VERSION 5.8 ;
BUSBITCHARS "[]" ;
DIVIDERCHAR "/" ;
UNITS
    DATABASE MICRONS 1000 ;
END UNITS

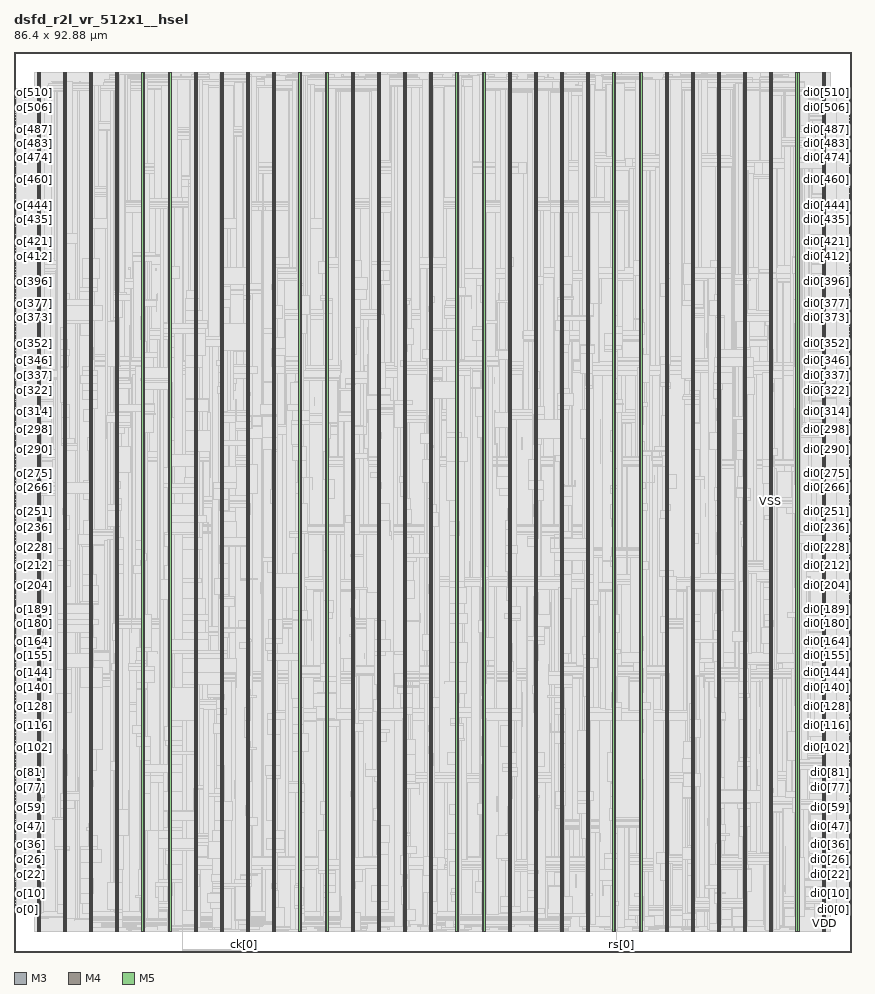
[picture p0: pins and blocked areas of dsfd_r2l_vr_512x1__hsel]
MACRO dsfd_r2l_vr_512x1__hsel
  FOREIGN dsfd_r2l_vr_512x1__hsel 0 0 ;
  CLASS BLOCK ;
  SIZE 86.4 BY 92.88 ;
  PIN ck[0]
    DIRECTION INPUT ;
    USE SIGNAL ;
    PORT
      LAYER M3 ;
        RECT  23.76 0 23.778 0.144 ;
    END
    PORT
      LAYER M3 ;
        RECT  23.76 0.108 23.778 0.221 ;
    END
  END ck[0]
  PIN di0[0]
    DIRECTION INPUT ;
    USE SIGNAL ;
    PORT
      LAYER M4 ;
        RECT  86.208 4.416 86.4 4.44 ;
    END
  END di0[0]
  PIN di0[100]
    DIRECTION INPUT ;
    USE SIGNAL ;
    PORT
      LAYER M4 ;
        RECT  86.208 20.784 86.4 20.808 ;
    END
  END di0[100]
  PIN di0[101]
    DIRECTION INPUT ;
    USE SIGNAL ;
    PORT
      LAYER M4 ;
        RECT  86.208 20.928 86.4 20.952 ;
    END
  END di0[101]
  PIN di0[102]
    DIRECTION INPUT ;
    USE SIGNAL ;
    PORT
      LAYER M4 ;
        RECT  86.208 21.12 86.4 21.144 ;
    END
  END di0[102]
  PIN di0[103]
    DIRECTION INPUT ;
    USE SIGNAL ;
    PORT
      LAYER M4 ;
        RECT  86.208 21.264 86.4 21.288 ;
    END
  END di0[103]
  PIN di0[104]
    DIRECTION INPUT ;
    USE SIGNAL ;
    PORT
      LAYER M4 ;
        RECT  86.208 21.408 86.4 21.432 ;
    END
  END di0[104]
  PIN di0[105]
    DIRECTION INPUT ;
    USE SIGNAL ;
    PORT
      LAYER M4 ;
        RECT  86.208 21.6 86.4 21.624 ;
    END
  END di0[105]
  PIN di0[106]
    DIRECTION INPUT ;
    USE SIGNAL ;
    PORT
      LAYER M4 ;
        RECT  86.208 21.744 86.4 21.768 ;
    END
  END di0[106]
  PIN di0[107]
    DIRECTION INPUT ;
    USE SIGNAL ;
    PORT
      LAYER M4 ;
        RECT  86.208 21.936 86.4 21.96 ;
    END
  END di0[107]
  PIN di0[108]
    DIRECTION INPUT ;
    USE SIGNAL ;
    PORT
      LAYER M4 ;
        RECT  86.208 22.08 86.4 22.104 ;
    END
  END di0[108]
  PIN di0[109]
    DIRECTION INPUT ;
    USE SIGNAL ;
    PORT
      LAYER M4 ;
        RECT  86.208 22.224 86.4 22.248 ;
    END
  END di0[109]
  PIN di0[10]
    DIRECTION INPUT ;
    USE SIGNAL ;
    PORT
      LAYER M4 ;
        RECT  86.208 6.048 86.4 6.072 ;
    END
  END di0[10]
  PIN di0[110]
    DIRECTION INPUT ;
    USE SIGNAL ;
    PORT
      LAYER M4 ;
        RECT  86.208 22.416 86.4 22.44 ;
    END
  END di0[110]
  PIN di0[111]
    DIRECTION INPUT ;
    USE SIGNAL ;
    PORT
      LAYER M4 ;
        RECT  86.208 22.56 86.4 22.584 ;
    END
  END di0[111]
  PIN di0[112]
    DIRECTION INPUT ;
    USE SIGNAL ;
    PORT
      LAYER M4 ;
        RECT  86.208 22.752 86.4 22.776 ;
    END
  END di0[112]
  PIN di0[113]
    DIRECTION INPUT ;
    USE SIGNAL ;
    PORT
      LAYER M4 ;
        RECT  86.208 22.896 86.4 22.92 ;
    END
  END di0[113]
  PIN di0[114]
    DIRECTION INPUT ;
    USE SIGNAL ;
    PORT
      LAYER M4 ;
        RECT  86.208 23.04 86.4 23.064 ;
    END
  END di0[114]
  PIN di0[115]
    DIRECTION INPUT ;
    USE SIGNAL ;
    PORT
      LAYER M4 ;
        RECT  86.208 23.232 86.4 23.256 ;
    END
  END di0[115]
  PIN di0[116]
    DIRECTION INPUT ;
    USE SIGNAL ;
    PORT
      LAYER M4 ;
        RECT  86.208 23.376 86.4 23.4 ;
    END
  END di0[116]
  PIN di0[117]
    DIRECTION INPUT ;
    USE SIGNAL ;
    PORT
      LAYER M4 ;
        RECT  86.208 23.568 86.4 23.592 ;
    END
  END di0[117]
  PIN di0[118]
    DIRECTION INPUT ;
    USE SIGNAL ;
    PORT
      LAYER M4 ;
        RECT  86.208 23.712 86.4 23.736 ;
    END
  END di0[118]
  PIN di0[119]
    DIRECTION INPUT ;
    USE SIGNAL ;
    PORT
      LAYER M4 ;
        RECT  86.208 23.856 86.4 23.88 ;
    END
  END di0[119]
  PIN di0[11]
    DIRECTION INPUT ;
    USE SIGNAL ;
    PORT
      LAYER M4 ;
        RECT  86.208 6.192 86.4 6.216 ;
    END
  END di0[11]
  PIN di0[120]
    DIRECTION INPUT ;
    USE SIGNAL ;
    PORT
      LAYER M4 ;
        RECT  86.208 24.048 86.4 24.072 ;
    END
  END di0[120]
  PIN di0[121]
    DIRECTION INPUT ;
    USE SIGNAL ;
    PORT
      LAYER M4 ;
        RECT  86.208 24.192 86.4 24.216 ;
    END
  END di0[121]
  PIN di0[122]
    DIRECTION INPUT ;
    USE SIGNAL ;
    PORT
      LAYER M4 ;
        RECT  86.208 24.384 86.4 24.408 ;
    END
  END di0[122]
  PIN di0[123]
    DIRECTION INPUT ;
    USE SIGNAL ;
    PORT
      LAYER M4 ;
        RECT  86.208 24.528 86.4 24.552 ;
    END
  END di0[123]
  PIN di0[124]
    DIRECTION INPUT ;
    USE SIGNAL ;
    PORT
      LAYER M4 ;
        RECT  86.208 24.72 86.4 24.744 ;
    END
  END di0[124]
  PIN di0[125]
    DIRECTION INPUT ;
    USE SIGNAL ;
    PORT
      LAYER M4 ;
        RECT  86.208 24.864 86.4 24.888 ;
    END
  END di0[125]
  PIN di0[126]
    DIRECTION INPUT ;
    USE SIGNAL ;
    PORT
      LAYER M4 ;
        RECT  86.208 25.008 86.4 25.032 ;
    END
  END di0[126]
  PIN di0[127]
    DIRECTION INPUT ;
    USE SIGNAL ;
    PORT
      LAYER M4 ;
        RECT  86.208 25.2 86.4 25.224 ;
    END
  END di0[127]
  PIN di0[128]
    DIRECTION INPUT ;
    USE SIGNAL ;
    PORT
      LAYER M4 ;
        RECT  86.208 25.344 86.4 25.368 ;
    END
  END di0[128]
  PIN di0[129]
    DIRECTION INPUT ;
    USE SIGNAL ;
    PORT
      LAYER M4 ;
        RECT  86.208 25.536 86.4 25.56 ;
    END
  END di0[129]
  PIN di0[12]
    DIRECTION INPUT ;
    USE SIGNAL ;
    PORT
      LAYER M4 ;
        RECT  86.208 6.384 86.4 6.408 ;
    END
  END di0[12]
  PIN di0[130]
    DIRECTION INPUT ;
    USE SIGNAL ;
    PORT
      LAYER M4 ;
        RECT  86.208 25.68 86.4 25.704 ;
    END
  END di0[130]
  PIN di0[131]
    DIRECTION INPUT ;
    USE SIGNAL ;
    PORT
      LAYER M4 ;
        RECT  86.208 25.824 86.4 25.848 ;
    END
  END di0[131]
  PIN di0[132]
    DIRECTION INPUT ;
    USE SIGNAL ;
    PORT
      LAYER M4 ;
        RECT  86.208 26.016 86.4 26.04 ;
    END
  END di0[132]
  PIN di0[133]
    DIRECTION INPUT ;
    USE SIGNAL ;
    PORT
      LAYER M4 ;
        RECT  86.208 26.16 86.4 26.184 ;
    END
  END di0[133]
  PIN di0[134]
    DIRECTION INPUT ;
    USE SIGNAL ;
    PORT
      LAYER M4 ;
        RECT  86.208 26.352 86.4 26.376 ;
    END
  END di0[134]
  PIN di0[135]
    DIRECTION INPUT ;
    USE SIGNAL ;
    PORT
      LAYER M4 ;
        RECT  86.208 26.496 86.4 26.52 ;
    END
  END di0[135]
  PIN di0[136]
    DIRECTION INPUT ;
    USE SIGNAL ;
    PORT
      LAYER M4 ;
        RECT  86.208 26.64 86.4 26.664 ;
    END
  END di0[136]
  PIN di0[137]
    DIRECTION INPUT ;
    USE SIGNAL ;
    PORT
      LAYER M4 ;
        RECT  86.208 26.832 86.4 26.856 ;
    END
  END di0[137]
  PIN di0[138]
    DIRECTION INPUT ;
    USE SIGNAL ;
    PORT
      LAYER M4 ;
        RECT  86.208 26.976 86.4 27 ;
    END
  END di0[138]
  PIN di0[139]
    DIRECTION INPUT ;
    USE SIGNAL ;
    PORT
      LAYER M4 ;
        RECT  86.208 27.168 86.4 27.192 ;
    END
  END di0[139]
  PIN di0[13]
    DIRECTION INPUT ;
    USE SIGNAL ;
    PORT
      LAYER M4 ;
        RECT  86.208 6.528 86.4 6.552 ;
    END
  END di0[13]
  PIN di0[140]
    DIRECTION INPUT ;
    USE SIGNAL ;
    PORT
      LAYER M4 ;
        RECT  86.208 27.312 86.4 27.336 ;
    END
  END di0[140]
  PIN di0[141]
    DIRECTION INPUT ;
    USE SIGNAL ;
    PORT
      LAYER M4 ;
        RECT  86.208 27.456 86.4 27.48 ;
    END
  END di0[141]
  PIN di0[142]
    DIRECTION INPUT ;
    USE SIGNAL ;
    PORT
      LAYER M4 ;
        RECT  86.208 27.648 86.4 27.672 ;
    END
  END di0[142]
  PIN di0[143]
    DIRECTION INPUT ;
    USE SIGNAL ;
    PORT
      LAYER M4 ;
        RECT  86.208 27.792 86.4 27.816 ;
    END
  END di0[143]
  PIN di0[144]
    DIRECTION INPUT ;
    USE SIGNAL ;
    PORT
      LAYER M4 ;
        RECT  86.208 27.984 86.4 28.008 ;
    END
  END di0[144]
  PIN di0[145]
    DIRECTION INPUT ;
    USE SIGNAL ;
    PORT
      LAYER M4 ;
        RECT  86.208 28.128 86.4 28.152 ;
    END
  END di0[145]
  PIN di0[146]
    DIRECTION INPUT ;
    USE SIGNAL ;
    PORT
      LAYER M4 ;
        RECT  86.208 28.272 86.4 28.296 ;
    END
  END di0[146]
  PIN di0[147]
    DIRECTION INPUT ;
    USE SIGNAL ;
    PORT
      LAYER M4 ;
        RECT  86.208 28.464 86.4 28.488 ;
    END
  END di0[147]
  PIN di0[148]
    DIRECTION INPUT ;
    USE SIGNAL ;
    PORT
      LAYER M4 ;
        RECT  86.208 28.608 86.4 28.632 ;
    END
  END di0[148]
  PIN di0[149]
    DIRECTION INPUT ;
    USE SIGNAL ;
    PORT
      LAYER M4 ;
        RECT  86.208 28.8 86.4 28.824 ;
    END
  END di0[149]
  PIN di0[14]
    DIRECTION INPUT ;
    USE SIGNAL ;
    PORT
      LAYER M4 ;
        RECT  86.208 6.72 86.4 6.744 ;
    END
  END di0[14]
  PIN di0[150]
    DIRECTION INPUT ;
    USE SIGNAL ;
    PORT
      LAYER M4 ;
        RECT  86.208 28.944 86.4 28.968 ;
    END
  END di0[150]
  PIN di0[151]
    DIRECTION INPUT ;
    USE SIGNAL ;
    PORT
      LAYER M4 ;
        RECT  86.208 29.136 86.4 29.16 ;
    END
  END di0[151]
  PIN di0[152]
    DIRECTION INPUT ;
    USE SIGNAL ;
    PORT
      LAYER M4 ;
        RECT  86.208 29.28 86.4 29.304 ;
    END
  END di0[152]
  PIN di0[153]
    DIRECTION INPUT ;
    USE SIGNAL ;
    PORT
      LAYER M4 ;
        RECT  86.208 29.424 86.4 29.448 ;
    END
  END di0[153]
  PIN di0[154]
    DIRECTION INPUT ;
    USE SIGNAL ;
    PORT
      LAYER M4 ;
        RECT  86.208 29.616 86.4 29.64 ;
    END
  END di0[154]
  PIN di0[155]
    DIRECTION INPUT ;
    USE SIGNAL ;
    PORT
      LAYER M4 ;
        RECT  86.208 29.76 86.4 29.784 ;
    END
  END di0[155]
  PIN di0[156]
    DIRECTION INPUT ;
    USE SIGNAL ;
    PORT
      LAYER M4 ;
        RECT  86.208 29.952 86.4 29.976 ;
    END
  END di0[156]
  PIN di0[157]
    DIRECTION INPUT ;
    USE SIGNAL ;
    PORT
      LAYER M4 ;
        RECT  86.208 30.096 86.4 30.12 ;
    END
  END di0[157]
  PIN di0[158]
    DIRECTION INPUT ;
    USE SIGNAL ;
    PORT
      LAYER M4 ;
        RECT  86.208 30.24 86.4 30.264 ;
    END
  END di0[158]
  PIN di0[159]
    DIRECTION INPUT ;
    USE SIGNAL ;
    PORT
      LAYER M4 ;
        RECT  86.208 30.432 86.4 30.456 ;
    END
  END di0[159]
  PIN di0[15]
    DIRECTION INPUT ;
    USE SIGNAL ;
    PORT
      LAYER M4 ;
        RECT  86.208 6.864 86.4 6.888 ;
    END
  END di0[15]
  PIN di0[160]
    DIRECTION INPUT ;
    USE SIGNAL ;
    PORT
      LAYER M4 ;
        RECT  86.208 30.576 86.4 30.6 ;
    END
  END di0[160]
  PIN di0[161]
    DIRECTION INPUT ;
    USE SIGNAL ;
    PORT
      LAYER M4 ;
        RECT  86.208 30.768 86.4 30.792 ;
    END
  END di0[161]
  PIN di0[162]
    DIRECTION INPUT ;
    USE SIGNAL ;
    PORT
      LAYER M4 ;
        RECT  86.208 30.912 86.4 30.936 ;
    END
  END di0[162]
  PIN di0[163]
    DIRECTION INPUT ;
    USE SIGNAL ;
    PORT
      LAYER M4 ;
        RECT  86.208 31.056 86.4 31.08 ;
    END
  END di0[163]
  PIN di0[164]
    DIRECTION INPUT ;
    USE SIGNAL ;
    PORT
      LAYER M4 ;
        RECT  86.208 31.248 86.4 31.272 ;
    END
  END di0[164]
  PIN di0[165]
    DIRECTION INPUT ;
    USE SIGNAL ;
    PORT
      LAYER M4 ;
        RECT  86.208 31.392 86.4 31.416 ;
    END
  END di0[165]
  PIN di0[166]
    DIRECTION INPUT ;
    USE SIGNAL ;
    PORT
      LAYER M4 ;
        RECT  86.208 31.584 86.4 31.608 ;
    END
  END di0[166]
  PIN di0[167]
    DIRECTION INPUT ;
    USE SIGNAL ;
    PORT
      LAYER M4 ;
        RECT  86.208 31.728 86.4 31.752 ;
    END
  END di0[167]
  PIN di0[168]
    DIRECTION INPUT ;
    USE SIGNAL ;
    PORT
      LAYER M4 ;
        RECT  86.208 31.872 86.4 31.896 ;
    END
  END di0[168]
  PIN di0[169]
    DIRECTION INPUT ;
    USE SIGNAL ;
    PORT
      LAYER M4 ;
        RECT  86.208 32.064 86.4 32.088 ;
    END
  END di0[169]
  PIN di0[16]
    DIRECTION INPUT ;
    USE SIGNAL ;
    PORT
      LAYER M4 ;
        RECT  86.208 7.008 86.4 7.032 ;
    END
  END di0[16]
  PIN di0[170]
    DIRECTION INPUT ;
    USE SIGNAL ;
    PORT
      LAYER M4 ;
        RECT  86.208 32.208 86.4 32.232 ;
    END
  END di0[170]
  PIN di0[171]
    DIRECTION INPUT ;
    USE SIGNAL ;
    PORT
      LAYER M4 ;
        RECT  86.208 32.4 86.4 32.424 ;
    END
  END di0[171]
  PIN di0[172]
    DIRECTION INPUT ;
    USE SIGNAL ;
    PORT
      LAYER M4 ;
        RECT  86.208 32.544 86.4 32.568 ;
    END
  END di0[172]
  PIN di0[173]
    DIRECTION INPUT ;
    USE SIGNAL ;
    PORT
      LAYER M4 ;
        RECT  86.208 32.688 86.4 32.712 ;
    END
  END di0[173]
  PIN di0[174]
    DIRECTION INPUT ;
    USE SIGNAL ;
    PORT
      LAYER M4 ;
        RECT  86.208 32.88 86.4 32.904 ;
    END
  END di0[174]
  PIN di0[175]
    DIRECTION INPUT ;
    USE SIGNAL ;
    PORT
      LAYER M4 ;
        RECT  86.208 33.024 86.4 33.048 ;
    END
  END di0[175]
  PIN di0[176]
    DIRECTION INPUT ;
    USE SIGNAL ;
    PORT
      LAYER M4 ;
        RECT  86.208 33.216 86.4 33.24 ;
    END
  END di0[176]
  PIN di0[177]
    DIRECTION INPUT ;
    USE SIGNAL ;
    PORT
      LAYER M4 ;
        RECT  86.208 33.36 86.4 33.384 ;
    END
  END di0[177]
  PIN di0[178]
    DIRECTION INPUT ;
    USE SIGNAL ;
    PORT
      LAYER M4 ;
        RECT  86.208 33.552 86.4 33.576 ;
    END
  END di0[178]
  PIN di0[179]
    DIRECTION INPUT ;
    USE SIGNAL ;
    PORT
      LAYER M4 ;
        RECT  86.208 33.696 86.4 33.72 ;
    END
  END di0[179]
  PIN di0[17]
    DIRECTION INPUT ;
    USE SIGNAL ;
    PORT
      LAYER M4 ;
        RECT  86.208 7.2 86.4 7.224 ;
    END
  END di0[17]
  PIN di0[180]
    DIRECTION INPUT ;
    USE SIGNAL ;
    PORT
      LAYER M4 ;
        RECT  86.208 33.84 86.4 33.864 ;
    END
  END di0[180]
  PIN di0[181]
    DIRECTION INPUT ;
    USE SIGNAL ;
    PORT
      LAYER M4 ;
        RECT  86.208 34.032 86.4 34.056 ;
    END
  END di0[181]
  PIN di0[182]
    DIRECTION INPUT ;
    USE SIGNAL ;
    PORT
      LAYER M4 ;
        RECT  86.208 34.176 86.4 34.2 ;
    END
  END di0[182]
  PIN di0[183]
    DIRECTION INPUT ;
    USE SIGNAL ;
    PORT
      LAYER M4 ;
        RECT  86.208 34.368 86.4 34.392 ;
    END
  END di0[183]
  PIN di0[184]
    DIRECTION INPUT ;
    USE SIGNAL ;
    PORT
      LAYER M4 ;
        RECT  86.208 34.512 86.4 34.536 ;
    END
  END di0[184]
  PIN di0[185]
    DIRECTION INPUT ;
    USE SIGNAL ;
    PORT
      LAYER M4 ;
        RECT  86.208 34.656 86.4 34.68 ;
    END
  END di0[185]
  PIN di0[186]
    DIRECTION INPUT ;
    USE SIGNAL ;
    PORT
      LAYER M4 ;
        RECT  86.208 34.848 86.4 34.872 ;
    END
  END di0[186]
  PIN di0[187]
    DIRECTION INPUT ;
    USE SIGNAL ;
    PORT
      LAYER M4 ;
        RECT  86.208 34.992 86.4 35.016 ;
    END
  END di0[187]
  PIN di0[188]
    DIRECTION INPUT ;
    USE SIGNAL ;
    PORT
      LAYER M4 ;
        RECT  86.208 35.184 86.4 35.208 ;
    END
  END di0[188]
  PIN di0[189]
    DIRECTION INPUT ;
    USE SIGNAL ;
    PORT
      LAYER M4 ;
        RECT  86.208 35.328 86.4 35.352 ;
    END
  END di0[189]
  PIN di0[18]
    DIRECTION INPUT ;
    USE SIGNAL ;
    PORT
      LAYER M4 ;
        RECT  86.208 7.344 86.4 7.368 ;
    END
  END di0[18]
  PIN di0[190]
    DIRECTION INPUT ;
    USE SIGNAL ;
    PORT
      LAYER M4 ;
        RECT  86.208 35.472 86.4 35.496 ;
    END
  END di0[190]
  PIN di0[191]
    DIRECTION INPUT ;
    USE SIGNAL ;
    PORT
      LAYER M4 ;
        RECT  86.208 35.664 86.4 35.688 ;
    END
  END di0[191]
  PIN di0[192]
    DIRECTION INPUT ;
    USE SIGNAL ;
    PORT
      LAYER M4 ;
        RECT  86.208 35.808 86.4 35.832 ;
    END
  END di0[192]
  PIN di0[193]
    DIRECTION INPUT ;
    USE SIGNAL ;
    PORT
      LAYER M4 ;
        RECT  86.208 36 86.4 36.024 ;
    END
  END di0[193]
  PIN di0[194]
    DIRECTION INPUT ;
    USE SIGNAL ;
    PORT
      LAYER M4 ;
        RECT  86.208 36.144 86.4 36.168 ;
    END
  END di0[194]
  PIN di0[195]
    DIRECTION INPUT ;
    USE SIGNAL ;
    PORT
      LAYER M4 ;
        RECT  86.208 36.288 86.4 36.312 ;
    END
  END di0[195]
  PIN di0[196]
    DIRECTION INPUT ;
    USE SIGNAL ;
    PORT
      LAYER M4 ;
        RECT  86.208 36.48 86.4 36.504 ;
    END
  END di0[196]
  PIN di0[197]
    DIRECTION INPUT ;
    USE SIGNAL ;
    PORT
      LAYER M4 ;
        RECT  86.208 36.624 86.4 36.648 ;
    END
  END di0[197]
  PIN di0[198]
    DIRECTION INPUT ;
    USE SIGNAL ;
    PORT
      LAYER M4 ;
        RECT  86.208 36.816 86.4 36.84 ;
    END
  END di0[198]
  PIN di0[199]
    DIRECTION INPUT ;
    USE SIGNAL ;
    PORT
      LAYER M4 ;
        RECT  86.208 36.96 86.4 36.984 ;
    END
  END di0[199]
  PIN di0[19]
    DIRECTION INPUT ;
    USE SIGNAL ;
    PORT
      LAYER M4 ;
        RECT  86.208 7.536 86.4 7.56 ;
    END
  END di0[19]
  PIN di0[1]
    DIRECTION INPUT ;
    USE SIGNAL ;
    PORT
      LAYER M4 ;
        RECT  86.208 4.56 86.4 4.584 ;
    END
  END di0[1]
  PIN di0[200]
    DIRECTION INPUT ;
    USE SIGNAL ;
    PORT
      LAYER M4 ;
        RECT  86.208 37.152 86.4 37.176 ;
    END
  END di0[200]
  PIN di0[201]
    DIRECTION INPUT ;
    USE SIGNAL ;
    PORT
      LAYER M4 ;
        RECT  86.208 37.296 86.4 37.32 ;
    END
  END di0[201]
  PIN di0[202]
    DIRECTION INPUT ;
    USE SIGNAL ;
    PORT
      LAYER M4 ;
        RECT  86.208 37.44 86.4 37.464 ;
    END
  END di0[202]
  PIN di0[203]
    DIRECTION INPUT ;
    USE SIGNAL ;
    PORT
      LAYER M4 ;
        RECT  86.208 37.632 86.4 37.656 ;
    END
  END di0[203]
  PIN di0[204]
    DIRECTION INPUT ;
    USE SIGNAL ;
    PORT
      LAYER M4 ;
        RECT  86.208 37.776 86.4 37.8 ;
    END
  END di0[204]
  PIN di0[205]
    DIRECTION INPUT ;
    USE SIGNAL ;
    PORT
      LAYER M4 ;
        RECT  86.208 37.968 86.4 37.992 ;
    END
  END di0[205]
  PIN di0[206]
    DIRECTION INPUT ;
    USE SIGNAL ;
    PORT
      LAYER M4 ;
        RECT  86.208 38.112 86.4 38.136 ;
    END
  END di0[206]
  PIN di0[207]
    DIRECTION INPUT ;
    USE SIGNAL ;
    PORT
      LAYER M4 ;
        RECT  86.208 38.256 86.4 38.28 ;
    END
  END di0[207]
  PIN di0[208]
    DIRECTION INPUT ;
    USE SIGNAL ;
    PORT
      LAYER M4 ;
        RECT  86.208 38.448 86.4 38.472 ;
    END
  END di0[208]
  PIN di0[209]
    DIRECTION INPUT ;
    USE SIGNAL ;
    PORT
      LAYER M4 ;
        RECT  86.208 38.592 86.4 38.616 ;
    END
  END di0[209]
  PIN di0[20]
    DIRECTION INPUT ;
    USE SIGNAL ;
    PORT
      LAYER M4 ;
        RECT  86.208 7.68 86.4 7.704 ;
    END
  END di0[20]
  PIN di0[210]
    DIRECTION INPUT ;
    USE SIGNAL ;
    PORT
      LAYER M4 ;
        RECT  86.208 38.784 86.4 38.808 ;
    END
  END di0[210]
  PIN di0[211]
    DIRECTION INPUT ;
    USE SIGNAL ;
    PORT
      LAYER M4 ;
        RECT  86.208 38.928 86.4 38.952 ;
    END
  END di0[211]
  PIN di0[212]
    DIRECTION INPUT ;
    USE SIGNAL ;
    PORT
      LAYER M4 ;
        RECT  86.208 39.072 86.4 39.096 ;
    END
  END di0[212]
  PIN di0[213]
    DIRECTION INPUT ;
    USE SIGNAL ;
    PORT
      LAYER M4 ;
        RECT  86.208 39.264 86.4 39.288 ;
    END
  END di0[213]
  PIN di0[214]
    DIRECTION INPUT ;
    USE SIGNAL ;
    PORT
      LAYER M4 ;
        RECT  86.208 39.408 86.4 39.432 ;
    END
  END di0[214]
  PIN di0[215]
    DIRECTION INPUT ;
    USE SIGNAL ;
    PORT
      LAYER M4 ;
        RECT  86.208 39.6 86.4 39.624 ;
    END
  END di0[215]
  PIN di0[216]
    DIRECTION INPUT ;
    USE SIGNAL ;
    PORT
      LAYER M4 ;
        RECT  86.208 39.744 86.4 39.768 ;
    END
  END di0[216]
  PIN di0[217]
    DIRECTION INPUT ;
    USE SIGNAL ;
    PORT
      LAYER M4 ;
        RECT  86.208 39.888 86.4 39.912 ;
    END
  END di0[217]
  PIN di0[218]
    DIRECTION INPUT ;
    USE SIGNAL ;
    PORT
      LAYER M4 ;
        RECT  86.208 40.08 86.4 40.104 ;
    END
  END di0[218]
  PIN di0[219]
    DIRECTION INPUT ;
    USE SIGNAL ;
    PORT
      LAYER M4 ;
        RECT  86.208 40.224 86.4 40.248 ;
    END
  END di0[219]
  PIN di0[21]
    DIRECTION INPUT ;
    USE SIGNAL ;
    PORT
      LAYER M4 ;
        RECT  86.208 7.872 86.4 7.896 ;
    END
  END di0[21]
  PIN di0[220]
    DIRECTION INPUT ;
    USE SIGNAL ;
    PORT
      LAYER M4 ;
        RECT  86.208 40.416 86.4 40.44 ;
    END
  END di0[220]
  PIN di0[221]
    DIRECTION INPUT ;
    USE SIGNAL ;
    PORT
      LAYER M4 ;
        RECT  86.208 40.56 86.4 40.584 ;
    END
  END di0[221]
  PIN di0[222]
    DIRECTION INPUT ;
    USE SIGNAL ;
    PORT
      LAYER M4 ;
        RECT  86.208 40.704 86.4 40.728 ;
    END
  END di0[222]
  PIN di0[223]
    DIRECTION INPUT ;
    USE SIGNAL ;
    PORT
      LAYER M4 ;
        RECT  86.208 40.896 86.4 40.92 ;
    END
  END di0[223]
  PIN di0[224]
    DIRECTION INPUT ;
    USE SIGNAL ;
    PORT
      LAYER M4 ;
        RECT  86.208 41.04 86.4 41.064 ;
    END
  END di0[224]
  PIN di0[225]
    DIRECTION INPUT ;
    USE SIGNAL ;
    PORT
      LAYER M4 ;
        RECT  86.208 41.232 86.4 41.256 ;
    END
  END di0[225]
  PIN di0[226]
    DIRECTION INPUT ;
    USE SIGNAL ;
    PORT
      LAYER M4 ;
        RECT  86.208 41.376 86.4 41.4 ;
    END
  END di0[226]
  PIN di0[227]
    DIRECTION INPUT ;
    USE SIGNAL ;
    PORT
      LAYER M4 ;
        RECT  86.208 41.568 86.4 41.592 ;
    END
  END di0[227]
  PIN di0[228]
    DIRECTION INPUT ;
    USE SIGNAL ;
    PORT
      LAYER M4 ;
        RECT  86.208 41.712 86.4 41.736 ;
    END
  END di0[228]
  PIN di0[229]
    DIRECTION INPUT ;
    USE SIGNAL ;
    PORT
      LAYER M4 ;
        RECT  86.208 41.856 86.4 41.88 ;
    END
  END di0[229]
  PIN di0[22]
    DIRECTION INPUT ;
    USE SIGNAL ;
    PORT
      LAYER M4 ;
        RECT  86.208 8.016 86.4 8.04 ;
    END
  END di0[22]
  PIN di0[230]
    DIRECTION INPUT ;
    USE SIGNAL ;
    PORT
      LAYER M4 ;
        RECT  86.208 42.048 86.4 42.072 ;
    END
  END di0[230]
  PIN di0[231]
    DIRECTION INPUT ;
    USE SIGNAL ;
    PORT
      LAYER M4 ;
        RECT  86.208 42.192 86.4 42.216 ;
    END
  END di0[231]
  PIN di0[232]
    DIRECTION INPUT ;
    USE SIGNAL ;
    PORT
      LAYER M4 ;
        RECT  86.208 42.384 86.4 42.408 ;
    END
  END di0[232]
  PIN di0[233]
    DIRECTION INPUT ;
    USE SIGNAL ;
    PORT
      LAYER M4 ;
        RECT  86.208 42.528 86.4 42.552 ;
    END
  END di0[233]
  PIN di0[234]
    DIRECTION INPUT ;
    USE SIGNAL ;
    PORT
      LAYER M4 ;
        RECT  86.208 42.672 86.4 42.696 ;
    END
  END di0[234]
  PIN di0[235]
    DIRECTION INPUT ;
    USE SIGNAL ;
    PORT
      LAYER M4 ;
        RECT  86.208 42.864 86.4 42.888 ;
    END
  END di0[235]
  PIN di0[236]
    DIRECTION INPUT ;
    USE SIGNAL ;
    PORT
      LAYER M4 ;
        RECT  86.208 43.008 86.4 43.032 ;
    END
  END di0[236]
  PIN di0[237]
    DIRECTION INPUT ;
    USE SIGNAL ;
    PORT
      LAYER M4 ;
        RECT  86.208 43.2 86.4 43.224 ;
    END
  END di0[237]
  PIN di0[238]
    DIRECTION INPUT ;
    USE SIGNAL ;
    PORT
      LAYER M4 ;
        RECT  86.208 43.344 86.4 43.368 ;
    END
  END di0[238]
  PIN di0[239]
    DIRECTION INPUT ;
    USE SIGNAL ;
    PORT
      LAYER M4 ;
        RECT  86.208 43.488 86.4 43.512 ;
    END
  END di0[239]
  PIN di0[23]
    DIRECTION INPUT ;
    USE SIGNAL ;
    PORT
      LAYER M4 ;
        RECT  86.208 8.16 86.4 8.184 ;
    END
  END di0[23]
  PIN di0[240]
    DIRECTION INPUT ;
    USE SIGNAL ;
    PORT
      LAYER M4 ;
        RECT  86.208 43.68 86.4 43.704 ;
    END
  END di0[240]
  PIN di0[241]
    DIRECTION INPUT ;
    USE SIGNAL ;
    PORT
      LAYER M4 ;
        RECT  86.208 43.824 86.4 43.848 ;
    END
  END di0[241]
  PIN di0[242]
    DIRECTION INPUT ;
    USE SIGNAL ;
    PORT
      LAYER M4 ;
        RECT  86.208 44.016 86.4 44.04 ;
    END
  END di0[242]
  PIN di0[243]
    DIRECTION INPUT ;
    USE SIGNAL ;
    PORT
      LAYER M4 ;
        RECT  86.208 44.16 86.4 44.184 ;
    END
  END di0[243]
  PIN di0[244]
    DIRECTION INPUT ;
    USE SIGNAL ;
    PORT
      LAYER M4 ;
        RECT  86.208 44.304 86.4 44.328 ;
    END
  END di0[244]
  PIN di0[245]
    DIRECTION INPUT ;
    USE SIGNAL ;
    PORT
      LAYER M4 ;
        RECT  86.208 44.496 86.4 44.52 ;
    END
  END di0[245]
  PIN di0[246]
    DIRECTION INPUT ;
    USE SIGNAL ;
    PORT
      LAYER M4 ;
        RECT  86.208 44.64 86.4 44.664 ;
    END
  END di0[246]
  PIN di0[247]
    DIRECTION INPUT ;
    USE SIGNAL ;
    PORT
      LAYER M4 ;
        RECT  86.208 44.832 86.4 44.856 ;
    END
  END di0[247]
  PIN di0[248]
    DIRECTION INPUT ;
    USE SIGNAL ;
    PORT
      LAYER M4 ;
        RECT  86.208 44.976 86.4 45 ;
    END
  END di0[248]
  PIN di0[249]
    DIRECTION INPUT ;
    USE SIGNAL ;
    PORT
      LAYER M4 ;
        RECT  86.208 45.12 86.4 45.144 ;
    END
  END di0[249]
  PIN di0[24]
    DIRECTION INPUT ;
    USE SIGNAL ;
    PORT
      LAYER M4 ;
        RECT  86.208 8.352 86.4 8.376 ;
    END
  END di0[24]
  PIN di0[250]
    DIRECTION INPUT ;
    USE SIGNAL ;
    PORT
      LAYER M4 ;
        RECT  86.208 45.312 86.4 45.336 ;
    END
  END di0[250]
  PIN di0[251]
    DIRECTION INPUT ;
    USE SIGNAL ;
    PORT
      LAYER M4 ;
        RECT  86.208 45.456 86.4 45.48 ;
    END
  END di0[251]
  PIN di0[252]
    DIRECTION INPUT ;
    USE SIGNAL ;
    PORT
      LAYER M4 ;
        RECT  86.208 45.648 86.4 45.672 ;
    END
  END di0[252]
  PIN di0[253]
    DIRECTION INPUT ;
    USE SIGNAL ;
    PORT
      LAYER M4 ;
        RECT  86.208 45.792 86.4 45.816 ;
    END
  END di0[253]
  PIN di0[254]
    DIRECTION INPUT ;
    USE SIGNAL ;
    PORT
      LAYER M4 ;
        RECT  86.208 45.984 86.4 46.008 ;
    END
  END di0[254]
  PIN di0[255]
    DIRECTION INPUT ;
    USE SIGNAL ;
    PORT
      LAYER M4 ;
        RECT  86.208 46.128 86.4 46.152 ;
    END
  END di0[255]
  PIN di0[256]
    DIRECTION INPUT ;
    USE SIGNAL ;
    PORT
      LAYER M4 ;
        RECT  86.208 46.272 86.4 46.296 ;
    END
  END di0[256]
  PIN di0[257]
    DIRECTION INPUT ;
    USE SIGNAL ;
    PORT
      LAYER M4 ;
        RECT  86.208 46.464 86.4 46.488 ;
    END
  END di0[257]
  PIN di0[258]
    DIRECTION INPUT ;
    USE SIGNAL ;
    PORT
      LAYER M4 ;
        RECT  86.208 46.608 86.4 46.632 ;
    END
  END di0[258]
  PIN di0[259]
    DIRECTION INPUT ;
    USE SIGNAL ;
    PORT
      LAYER M4 ;
        RECT  86.208 46.8 86.4 46.824 ;
    END
  END di0[259]
  PIN di0[25]
    DIRECTION INPUT ;
    USE SIGNAL ;
    PORT
      LAYER M4 ;
        RECT  86.208 8.496 86.4 8.52 ;
    END
  END di0[25]
  PIN di0[260]
    DIRECTION INPUT ;
    USE SIGNAL ;
    PORT
      LAYER M4 ;
        RECT  86.208 46.944 86.4 46.968 ;
    END
  END di0[260]
  PIN di0[261]
    DIRECTION INPUT ;
    USE SIGNAL ;
    PORT
      LAYER M4 ;
        RECT  86.208 47.088 86.4 47.112 ;
    END
  END di0[261]
  PIN di0[262]
    DIRECTION INPUT ;
    USE SIGNAL ;
    PORT
      LAYER M4 ;
        RECT  86.208 47.28 86.4 47.304 ;
    END
  END di0[262]
  PIN di0[263]
    DIRECTION INPUT ;
    USE SIGNAL ;
    PORT
      LAYER M4 ;
        RECT  86.208 47.424 86.4 47.448 ;
    END
  END di0[263]
  PIN di0[264]
    DIRECTION INPUT ;
    USE SIGNAL ;
    PORT
      LAYER M4 ;
        RECT  86.208 47.616 86.4 47.64 ;
    END
  END di0[264]
  PIN di0[265]
    DIRECTION INPUT ;
    USE SIGNAL ;
    PORT
      LAYER M4 ;
        RECT  86.208 47.76 86.4 47.784 ;
    END
  END di0[265]
  PIN di0[266]
    DIRECTION INPUT ;
    USE SIGNAL ;
    PORT
      LAYER M4 ;
        RECT  86.208 47.904 86.4 47.928 ;
    END
  END di0[266]
  PIN di0[267]
    DIRECTION INPUT ;
    USE SIGNAL ;
    PORT
      LAYER M4 ;
        RECT  86.208 48.096 86.4 48.12 ;
    END
  END di0[267]
  PIN di0[268]
    DIRECTION INPUT ;
    USE SIGNAL ;
    PORT
      LAYER M4 ;
        RECT  86.208 48.24 86.4 48.264 ;
    END
  END di0[268]
  PIN di0[269]
    DIRECTION INPUT ;
    USE SIGNAL ;
    PORT
      LAYER M4 ;
        RECT  86.208 48.432 86.4 48.456 ;
    END
  END di0[269]
  PIN di0[26]
    DIRECTION INPUT ;
    USE SIGNAL ;
    PORT
      LAYER M4 ;
        RECT  86.208 8.688 86.4 8.712 ;
    END
  END di0[26]
  PIN di0[270]
    DIRECTION INPUT ;
    USE SIGNAL ;
    PORT
      LAYER M4 ;
        RECT  86.208 48.576 86.4 48.6 ;
    END
  END di0[270]
  PIN di0[271]
    DIRECTION INPUT ;
    USE SIGNAL ;
    PORT
      LAYER M4 ;
        RECT  86.208 48.72 86.4 48.744 ;
    END
  END di0[271]
  PIN di0[272]
    DIRECTION INPUT ;
    USE SIGNAL ;
    PORT
      LAYER M4 ;
        RECT  86.208 48.912 86.4 48.936 ;
    END
  END di0[272]
  PIN di0[273]
    DIRECTION INPUT ;
    USE SIGNAL ;
    PORT
      LAYER M4 ;
        RECT  86.208 49.056 86.4 49.08 ;
    END
  END di0[273]
  PIN di0[274]
    DIRECTION INPUT ;
    USE SIGNAL ;
    PORT
      LAYER M4 ;
        RECT  86.208 49.248 86.4 49.272 ;
    END
  END di0[274]
  PIN di0[275]
    DIRECTION INPUT ;
    USE SIGNAL ;
    PORT
      LAYER M4 ;
        RECT  86.208 49.392 86.4 49.416 ;
    END
  END di0[275]
  PIN di0[276]
    DIRECTION INPUT ;
    USE SIGNAL ;
    PORT
      LAYER M4 ;
        RECT  86.208 49.536 86.4 49.56 ;
    END
  END di0[276]
  PIN di0[277]
    DIRECTION INPUT ;
    USE SIGNAL ;
    PORT
      LAYER M4 ;
        RECT  86.208 49.728 86.4 49.752 ;
    END
  END di0[277]
  PIN di0[278]
    DIRECTION INPUT ;
    USE SIGNAL ;
    PORT
      LAYER M4 ;
        RECT  86.208 49.872 86.4 49.896 ;
    END
  END di0[278]
  PIN di0[279]
    DIRECTION INPUT ;
    USE SIGNAL ;
    PORT
      LAYER M4 ;
        RECT  86.208 50.064 86.4 50.088 ;
    END
  END di0[279]
  PIN di0[27]
    DIRECTION INPUT ;
    USE SIGNAL ;
    PORT
      LAYER M4 ;
        RECT  86.208 8.832 86.4 8.856 ;
    END
  END di0[27]
  PIN di0[280]
    DIRECTION INPUT ;
    USE SIGNAL ;
    PORT
      LAYER M4 ;
        RECT  86.208 50.208 86.4 50.232 ;
    END
  END di0[280]
  PIN di0[281]
    DIRECTION INPUT ;
    USE SIGNAL ;
    PORT
      LAYER M4 ;
        RECT  86.208 50.4 86.4 50.424 ;
    END
  END di0[281]
  PIN di0[282]
    DIRECTION INPUT ;
    USE SIGNAL ;
    PORT
      LAYER M4 ;
        RECT  86.208 50.544 86.4 50.568 ;
    END
  END di0[282]
  PIN di0[283]
    DIRECTION INPUT ;
    USE SIGNAL ;
    PORT
      LAYER M4 ;
        RECT  86.208 50.688 86.4 50.712 ;
    END
  END di0[283]
  PIN di0[284]
    DIRECTION INPUT ;
    USE SIGNAL ;
    PORT
      LAYER M4 ;
        RECT  86.208 50.88 86.4 50.904 ;
    END
  END di0[284]
  PIN di0[285]
    DIRECTION INPUT ;
    USE SIGNAL ;
    PORT
      LAYER M4 ;
        RECT  86.208 51.024 86.4 51.048 ;
    END
  END di0[285]
  PIN di0[286]
    DIRECTION INPUT ;
    USE SIGNAL ;
    PORT
      LAYER M4 ;
        RECT  86.208 51.216 86.4 51.24 ;
    END
  END di0[286]
  PIN di0[287]
    DIRECTION INPUT ;
    USE SIGNAL ;
    PORT
      LAYER M4 ;
        RECT  86.208 51.36 86.4 51.384 ;
    END
  END di0[287]
  PIN di0[288]
    DIRECTION INPUT ;
    USE SIGNAL ;
    PORT
      LAYER M4 ;
        RECT  86.208 51.504 86.4 51.528 ;
    END
  END di0[288]
  PIN di0[289]
    DIRECTION INPUT ;
    USE SIGNAL ;
    PORT
      LAYER M4 ;
        RECT  86.208 51.696 86.4 51.72 ;
    END
  END di0[289]
  PIN di0[28]
    DIRECTION INPUT ;
    USE SIGNAL ;
    PORT
      LAYER M4 ;
        RECT  86.208 8.976 86.4 9 ;
    END
  END di0[28]
  PIN di0[290]
    DIRECTION INPUT ;
    USE SIGNAL ;
    PORT
      LAYER M4 ;
        RECT  86.208 51.84 86.4 51.864 ;
    END
  END di0[290]
  PIN di0[291]
    DIRECTION INPUT ;
    USE SIGNAL ;
    PORT
      LAYER M4 ;
        RECT  86.208 52.032 86.4 52.056 ;
    END
  END di0[291]
  PIN di0[292]
    DIRECTION INPUT ;
    USE SIGNAL ;
    PORT
      LAYER M4 ;
        RECT  86.208 52.176 86.4 52.2 ;
    END
  END di0[292]
  PIN di0[293]
    DIRECTION INPUT ;
    USE SIGNAL ;
    PORT
      LAYER M4 ;
        RECT  86.208 52.32 86.4 52.344 ;
    END
  END di0[293]
  PIN di0[294]
    DIRECTION INPUT ;
    USE SIGNAL ;
    PORT
      LAYER M4 ;
        RECT  86.208 52.512 86.4 52.536 ;
    END
  END di0[294]
  PIN di0[295]
    DIRECTION INPUT ;
    USE SIGNAL ;
    PORT
      LAYER M4 ;
        RECT  86.208 52.656 86.4 52.68 ;
    END
  END di0[295]
  PIN di0[296]
    DIRECTION INPUT ;
    USE SIGNAL ;
    PORT
      LAYER M4 ;
        RECT  86.208 52.848 86.4 52.872 ;
    END
  END di0[296]
  PIN di0[297]
    DIRECTION INPUT ;
    USE SIGNAL ;
    PORT
      LAYER M4 ;
        RECT  86.208 52.992 86.4 53.016 ;
    END
  END di0[297]
  PIN di0[298]
    DIRECTION INPUT ;
    USE SIGNAL ;
    PORT
      LAYER M4 ;
        RECT  86.208 53.136 86.4 53.16 ;
    END
  END di0[298]
  PIN di0[299]
    DIRECTION INPUT ;
    USE SIGNAL ;
    PORT
      LAYER M4 ;
        RECT  86.208 53.328 86.4 53.352 ;
    END
  END di0[299]
  PIN di0[29]
    DIRECTION INPUT ;
    USE SIGNAL ;
    PORT
      LAYER M4 ;
        RECT  86.208 9.168 86.4 9.192 ;
    END
  END di0[29]
  PIN di0[2]
    DIRECTION INPUT ;
    USE SIGNAL ;
    PORT
      LAYER M4 ;
        RECT  86.208 4.752 86.4 4.776 ;
    END
  END di0[2]
  PIN di0[300]
    DIRECTION INPUT ;
    USE SIGNAL ;
    PORT
      LAYER M4 ;
        RECT  86.208 53.472 86.4 53.496 ;
    END
  END di0[300]
  PIN di0[301]
    DIRECTION INPUT ;
    USE SIGNAL ;
    PORT
      LAYER M4 ;
        RECT  86.208 53.664 86.4 53.688 ;
    END
  END di0[301]
  PIN di0[302]
    DIRECTION INPUT ;
    USE SIGNAL ;
    PORT
      LAYER M4 ;
        RECT  86.208 53.808 86.4 53.832 ;
    END
  END di0[302]
  PIN di0[303]
    DIRECTION INPUT ;
    USE SIGNAL ;
    PORT
      LAYER M4 ;
        RECT  86.208 54 86.4 54.024 ;
    END
  END di0[303]
  PIN di0[304]
    DIRECTION INPUT ;
    USE SIGNAL ;
    PORT
      LAYER M4 ;
        RECT  86.208 54.144 86.4 54.168 ;
    END
  END di0[304]
  PIN di0[305]
    DIRECTION INPUT ;
    USE SIGNAL ;
    PORT
      LAYER M4 ;
        RECT  86.208 54.288 86.4 54.312 ;
    END
  END di0[305]
  PIN di0[306]
    DIRECTION INPUT ;
    USE SIGNAL ;
    PORT
      LAYER M4 ;
        RECT  86.208 54.48 86.4 54.504 ;
    END
  END di0[306]
  PIN di0[307]
    DIRECTION INPUT ;
    USE SIGNAL ;
    PORT
      LAYER M4 ;
        RECT  86.208 54.624 86.4 54.648 ;
    END
  END di0[307]
  PIN di0[308]
    DIRECTION INPUT ;
    USE SIGNAL ;
    PORT
      LAYER M4 ;
        RECT  86.208 54.816 86.4 54.84 ;
    END
  END di0[308]
  PIN di0[309]
    DIRECTION INPUT ;
    USE SIGNAL ;
    PORT
      LAYER M4 ;
        RECT  86.208 54.96 86.4 54.984 ;
    END
  END di0[309]
  PIN di0[30]
    DIRECTION INPUT ;
    USE SIGNAL ;
    PORT
      LAYER M4 ;
        RECT  86.208 9.312 86.4 9.336 ;
    END
  END di0[30]
  PIN di0[310]
    DIRECTION INPUT ;
    USE SIGNAL ;
    PORT
      LAYER M4 ;
        RECT  86.208 55.104 86.4 55.128 ;
    END
  END di0[310]
  PIN di0[311]
    DIRECTION INPUT ;
    USE SIGNAL ;
    PORT
      LAYER M4 ;
        RECT  86.208 55.296 86.4 55.32 ;
    END
  END di0[311]
  PIN di0[312]
    DIRECTION INPUT ;
    USE SIGNAL ;
    PORT
      LAYER M4 ;
        RECT  86.208 55.44 86.4 55.464 ;
    END
  END di0[312]
  PIN di0[313]
    DIRECTION INPUT ;
    USE SIGNAL ;
    PORT
      LAYER M4 ;
        RECT  86.208 55.632 86.4 55.656 ;
    END
  END di0[313]
  PIN di0[314]
    DIRECTION INPUT ;
    USE SIGNAL ;
    PORT
      LAYER M4 ;
        RECT  86.208 55.776 86.4 55.8 ;
    END
  END di0[314]
  PIN di0[315]
    DIRECTION INPUT ;
    USE SIGNAL ;
    PORT
      LAYER M4 ;
        RECT  86.208 55.92 86.4 55.944 ;
    END
  END di0[315]
  PIN di0[316]
    DIRECTION INPUT ;
    USE SIGNAL ;
    PORT
      LAYER M4 ;
        RECT  86.208 56.112 86.4 56.136 ;
    END
  END di0[316]
  PIN di0[317]
    DIRECTION INPUT ;
    USE SIGNAL ;
    PORT
      LAYER M4 ;
        RECT  86.208 56.256 86.4 56.28 ;
    END
  END di0[317]
  PIN di0[318]
    DIRECTION INPUT ;
    USE SIGNAL ;
    PORT
      LAYER M4 ;
        RECT  86.208 56.448 86.4 56.472 ;
    END
  END di0[318]
  PIN di0[319]
    DIRECTION INPUT ;
    USE SIGNAL ;
    PORT
      LAYER M4 ;
        RECT  86.208 56.592 86.4 56.616 ;
    END
  END di0[319]
  PIN di0[31]
    DIRECTION INPUT ;
    USE SIGNAL ;
    PORT
      LAYER M4 ;
        RECT  86.208 9.504 86.4 9.528 ;
    END
  END di0[31]
  PIN di0[320]
    DIRECTION INPUT ;
    USE SIGNAL ;
    PORT
      LAYER M4 ;
        RECT  86.208 56.736 86.4 56.76 ;
    END
  END di0[320]
  PIN di0[321]
    DIRECTION INPUT ;
    USE SIGNAL ;
    PORT
      LAYER M4 ;
        RECT  86.208 56.928 86.4 56.952 ;
    END
  END di0[321]
  PIN di0[322]
    DIRECTION INPUT ;
    USE SIGNAL ;
    PORT
      LAYER M4 ;
        RECT  86.208 57.072 86.4 57.096 ;
    END
  END di0[322]
  PIN di0[323]
    DIRECTION INPUT ;
    USE SIGNAL ;
    PORT
      LAYER M4 ;
        RECT  86.208 57.264 86.4 57.288 ;
    END
  END di0[323]
  PIN di0[324]
    DIRECTION INPUT ;
    USE SIGNAL ;
    PORT
      LAYER M4 ;
        RECT  86.208 57.408 86.4 57.432 ;
    END
  END di0[324]
  PIN di0[325]
    DIRECTION INPUT ;
    USE SIGNAL ;
    PORT
      LAYER M4 ;
        RECT  86.208 57.552 86.4 57.576 ;
    END
  END di0[325]
  PIN di0[326]
    DIRECTION INPUT ;
    USE SIGNAL ;
    PORT
      LAYER M4 ;
        RECT  86.208 57.744 86.4 57.768 ;
    END
  END di0[326]
  PIN di0[327]
    DIRECTION INPUT ;
    USE SIGNAL ;
    PORT
      LAYER M4 ;
        RECT  86.208 57.888 86.4 57.912 ;
    END
  END di0[327]
  PIN di0[328]
    DIRECTION INPUT ;
    USE SIGNAL ;
    PORT
      LAYER M4 ;
        RECT  86.208 58.08 86.4 58.104 ;
    END
  END di0[328]
  PIN di0[329]
    DIRECTION INPUT ;
    USE SIGNAL ;
    PORT
      LAYER M4 ;
        RECT  86.208 58.224 86.4 58.248 ;
    END
  END di0[329]
  PIN di0[32]
    DIRECTION INPUT ;
    USE SIGNAL ;
    PORT
      LAYER M4 ;
        RECT  86.208 9.648 86.4 9.672 ;
    END
  END di0[32]
  PIN di0[330]
    DIRECTION INPUT ;
    USE SIGNAL ;
    PORT
      LAYER M4 ;
        RECT  86.208 58.416 86.4 58.44 ;
    END
  END di0[330]
  PIN di0[331]
    DIRECTION INPUT ;
    USE SIGNAL ;
    PORT
      LAYER M4 ;
        RECT  86.208 58.56 86.4 58.584 ;
    END
  END di0[331]
  PIN di0[332]
    DIRECTION INPUT ;
    USE SIGNAL ;
    PORT
      LAYER M4 ;
        RECT  86.208 58.704 86.4 58.728 ;
    END
  END di0[332]
  PIN di0[333]
    DIRECTION INPUT ;
    USE SIGNAL ;
    PORT
      LAYER M4 ;
        RECT  86.208 58.896 86.4 58.92 ;
    END
  END di0[333]
  PIN di0[334]
    DIRECTION INPUT ;
    USE SIGNAL ;
    PORT
      LAYER M4 ;
        RECT  86.208 59.04 86.4 59.064 ;
    END
  END di0[334]
  PIN di0[335]
    DIRECTION INPUT ;
    USE SIGNAL ;
    PORT
      LAYER M4 ;
        RECT  86.208 59.232 86.4 59.256 ;
    END
  END di0[335]
  PIN di0[336]
    DIRECTION INPUT ;
    USE SIGNAL ;
    PORT
      LAYER M4 ;
        RECT  86.208 59.376 86.4 59.4 ;
    END
  END di0[336]
  PIN di0[337]
    DIRECTION INPUT ;
    USE SIGNAL ;
    PORT
      LAYER M4 ;
        RECT  86.208 59.52 86.4 59.544 ;
    END
  END di0[337]
  PIN di0[338]
    DIRECTION INPUT ;
    USE SIGNAL ;
    PORT
      LAYER M4 ;
        RECT  86.208 59.712 86.4 59.736 ;
    END
  END di0[338]
  PIN di0[339]
    DIRECTION INPUT ;
    USE SIGNAL ;
    PORT
      LAYER M4 ;
        RECT  86.208 59.856 86.4 59.88 ;
    END
  END di0[339]
  PIN di0[33]
    DIRECTION INPUT ;
    USE SIGNAL ;
    PORT
      LAYER M4 ;
        RECT  86.208 9.792 86.4 9.816 ;
    END
  END di0[33]
  PIN di0[340]
    DIRECTION INPUT ;
    USE SIGNAL ;
    PORT
      LAYER M4 ;
        RECT  86.208 60.048 86.4 60.072 ;
    END
  END di0[340]
  PIN di0[341]
    DIRECTION INPUT ;
    USE SIGNAL ;
    PORT
      LAYER M4 ;
        RECT  86.208 60.192 86.4 60.216 ;
    END
  END di0[341]
  PIN di0[342]
    DIRECTION INPUT ;
    USE SIGNAL ;
    PORT
      LAYER M4 ;
        RECT  86.208 60.336 86.4 60.36 ;
    END
  END di0[342]
  PIN di0[343]
    DIRECTION INPUT ;
    USE SIGNAL ;
    PORT
      LAYER M4 ;
        RECT  86.208 60.528 86.4 60.552 ;
    END
  END di0[343]
  PIN di0[344]
    DIRECTION INPUT ;
    USE SIGNAL ;
    PORT
      LAYER M4 ;
        RECT  86.208 60.672 86.4 60.696 ;
    END
  END di0[344]
  PIN di0[345]
    DIRECTION INPUT ;
    USE SIGNAL ;
    PORT
      LAYER M4 ;
        RECT  86.208 60.864 86.4 60.888 ;
    END
  END di0[345]
  PIN di0[346]
    DIRECTION INPUT ;
    USE SIGNAL ;
    PORT
      LAYER M4 ;
        RECT  86.208 61.008 86.4 61.032 ;
    END
  END di0[346]
  PIN di0[347]
    DIRECTION INPUT ;
    USE SIGNAL ;
    PORT
      LAYER M4 ;
        RECT  86.208 61.152 86.4 61.176 ;
    END
  END di0[347]
  PIN di0[348]
    DIRECTION INPUT ;
    USE SIGNAL ;
    PORT
      LAYER M4 ;
        RECT  86.208 61.344 86.4 61.368 ;
    END
  END di0[348]
  PIN di0[349]
    DIRECTION INPUT ;
    USE SIGNAL ;
    PORT
      LAYER M4 ;
        RECT  86.208 61.488 86.4 61.512 ;
    END
  END di0[349]
  PIN di0[34]
    DIRECTION INPUT ;
    USE SIGNAL ;
    PORT
      LAYER M4 ;
        RECT  86.208 9.984 86.4 10.008 ;
    END
  END di0[34]
  PIN di0[350]
    DIRECTION INPUT ;
    USE SIGNAL ;
    PORT
      LAYER M4 ;
        RECT  86.208 61.68 86.4 61.704 ;
    END
  END di0[350]
  PIN di0[351]
    DIRECTION INPUT ;
    USE SIGNAL ;
    PORT
      LAYER M4 ;
        RECT  86.208 61.824 86.4 61.848 ;
    END
  END di0[351]
  PIN di0[352]
    DIRECTION INPUT ;
    USE SIGNAL ;
    PORT
      LAYER M4 ;
        RECT  86.208 61.968 86.4 61.992 ;
    END
  END di0[352]
  PIN di0[353]
    DIRECTION INPUT ;
    USE SIGNAL ;
    PORT
      LAYER M4 ;
        RECT  86.208 62.16 86.4 62.184 ;
    END
  END di0[353]
  PIN di0[354]
    DIRECTION INPUT ;
    USE SIGNAL ;
    PORT
      LAYER M4 ;
        RECT  86.208 62.304 86.4 62.328 ;
    END
  END di0[354]
  PIN di0[355]
    DIRECTION INPUT ;
    USE SIGNAL ;
    PORT
      LAYER M4 ;
        RECT  86.208 62.496 86.4 62.52 ;
    END
  END di0[355]
  PIN di0[356]
    DIRECTION INPUT ;
    USE SIGNAL ;
    PORT
      LAYER M4 ;
        RECT  86.208 62.64 86.4 62.664 ;
    END
  END di0[356]
  PIN di0[357]
    DIRECTION INPUT ;
    USE SIGNAL ;
    PORT
      LAYER M4 ;
        RECT  86.208 62.832 86.4 62.856 ;
    END
  END di0[357]
  PIN di0[358]
    DIRECTION INPUT ;
    USE SIGNAL ;
    PORT
      LAYER M4 ;
        RECT  86.208 62.976 86.4 63 ;
    END
  END di0[358]
  PIN di0[359]
    DIRECTION INPUT ;
    USE SIGNAL ;
    PORT
      LAYER M4 ;
        RECT  86.208 63.12 86.4 63.144 ;
    END
  END di0[359]
  PIN di0[35]
    DIRECTION INPUT ;
    USE SIGNAL ;
    PORT
      LAYER M4 ;
        RECT  86.208 10.128 86.4 10.152 ;
    END
  END di0[35]
  PIN di0[360]
    DIRECTION INPUT ;
    USE SIGNAL ;
    PORT
      LAYER M4 ;
        RECT  86.208 63.312 86.4 63.336 ;
    END
  END di0[360]
  PIN di0[361]
    DIRECTION INPUT ;
    USE SIGNAL ;
    PORT
      LAYER M4 ;
        RECT  86.208 63.456 86.4 63.48 ;
    END
  END di0[361]
  PIN di0[362]
    DIRECTION INPUT ;
    USE SIGNAL ;
    PORT
      LAYER M4 ;
        RECT  86.208 63.648 86.4 63.672 ;
    END
  END di0[362]
  PIN di0[363]
    DIRECTION INPUT ;
    USE SIGNAL ;
    PORT
      LAYER M4 ;
        RECT  86.208 63.792 86.4 63.816 ;
    END
  END di0[363]
  PIN di0[364]
    DIRECTION INPUT ;
    USE SIGNAL ;
    PORT
      LAYER M4 ;
        RECT  86.208 63.936 86.4 63.96 ;
    END
  END di0[364]
  PIN di0[365]
    DIRECTION INPUT ;
    USE SIGNAL ;
    PORT
      LAYER M4 ;
        RECT  86.208 64.128 86.4 64.152 ;
    END
  END di0[365]
  PIN di0[366]
    DIRECTION INPUT ;
    USE SIGNAL ;
    PORT
      LAYER M4 ;
        RECT  86.208 64.272 86.4 64.296 ;
    END
  END di0[366]
  PIN di0[367]
    DIRECTION INPUT ;
    USE SIGNAL ;
    PORT
      LAYER M4 ;
        RECT  86.208 64.464 86.4 64.488 ;
    END
  END di0[367]
  PIN di0[368]
    DIRECTION INPUT ;
    USE SIGNAL ;
    PORT
      LAYER M4 ;
        RECT  86.208 64.608 86.4 64.632 ;
    END
  END di0[368]
  PIN di0[369]
    DIRECTION INPUT ;
    USE SIGNAL ;
    PORT
      LAYER M4 ;
        RECT  86.208 64.752 86.4 64.776 ;
    END
  END di0[369]
  PIN di0[36]
    DIRECTION INPUT ;
    USE SIGNAL ;
    PORT
      LAYER M4 ;
        RECT  86.208 10.32 86.4 10.344 ;
    END
  END di0[36]
  PIN di0[370]
    DIRECTION INPUT ;
    USE SIGNAL ;
    PORT
      LAYER M4 ;
        RECT  86.208 64.944 86.4 64.968 ;
    END
  END di0[370]
  PIN di0[371]
    DIRECTION INPUT ;
    USE SIGNAL ;
    PORT
      LAYER M4 ;
        RECT  86.208 65.088 86.4 65.112 ;
    END
  END di0[371]
  PIN di0[372]
    DIRECTION INPUT ;
    USE SIGNAL ;
    PORT
      LAYER M4 ;
        RECT  86.208 65.28 86.4 65.304 ;
    END
  END di0[372]
  PIN di0[373]
    DIRECTION INPUT ;
    USE SIGNAL ;
    PORT
      LAYER M4 ;
        RECT  86.208 65.424 86.4 65.448 ;
    END
  END di0[373]
  PIN di0[374]
    DIRECTION INPUT ;
    USE SIGNAL ;
    PORT
      LAYER M4 ;
        RECT  86.208 65.568 86.4 65.592 ;
    END
  END di0[374]
  PIN di0[375]
    DIRECTION INPUT ;
    USE SIGNAL ;
    PORT
      LAYER M4 ;
        RECT  86.208 65.76 86.4 65.784 ;
    END
  END di0[375]
  PIN di0[376]
    DIRECTION INPUT ;
    USE SIGNAL ;
    PORT
      LAYER M4 ;
        RECT  86.208 65.904 86.4 65.928 ;
    END
  END di0[376]
  PIN di0[377]
    DIRECTION INPUT ;
    USE SIGNAL ;
    PORT
      LAYER M4 ;
        RECT  86.208 66.096 86.4 66.12 ;
    END
  END di0[377]
  PIN di0[378]
    DIRECTION INPUT ;
    USE SIGNAL ;
    PORT
      LAYER M4 ;
        RECT  86.208 66.24 86.4 66.264 ;
    END
  END di0[378]
  PIN di0[379]
    DIRECTION INPUT ;
    USE SIGNAL ;
    PORT
      LAYER M4 ;
        RECT  86.208 66.384 86.4 66.408 ;
    END
  END di0[379]
  PIN di0[37]
    DIRECTION INPUT ;
    USE SIGNAL ;
    PORT
      LAYER M4 ;
        RECT  86.208 10.464 86.4 10.488 ;
    END
  END di0[37]
  PIN di0[380]
    DIRECTION INPUT ;
    USE SIGNAL ;
    PORT
      LAYER M4 ;
        RECT  86.208 66.576 86.4 66.6 ;
    END
  END di0[380]
  PIN di0[381]
    DIRECTION INPUT ;
    USE SIGNAL ;
    PORT
      LAYER M4 ;
        RECT  86.208 66.72 86.4 66.744 ;
    END
  END di0[381]
  PIN di0[382]
    DIRECTION INPUT ;
    USE SIGNAL ;
    PORT
      LAYER M4 ;
        RECT  86.208 66.912 86.4 66.936 ;
    END
  END di0[382]
  PIN di0[383]
    DIRECTION INPUT ;
    USE SIGNAL ;
    PORT
      LAYER M4 ;
        RECT  86.208 67.056 86.4 67.08 ;
    END
  END di0[383]
  PIN di0[384]
    DIRECTION INPUT ;
    USE SIGNAL ;
    PORT
      LAYER M4 ;
        RECT  86.208 67.248 86.4 67.272 ;
    END
  END di0[384]
  PIN di0[385]
    DIRECTION INPUT ;
    USE SIGNAL ;
    PORT
      LAYER M4 ;
        RECT  86.208 67.392 86.4 67.416 ;
    END
  END di0[385]
  PIN di0[386]
    DIRECTION INPUT ;
    USE SIGNAL ;
    PORT
      LAYER M4 ;
        RECT  86.208 67.536 86.4 67.56 ;
    END
  END di0[386]
  PIN di0[387]
    DIRECTION INPUT ;
    USE SIGNAL ;
    PORT
      LAYER M4 ;
        RECT  86.208 67.728 86.4 67.752 ;
    END
  END di0[387]
  PIN di0[388]
    DIRECTION INPUT ;
    USE SIGNAL ;
    PORT
      LAYER M4 ;
        RECT  86.208 67.872 86.4 67.896 ;
    END
  END di0[388]
  PIN di0[389]
    DIRECTION INPUT ;
    USE SIGNAL ;
    PORT
      LAYER M4 ;
        RECT  86.208 68.064 86.4 68.088 ;
    END
  END di0[389]
  PIN di0[38]
    DIRECTION INPUT ;
    USE SIGNAL ;
    PORT
      LAYER M4 ;
        RECT  86.208 10.608 86.4 10.632 ;
    END
  END di0[38]
  PIN di0[390]
    DIRECTION INPUT ;
    USE SIGNAL ;
    PORT
      LAYER M4 ;
        RECT  86.208 68.208 86.4 68.232 ;
    END
  END di0[390]
  PIN di0[391]
    DIRECTION INPUT ;
    USE SIGNAL ;
    PORT
      LAYER M4 ;
        RECT  86.208 68.352 86.4 68.376 ;
    END
  END di0[391]
  PIN di0[392]
    DIRECTION INPUT ;
    USE SIGNAL ;
    PORT
      LAYER M4 ;
        RECT  86.208 68.544 86.4 68.568 ;
    END
  END di0[392]
  PIN di0[393]
    DIRECTION INPUT ;
    USE SIGNAL ;
    PORT
      LAYER M4 ;
        RECT  86.208 68.688 86.4 68.712 ;
    END
  END di0[393]
  PIN di0[394]
    DIRECTION INPUT ;
    USE SIGNAL ;
    PORT
      LAYER M4 ;
        RECT  86.208 68.88 86.4 68.904 ;
    END
  END di0[394]
  PIN di0[395]
    DIRECTION INPUT ;
    USE SIGNAL ;
    PORT
      LAYER M4 ;
        RECT  86.208 69.024 86.4 69.048 ;
    END
  END di0[395]
  PIN di0[396]
    DIRECTION INPUT ;
    USE SIGNAL ;
    PORT
      LAYER M4 ;
        RECT  86.208 69.168 86.4 69.192 ;
    END
  END di0[396]
  PIN di0[397]
    DIRECTION INPUT ;
    USE SIGNAL ;
    PORT
      LAYER M4 ;
        RECT  86.208 69.36 86.4 69.384 ;
    END
  END di0[397]
  PIN di0[398]
    DIRECTION INPUT ;
    USE SIGNAL ;
    PORT
      LAYER M4 ;
        RECT  86.208 69.504 86.4 69.528 ;
    END
  END di0[398]
  PIN di0[399]
    DIRECTION INPUT ;
    USE SIGNAL ;
    PORT
      LAYER M4 ;
        RECT  86.208 69.696 86.4 69.72 ;
    END
  END di0[399]
  PIN di0[39]
    DIRECTION INPUT ;
    USE SIGNAL ;
    PORT
      LAYER M4 ;
        RECT  86.208 10.8 86.4 10.824 ;
    END
  END di0[39]
  PIN di0[3]
    DIRECTION INPUT ;
    USE SIGNAL ;
    PORT
      LAYER M4 ;
        RECT  86.208 4.896 86.4 4.92 ;
    END
  END di0[3]
  PIN di0[400]
    DIRECTION INPUT ;
    USE SIGNAL ;
    PORT
      LAYER M4 ;
        RECT  86.208 69.84 86.4 69.864 ;
    END
  END di0[400]
  PIN di0[401]
    DIRECTION INPUT ;
    USE SIGNAL ;
    PORT
      LAYER M4 ;
        RECT  86.208 69.984 86.4 70.008 ;
    END
  END di0[401]
  PIN di0[402]
    DIRECTION INPUT ;
    USE SIGNAL ;
    PORT
      LAYER M4 ;
        RECT  86.208 70.176 86.4 70.2 ;
    END
  END di0[402]
  PIN di0[403]
    DIRECTION INPUT ;
    USE SIGNAL ;
    PORT
      LAYER M4 ;
        RECT  86.208 70.32 86.4 70.344 ;
    END
  END di0[403]
  PIN di0[404]
    DIRECTION INPUT ;
    USE SIGNAL ;
    PORT
      LAYER M4 ;
        RECT  86.208 70.512 86.4 70.536 ;
    END
  END di0[404]
  PIN di0[405]
    DIRECTION INPUT ;
    USE SIGNAL ;
    PORT
      LAYER M4 ;
        RECT  86.208 70.656 86.4 70.68 ;
    END
  END di0[405]
  PIN di0[406]
    DIRECTION INPUT ;
    USE SIGNAL ;
    PORT
      LAYER M4 ;
        RECT  86.208 70.848 86.4 70.872 ;
    END
  END di0[406]
  PIN di0[407]
    DIRECTION INPUT ;
    USE SIGNAL ;
    PORT
      LAYER M4 ;
        RECT  86.208 70.992 86.4 71.016 ;
    END
  END di0[407]
  PIN di0[408]
    DIRECTION INPUT ;
    USE SIGNAL ;
    PORT
      LAYER M4 ;
        RECT  86.208 71.136 86.4 71.16 ;
    END
  END di0[408]
  PIN di0[409]
    DIRECTION INPUT ;
    USE SIGNAL ;
    PORT
      LAYER M4 ;
        RECT  86.208 71.328 86.4 71.352 ;
    END
  END di0[409]
  PIN di0[40]
    DIRECTION INPUT ;
    USE SIGNAL ;
    PORT
      LAYER M4 ;
        RECT  86.208 10.944 86.4 10.968 ;
    END
  END di0[40]
  PIN di0[410]
    DIRECTION INPUT ;
    USE SIGNAL ;
    PORT
      LAYER M4 ;
        RECT  86.208 71.472 86.4 71.496 ;
    END
  END di0[410]
  PIN di0[411]
    DIRECTION INPUT ;
    USE SIGNAL ;
    PORT
      LAYER M4 ;
        RECT  86.208 71.664 86.4 71.688 ;
    END
  END di0[411]
  PIN di0[412]
    DIRECTION INPUT ;
    USE SIGNAL ;
    PORT
      LAYER M4 ;
        RECT  86.208 71.808 86.4 71.832 ;
    END
  END di0[412]
  PIN di0[413]
    DIRECTION INPUT ;
    USE SIGNAL ;
    PORT
      LAYER M4 ;
        RECT  86.208 71.952 86.4 71.976 ;
    END
  END di0[413]
  PIN di0[414]
    DIRECTION INPUT ;
    USE SIGNAL ;
    PORT
      LAYER M4 ;
        RECT  86.208 72.144 86.4 72.168 ;
    END
  END di0[414]
  PIN di0[415]
    DIRECTION INPUT ;
    USE SIGNAL ;
    PORT
      LAYER M4 ;
        RECT  86.208 72.288 86.4 72.312 ;
    END
  END di0[415]
  PIN di0[416]
    DIRECTION INPUT ;
    USE SIGNAL ;
    PORT
      LAYER M4 ;
        RECT  86.208 72.48 86.4 72.504 ;
    END
  END di0[416]
  PIN di0[417]
    DIRECTION INPUT ;
    USE SIGNAL ;
    PORT
      LAYER M4 ;
        RECT  86.208 72.624 86.4 72.648 ;
    END
  END di0[417]
  PIN di0[418]
    DIRECTION INPUT ;
    USE SIGNAL ;
    PORT
      LAYER M4 ;
        RECT  86.208 72.768 86.4 72.792 ;
    END
  END di0[418]
  PIN di0[419]
    DIRECTION INPUT ;
    USE SIGNAL ;
    PORT
      LAYER M4 ;
        RECT  86.208 72.96 86.4 72.984 ;
    END
  END di0[419]
  PIN di0[41]
    DIRECTION INPUT ;
    USE SIGNAL ;
    PORT
      LAYER M4 ;
        RECT  86.208 11.136 86.4 11.16 ;
    END
  END di0[41]
  PIN di0[420]
    DIRECTION INPUT ;
    USE SIGNAL ;
    PORT
      LAYER M4 ;
        RECT  86.208 73.104 86.4 73.128 ;
    END
  END di0[420]
  PIN di0[421]
    DIRECTION INPUT ;
    USE SIGNAL ;
    PORT
      LAYER M4 ;
        RECT  86.208 73.296 86.4 73.32 ;
    END
  END di0[421]
  PIN di0[422]
    DIRECTION INPUT ;
    USE SIGNAL ;
    PORT
      LAYER M4 ;
        RECT  86.208 73.44 86.4 73.464 ;
    END
  END di0[422]
  PIN di0[423]
    DIRECTION INPUT ;
    USE SIGNAL ;
    PORT
      LAYER M4 ;
        RECT  86.208 73.584 86.4 73.608 ;
    END
  END di0[423]
  PIN di0[424]
    DIRECTION INPUT ;
    USE SIGNAL ;
    PORT
      LAYER M4 ;
        RECT  86.208 73.776 86.4 73.8 ;
    END
  END di0[424]
  PIN di0[425]
    DIRECTION INPUT ;
    USE SIGNAL ;
    PORT
      LAYER M4 ;
        RECT  86.208 73.92 86.4 73.944 ;
    END
  END di0[425]
  PIN di0[426]
    DIRECTION INPUT ;
    USE SIGNAL ;
    PORT
      LAYER M4 ;
        RECT  86.208 74.112 86.4 74.136 ;
    END
  END di0[426]
  PIN di0[427]
    DIRECTION INPUT ;
    USE SIGNAL ;
    PORT
      LAYER M4 ;
        RECT  86.208 74.256 86.4 74.28 ;
    END
  END di0[427]
  PIN di0[428]
    DIRECTION INPUT ;
    USE SIGNAL ;
    PORT
      LAYER M4 ;
        RECT  86.208 74.4 86.4 74.424 ;
    END
  END di0[428]
  PIN di0[429]
    DIRECTION INPUT ;
    USE SIGNAL ;
    PORT
      LAYER M4 ;
        RECT  86.208 74.592 86.4 74.616 ;
    END
  END di0[429]
  PIN di0[42]
    DIRECTION INPUT ;
    USE SIGNAL ;
    PORT
      LAYER M4 ;
        RECT  86.208 11.28 86.4 11.304 ;
    END
  END di0[42]
  PIN di0[430]
    DIRECTION INPUT ;
    USE SIGNAL ;
    PORT
      LAYER M4 ;
        RECT  86.208 74.736 86.4 74.76 ;
    END
  END di0[430]
  PIN di0[431]
    DIRECTION INPUT ;
    USE SIGNAL ;
    PORT
      LAYER M4 ;
        RECT  86.208 74.928 86.4 74.952 ;
    END
  END di0[431]
  PIN di0[432]
    DIRECTION INPUT ;
    USE SIGNAL ;
    PORT
      LAYER M4 ;
        RECT  86.208 75.072 86.4 75.096 ;
    END
  END di0[432]
  PIN di0[433]
    DIRECTION INPUT ;
    USE SIGNAL ;
    PORT
      LAYER M4 ;
        RECT  86.208 75.264 86.4 75.288 ;
    END
  END di0[433]
  PIN di0[434]
    DIRECTION INPUT ;
    USE SIGNAL ;
    PORT
      LAYER M4 ;
        RECT  86.208 75.408 86.4 75.432 ;
    END
  END di0[434]
  PIN di0[435]
    DIRECTION INPUT ;
    USE SIGNAL ;
    PORT
      LAYER M4 ;
        RECT  86.208 75.552 86.4 75.576 ;
    END
  END di0[435]
  PIN di0[436]
    DIRECTION INPUT ;
    USE SIGNAL ;
    PORT
      LAYER M4 ;
        RECT  86.208 75.744 86.4 75.768 ;
    END
  END di0[436]
  PIN di0[437]
    DIRECTION INPUT ;
    USE SIGNAL ;
    PORT
      LAYER M4 ;
        RECT  86.208 75.888 86.4 75.912 ;
    END
  END di0[437]
  PIN di0[438]
    DIRECTION INPUT ;
    USE SIGNAL ;
    PORT
      LAYER M4 ;
        RECT  86.208 76.08 86.4 76.104 ;
    END
  END di0[438]
  PIN di0[439]
    DIRECTION INPUT ;
    USE SIGNAL ;
    PORT
      LAYER M4 ;
        RECT  86.208 76.224 86.4 76.248 ;
    END
  END di0[439]
  PIN di0[43]
    DIRECTION INPUT ;
    USE SIGNAL ;
    PORT
      LAYER M4 ;
        RECT  86.208 11.424 86.4 11.448 ;
    END
  END di0[43]
  PIN di0[440]
    DIRECTION INPUT ;
    USE SIGNAL ;
    PORT
      LAYER M4 ;
        RECT  86.208 76.368 86.4 76.392 ;
    END
  END di0[440]
  PIN di0[441]
    DIRECTION INPUT ;
    USE SIGNAL ;
    PORT
      LAYER M4 ;
        RECT  86.208 76.56 86.4 76.584 ;
    END
  END di0[441]
  PIN di0[442]
    DIRECTION INPUT ;
    USE SIGNAL ;
    PORT
      LAYER M4 ;
        RECT  86.208 76.704 86.4 76.728 ;
    END
  END di0[442]
  PIN di0[443]
    DIRECTION INPUT ;
    USE SIGNAL ;
    PORT
      LAYER M4 ;
        RECT  86.208 76.896 86.4 76.92 ;
    END
  END di0[443]
  PIN di0[444]
    DIRECTION INPUT ;
    USE SIGNAL ;
    PORT
      LAYER M4 ;
        RECT  86.208 77.04 86.4 77.064 ;
    END
  END di0[444]
  PIN di0[445]
    DIRECTION INPUT ;
    USE SIGNAL ;
    PORT
      LAYER M4 ;
        RECT  86.208 77.184 86.4 77.208 ;
    END
  END di0[445]
  PIN di0[446]
    DIRECTION INPUT ;
    USE SIGNAL ;
    PORT
      LAYER M4 ;
        RECT  86.208 77.376 86.4 77.4 ;
    END
  END di0[446]
  PIN di0[447]
    DIRECTION INPUT ;
    USE SIGNAL ;
    PORT
      LAYER M4 ;
        RECT  86.208 77.52 86.4 77.544 ;
    END
  END di0[447]
  PIN di0[448]
    DIRECTION INPUT ;
    USE SIGNAL ;
    PORT
      LAYER M4 ;
        RECT  86.208 77.712 86.4 77.736 ;
    END
  END di0[448]
  PIN di0[449]
    DIRECTION INPUT ;
    USE SIGNAL ;
    PORT
      LAYER M4 ;
        RECT  86.208 77.856 86.4 77.88 ;
    END
  END di0[449]
  PIN di0[44]
    DIRECTION INPUT ;
    USE SIGNAL ;
    PORT
      LAYER M4 ;
        RECT  86.208 11.616 86.4 11.64 ;
    END
  END di0[44]
  PIN di0[450]
    DIRECTION INPUT ;
    USE SIGNAL ;
    PORT
      LAYER M4 ;
        RECT  86.208 78 86.4 78.024 ;
    END
  END di0[450]
  PIN di0[451]
    DIRECTION INPUT ;
    USE SIGNAL ;
    PORT
      LAYER M4 ;
        RECT  86.208 78.192 86.4 78.216 ;
    END
  END di0[451]
  PIN di0[452]
    DIRECTION INPUT ;
    USE SIGNAL ;
    PORT
      LAYER M4 ;
        RECT  86.208 78.336 86.4 78.36 ;
    END
  END di0[452]
  PIN di0[453]
    DIRECTION INPUT ;
    USE SIGNAL ;
    PORT
      LAYER M4 ;
        RECT  86.208 78.528 86.4 78.552 ;
    END
  END di0[453]
  PIN di0[454]
    DIRECTION INPUT ;
    USE SIGNAL ;
    PORT
      LAYER M4 ;
        RECT  86.208 78.672 86.4 78.696 ;
    END
  END di0[454]
  PIN di0[455]
    DIRECTION INPUT ;
    USE SIGNAL ;
    PORT
      LAYER M4 ;
        RECT  86.208 78.816 86.4 78.84 ;
    END
  END di0[455]
  PIN di0[456]
    DIRECTION INPUT ;
    USE SIGNAL ;
    PORT
      LAYER M4 ;
        RECT  86.208 79.008 86.4 79.032 ;
    END
  END di0[456]
  PIN di0[457]
    DIRECTION INPUT ;
    USE SIGNAL ;
    PORT
      LAYER M4 ;
        RECT  86.208 79.152 86.4 79.176 ;
    END
  END di0[457]
  PIN di0[458]
    DIRECTION INPUT ;
    USE SIGNAL ;
    PORT
      LAYER M4 ;
        RECT  86.208 79.344 86.4 79.368 ;
    END
  END di0[458]
  PIN di0[459]
    DIRECTION INPUT ;
    USE SIGNAL ;
    PORT
      LAYER M4 ;
        RECT  86.208 79.488 86.4 79.512 ;
    END
  END di0[459]
  PIN di0[45]
    DIRECTION INPUT ;
    USE SIGNAL ;
    PORT
      LAYER M4 ;
        RECT  86.208 11.76 86.4 11.784 ;
    END
  END di0[45]
  PIN di0[460]
    DIRECTION INPUT ;
    USE SIGNAL ;
    PORT
      LAYER M4 ;
        RECT  86.208 79.68 86.4 79.704 ;
    END
  END di0[460]
  PIN di0[461]
    DIRECTION INPUT ;
    USE SIGNAL ;
    PORT
      LAYER M4 ;
        RECT  86.208 79.824 86.4 79.848 ;
    END
  END di0[461]
  PIN di0[462]
    DIRECTION INPUT ;
    USE SIGNAL ;
    PORT
      LAYER M4 ;
        RECT  86.208 79.968 86.4 79.992 ;
    END
  END di0[462]
  PIN di0[463]
    DIRECTION INPUT ;
    USE SIGNAL ;
    PORT
      LAYER M4 ;
        RECT  86.208 80.16 86.4 80.184 ;
    END
  END di0[463]
  PIN di0[464]
    DIRECTION INPUT ;
    USE SIGNAL ;
    PORT
      LAYER M4 ;
        RECT  86.208 80.304 86.4 80.328 ;
    END
  END di0[464]
  PIN di0[465]
    DIRECTION INPUT ;
    USE SIGNAL ;
    PORT
      LAYER M4 ;
        RECT  86.208 80.496 86.4 80.52 ;
    END
  END di0[465]
  PIN di0[466]
    DIRECTION INPUT ;
    USE SIGNAL ;
    PORT
      LAYER M4 ;
        RECT  86.208 80.64 86.4 80.664 ;
    END
  END di0[466]
  PIN di0[467]
    DIRECTION INPUT ;
    USE SIGNAL ;
    PORT
      LAYER M4 ;
        RECT  86.208 80.784 86.4 80.808 ;
    END
  END di0[467]
  PIN di0[468]
    DIRECTION INPUT ;
    USE SIGNAL ;
    PORT
      LAYER M4 ;
        RECT  86.208 80.976 86.4 81 ;
    END
  END di0[468]
  PIN di0[469]
    DIRECTION INPUT ;
    USE SIGNAL ;
    PORT
      LAYER M4 ;
        RECT  86.208 81.12 86.4 81.144 ;
    END
  END di0[469]
  PIN di0[46]
    DIRECTION INPUT ;
    USE SIGNAL ;
    PORT
      LAYER M4 ;
        RECT  86.208 11.952 86.4 11.976 ;
    END
  END di0[46]
  PIN di0[470]
    DIRECTION INPUT ;
    USE SIGNAL ;
    PORT
      LAYER M4 ;
        RECT  86.208 81.312 86.4 81.336 ;
    END
  END di0[470]
  PIN di0[471]
    DIRECTION INPUT ;
    USE SIGNAL ;
    PORT
      LAYER M4 ;
        RECT  86.208 81.456 86.4 81.48 ;
    END
  END di0[471]
  PIN di0[472]
    DIRECTION INPUT ;
    USE SIGNAL ;
    PORT
      LAYER M4 ;
        RECT  86.208 81.6 86.4 81.624 ;
    END
  END di0[472]
  PIN di0[473]
    DIRECTION INPUT ;
    USE SIGNAL ;
    PORT
      LAYER M4 ;
        RECT  86.208 81.792 86.4 81.816 ;
    END
  END di0[473]
  PIN di0[474]
    DIRECTION INPUT ;
    USE SIGNAL ;
    PORT
      LAYER M4 ;
        RECT  86.208 81.936 86.4 81.96 ;
    END
  END di0[474]
  PIN di0[475]
    DIRECTION INPUT ;
    USE SIGNAL ;
    PORT
      LAYER M4 ;
        RECT  86.208 82.128 86.4 82.152 ;
    END
  END di0[475]
  PIN di0[476]
    DIRECTION INPUT ;
    USE SIGNAL ;
    PORT
      LAYER M4 ;
        RECT  86.208 82.272 86.4 82.296 ;
    END
  END di0[476]
  PIN di0[477]
    DIRECTION INPUT ;
    USE SIGNAL ;
    PORT
      LAYER M4 ;
        RECT  86.208 82.416 86.4 82.44 ;
    END
  END di0[477]
  PIN di0[478]
    DIRECTION INPUT ;
    USE SIGNAL ;
    PORT
      LAYER M4 ;
        RECT  86.208 82.608 86.4 82.632 ;
    END
  END di0[478]
  PIN di0[479]
    DIRECTION INPUT ;
    USE SIGNAL ;
    PORT
      LAYER M4 ;
        RECT  86.208 82.752 86.4 82.776 ;
    END
  END di0[479]
  PIN di0[47]
    DIRECTION INPUT ;
    USE SIGNAL ;
    PORT
      LAYER M4 ;
        RECT  86.208 12.096 86.4 12.12 ;
    END
  END di0[47]
  PIN di0[480]
    DIRECTION INPUT ;
    USE SIGNAL ;
    PORT
      LAYER M4 ;
        RECT  86.208 82.944 86.4 82.968 ;
    END
  END di0[480]
  PIN di0[481]
    DIRECTION INPUT ;
    USE SIGNAL ;
    PORT
      LAYER M4 ;
        RECT  86.208 83.088 86.4 83.112 ;
    END
  END di0[481]
  PIN di0[482]
    DIRECTION INPUT ;
    USE SIGNAL ;
    PORT
      LAYER M4 ;
        RECT  86.208 83.232 86.4 83.256 ;
    END
  END di0[482]
  PIN di0[483]
    DIRECTION INPUT ;
    USE SIGNAL ;
    PORT
      LAYER M4 ;
        RECT  86.208 83.424 86.4 83.448 ;
    END
  END di0[483]
  PIN di0[484]
    DIRECTION INPUT ;
    USE SIGNAL ;
    PORT
      LAYER M4 ;
        RECT  86.208 83.568 86.4 83.592 ;
    END
  END di0[484]
  PIN di0[485]
    DIRECTION INPUT ;
    USE SIGNAL ;
    PORT
      LAYER M4 ;
        RECT  86.208 83.76 86.4 83.784 ;
    END
  END di0[485]
  PIN di0[486]
    DIRECTION INPUT ;
    USE SIGNAL ;
    PORT
      LAYER M4 ;
        RECT  86.208 83.904 86.4 83.928 ;
    END
  END di0[486]
  PIN di0[487]
    DIRECTION INPUT ;
    USE SIGNAL ;
    PORT
      LAYER M4 ;
        RECT  86.208 84.096 86.4 84.12 ;
    END
  END di0[487]
  PIN di0[488]
    DIRECTION INPUT ;
    USE SIGNAL ;
    PORT
      LAYER M4 ;
        RECT  86.208 84.24 86.4 84.264 ;
    END
  END di0[488]
  PIN di0[489]
    DIRECTION INPUT ;
    USE SIGNAL ;
    PORT
      LAYER M4 ;
        RECT  86.208 84.384 86.4 84.408 ;
    END
  END di0[489]
  PIN di0[48]
    DIRECTION INPUT ;
    USE SIGNAL ;
    PORT
      LAYER M4 ;
        RECT  86.208 12.288 86.4 12.312 ;
    END
  END di0[48]
  PIN di0[490]
    DIRECTION INPUT ;
    USE SIGNAL ;
    PORT
      LAYER M4 ;
        RECT  86.208 84.576 86.4 84.6 ;
    END
  END di0[490]
  PIN di0[491]
    DIRECTION INPUT ;
    USE SIGNAL ;
    PORT
      LAYER M4 ;
        RECT  86.208 84.72 86.4 84.744 ;
    END
  END di0[491]
  PIN di0[492]
    DIRECTION INPUT ;
    USE SIGNAL ;
    PORT
      LAYER M4 ;
        RECT  86.208 84.912 86.4 84.936 ;
    END
  END di0[492]
  PIN di0[493]
    DIRECTION INPUT ;
    USE SIGNAL ;
    PORT
      LAYER M4 ;
        RECT  86.208 85.056 86.4 85.08 ;
    END
  END di0[493]
  PIN di0[494]
    DIRECTION INPUT ;
    USE SIGNAL ;
    PORT
      LAYER M4 ;
        RECT  86.208 85.2 86.4 85.224 ;
    END
  END di0[494]
  PIN di0[495]
    DIRECTION INPUT ;
    USE SIGNAL ;
    PORT
      LAYER M4 ;
        RECT  86.208 85.392 86.4 85.416 ;
    END
  END di0[495]
  PIN di0[496]
    DIRECTION INPUT ;
    USE SIGNAL ;
    PORT
      LAYER M4 ;
        RECT  86.208 85.536 86.4 85.56 ;
    END
  END di0[496]
  PIN di0[497]
    DIRECTION INPUT ;
    USE SIGNAL ;
    PORT
      LAYER M4 ;
        RECT  86.208 85.728 86.4 85.752 ;
    END
  END di0[497]
  PIN di0[498]
    DIRECTION INPUT ;
    USE SIGNAL ;
    PORT
      LAYER M4 ;
        RECT  86.208 85.872 86.4 85.896 ;
    END
  END di0[498]
  PIN di0[499]
    DIRECTION INPUT ;
    USE SIGNAL ;
    PORT
      LAYER M4 ;
        RECT  86.208 86.016 86.4 86.04 ;
    END
  END di0[499]
  PIN di0[49]
    DIRECTION INPUT ;
    USE SIGNAL ;
    PORT
      LAYER M4 ;
        RECT  86.208 12.432 86.4 12.456 ;
    END
  END di0[49]
  PIN di0[4]
    DIRECTION INPUT ;
    USE SIGNAL ;
    PORT
      LAYER M4 ;
        RECT  86.208 5.088 86.4 5.112 ;
    END
  END di0[4]
  PIN di0[500]
    DIRECTION INPUT ;
    USE SIGNAL ;
    PORT
      LAYER M4 ;
        RECT  86.208 86.208 86.4 86.232 ;
    END
  END di0[500]
  PIN di0[501]
    DIRECTION INPUT ;
    USE SIGNAL ;
    PORT
      LAYER M4 ;
        RECT  86.208 86.352 86.4 86.376 ;
    END
  END di0[501]
  PIN di0[502]
    DIRECTION INPUT ;
    USE SIGNAL ;
    PORT
      LAYER M4 ;
        RECT  86.208 86.544 86.4 86.568 ;
    END
  END di0[502]
  PIN di0[503]
    DIRECTION INPUT ;
    USE SIGNAL ;
    PORT
      LAYER M4 ;
        RECT  86.208 86.688 86.4 86.712 ;
    END
  END di0[503]
  PIN di0[504]
    DIRECTION INPUT ;
    USE SIGNAL ;
    PORT
      LAYER M4 ;
        RECT  86.208 86.832 86.4 86.856 ;
    END
  END di0[504]
  PIN di0[505]
    DIRECTION INPUT ;
    USE SIGNAL ;
    PORT
      LAYER M4 ;
        RECT  86.208 87.024 86.4 87.048 ;
    END
  END di0[505]
  PIN di0[506]
    DIRECTION INPUT ;
    USE SIGNAL ;
    PORT
      LAYER M4 ;
        RECT  86.208 87.168 86.4 87.192 ;
    END
  END di0[506]
  PIN di0[507]
    DIRECTION INPUT ;
    USE SIGNAL ;
    PORT
      LAYER M4 ;
        RECT  86.208 87.36 86.4 87.384 ;
    END
  END di0[507]
  PIN di0[508]
    DIRECTION INPUT ;
    USE SIGNAL ;
    PORT
      LAYER M4 ;
        RECT  86.208 87.504 86.4 87.528 ;
    END
  END di0[508]
  PIN di0[509]
    DIRECTION INPUT ;
    USE SIGNAL ;
    PORT
      LAYER M4 ;
        RECT  86.208 87.696 86.4 87.72 ;
    END
  END di0[509]
  PIN di0[50]
    DIRECTION INPUT ;
    USE SIGNAL ;
    PORT
      LAYER M4 ;
        RECT  86.208 12.576 86.4 12.6 ;
    END
  END di0[50]
  PIN di0[510]
    DIRECTION INPUT ;
    USE SIGNAL ;
    PORT
      LAYER M4 ;
        RECT  86.208 87.84 86.4 87.864 ;
    END
  END di0[510]
  PIN di0[511]
    DIRECTION INPUT ;
    USE SIGNAL ;
    PORT
      LAYER M4 ;
        RECT  86.208 87.984 86.4 88.008 ;
    END
  END di0[511]
  PIN di0[512]
    DIRECTION INPUT ;
    USE SIGNAL ;
    PORT
      LAYER M4 ;
        RECT  86.208 88.176 86.4 88.2 ;
    END
  END di0[512]
  PIN di0[513]
    DIRECTION INPUT ;
    USE SIGNAL ;
    PORT
      LAYER M4 ;
        RECT  86.208 88.32 86.4 88.344 ;
    END
  END di0[513]
  PIN di0[51]
    DIRECTION INPUT ;
    USE SIGNAL ;
    PORT
      LAYER M4 ;
        RECT  86.208 12.768 86.4 12.792 ;
    END
  END di0[51]
  PIN di0[52]
    DIRECTION INPUT ;
    USE SIGNAL ;
    PORT
      LAYER M4 ;
        RECT  86.208 12.912 86.4 12.936 ;
    END
  END di0[52]
  PIN di0[53]
    DIRECTION INPUT ;
    USE SIGNAL ;
    PORT
      LAYER M4 ;
        RECT  86.208 13.104 86.4 13.128 ;
    END
  END di0[53]
  PIN di0[54]
    DIRECTION INPUT ;
    USE SIGNAL ;
    PORT
      LAYER M4 ;
        RECT  86.208 13.248 86.4 13.272 ;
    END
  END di0[54]
  PIN di0[55]
    DIRECTION INPUT ;
    USE SIGNAL ;
    PORT
      LAYER M4 ;
        RECT  86.208 13.392 86.4 13.416 ;
    END
  END di0[55]
  PIN di0[56]
    DIRECTION INPUT ;
    USE SIGNAL ;
    PORT
      LAYER M4 ;
        RECT  86.208 13.584 86.4 13.608 ;
    END
  END di0[56]
  PIN di0[57]
    DIRECTION INPUT ;
    USE SIGNAL ;
    PORT
      LAYER M4 ;
        RECT  86.208 13.728 86.4 13.752 ;
    END
  END di0[57]
  PIN di0[58]
    DIRECTION INPUT ;
    USE SIGNAL ;
    PORT
      LAYER M4 ;
        RECT  86.208 13.92 86.4 13.944 ;
    END
  END di0[58]
  PIN di0[59]
    DIRECTION INPUT ;
    USE SIGNAL ;
    PORT
      LAYER M4 ;
        RECT  86.208 14.064 86.4 14.088 ;
    END
  END di0[59]
  PIN di0[5]
    DIRECTION INPUT ;
    USE SIGNAL ;
    PORT
      LAYER M4 ;
        RECT  86.208 5.232 86.4 5.256 ;
    END
  END di0[5]
  PIN di0[60]
    DIRECTION INPUT ;
    USE SIGNAL ;
    PORT
      LAYER M4 ;
        RECT  86.208 14.208 86.4 14.232 ;
    END
  END di0[60]
  PIN di0[61]
    DIRECTION INPUT ;
    USE SIGNAL ;
    PORT
      LAYER M4 ;
        RECT  86.208 14.4 86.4 14.424 ;
    END
  END di0[61]
  PIN di0[62]
    DIRECTION INPUT ;
    USE SIGNAL ;
    PORT
      LAYER M4 ;
        RECT  86.208 14.544 86.4 14.568 ;
    END
  END di0[62]
  PIN di0[63]
    DIRECTION INPUT ;
    USE SIGNAL ;
    PORT
      LAYER M4 ;
        RECT  86.208 14.736 86.4 14.76 ;
    END
  END di0[63]
  PIN di0[64]
    DIRECTION INPUT ;
    USE SIGNAL ;
    PORT
      LAYER M4 ;
        RECT  86.208 14.88 86.4 14.904 ;
    END
  END di0[64]
  PIN di0[65]
    DIRECTION INPUT ;
    USE SIGNAL ;
    PORT
      LAYER M4 ;
        RECT  86.208 15.024 86.4 15.048 ;
    END
  END di0[65]
  PIN di0[66]
    DIRECTION INPUT ;
    USE SIGNAL ;
    PORT
      LAYER M4 ;
        RECT  86.208 15.216 86.4 15.24 ;
    END
  END di0[66]
  PIN di0[67]
    DIRECTION INPUT ;
    USE SIGNAL ;
    PORT
      LAYER M4 ;
        RECT  86.208 15.36 86.4 15.384 ;
    END
  END di0[67]
  PIN di0[68]
    DIRECTION INPUT ;
    USE SIGNAL ;
    PORT
      LAYER M4 ;
        RECT  86.208 15.552 86.4 15.576 ;
    END
  END di0[68]
  PIN di0[69]
    DIRECTION INPUT ;
    USE SIGNAL ;
    PORT
      LAYER M4 ;
        RECT  86.208 15.696 86.4 15.72 ;
    END
  END di0[69]
  PIN di0[6]
    DIRECTION INPUT ;
    USE SIGNAL ;
    PORT
      LAYER M4 ;
        RECT  86.208 5.376 86.4 5.4 ;
    END
  END di0[6]
  PIN di0[70]
    DIRECTION INPUT ;
    USE SIGNAL ;
    PORT
      LAYER M4 ;
        RECT  86.208 15.84 86.4 15.864 ;
    END
  END di0[70]
  PIN di0[71]
    DIRECTION INPUT ;
    USE SIGNAL ;
    PORT
      LAYER M4 ;
        RECT  86.208 16.032 86.4 16.056 ;
    END
  END di0[71]
  PIN di0[72]
    DIRECTION INPUT ;
    USE SIGNAL ;
    PORT
      LAYER M4 ;
        RECT  86.208 16.176 86.4 16.2 ;
    END
  END di0[72]
  PIN di0[73]
    DIRECTION INPUT ;
    USE SIGNAL ;
    PORT
      LAYER M4 ;
        RECT  86.208 16.368 86.4 16.392 ;
    END
  END di0[73]
  PIN di0[74]
    DIRECTION INPUT ;
    USE SIGNAL ;
    PORT
      LAYER M4 ;
        RECT  86.208 16.512 86.4 16.536 ;
    END
  END di0[74]
  PIN di0[75]
    DIRECTION INPUT ;
    USE SIGNAL ;
    PORT
      LAYER M4 ;
        RECT  86.208 16.704 86.4 16.728 ;
    END
  END di0[75]
  PIN di0[76]
    DIRECTION INPUT ;
    USE SIGNAL ;
    PORT
      LAYER M4 ;
        RECT  86.208 16.848 86.4 16.872 ;
    END
  END di0[76]
  PIN di0[77]
    DIRECTION INPUT ;
    USE SIGNAL ;
    PORT
      LAYER M4 ;
        RECT  86.208 16.992 86.4 17.016 ;
    END
  END di0[77]
  PIN di0[78]
    DIRECTION INPUT ;
    USE SIGNAL ;
    PORT
      LAYER M4 ;
        RECT  86.208 17.184 86.4 17.208 ;
    END
  END di0[78]
  PIN di0[79]
    DIRECTION INPUT ;
    USE SIGNAL ;
    PORT
      LAYER M4 ;
        RECT  86.208 17.328 86.4 17.352 ;
    END
  END di0[79]
  PIN di0[7]
    DIRECTION INPUT ;
    USE SIGNAL ;
    PORT
      LAYER M4 ;
        RECT  86.208 5.568 86.4 5.592 ;
    END
  END di0[7]
  PIN di0[80]
    DIRECTION INPUT ;
    USE SIGNAL ;
    PORT
      LAYER M4 ;
        RECT  86.208 17.52 86.4 17.544 ;
    END
  END di0[80]
  PIN di0[81]
    DIRECTION INPUT ;
    USE SIGNAL ;
    PORT
      LAYER M4 ;
        RECT  86.208 17.664 86.4 17.688 ;
    END
  END di0[81]
  PIN di0[82]
    DIRECTION INPUT ;
    USE SIGNAL ;
    PORT
      LAYER M4 ;
        RECT  86.208 17.808 86.4 17.832 ;
    END
  END di0[82]
  PIN di0[83]
    DIRECTION INPUT ;
    USE SIGNAL ;
    PORT
      LAYER M4 ;
        RECT  86.208 18 86.4 18.024 ;
    END
  END di0[83]
  PIN di0[84]
    DIRECTION INPUT ;
    USE SIGNAL ;
    PORT
      LAYER M4 ;
        RECT  86.208 18.144 86.4 18.168 ;
    END
  END di0[84]
  PIN di0[85]
    DIRECTION INPUT ;
    USE SIGNAL ;
    PORT
      LAYER M4 ;
        RECT  86.208 18.336 86.4 18.36 ;
    END
  END di0[85]
  PIN di0[86]
    DIRECTION INPUT ;
    USE SIGNAL ;
    PORT
      LAYER M4 ;
        RECT  86.208 18.48 86.4 18.504 ;
    END
  END di0[86]
  PIN di0[87]
    DIRECTION INPUT ;
    USE SIGNAL ;
    PORT
      LAYER M4 ;
        RECT  86.208 18.624 86.4 18.648 ;
    END
  END di0[87]
  PIN di0[88]
    DIRECTION INPUT ;
    USE SIGNAL ;
    PORT
      LAYER M4 ;
        RECT  86.208 18.816 86.4 18.84 ;
    END
  END di0[88]
  PIN di0[89]
    DIRECTION INPUT ;
    USE SIGNAL ;
    PORT
      LAYER M4 ;
        RECT  86.208 18.96 86.4 18.984 ;
    END
  END di0[89]
  PIN di0[8]
    DIRECTION INPUT ;
    USE SIGNAL ;
    PORT
      LAYER M4 ;
        RECT  86.208 5.712 86.4 5.736 ;
    END
  END di0[8]
  PIN di0[90]
    DIRECTION INPUT ;
    USE SIGNAL ;
    PORT
      LAYER M4 ;
        RECT  86.208 19.152 86.4 19.176 ;
    END
  END di0[90]
  PIN di0[91]
    DIRECTION INPUT ;
    USE SIGNAL ;
    PORT
      LAYER M4 ;
        RECT  86.208 19.296 86.4 19.32 ;
    END
  END di0[91]
  PIN di0[92]
    DIRECTION INPUT ;
    USE SIGNAL ;
    PORT
      LAYER M4 ;
        RECT  86.208 19.44 86.4 19.464 ;
    END
  END di0[92]
  PIN di0[93]
    DIRECTION INPUT ;
    USE SIGNAL ;
    PORT
      LAYER M4 ;
        RECT  86.208 19.632 86.4 19.656 ;
    END
  END di0[93]
  PIN di0[94]
    DIRECTION INPUT ;
    USE SIGNAL ;
    PORT
      LAYER M4 ;
        RECT  86.208 19.776 86.4 19.8 ;
    END
  END di0[94]
  PIN di0[95]
    DIRECTION INPUT ;
    USE SIGNAL ;
    PORT
      LAYER M4 ;
        RECT  86.208 19.968 86.4 19.992 ;
    END
  END di0[95]
  PIN di0[96]
    DIRECTION INPUT ;
    USE SIGNAL ;
    PORT
      LAYER M4 ;
        RECT  86.208 20.112 86.4 20.136 ;
    END
  END di0[96]
  PIN di0[97]
    DIRECTION INPUT ;
    USE SIGNAL ;
    PORT
      LAYER M4 ;
        RECT  86.208 20.304 86.4 20.328 ;
    END
  END di0[97]
  PIN di0[98]
    DIRECTION INPUT ;
    USE SIGNAL ;
    PORT
      LAYER M4 ;
        RECT  86.208 20.448 86.4 20.472 ;
    END
  END di0[98]
  PIN di0[99]
    DIRECTION INPUT ;
    USE SIGNAL ;
    PORT
      LAYER M4 ;
        RECT  86.208 20.592 86.4 20.616 ;
    END
  END di0[99]
  PIN di0[9]
    DIRECTION INPUT ;
    USE SIGNAL ;
    PORT
      LAYER M4 ;
        RECT  86.208 5.904 86.4 5.928 ;
    END
  END di0[9]
  PIN fi0[0]
    DIRECTION INPUT ;
    USE SIGNAL ;
    PORT
      LAYER M4 ;
        RECT  86.208 88.512 86.4 88.536 ;
    END
  END fi0[0]
  PIN o[0]
    DIRECTION OUTPUT ;
    USE SIGNAL ;
    PORT
      LAYER M4 ;
        RECT  0 4.416 0.192 4.44 ;
    END
  END o[0]
  PIN o[100]
    DIRECTION OUTPUT ;
    USE SIGNAL ;
    PORT
      LAYER M4 ;
        RECT  0 20.784 0.192 20.808 ;
    END
  END o[100]
  PIN o[101]
    DIRECTION OUTPUT ;
    USE SIGNAL ;
    PORT
      LAYER M4 ;
        RECT  0 20.928 0.192 20.952 ;
    END
  END o[101]
  PIN o[102]
    DIRECTION OUTPUT ;
    USE SIGNAL ;
    PORT
      LAYER M4 ;
        RECT  0 21.12 0.192 21.144 ;
    END
  END o[102]
  PIN o[103]
    DIRECTION OUTPUT ;
    USE SIGNAL ;
    PORT
      LAYER M4 ;
        RECT  0 21.264 0.192 21.288 ;
    END
  END o[103]
  PIN o[104]
    DIRECTION OUTPUT ;
    USE SIGNAL ;
    PORT
      LAYER M4 ;
        RECT  0 21.408 0.192 21.432 ;
    END
  END o[104]
  PIN o[105]
    DIRECTION OUTPUT ;
    USE SIGNAL ;
    PORT
      LAYER M4 ;
        RECT  0 21.6 0.192 21.624 ;
    END
  END o[105]
  PIN o[106]
    DIRECTION OUTPUT ;
    USE SIGNAL ;
    PORT
      LAYER M4 ;
        RECT  0 21.744 0.192 21.768 ;
    END
  END o[106]
  PIN o[107]
    DIRECTION OUTPUT ;
    USE SIGNAL ;
    PORT
      LAYER M4 ;
        RECT  0 21.936 0.192 21.96 ;
    END
  END o[107]
  PIN o[108]
    DIRECTION OUTPUT ;
    USE SIGNAL ;
    PORT
      LAYER M4 ;
        RECT  0 22.08 0.192 22.104 ;
    END
  END o[108]
  PIN o[109]
    DIRECTION OUTPUT ;
    USE SIGNAL ;
    PORT
      LAYER M4 ;
        RECT  0 22.224 0.192 22.248 ;
    END
  END o[109]
  PIN o[10]
    DIRECTION OUTPUT ;
    USE SIGNAL ;
    PORT
      LAYER M4 ;
        RECT  0 6.048 0.192 6.072 ;
    END
  END o[10]
  PIN o[110]
    DIRECTION OUTPUT ;
    USE SIGNAL ;
    PORT
      LAYER M4 ;
        RECT  0 22.416 0.192 22.44 ;
    END
  END o[110]
  PIN o[111]
    DIRECTION OUTPUT ;
    USE SIGNAL ;
    PORT
      LAYER M4 ;
        RECT  0 22.56 0.192 22.584 ;
    END
  END o[111]
  PIN o[112]
    DIRECTION OUTPUT ;
    USE SIGNAL ;
    PORT
      LAYER M4 ;
        RECT  0 22.752 0.192 22.776 ;
    END
  END o[112]
  PIN o[113]
    DIRECTION OUTPUT ;
    USE SIGNAL ;
    PORT
      LAYER M4 ;
        RECT  0 22.896 0.192 22.92 ;
    END
  END o[113]
  PIN o[114]
    DIRECTION OUTPUT ;
    USE SIGNAL ;
    PORT
      LAYER M4 ;
        RECT  0 23.04 0.192 23.064 ;
    END
  END o[114]
  PIN o[115]
    DIRECTION OUTPUT ;
    USE SIGNAL ;
    PORT
      LAYER M4 ;
        RECT  0 23.232 0.192 23.256 ;
    END
  END o[115]
  PIN o[116]
    DIRECTION OUTPUT ;
    USE SIGNAL ;
    PORT
      LAYER M4 ;
        RECT  0 23.376 0.192 23.4 ;
    END
  END o[116]
  PIN o[117]
    DIRECTION OUTPUT ;
    USE SIGNAL ;
    PORT
      LAYER M4 ;
        RECT  0 23.568 0.192 23.592 ;
    END
  END o[117]
  PIN o[118]
    DIRECTION OUTPUT ;
    USE SIGNAL ;
    PORT
      LAYER M4 ;
        RECT  0 23.712 0.192 23.736 ;
    END
  END o[118]
  PIN o[119]
    DIRECTION OUTPUT ;
    USE SIGNAL ;
    PORT
      LAYER M4 ;
        RECT  0 23.856 0.192 23.88 ;
    END
  END o[119]
  PIN o[11]
    DIRECTION OUTPUT ;
    USE SIGNAL ;
    PORT
      LAYER M4 ;
        RECT  0 6.192 0.192 6.216 ;
    END
  END o[11]
  PIN o[120]
    DIRECTION OUTPUT ;
    USE SIGNAL ;
    PORT
      LAYER M4 ;
        RECT  0 24.048 0.192 24.072 ;
    END
  END o[120]
  PIN o[121]
    DIRECTION OUTPUT ;
    USE SIGNAL ;
    PORT
      LAYER M4 ;
        RECT  0 24.192 0.192 24.216 ;
    END
  END o[121]
  PIN o[122]
    DIRECTION OUTPUT ;
    USE SIGNAL ;
    PORT
      LAYER M4 ;
        RECT  0 24.384 0.192 24.408 ;
    END
  END o[122]
  PIN o[123]
    DIRECTION OUTPUT ;
    USE SIGNAL ;
    PORT
      LAYER M4 ;
        RECT  0 24.528 0.192 24.552 ;
    END
  END o[123]
  PIN o[124]
    DIRECTION OUTPUT ;
    USE SIGNAL ;
    PORT
      LAYER M4 ;
        RECT  0 24.72 0.192 24.744 ;
    END
  END o[124]
  PIN o[125]
    DIRECTION OUTPUT ;
    USE SIGNAL ;
    PORT
      LAYER M4 ;
        RECT  0 24.864 0.192 24.888 ;
    END
  END o[125]
  PIN o[126]
    DIRECTION OUTPUT ;
    USE SIGNAL ;
    PORT
      LAYER M4 ;
        RECT  0 25.008 0.192 25.032 ;
    END
  END o[126]
  PIN o[127]
    DIRECTION OUTPUT ;
    USE SIGNAL ;
    PORT
      LAYER M4 ;
        RECT  0 25.2 0.192 25.224 ;
    END
  END o[127]
  PIN o[128]
    DIRECTION OUTPUT ;
    USE SIGNAL ;
    PORT
      LAYER M4 ;
        RECT  0 25.344 0.192 25.368 ;
    END
  END o[128]
  PIN o[129]
    DIRECTION OUTPUT ;
    USE SIGNAL ;
    PORT
      LAYER M4 ;
        RECT  0 25.536 0.192 25.56 ;
    END
  END o[129]
  PIN o[12]
    DIRECTION OUTPUT ;
    USE SIGNAL ;
    PORT
      LAYER M4 ;
        RECT  0 6.384 0.192 6.408 ;
    END
  END o[12]
  PIN o[130]
    DIRECTION OUTPUT ;
    USE SIGNAL ;
    PORT
      LAYER M4 ;
        RECT  0 25.68 0.192 25.704 ;
    END
  END o[130]
  PIN o[131]
    DIRECTION OUTPUT ;
    USE SIGNAL ;
    PORT
      LAYER M4 ;
        RECT  0 25.824 0.192 25.848 ;
    END
  END o[131]
  PIN o[132]
    DIRECTION OUTPUT ;
    USE SIGNAL ;
    PORT
      LAYER M4 ;
        RECT  0 26.016 0.192 26.04 ;
    END
  END o[132]
  PIN o[133]
    DIRECTION OUTPUT ;
    USE SIGNAL ;
    PORT
      LAYER M4 ;
        RECT  0 26.16 0.192 26.184 ;
    END
  END o[133]
  PIN o[134]
    DIRECTION OUTPUT ;
    USE SIGNAL ;
    PORT
      LAYER M4 ;
        RECT  0 26.352 0.192 26.376 ;
    END
  END o[134]
  PIN o[135]
    DIRECTION OUTPUT ;
    USE SIGNAL ;
    PORT
      LAYER M4 ;
        RECT  0 26.496 0.192 26.52 ;
    END
  END o[135]
  PIN o[136]
    DIRECTION OUTPUT ;
    USE SIGNAL ;
    PORT
      LAYER M4 ;
        RECT  0 26.64 0.192 26.664 ;
    END
  END o[136]
  PIN o[137]
    DIRECTION OUTPUT ;
    USE SIGNAL ;
    PORT
      LAYER M4 ;
        RECT  0 26.832 0.192 26.856 ;
    END
  END o[137]
  PIN o[138]
    DIRECTION OUTPUT ;
    USE SIGNAL ;
    PORT
      LAYER M4 ;
        RECT  0 26.976 0.192 27 ;
    END
  END o[138]
  PIN o[139]
    DIRECTION OUTPUT ;
    USE SIGNAL ;
    PORT
      LAYER M4 ;
        RECT  0 27.168 0.192 27.192 ;
    END
  END o[139]
  PIN o[13]
    DIRECTION OUTPUT ;
    USE SIGNAL ;
    PORT
      LAYER M4 ;
        RECT  0 6.528 0.192 6.552 ;
    END
  END o[13]
  PIN o[140]
    DIRECTION OUTPUT ;
    USE SIGNAL ;
    PORT
      LAYER M4 ;
        RECT  0 27.312 0.192 27.336 ;
    END
  END o[140]
  PIN o[141]
    DIRECTION OUTPUT ;
    USE SIGNAL ;
    PORT
      LAYER M4 ;
        RECT  0 27.456 0.192 27.48 ;
    END
  END o[141]
  PIN o[142]
    DIRECTION OUTPUT ;
    USE SIGNAL ;
    PORT
      LAYER M4 ;
        RECT  0 27.648 0.192 27.672 ;
    END
  END o[142]
  PIN o[143]
    DIRECTION OUTPUT ;
    USE SIGNAL ;
    PORT
      LAYER M4 ;
        RECT  0 27.792 0.192 27.816 ;
    END
  END o[143]
  PIN o[144]
    DIRECTION OUTPUT ;
    USE SIGNAL ;
    PORT
      LAYER M4 ;
        RECT  0 27.984 0.192 28.008 ;
    END
  END o[144]
  PIN o[145]
    DIRECTION OUTPUT ;
    USE SIGNAL ;
    PORT
      LAYER M4 ;
        RECT  0 28.128 0.192 28.152 ;
    END
  END o[145]
  PIN o[146]
    DIRECTION OUTPUT ;
    USE SIGNAL ;
    PORT
      LAYER M4 ;
        RECT  0 28.272 0.192 28.296 ;
    END
  END o[146]
  PIN o[147]
    DIRECTION OUTPUT ;
    USE SIGNAL ;
    PORT
      LAYER M4 ;
        RECT  0 28.464 0.192 28.488 ;
    END
  END o[147]
  PIN o[148]
    DIRECTION OUTPUT ;
    USE SIGNAL ;
    PORT
      LAYER M4 ;
        RECT  0 28.608 0.192 28.632 ;
    END
  END o[148]
  PIN o[149]
    DIRECTION OUTPUT ;
    USE SIGNAL ;
    PORT
      LAYER M4 ;
        RECT  0 28.8 0.192 28.824 ;
    END
  END o[149]
  PIN o[14]
    DIRECTION OUTPUT ;
    USE SIGNAL ;
    PORT
      LAYER M4 ;
        RECT  0 6.72 0.192 6.744 ;
    END
  END o[14]
  PIN o[150]
    DIRECTION OUTPUT ;
    USE SIGNAL ;
    PORT
      LAYER M4 ;
        RECT  0 28.944 0.192 28.968 ;
    END
  END o[150]
  PIN o[151]
    DIRECTION OUTPUT ;
    USE SIGNAL ;
    PORT
      LAYER M4 ;
        RECT  0 29.136 0.192 29.16 ;
    END
  END o[151]
  PIN o[152]
    DIRECTION OUTPUT ;
    USE SIGNAL ;
    PORT
      LAYER M4 ;
        RECT  0 29.28 0.192 29.304 ;
    END
  END o[152]
  PIN o[153]
    DIRECTION OUTPUT ;
    USE SIGNAL ;
    PORT
      LAYER M4 ;
        RECT  0 29.424 0.192 29.448 ;
    END
  END o[153]
  PIN o[154]
    DIRECTION OUTPUT ;
    USE SIGNAL ;
    PORT
      LAYER M4 ;
        RECT  0 29.616 0.192 29.64 ;
    END
  END o[154]
  PIN o[155]
    DIRECTION OUTPUT ;
    USE SIGNAL ;
    PORT
      LAYER M4 ;
        RECT  0 29.76 0.192 29.784 ;
    END
  END o[155]
  PIN o[156]
    DIRECTION OUTPUT ;
    USE SIGNAL ;
    PORT
      LAYER M4 ;
        RECT  0 29.952 0.192 29.976 ;
    END
  END o[156]
  PIN o[157]
    DIRECTION OUTPUT ;
    USE SIGNAL ;
    PORT
      LAYER M4 ;
        RECT  0 30.096 0.192 30.12 ;
    END
  END o[157]
  PIN o[158]
    DIRECTION OUTPUT ;
    USE SIGNAL ;
    PORT
      LAYER M4 ;
        RECT  0 30.24 0.192 30.264 ;
    END
  END o[158]
  PIN o[159]
    DIRECTION OUTPUT ;
    USE SIGNAL ;
    PORT
      LAYER M4 ;
        RECT  0 30.432 0.192 30.456 ;
    END
  END o[159]
  PIN o[15]
    DIRECTION OUTPUT ;
    USE SIGNAL ;
    PORT
      LAYER M4 ;
        RECT  0 6.864 0.192 6.888 ;
    END
  END o[15]
  PIN o[160]
    DIRECTION OUTPUT ;
    USE SIGNAL ;
    PORT
      LAYER M4 ;
        RECT  0 30.576 0.192 30.6 ;
    END
  END o[160]
  PIN o[161]
    DIRECTION OUTPUT ;
    USE SIGNAL ;
    PORT
      LAYER M4 ;
        RECT  0 30.768 0.192 30.792 ;
    END
  END o[161]
  PIN o[162]
    DIRECTION OUTPUT ;
    USE SIGNAL ;
    PORT
      LAYER M4 ;
        RECT  0 30.912 0.192 30.936 ;
    END
  END o[162]
  PIN o[163]
    DIRECTION OUTPUT ;
    USE SIGNAL ;
    PORT
      LAYER M4 ;
        RECT  0 31.056 0.192 31.08 ;
    END
  END o[163]
  PIN o[164]
    DIRECTION OUTPUT ;
    USE SIGNAL ;
    PORT
      LAYER M4 ;
        RECT  0 31.248 0.192 31.272 ;
    END
  END o[164]
  PIN o[165]
    DIRECTION OUTPUT ;
    USE SIGNAL ;
    PORT
      LAYER M4 ;
        RECT  0 31.392 0.192 31.416 ;
    END
  END o[165]
  PIN o[166]
    DIRECTION OUTPUT ;
    USE SIGNAL ;
    PORT
      LAYER M4 ;
        RECT  0 31.584 0.192 31.608 ;
    END
  END o[166]
  PIN o[167]
    DIRECTION OUTPUT ;
    USE SIGNAL ;
    PORT
      LAYER M4 ;
        RECT  0 31.728 0.192 31.752 ;
    END
  END o[167]
  PIN o[168]
    DIRECTION OUTPUT ;
    USE SIGNAL ;
    PORT
      LAYER M4 ;
        RECT  0 31.872 0.192 31.896 ;
    END
  END o[168]
  PIN o[169]
    DIRECTION OUTPUT ;
    USE SIGNAL ;
    PORT
      LAYER M4 ;
        RECT  0 32.064 0.192 32.088 ;
    END
  END o[169]
  PIN o[16]
    DIRECTION OUTPUT ;
    USE SIGNAL ;
    PORT
      LAYER M4 ;
        RECT  0 7.008 0.192 7.032 ;
    END
  END o[16]
  PIN o[170]
    DIRECTION OUTPUT ;
    USE SIGNAL ;
    PORT
      LAYER M4 ;
        RECT  0 32.208 0.192 32.232 ;
    END
  END o[170]
  PIN o[171]
    DIRECTION OUTPUT ;
    USE SIGNAL ;
    PORT
      LAYER M4 ;
        RECT  0 32.4 0.192 32.424 ;
    END
  END o[171]
  PIN o[172]
    DIRECTION OUTPUT ;
    USE SIGNAL ;
    PORT
      LAYER M4 ;
        RECT  0 32.544 0.192 32.568 ;
    END
  END o[172]
  PIN o[173]
    DIRECTION OUTPUT ;
    USE SIGNAL ;
    PORT
      LAYER M4 ;
        RECT  0 32.688 0.192 32.712 ;
    END
  END o[173]
  PIN o[174]
    DIRECTION OUTPUT ;
    USE SIGNAL ;
    PORT
      LAYER M4 ;
        RECT  0 32.88 0.192 32.904 ;
    END
  END o[174]
  PIN o[175]
    DIRECTION OUTPUT ;
    USE SIGNAL ;
    PORT
      LAYER M4 ;
        RECT  0 33.024 0.192 33.048 ;
    END
  END o[175]
  PIN o[176]
    DIRECTION OUTPUT ;
    USE SIGNAL ;
    PORT
      LAYER M4 ;
        RECT  0 33.216 0.192 33.24 ;
    END
  END o[176]
  PIN o[177]
    DIRECTION OUTPUT ;
    USE SIGNAL ;
    PORT
      LAYER M4 ;
        RECT  0 33.36 0.192 33.384 ;
    END
  END o[177]
  PIN o[178]
    DIRECTION OUTPUT ;
    USE SIGNAL ;
    PORT
      LAYER M4 ;
        RECT  0 33.552 0.192 33.576 ;
    END
  END o[178]
  PIN o[179]
    DIRECTION OUTPUT ;
    USE SIGNAL ;
    PORT
      LAYER M4 ;
        RECT  0 33.696 0.192 33.72 ;
    END
  END o[179]
  PIN o[17]
    DIRECTION OUTPUT ;
    USE SIGNAL ;
    PORT
      LAYER M4 ;
        RECT  0 7.2 0.192 7.224 ;
    END
  END o[17]
  PIN o[180]
    DIRECTION OUTPUT ;
    USE SIGNAL ;
    PORT
      LAYER M4 ;
        RECT  0 33.84 0.192 33.864 ;
    END
  END o[180]
  PIN o[181]
    DIRECTION OUTPUT ;
    USE SIGNAL ;
    PORT
      LAYER M4 ;
        RECT  0 34.032 0.192 34.056 ;
    END
  END o[181]
  PIN o[182]
    DIRECTION OUTPUT ;
    USE SIGNAL ;
    PORT
      LAYER M4 ;
        RECT  0 34.176 0.192 34.2 ;
    END
  END o[182]
  PIN o[183]
    DIRECTION OUTPUT ;
    USE SIGNAL ;
    PORT
      LAYER M4 ;
        RECT  0 34.368 0.192 34.392 ;
    END
  END o[183]
  PIN o[184]
    DIRECTION OUTPUT ;
    USE SIGNAL ;
    PORT
      LAYER M4 ;
        RECT  0 34.512 0.192 34.536 ;
    END
  END o[184]
  PIN o[185]
    DIRECTION OUTPUT ;
    USE SIGNAL ;
    PORT
      LAYER M4 ;
        RECT  0 34.656 0.192 34.68 ;
    END
  END o[185]
  PIN o[186]
    DIRECTION OUTPUT ;
    USE SIGNAL ;
    PORT
      LAYER M4 ;
        RECT  0 34.848 0.192 34.872 ;
    END
  END o[186]
  PIN o[187]
    DIRECTION OUTPUT ;
    USE SIGNAL ;
    PORT
      LAYER M4 ;
        RECT  0 34.992 0.192 35.016 ;
    END
  END o[187]
  PIN o[188]
    DIRECTION OUTPUT ;
    USE SIGNAL ;
    PORT
      LAYER M4 ;
        RECT  0 35.184 0.192 35.208 ;
    END
  END o[188]
  PIN o[189]
    DIRECTION OUTPUT ;
    USE SIGNAL ;
    PORT
      LAYER M4 ;
        RECT  0 35.328 0.192 35.352 ;
    END
  END o[189]
  PIN o[18]
    DIRECTION OUTPUT ;
    USE SIGNAL ;
    PORT
      LAYER M4 ;
        RECT  0 7.344 0.192 7.368 ;
    END
  END o[18]
  PIN o[190]
    DIRECTION OUTPUT ;
    USE SIGNAL ;
    PORT
      LAYER M4 ;
        RECT  0 35.472 0.192 35.496 ;
    END
  END o[190]
  PIN o[191]
    DIRECTION OUTPUT ;
    USE SIGNAL ;
    PORT
      LAYER M4 ;
        RECT  0 35.664 0.192 35.688 ;
    END
  END o[191]
  PIN o[192]
    DIRECTION OUTPUT ;
    USE SIGNAL ;
    PORT
      LAYER M4 ;
        RECT  0 35.808 0.192 35.832 ;
    END
  END o[192]
  PIN o[193]
    DIRECTION OUTPUT ;
    USE SIGNAL ;
    PORT
      LAYER M4 ;
        RECT  0 36 0.192 36.024 ;
    END
  END o[193]
  PIN o[194]
    DIRECTION OUTPUT ;
    USE SIGNAL ;
    PORT
      LAYER M4 ;
        RECT  0 36.144 0.192 36.168 ;
    END
  END o[194]
  PIN o[195]
    DIRECTION OUTPUT ;
    USE SIGNAL ;
    PORT
      LAYER M4 ;
        RECT  0 36.288 0.192 36.312 ;
    END
  END o[195]
  PIN o[196]
    DIRECTION OUTPUT ;
    USE SIGNAL ;
    PORT
      LAYER M4 ;
        RECT  0 36.48 0.192 36.504 ;
    END
  END o[196]
  PIN o[197]
    DIRECTION OUTPUT ;
    USE SIGNAL ;
    PORT
      LAYER M4 ;
        RECT  0 36.624 0.192 36.648 ;
    END
  END o[197]
  PIN o[198]
    DIRECTION OUTPUT ;
    USE SIGNAL ;
    PORT
      LAYER M4 ;
        RECT  0 36.816 0.192 36.84 ;
    END
  END o[198]
  PIN o[199]
    DIRECTION OUTPUT ;
    USE SIGNAL ;
    PORT
      LAYER M4 ;
        RECT  0 36.96 0.192 36.984 ;
    END
  END o[199]
  PIN o[19]
    DIRECTION OUTPUT ;
    USE SIGNAL ;
    PORT
      LAYER M4 ;
        RECT  0 7.536 0.192 7.56 ;
    END
  END o[19]
  PIN o[1]
    DIRECTION OUTPUT ;
    USE SIGNAL ;
    PORT
      LAYER M4 ;
        RECT  0 4.56 0.192 4.584 ;
    END
  END o[1]
  PIN o[200]
    DIRECTION OUTPUT ;
    USE SIGNAL ;
    PORT
      LAYER M4 ;
        RECT  0 37.152 0.192 37.176 ;
    END
  END o[200]
  PIN o[201]
    DIRECTION OUTPUT ;
    USE SIGNAL ;
    PORT
      LAYER M4 ;
        RECT  0 37.296 0.192 37.32 ;
    END
  END o[201]
  PIN o[202]
    DIRECTION OUTPUT ;
    USE SIGNAL ;
    PORT
      LAYER M4 ;
        RECT  0 37.44 0.192 37.464 ;
    END
  END o[202]
  PIN o[203]
    DIRECTION OUTPUT ;
    USE SIGNAL ;
    PORT
      LAYER M4 ;
        RECT  0 37.632 0.192 37.656 ;
    END
  END o[203]
  PIN o[204]
    DIRECTION OUTPUT ;
    USE SIGNAL ;
    PORT
      LAYER M4 ;
        RECT  0 37.776 0.192 37.8 ;
    END
  END o[204]
  PIN o[205]
    DIRECTION OUTPUT ;
    USE SIGNAL ;
    PORT
      LAYER M4 ;
        RECT  0 37.968 0.192 37.992 ;
    END
  END o[205]
  PIN o[206]
    DIRECTION OUTPUT ;
    USE SIGNAL ;
    PORT
      LAYER M4 ;
        RECT  0 38.112 0.192 38.136 ;
    END
  END o[206]
  PIN o[207]
    DIRECTION OUTPUT ;
    USE SIGNAL ;
    PORT
      LAYER M4 ;
        RECT  0 38.256 0.192 38.28 ;
    END
  END o[207]
  PIN o[208]
    DIRECTION OUTPUT ;
    USE SIGNAL ;
    PORT
      LAYER M4 ;
        RECT  0 38.448 0.192 38.472 ;
    END
  END o[208]
  PIN o[209]
    DIRECTION OUTPUT ;
    USE SIGNAL ;
    PORT
      LAYER M4 ;
        RECT  0 38.592 0.192 38.616 ;
    END
  END o[209]
  PIN o[20]
    DIRECTION OUTPUT ;
    USE SIGNAL ;
    PORT
      LAYER M4 ;
        RECT  0 7.68 0.192 7.704 ;
    END
  END o[20]
  PIN o[210]
    DIRECTION OUTPUT ;
    USE SIGNAL ;
    PORT
      LAYER M4 ;
        RECT  0 38.784 0.192 38.808 ;
    END
  END o[210]
  PIN o[211]
    DIRECTION OUTPUT ;
    USE SIGNAL ;
    PORT
      LAYER M4 ;
        RECT  0 38.928 0.192 38.952 ;
    END
  END o[211]
  PIN o[212]
    DIRECTION OUTPUT ;
    USE SIGNAL ;
    PORT
      LAYER M4 ;
        RECT  0 39.072 0.192 39.096 ;
    END
  END o[212]
  PIN o[213]
    DIRECTION OUTPUT ;
    USE SIGNAL ;
    PORT
      LAYER M4 ;
        RECT  0 39.264 0.192 39.288 ;
    END
  END o[213]
  PIN o[214]
    DIRECTION OUTPUT ;
    USE SIGNAL ;
    PORT
      LAYER M4 ;
        RECT  0 39.408 0.192 39.432 ;
    END
  END o[214]
  PIN o[215]
    DIRECTION OUTPUT ;
    USE SIGNAL ;
    PORT
      LAYER M4 ;
        RECT  0 39.6 0.192 39.624 ;
    END
  END o[215]
  PIN o[216]
    DIRECTION OUTPUT ;
    USE SIGNAL ;
    PORT
      LAYER M4 ;
        RECT  0 39.744 0.192 39.768 ;
    END
  END o[216]
  PIN o[217]
    DIRECTION OUTPUT ;
    USE SIGNAL ;
    PORT
      LAYER M4 ;
        RECT  0 39.888 0.192 39.912 ;
    END
  END o[217]
  PIN o[218]
    DIRECTION OUTPUT ;
    USE SIGNAL ;
    PORT
      LAYER M4 ;
        RECT  0 40.08 0.192 40.104 ;
    END
  END o[218]
  PIN o[219]
    DIRECTION OUTPUT ;
    USE SIGNAL ;
    PORT
      LAYER M4 ;
        RECT  0 40.224 0.192 40.248 ;
    END
  END o[219]
  PIN o[21]
    DIRECTION OUTPUT ;
    USE SIGNAL ;
    PORT
      LAYER M4 ;
        RECT  0 7.872 0.192 7.896 ;
    END
  END o[21]
  PIN o[220]
    DIRECTION OUTPUT ;
    USE SIGNAL ;
    PORT
      LAYER M4 ;
        RECT  0 40.416 0.192 40.44 ;
    END
  END o[220]
  PIN o[221]
    DIRECTION OUTPUT ;
    USE SIGNAL ;
    PORT
      LAYER M4 ;
        RECT  0 40.56 0.192 40.584 ;
    END
  END o[221]
  PIN o[222]
    DIRECTION OUTPUT ;
    USE SIGNAL ;
    PORT
      LAYER M4 ;
        RECT  0 40.704 0.192 40.728 ;
    END
  END o[222]
  PIN o[223]
    DIRECTION OUTPUT ;
    USE SIGNAL ;
    PORT
      LAYER M4 ;
        RECT  0 40.896 0.192 40.92 ;
    END
  END o[223]
  PIN o[224]
    DIRECTION OUTPUT ;
    USE SIGNAL ;
    PORT
      LAYER M4 ;
        RECT  0 41.04 0.192 41.064 ;
    END
  END o[224]
  PIN o[225]
    DIRECTION OUTPUT ;
    USE SIGNAL ;
    PORT
      LAYER M4 ;
        RECT  0 41.232 0.192 41.256 ;
    END
  END o[225]
  PIN o[226]
    DIRECTION OUTPUT ;
    USE SIGNAL ;
    PORT
      LAYER M4 ;
        RECT  0 41.376 0.192 41.4 ;
    END
  END o[226]
  PIN o[227]
    DIRECTION OUTPUT ;
    USE SIGNAL ;
    PORT
      LAYER M4 ;
        RECT  0 41.568 0.192 41.592 ;
    END
  END o[227]
  PIN o[228]
    DIRECTION OUTPUT ;
    USE SIGNAL ;
    PORT
      LAYER M4 ;
        RECT  0 41.712 0.192 41.736 ;
    END
  END o[228]
  PIN o[229]
    DIRECTION OUTPUT ;
    USE SIGNAL ;
    PORT
      LAYER M4 ;
        RECT  0 41.856 0.192 41.88 ;
    END
  END o[229]
  PIN o[22]
    DIRECTION OUTPUT ;
    USE SIGNAL ;
    PORT
      LAYER M4 ;
        RECT  0 8.016 0.192 8.04 ;
    END
  END o[22]
  PIN o[230]
    DIRECTION OUTPUT ;
    USE SIGNAL ;
    PORT
      LAYER M4 ;
        RECT  0 42.048 0.192 42.072 ;
    END
  END o[230]
  PIN o[231]
    DIRECTION OUTPUT ;
    USE SIGNAL ;
    PORT
      LAYER M4 ;
        RECT  0 42.192 0.192 42.216 ;
    END
  END o[231]
  PIN o[232]
    DIRECTION OUTPUT ;
    USE SIGNAL ;
    PORT
      LAYER M4 ;
        RECT  0 42.384 0.192 42.408 ;
    END
  END o[232]
  PIN o[233]
    DIRECTION OUTPUT ;
    USE SIGNAL ;
    PORT
      LAYER M4 ;
        RECT  0 42.528 0.192 42.552 ;
    END
  END o[233]
  PIN o[234]
    DIRECTION OUTPUT ;
    USE SIGNAL ;
    PORT
      LAYER M4 ;
        RECT  0 42.672 0.192 42.696 ;
    END
  END o[234]
  PIN o[235]
    DIRECTION OUTPUT ;
    USE SIGNAL ;
    PORT
      LAYER M4 ;
        RECT  0 42.864 0.192 42.888 ;
    END
  END o[235]
  PIN o[236]
    DIRECTION OUTPUT ;
    USE SIGNAL ;
    PORT
      LAYER M4 ;
        RECT  0 43.008 0.192 43.032 ;
    END
  END o[236]
  PIN o[237]
    DIRECTION OUTPUT ;
    USE SIGNAL ;
    PORT
      LAYER M4 ;
        RECT  0 43.2 0.192 43.224 ;
    END
  END o[237]
  PIN o[238]
    DIRECTION OUTPUT ;
    USE SIGNAL ;
    PORT
      LAYER M4 ;
        RECT  0 43.344 0.192 43.368 ;
    END
  END o[238]
  PIN o[239]
    DIRECTION OUTPUT ;
    USE SIGNAL ;
    PORT
      LAYER M4 ;
        RECT  0 43.488 0.192 43.512 ;
    END
  END o[239]
  PIN o[23]
    DIRECTION OUTPUT ;
    USE SIGNAL ;
    PORT
      LAYER M4 ;
        RECT  0 8.16 0.192 8.184 ;
    END
  END o[23]
  PIN o[240]
    DIRECTION OUTPUT ;
    USE SIGNAL ;
    PORT
      LAYER M4 ;
        RECT  0 43.68 0.192 43.704 ;
    END
  END o[240]
  PIN o[241]
    DIRECTION OUTPUT ;
    USE SIGNAL ;
    PORT
      LAYER M4 ;
        RECT  0 43.824 0.192 43.848 ;
    END
  END o[241]
  PIN o[242]
    DIRECTION OUTPUT ;
    USE SIGNAL ;
    PORT
      LAYER M4 ;
        RECT  0 44.016 0.192 44.04 ;
    END
  END o[242]
  PIN o[243]
    DIRECTION OUTPUT ;
    USE SIGNAL ;
    PORT
      LAYER M4 ;
        RECT  0 44.16 0.192 44.184 ;
    END
  END o[243]
  PIN o[244]
    DIRECTION OUTPUT ;
    USE SIGNAL ;
    PORT
      LAYER M4 ;
        RECT  0 44.304 0.192 44.328 ;
    END
  END o[244]
  PIN o[245]
    DIRECTION OUTPUT ;
    USE SIGNAL ;
    PORT
      LAYER M4 ;
        RECT  0 44.496 0.192 44.52 ;
    END
  END o[245]
  PIN o[246]
    DIRECTION OUTPUT ;
    USE SIGNAL ;
    PORT
      LAYER M4 ;
        RECT  0 44.64 0.192 44.664 ;
    END
  END o[246]
  PIN o[247]
    DIRECTION OUTPUT ;
    USE SIGNAL ;
    PORT
      LAYER M4 ;
        RECT  0 44.832 0.192 44.856 ;
    END
  END o[247]
  PIN o[248]
    DIRECTION OUTPUT ;
    USE SIGNAL ;
    PORT
      LAYER M4 ;
        RECT  0 44.976 0.192 45 ;
    END
  END o[248]
  PIN o[249]
    DIRECTION OUTPUT ;
    USE SIGNAL ;
    PORT
      LAYER M4 ;
        RECT  0 45.12 0.192 45.144 ;
    END
  END o[249]
  PIN o[24]
    DIRECTION OUTPUT ;
    USE SIGNAL ;
    PORT
      LAYER M4 ;
        RECT  0 8.352 0.192 8.376 ;
    END
  END o[24]
  PIN o[250]
    DIRECTION OUTPUT ;
    USE SIGNAL ;
    PORT
      LAYER M4 ;
        RECT  0 45.312 0.192 45.336 ;
    END
  END o[250]
  PIN o[251]
    DIRECTION OUTPUT ;
    USE SIGNAL ;
    PORT
      LAYER M4 ;
        RECT  0 45.456 0.192 45.48 ;
    END
  END o[251]
  PIN o[252]
    DIRECTION OUTPUT ;
    USE SIGNAL ;
    PORT
      LAYER M4 ;
        RECT  0 45.648 0.192 45.672 ;
    END
  END o[252]
  PIN o[253]
    DIRECTION OUTPUT ;
    USE SIGNAL ;
    PORT
      LAYER M4 ;
        RECT  0 45.792 0.192 45.816 ;
    END
  END o[253]
  PIN o[254]
    DIRECTION OUTPUT ;
    USE SIGNAL ;
    PORT
      LAYER M4 ;
        RECT  0 45.984 0.192 46.008 ;
    END
  END o[254]
  PIN o[255]
    DIRECTION OUTPUT ;
    USE SIGNAL ;
    PORT
      LAYER M4 ;
        RECT  0 46.128 0.192 46.152 ;
    END
  END o[255]
  PIN o[256]
    DIRECTION OUTPUT ;
    USE SIGNAL ;
    PORT
      LAYER M4 ;
        RECT  0 46.272 0.192 46.296 ;
    END
  END o[256]
  PIN o[257]
    DIRECTION OUTPUT ;
    USE SIGNAL ;
    PORT
      LAYER M4 ;
        RECT  0 46.464 0.192 46.488 ;
    END
  END o[257]
  PIN o[258]
    DIRECTION OUTPUT ;
    USE SIGNAL ;
    PORT
      LAYER M4 ;
        RECT  0 46.608 0.192 46.632 ;
    END
  END o[258]
  PIN o[259]
    DIRECTION OUTPUT ;
    USE SIGNAL ;
    PORT
      LAYER M4 ;
        RECT  0 46.8 0.192 46.824 ;
    END
  END o[259]
  PIN o[25]
    DIRECTION OUTPUT ;
    USE SIGNAL ;
    PORT
      LAYER M4 ;
        RECT  0 8.496 0.192 8.52 ;
    END
  END o[25]
  PIN o[260]
    DIRECTION OUTPUT ;
    USE SIGNAL ;
    PORT
      LAYER M4 ;
        RECT  0 46.944 0.192 46.968 ;
    END
  END o[260]
  PIN o[261]
    DIRECTION OUTPUT ;
    USE SIGNAL ;
    PORT
      LAYER M4 ;
        RECT  0 47.088 0.192 47.112 ;
    END
  END o[261]
  PIN o[262]
    DIRECTION OUTPUT ;
    USE SIGNAL ;
    PORT
      LAYER M4 ;
        RECT  0 47.28 0.192 47.304 ;
    END
  END o[262]
  PIN o[263]
    DIRECTION OUTPUT ;
    USE SIGNAL ;
    PORT
      LAYER M4 ;
        RECT  0 47.424 0.192 47.448 ;
    END
  END o[263]
  PIN o[264]
    DIRECTION OUTPUT ;
    USE SIGNAL ;
    PORT
      LAYER M4 ;
        RECT  0 47.616 0.192 47.64 ;
    END
  END o[264]
  PIN o[265]
    DIRECTION OUTPUT ;
    USE SIGNAL ;
    PORT
      LAYER M4 ;
        RECT  0 47.76 0.192 47.784 ;
    END
  END o[265]
  PIN o[266]
    DIRECTION OUTPUT ;
    USE SIGNAL ;
    PORT
      LAYER M4 ;
        RECT  0 47.904 0.192 47.928 ;
    END
  END o[266]
  PIN o[267]
    DIRECTION OUTPUT ;
    USE SIGNAL ;
    PORT
      LAYER M4 ;
        RECT  0 48.096 0.192 48.12 ;
    END
  END o[267]
  PIN o[268]
    DIRECTION OUTPUT ;
    USE SIGNAL ;
    PORT
      LAYER M4 ;
        RECT  0 48.24 0.192 48.264 ;
    END
  END o[268]
  PIN o[269]
    DIRECTION OUTPUT ;
    USE SIGNAL ;
    PORT
      LAYER M4 ;
        RECT  0 48.432 0.192 48.456 ;
    END
  END o[269]
  PIN o[26]
    DIRECTION OUTPUT ;
    USE SIGNAL ;
    PORT
      LAYER M4 ;
        RECT  0 8.688 0.192 8.712 ;
    END
  END o[26]
  PIN o[270]
    DIRECTION OUTPUT ;
    USE SIGNAL ;
    PORT
      LAYER M4 ;
        RECT  0 48.576 0.192 48.6 ;
    END
  END o[270]
  PIN o[271]
    DIRECTION OUTPUT ;
    USE SIGNAL ;
    PORT
      LAYER M4 ;
        RECT  0 48.72 0.192 48.744 ;
    END
  END o[271]
  PIN o[272]
    DIRECTION OUTPUT ;
    USE SIGNAL ;
    PORT
      LAYER M4 ;
        RECT  0 48.912 0.192 48.936 ;
    END
  END o[272]
  PIN o[273]
    DIRECTION OUTPUT ;
    USE SIGNAL ;
    PORT
      LAYER M4 ;
        RECT  0 49.056 0.192 49.08 ;
    END
  END o[273]
  PIN o[274]
    DIRECTION OUTPUT ;
    USE SIGNAL ;
    PORT
      LAYER M4 ;
        RECT  0 49.248 0.192 49.272 ;
    END
  END o[274]
  PIN o[275]
    DIRECTION OUTPUT ;
    USE SIGNAL ;
    PORT
      LAYER M4 ;
        RECT  0 49.392 0.192 49.416 ;
    END
  END o[275]
  PIN o[276]
    DIRECTION OUTPUT ;
    USE SIGNAL ;
    PORT
      LAYER M4 ;
        RECT  0 49.536 0.192 49.56 ;
    END
  END o[276]
  PIN o[277]
    DIRECTION OUTPUT ;
    USE SIGNAL ;
    PORT
      LAYER M4 ;
        RECT  0 49.728 0.192 49.752 ;
    END
  END o[277]
  PIN o[278]
    DIRECTION OUTPUT ;
    USE SIGNAL ;
    PORT
      LAYER M4 ;
        RECT  0 49.872 0.192 49.896 ;
    END
  END o[278]
  PIN o[279]
    DIRECTION OUTPUT ;
    USE SIGNAL ;
    PORT
      LAYER M4 ;
        RECT  0 50.064 0.192 50.088 ;
    END
  END o[279]
  PIN o[27]
    DIRECTION OUTPUT ;
    USE SIGNAL ;
    PORT
      LAYER M4 ;
        RECT  0 8.832 0.192 8.856 ;
    END
  END o[27]
  PIN o[280]
    DIRECTION OUTPUT ;
    USE SIGNAL ;
    PORT
      LAYER M4 ;
        RECT  0 50.208 0.192 50.232 ;
    END
  END o[280]
  PIN o[281]
    DIRECTION OUTPUT ;
    USE SIGNAL ;
    PORT
      LAYER M4 ;
        RECT  0 50.4 0.192 50.424 ;
    END
  END o[281]
  PIN o[282]
    DIRECTION OUTPUT ;
    USE SIGNAL ;
    PORT
      LAYER M4 ;
        RECT  0 50.544 0.192 50.568 ;
    END
  END o[282]
  PIN o[283]
    DIRECTION OUTPUT ;
    USE SIGNAL ;
    PORT
      LAYER M4 ;
        RECT  0 50.688 0.192 50.712 ;
    END
  END o[283]
  PIN o[284]
    DIRECTION OUTPUT ;
    USE SIGNAL ;
    PORT
      LAYER M4 ;
        RECT  0 50.88 0.192 50.904 ;
    END
  END o[284]
  PIN o[285]
    DIRECTION OUTPUT ;
    USE SIGNAL ;
    PORT
      LAYER M4 ;
        RECT  0 51.024 0.192 51.048 ;
    END
  END o[285]
  PIN o[286]
    DIRECTION OUTPUT ;
    USE SIGNAL ;
    PORT
      LAYER M4 ;
        RECT  0 51.216 0.192 51.24 ;
    END
  END o[286]
  PIN o[287]
    DIRECTION OUTPUT ;
    USE SIGNAL ;
    PORT
      LAYER M4 ;
        RECT  0 51.36 0.192 51.384 ;
    END
  END o[287]
  PIN o[288]
    DIRECTION OUTPUT ;
    USE SIGNAL ;
    PORT
      LAYER M4 ;
        RECT  0 51.504 0.192 51.528 ;
    END
  END o[288]
  PIN o[289]
    DIRECTION OUTPUT ;
    USE SIGNAL ;
    PORT
      LAYER M4 ;
        RECT  0 51.696 0.192 51.72 ;
    END
  END o[289]
  PIN o[28]
    DIRECTION OUTPUT ;
    USE SIGNAL ;
    PORT
      LAYER M4 ;
        RECT  0 8.976 0.192 9 ;
    END
  END o[28]
  PIN o[290]
    DIRECTION OUTPUT ;
    USE SIGNAL ;
    PORT
      LAYER M4 ;
        RECT  0 51.84 0.192 51.864 ;
    END
  END o[290]
  PIN o[291]
    DIRECTION OUTPUT ;
    USE SIGNAL ;
    PORT
      LAYER M4 ;
        RECT  0 52.032 0.192 52.056 ;
    END
  END o[291]
  PIN o[292]
    DIRECTION OUTPUT ;
    USE SIGNAL ;
    PORT
      LAYER M4 ;
        RECT  0 52.176 0.192 52.2 ;
    END
  END o[292]
  PIN o[293]
    DIRECTION OUTPUT ;
    USE SIGNAL ;
    PORT
      LAYER M4 ;
        RECT  0 52.32 0.192 52.344 ;
    END
  END o[293]
  PIN o[294]
    DIRECTION OUTPUT ;
    USE SIGNAL ;
    PORT
      LAYER M4 ;
        RECT  0 52.512 0.192 52.536 ;
    END
  END o[294]
  PIN o[295]
    DIRECTION OUTPUT ;
    USE SIGNAL ;
    PORT
      LAYER M4 ;
        RECT  0 52.656 0.192 52.68 ;
    END
  END o[295]
  PIN o[296]
    DIRECTION OUTPUT ;
    USE SIGNAL ;
    PORT
      LAYER M4 ;
        RECT  0 52.848 0.192 52.872 ;
    END
  END o[296]
  PIN o[297]
    DIRECTION OUTPUT ;
    USE SIGNAL ;
    PORT
      LAYER M4 ;
        RECT  0 52.992 0.192 53.016 ;
    END
  END o[297]
  PIN o[298]
    DIRECTION OUTPUT ;
    USE SIGNAL ;
    PORT
      LAYER M4 ;
        RECT  0 53.136 0.192 53.16 ;
    END
  END o[298]
  PIN o[299]
    DIRECTION OUTPUT ;
    USE SIGNAL ;
    PORT
      LAYER M4 ;
        RECT  0 53.328 0.192 53.352 ;
    END
  END o[299]
  PIN o[29]
    DIRECTION OUTPUT ;
    USE SIGNAL ;
    PORT
      LAYER M4 ;
        RECT  0 9.168 0.192 9.192 ;
    END
  END o[29]
  PIN o[2]
    DIRECTION OUTPUT ;
    USE SIGNAL ;
    PORT
      LAYER M4 ;
        RECT  0 4.752 0.192 4.776 ;
    END
  END o[2]
  PIN o[300]
    DIRECTION OUTPUT ;
    USE SIGNAL ;
    PORT
      LAYER M4 ;
        RECT  0 53.472 0.192 53.496 ;
    END
  END o[300]
  PIN o[301]
    DIRECTION OUTPUT ;
    USE SIGNAL ;
    PORT
      LAYER M4 ;
        RECT  0 53.664 0.192 53.688 ;
    END
  END o[301]
  PIN o[302]
    DIRECTION OUTPUT ;
    USE SIGNAL ;
    PORT
      LAYER M4 ;
        RECT  0 53.808 0.192 53.832 ;
    END
  END o[302]
  PIN o[303]
    DIRECTION OUTPUT ;
    USE SIGNAL ;
    PORT
      LAYER M4 ;
        RECT  0 54 0.192 54.024 ;
    END
  END o[303]
  PIN o[304]
    DIRECTION OUTPUT ;
    USE SIGNAL ;
    PORT
      LAYER M4 ;
        RECT  0 54.144 0.192 54.168 ;
    END
  END o[304]
  PIN o[305]
    DIRECTION OUTPUT ;
    USE SIGNAL ;
    PORT
      LAYER M4 ;
        RECT  0 54.288 0.192 54.312 ;
    END
  END o[305]
  PIN o[306]
    DIRECTION OUTPUT ;
    USE SIGNAL ;
    PORT
      LAYER M4 ;
        RECT  0 54.48 0.192 54.504 ;
    END
  END o[306]
  PIN o[307]
    DIRECTION OUTPUT ;
    USE SIGNAL ;
    PORT
      LAYER M4 ;
        RECT  0 54.624 0.192 54.648 ;
    END
  END o[307]
  PIN o[308]
    DIRECTION OUTPUT ;
    USE SIGNAL ;
    PORT
      LAYER M4 ;
        RECT  0 54.816 0.192 54.84 ;
    END
  END o[308]
  PIN o[309]
    DIRECTION OUTPUT ;
    USE SIGNAL ;
    PORT
      LAYER M4 ;
        RECT  0 54.96 0.192 54.984 ;
    END
  END o[309]
  PIN o[30]
    DIRECTION OUTPUT ;
    USE SIGNAL ;
    PORT
      LAYER M4 ;
        RECT  0 9.312 0.192 9.336 ;
    END
  END o[30]
  PIN o[310]
    DIRECTION OUTPUT ;
    USE SIGNAL ;
    PORT
      LAYER M4 ;
        RECT  0 55.104 0.192 55.128 ;
    END
  END o[310]
  PIN o[311]
    DIRECTION OUTPUT ;
    USE SIGNAL ;
    PORT
      LAYER M4 ;
        RECT  0 55.296 0.192 55.32 ;
    END
  END o[311]
  PIN o[312]
    DIRECTION OUTPUT ;
    USE SIGNAL ;
    PORT
      LAYER M4 ;
        RECT  0 55.44 0.192 55.464 ;
    END
  END o[312]
  PIN o[313]
    DIRECTION OUTPUT ;
    USE SIGNAL ;
    PORT
      LAYER M4 ;
        RECT  0 55.632 0.192 55.656 ;
    END
  END o[313]
  PIN o[314]
    DIRECTION OUTPUT ;
    USE SIGNAL ;
    PORT
      LAYER M4 ;
        RECT  0 55.776 0.192 55.8 ;
    END
  END o[314]
  PIN o[315]
    DIRECTION OUTPUT ;
    USE SIGNAL ;
    PORT
      LAYER M4 ;
        RECT  0 55.92 0.192 55.944 ;
    END
  END o[315]
  PIN o[316]
    DIRECTION OUTPUT ;
    USE SIGNAL ;
    PORT
      LAYER M4 ;
        RECT  0 56.112 0.192 56.136 ;
    END
  END o[316]
  PIN o[317]
    DIRECTION OUTPUT ;
    USE SIGNAL ;
    PORT
      LAYER M4 ;
        RECT  0 56.256 0.192 56.28 ;
    END
  END o[317]
  PIN o[318]
    DIRECTION OUTPUT ;
    USE SIGNAL ;
    PORT
      LAYER M4 ;
        RECT  0 56.448 0.192 56.472 ;
    END
  END o[318]
  PIN o[319]
    DIRECTION OUTPUT ;
    USE SIGNAL ;
    PORT
      LAYER M4 ;
        RECT  0 56.592 0.192 56.616 ;
    END
  END o[319]
  PIN o[31]
    DIRECTION OUTPUT ;
    USE SIGNAL ;
    PORT
      LAYER M4 ;
        RECT  0 9.504 0.192 9.528 ;
    END
  END o[31]
  PIN o[320]
    DIRECTION OUTPUT ;
    USE SIGNAL ;
    PORT
      LAYER M4 ;
        RECT  0 56.736 0.192 56.76 ;
    END
  END o[320]
  PIN o[321]
    DIRECTION OUTPUT ;
    USE SIGNAL ;
    PORT
      LAYER M4 ;
        RECT  0 56.928 0.192 56.952 ;
    END
  END o[321]
  PIN o[322]
    DIRECTION OUTPUT ;
    USE SIGNAL ;
    PORT
      LAYER M4 ;
        RECT  0 57.072 0.192 57.096 ;
    END
  END o[322]
  PIN o[323]
    DIRECTION OUTPUT ;
    USE SIGNAL ;
    PORT
      LAYER M4 ;
        RECT  0 57.264 0.192 57.288 ;
    END
  END o[323]
  PIN o[324]
    DIRECTION OUTPUT ;
    USE SIGNAL ;
    PORT
      LAYER M4 ;
        RECT  0 57.408 0.192 57.432 ;
    END
  END o[324]
  PIN o[325]
    DIRECTION OUTPUT ;
    USE SIGNAL ;
    PORT
      LAYER M4 ;
        RECT  0 57.552 0.192 57.576 ;
    END
  END o[325]
  PIN o[326]
    DIRECTION OUTPUT ;
    USE SIGNAL ;
    PORT
      LAYER M4 ;
        RECT  0 57.744 0.192 57.768 ;
    END
  END o[326]
  PIN o[327]
    DIRECTION OUTPUT ;
    USE SIGNAL ;
    PORT
      LAYER M4 ;
        RECT  0 57.888 0.192 57.912 ;
    END
  END o[327]
  PIN o[328]
    DIRECTION OUTPUT ;
    USE SIGNAL ;
    PORT
      LAYER M4 ;
        RECT  0 58.08 0.192 58.104 ;
    END
  END o[328]
  PIN o[329]
    DIRECTION OUTPUT ;
    USE SIGNAL ;
    PORT
      LAYER M4 ;
        RECT  0 58.224 0.192 58.248 ;
    END
  END o[329]
  PIN o[32]
    DIRECTION OUTPUT ;
    USE SIGNAL ;
    PORT
      LAYER M4 ;
        RECT  0 9.648 0.192 9.672 ;
    END
  END o[32]
  PIN o[330]
    DIRECTION OUTPUT ;
    USE SIGNAL ;
    PORT
      LAYER M4 ;
        RECT  0 58.416 0.192 58.44 ;
    END
  END o[330]
  PIN o[331]
    DIRECTION OUTPUT ;
    USE SIGNAL ;
    PORT
      LAYER M4 ;
        RECT  0 58.56 0.192 58.584 ;
    END
  END o[331]
  PIN o[332]
    DIRECTION OUTPUT ;
    USE SIGNAL ;
    PORT
      LAYER M4 ;
        RECT  0 58.704 0.192 58.728 ;
    END
  END o[332]
  PIN o[333]
    DIRECTION OUTPUT ;
    USE SIGNAL ;
    PORT
      LAYER M4 ;
        RECT  0 58.896 0.192 58.92 ;
    END
  END o[333]
  PIN o[334]
    DIRECTION OUTPUT ;
    USE SIGNAL ;
    PORT
      LAYER M4 ;
        RECT  0 59.04 0.192 59.064 ;
    END
  END o[334]
  PIN o[335]
    DIRECTION OUTPUT ;
    USE SIGNAL ;
    PORT
      LAYER M4 ;
        RECT  0 59.232 0.192 59.256 ;
    END
  END o[335]
  PIN o[336]
    DIRECTION OUTPUT ;
    USE SIGNAL ;
    PORT
      LAYER M4 ;
        RECT  0 59.376 0.192 59.4 ;
    END
  END o[336]
  PIN o[337]
    DIRECTION OUTPUT ;
    USE SIGNAL ;
    PORT
      LAYER M4 ;
        RECT  0 59.52 0.192 59.544 ;
    END
  END o[337]
  PIN o[338]
    DIRECTION OUTPUT ;
    USE SIGNAL ;
    PORT
      LAYER M4 ;
        RECT  0 59.712 0.192 59.736 ;
    END
  END o[338]
  PIN o[339]
    DIRECTION OUTPUT ;
    USE SIGNAL ;
    PORT
      LAYER M4 ;
        RECT  0 59.856 0.192 59.88 ;
    END
  END o[339]
  PIN o[33]
    DIRECTION OUTPUT ;
    USE SIGNAL ;
    PORT
      LAYER M4 ;
        RECT  0 9.792 0.192 9.816 ;
    END
  END o[33]
  PIN o[340]
    DIRECTION OUTPUT ;
    USE SIGNAL ;
    PORT
      LAYER M4 ;
        RECT  0 60.048 0.192 60.072 ;
    END
  END o[340]
  PIN o[341]
    DIRECTION OUTPUT ;
    USE SIGNAL ;
    PORT
      LAYER M4 ;
        RECT  0 60.192 0.192 60.216 ;
    END
  END o[341]
  PIN o[342]
    DIRECTION OUTPUT ;
    USE SIGNAL ;
    PORT
      LAYER M4 ;
        RECT  0 60.336 0.192 60.36 ;
    END
  END o[342]
  PIN o[343]
    DIRECTION OUTPUT ;
    USE SIGNAL ;
    PORT
      LAYER M4 ;
        RECT  0 60.528 0.192 60.552 ;
    END
  END o[343]
  PIN o[344]
    DIRECTION OUTPUT ;
    USE SIGNAL ;
    PORT
      LAYER M4 ;
        RECT  0 60.672 0.192 60.696 ;
    END
  END o[344]
  PIN o[345]
    DIRECTION OUTPUT ;
    USE SIGNAL ;
    PORT
      LAYER M4 ;
        RECT  0 60.864 0.192 60.888 ;
    END
  END o[345]
  PIN o[346]
    DIRECTION OUTPUT ;
    USE SIGNAL ;
    PORT
      LAYER M4 ;
        RECT  0 61.008 0.192 61.032 ;
    END
  END o[346]
  PIN o[347]
    DIRECTION OUTPUT ;
    USE SIGNAL ;
    PORT
      LAYER M4 ;
        RECT  0 61.152 0.192 61.176 ;
    END
  END o[347]
  PIN o[348]
    DIRECTION OUTPUT ;
    USE SIGNAL ;
    PORT
      LAYER M4 ;
        RECT  0 61.344 0.192 61.368 ;
    END
  END o[348]
  PIN o[349]
    DIRECTION OUTPUT ;
    USE SIGNAL ;
    PORT
      LAYER M4 ;
        RECT  0 61.488 0.192 61.512 ;
    END
  END o[349]
  PIN o[34]
    DIRECTION OUTPUT ;
    USE SIGNAL ;
    PORT
      LAYER M4 ;
        RECT  0 9.984 0.192 10.008 ;
    END
  END o[34]
  PIN o[350]
    DIRECTION OUTPUT ;
    USE SIGNAL ;
    PORT
      LAYER M4 ;
        RECT  0 61.68 0.192 61.704 ;
    END
  END o[350]
  PIN o[351]
    DIRECTION OUTPUT ;
    USE SIGNAL ;
    PORT
      LAYER M4 ;
        RECT  0 61.824 0.192 61.848 ;
    END
  END o[351]
  PIN o[352]
    DIRECTION OUTPUT ;
    USE SIGNAL ;
    PORT
      LAYER M4 ;
        RECT  0 61.968 0.192 61.992 ;
    END
  END o[352]
  PIN o[353]
    DIRECTION OUTPUT ;
    USE SIGNAL ;
    PORT
      LAYER M4 ;
        RECT  0 62.16 0.192 62.184 ;
    END
  END o[353]
  PIN o[354]
    DIRECTION OUTPUT ;
    USE SIGNAL ;
    PORT
      LAYER M4 ;
        RECT  0 62.304 0.192 62.328 ;
    END
  END o[354]
  PIN o[355]
    DIRECTION OUTPUT ;
    USE SIGNAL ;
    PORT
      LAYER M4 ;
        RECT  0 62.496 0.192 62.52 ;
    END
  END o[355]
  PIN o[356]
    DIRECTION OUTPUT ;
    USE SIGNAL ;
    PORT
      LAYER M4 ;
        RECT  0 62.64 0.192 62.664 ;
    END
  END o[356]
  PIN o[357]
    DIRECTION OUTPUT ;
    USE SIGNAL ;
    PORT
      LAYER M4 ;
        RECT  0 62.832 0.192 62.856 ;
    END
  END o[357]
  PIN o[358]
    DIRECTION OUTPUT ;
    USE SIGNAL ;
    PORT
      LAYER M4 ;
        RECT  0 62.976 0.192 63 ;
    END
  END o[358]
  PIN o[359]
    DIRECTION OUTPUT ;
    USE SIGNAL ;
    PORT
      LAYER M4 ;
        RECT  0 63.12 0.192 63.144 ;
    END
  END o[359]
  PIN o[35]
    DIRECTION OUTPUT ;
    USE SIGNAL ;
    PORT
      LAYER M4 ;
        RECT  0 10.128 0.192 10.152 ;
    END
  END o[35]
  PIN o[360]
    DIRECTION OUTPUT ;
    USE SIGNAL ;
    PORT
      LAYER M4 ;
        RECT  0 63.312 0.192 63.336 ;
    END
  END o[360]
  PIN o[361]
    DIRECTION OUTPUT ;
    USE SIGNAL ;
    PORT
      LAYER M4 ;
        RECT  0 63.456 0.192 63.48 ;
    END
  END o[361]
  PIN o[362]
    DIRECTION OUTPUT ;
    USE SIGNAL ;
    PORT
      LAYER M4 ;
        RECT  0 63.648 0.192 63.672 ;
    END
  END o[362]
  PIN o[363]
    DIRECTION OUTPUT ;
    USE SIGNAL ;
    PORT
      LAYER M4 ;
        RECT  0 63.792 0.192 63.816 ;
    END
  END o[363]
  PIN o[364]
    DIRECTION OUTPUT ;
    USE SIGNAL ;
    PORT
      LAYER M4 ;
        RECT  0 63.936 0.192 63.96 ;
    END
  END o[364]
  PIN o[365]
    DIRECTION OUTPUT ;
    USE SIGNAL ;
    PORT
      LAYER M4 ;
        RECT  0 64.128 0.192 64.152 ;
    END
  END o[365]
  PIN o[366]
    DIRECTION OUTPUT ;
    USE SIGNAL ;
    PORT
      LAYER M4 ;
        RECT  0 64.272 0.192 64.296 ;
    END
  END o[366]
  PIN o[367]
    DIRECTION OUTPUT ;
    USE SIGNAL ;
    PORT
      LAYER M4 ;
        RECT  0 64.464 0.192 64.488 ;
    END
  END o[367]
  PIN o[368]
    DIRECTION OUTPUT ;
    USE SIGNAL ;
    PORT
      LAYER M4 ;
        RECT  0 64.608 0.192 64.632 ;
    END
  END o[368]
  PIN o[369]
    DIRECTION OUTPUT ;
    USE SIGNAL ;
    PORT
      LAYER M4 ;
        RECT  0 64.752 0.192 64.776 ;
    END
  END o[369]
  PIN o[36]
    DIRECTION OUTPUT ;
    USE SIGNAL ;
    PORT
      LAYER M4 ;
        RECT  0 10.32 0.192 10.344 ;
    END
  END o[36]
  PIN o[370]
    DIRECTION OUTPUT ;
    USE SIGNAL ;
    PORT
      LAYER M4 ;
        RECT  0 64.944 0.192 64.968 ;
    END
  END o[370]
  PIN o[371]
    DIRECTION OUTPUT ;
    USE SIGNAL ;
    PORT
      LAYER M4 ;
        RECT  0 65.088 0.192 65.112 ;
    END
  END o[371]
  PIN o[372]
    DIRECTION OUTPUT ;
    USE SIGNAL ;
    PORT
      LAYER M4 ;
        RECT  0 65.28 0.192 65.304 ;
    END
  END o[372]
  PIN o[373]
    DIRECTION OUTPUT ;
    USE SIGNAL ;
    PORT
      LAYER M4 ;
        RECT  0 65.424 0.192 65.448 ;
    END
  END o[373]
  PIN o[374]
    DIRECTION OUTPUT ;
    USE SIGNAL ;
    PORT
      LAYER M4 ;
        RECT  0 65.568 0.192 65.592 ;
    END
  END o[374]
  PIN o[375]
    DIRECTION OUTPUT ;
    USE SIGNAL ;
    PORT
      LAYER M4 ;
        RECT  0 65.76 0.192 65.784 ;
    END
  END o[375]
  PIN o[376]
    DIRECTION OUTPUT ;
    USE SIGNAL ;
    PORT
      LAYER M4 ;
        RECT  0 65.904 0.192 65.928 ;
    END
  END o[376]
  PIN o[377]
    DIRECTION OUTPUT ;
    USE SIGNAL ;
    PORT
      LAYER M4 ;
        RECT  0 66.096 0.192 66.12 ;
    END
  END o[377]
  PIN o[378]
    DIRECTION OUTPUT ;
    USE SIGNAL ;
    PORT
      LAYER M4 ;
        RECT  0 66.24 0.192 66.264 ;
    END
  END o[378]
  PIN o[379]
    DIRECTION OUTPUT ;
    USE SIGNAL ;
    PORT
      LAYER M4 ;
        RECT  0 66.384 0.192 66.408 ;
    END
  END o[379]
  PIN o[37]
    DIRECTION OUTPUT ;
    USE SIGNAL ;
    PORT
      LAYER M4 ;
        RECT  0 10.464 0.192 10.488 ;
    END
  END o[37]
  PIN o[380]
    DIRECTION OUTPUT ;
    USE SIGNAL ;
    PORT
      LAYER M4 ;
        RECT  0 66.576 0.192 66.6 ;
    END
  END o[380]
  PIN o[381]
    DIRECTION OUTPUT ;
    USE SIGNAL ;
    PORT
      LAYER M4 ;
        RECT  0 66.72 0.192 66.744 ;
    END
  END o[381]
  PIN o[382]
    DIRECTION OUTPUT ;
    USE SIGNAL ;
    PORT
      LAYER M4 ;
        RECT  0 66.912 0.192 66.936 ;
    END
  END o[382]
  PIN o[383]
    DIRECTION OUTPUT ;
    USE SIGNAL ;
    PORT
      LAYER M4 ;
        RECT  0 67.056 0.192 67.08 ;
    END
  END o[383]
  PIN o[384]
    DIRECTION OUTPUT ;
    USE SIGNAL ;
    PORT
      LAYER M4 ;
        RECT  0 67.248 0.192 67.272 ;
    END
  END o[384]
  PIN o[385]
    DIRECTION OUTPUT ;
    USE SIGNAL ;
    PORT
      LAYER M4 ;
        RECT  0 67.392 0.192 67.416 ;
    END
  END o[385]
  PIN o[386]
    DIRECTION OUTPUT ;
    USE SIGNAL ;
    PORT
      LAYER M4 ;
        RECT  0 67.536 0.192 67.56 ;
    END
  END o[386]
  PIN o[387]
    DIRECTION OUTPUT ;
    USE SIGNAL ;
    PORT
      LAYER M4 ;
        RECT  0 67.728 0.192 67.752 ;
    END
  END o[387]
  PIN o[388]
    DIRECTION OUTPUT ;
    USE SIGNAL ;
    PORT
      LAYER M4 ;
        RECT  0 67.872 0.192 67.896 ;
    END
  END o[388]
  PIN o[389]
    DIRECTION OUTPUT ;
    USE SIGNAL ;
    PORT
      LAYER M4 ;
        RECT  0 68.064 0.192 68.088 ;
    END
  END o[389]
  PIN o[38]
    DIRECTION OUTPUT ;
    USE SIGNAL ;
    PORT
      LAYER M4 ;
        RECT  0 10.608 0.192 10.632 ;
    END
  END o[38]
  PIN o[390]
    DIRECTION OUTPUT ;
    USE SIGNAL ;
    PORT
      LAYER M4 ;
        RECT  0 68.208 0.192 68.232 ;
    END
  END o[390]
  PIN o[391]
    DIRECTION OUTPUT ;
    USE SIGNAL ;
    PORT
      LAYER M4 ;
        RECT  0 68.352 0.192 68.376 ;
    END
  END o[391]
  PIN o[392]
    DIRECTION OUTPUT ;
    USE SIGNAL ;
    PORT
      LAYER M4 ;
        RECT  0 68.544 0.192 68.568 ;
    END
  END o[392]
  PIN o[393]
    DIRECTION OUTPUT ;
    USE SIGNAL ;
    PORT
      LAYER M4 ;
        RECT  0 68.688 0.192 68.712 ;
    END
  END o[393]
  PIN o[394]
    DIRECTION OUTPUT ;
    USE SIGNAL ;
    PORT
      LAYER M4 ;
        RECT  0 68.88 0.192 68.904 ;
    END
  END o[394]
  PIN o[395]
    DIRECTION OUTPUT ;
    USE SIGNAL ;
    PORT
      LAYER M4 ;
        RECT  0 69.024 0.192 69.048 ;
    END
  END o[395]
  PIN o[396]
    DIRECTION OUTPUT ;
    USE SIGNAL ;
    PORT
      LAYER M4 ;
        RECT  0 69.168 0.192 69.192 ;
    END
  END o[396]
  PIN o[397]
    DIRECTION OUTPUT ;
    USE SIGNAL ;
    PORT
      LAYER M4 ;
        RECT  0 69.36 0.192 69.384 ;
    END
  END o[397]
  PIN o[398]
    DIRECTION OUTPUT ;
    USE SIGNAL ;
    PORT
      LAYER M4 ;
        RECT  0 69.504 0.192 69.528 ;
    END
  END o[398]
  PIN o[399]
    DIRECTION OUTPUT ;
    USE SIGNAL ;
    PORT
      LAYER M4 ;
        RECT  0 69.696 0.192 69.72 ;
    END
  END o[399]
  PIN o[39]
    DIRECTION OUTPUT ;
    USE SIGNAL ;
    PORT
      LAYER M4 ;
        RECT  0 10.8 0.192 10.824 ;
    END
  END o[39]
  PIN o[3]
    DIRECTION OUTPUT ;
    USE SIGNAL ;
    PORT
      LAYER M4 ;
        RECT  0 4.896 0.192 4.92 ;
    END
  END o[3]
  PIN o[400]
    DIRECTION OUTPUT ;
    USE SIGNAL ;
    PORT
      LAYER M4 ;
        RECT  0 69.84 0.192 69.864 ;
    END
  END o[400]
  PIN o[401]
    DIRECTION OUTPUT ;
    USE SIGNAL ;
    PORT
      LAYER M4 ;
        RECT  0 69.984 0.192 70.008 ;
    END
  END o[401]
  PIN o[402]
    DIRECTION OUTPUT ;
    USE SIGNAL ;
    PORT
      LAYER M4 ;
        RECT  0 70.176 0.192 70.2 ;
    END
  END o[402]
  PIN o[403]
    DIRECTION OUTPUT ;
    USE SIGNAL ;
    PORT
      LAYER M4 ;
        RECT  0 70.32 0.192 70.344 ;
    END
  END o[403]
  PIN o[404]
    DIRECTION OUTPUT ;
    USE SIGNAL ;
    PORT
      LAYER M4 ;
        RECT  0 70.512 0.192 70.536 ;
    END
  END o[404]
  PIN o[405]
    DIRECTION OUTPUT ;
    USE SIGNAL ;
    PORT
      LAYER M4 ;
        RECT  0 70.656 0.192 70.68 ;
    END
  END o[405]
  PIN o[406]
    DIRECTION OUTPUT ;
    USE SIGNAL ;
    PORT
      LAYER M4 ;
        RECT  0 70.848 0.192 70.872 ;
    END
  END o[406]
  PIN o[407]
    DIRECTION OUTPUT ;
    USE SIGNAL ;
    PORT
      LAYER M4 ;
        RECT  0 70.992 0.192 71.016 ;
    END
  END o[407]
  PIN o[408]
    DIRECTION OUTPUT ;
    USE SIGNAL ;
    PORT
      LAYER M4 ;
        RECT  0 71.136 0.192 71.16 ;
    END
  END o[408]
  PIN o[409]
    DIRECTION OUTPUT ;
    USE SIGNAL ;
    PORT
      LAYER M4 ;
        RECT  0 71.328 0.192 71.352 ;
    END
  END o[409]
  PIN o[40]
    DIRECTION OUTPUT ;
    USE SIGNAL ;
    PORT
      LAYER M4 ;
        RECT  0 10.944 0.192 10.968 ;
    END
  END o[40]
  PIN o[410]
    DIRECTION OUTPUT ;
    USE SIGNAL ;
    PORT
      LAYER M4 ;
        RECT  0 71.472 0.192 71.496 ;
    END
  END o[410]
  PIN o[411]
    DIRECTION OUTPUT ;
    USE SIGNAL ;
    PORT
      LAYER M4 ;
        RECT  0 71.664 0.192 71.688 ;
    END
  END o[411]
  PIN o[412]
    DIRECTION OUTPUT ;
    USE SIGNAL ;
    PORT
      LAYER M4 ;
        RECT  0 71.808 0.192 71.832 ;
    END
  END o[412]
  PIN o[413]
    DIRECTION OUTPUT ;
    USE SIGNAL ;
    PORT
      LAYER M4 ;
        RECT  0 71.952 0.192 71.976 ;
    END
  END o[413]
  PIN o[414]
    DIRECTION OUTPUT ;
    USE SIGNAL ;
    PORT
      LAYER M4 ;
        RECT  0 72.144 0.192 72.168 ;
    END
  END o[414]
  PIN o[415]
    DIRECTION OUTPUT ;
    USE SIGNAL ;
    PORT
      LAYER M4 ;
        RECT  0 72.288 0.192 72.312 ;
    END
  END o[415]
  PIN o[416]
    DIRECTION OUTPUT ;
    USE SIGNAL ;
    PORT
      LAYER M4 ;
        RECT  0 72.48 0.192 72.504 ;
    END
  END o[416]
  PIN o[417]
    DIRECTION OUTPUT ;
    USE SIGNAL ;
    PORT
      LAYER M4 ;
        RECT  0 72.624 0.192 72.648 ;
    END
  END o[417]
  PIN o[418]
    DIRECTION OUTPUT ;
    USE SIGNAL ;
    PORT
      LAYER M4 ;
        RECT  0 72.768 0.192 72.792 ;
    END
  END o[418]
  PIN o[419]
    DIRECTION OUTPUT ;
    USE SIGNAL ;
    PORT
      LAYER M4 ;
        RECT  0 72.96 0.192 72.984 ;
    END
  END o[419]
  PIN o[41]
    DIRECTION OUTPUT ;
    USE SIGNAL ;
    PORT
      LAYER M4 ;
        RECT  0 11.136 0.192 11.16 ;
    END
  END o[41]
  PIN o[420]
    DIRECTION OUTPUT ;
    USE SIGNAL ;
    PORT
      LAYER M4 ;
        RECT  0 73.104 0.192 73.128 ;
    END
  END o[420]
  PIN o[421]
    DIRECTION OUTPUT ;
    USE SIGNAL ;
    PORT
      LAYER M4 ;
        RECT  0 73.296 0.192 73.32 ;
    END
  END o[421]
  PIN o[422]
    DIRECTION OUTPUT ;
    USE SIGNAL ;
    PORT
      LAYER M4 ;
        RECT  0 73.44 0.192 73.464 ;
    END
  END o[422]
  PIN o[423]
    DIRECTION OUTPUT ;
    USE SIGNAL ;
    PORT
      LAYER M4 ;
        RECT  0 73.584 0.192 73.608 ;
    END
  END o[423]
  PIN o[424]
    DIRECTION OUTPUT ;
    USE SIGNAL ;
    PORT
      LAYER M4 ;
        RECT  0 73.776 0.192 73.8 ;
    END
  END o[424]
  PIN o[425]
    DIRECTION OUTPUT ;
    USE SIGNAL ;
    PORT
      LAYER M4 ;
        RECT  0 73.92 0.192 73.944 ;
    END
  END o[425]
  PIN o[426]
    DIRECTION OUTPUT ;
    USE SIGNAL ;
    PORT
      LAYER M4 ;
        RECT  0 74.112 0.192 74.136 ;
    END
  END o[426]
  PIN o[427]
    DIRECTION OUTPUT ;
    USE SIGNAL ;
    PORT
      LAYER M4 ;
        RECT  0 74.256 0.192 74.28 ;
    END
  END o[427]
  PIN o[428]
    DIRECTION OUTPUT ;
    USE SIGNAL ;
    PORT
      LAYER M4 ;
        RECT  0 74.4 0.192 74.424 ;
    END
  END o[428]
  PIN o[429]
    DIRECTION OUTPUT ;
    USE SIGNAL ;
    PORT
      LAYER M4 ;
        RECT  0 74.592 0.192 74.616 ;
    END
  END o[429]
  PIN o[42]
    DIRECTION OUTPUT ;
    USE SIGNAL ;
    PORT
      LAYER M4 ;
        RECT  0 11.28 0.192 11.304 ;
    END
  END o[42]
  PIN o[430]
    DIRECTION OUTPUT ;
    USE SIGNAL ;
    PORT
      LAYER M4 ;
        RECT  0 74.736 0.192 74.76 ;
    END
  END o[430]
  PIN o[431]
    DIRECTION OUTPUT ;
    USE SIGNAL ;
    PORT
      LAYER M4 ;
        RECT  0 74.928 0.192 74.952 ;
    END
  END o[431]
  PIN o[432]
    DIRECTION OUTPUT ;
    USE SIGNAL ;
    PORT
      LAYER M4 ;
        RECT  0 75.072 0.192 75.096 ;
    END
  END o[432]
  PIN o[433]
    DIRECTION OUTPUT ;
    USE SIGNAL ;
    PORT
      LAYER M4 ;
        RECT  0 75.264 0.192 75.288 ;
    END
  END o[433]
  PIN o[434]
    DIRECTION OUTPUT ;
    USE SIGNAL ;
    PORT
      LAYER M4 ;
        RECT  0 75.408 0.192 75.432 ;
    END
  END o[434]
  PIN o[435]
    DIRECTION OUTPUT ;
    USE SIGNAL ;
    PORT
      LAYER M4 ;
        RECT  0 75.552 0.192 75.576 ;
    END
  END o[435]
  PIN o[436]
    DIRECTION OUTPUT ;
    USE SIGNAL ;
    PORT
      LAYER M4 ;
        RECT  0 75.744 0.192 75.768 ;
    END
  END o[436]
  PIN o[437]
    DIRECTION OUTPUT ;
    USE SIGNAL ;
    PORT
      LAYER M4 ;
        RECT  0 75.888 0.192 75.912 ;
    END
  END o[437]
  PIN o[438]
    DIRECTION OUTPUT ;
    USE SIGNAL ;
    PORT
      LAYER M4 ;
        RECT  0 76.08 0.192 76.104 ;
    END
  END o[438]
  PIN o[439]
    DIRECTION OUTPUT ;
    USE SIGNAL ;
    PORT
      LAYER M4 ;
        RECT  0 76.224 0.192 76.248 ;
    END
  END o[439]
  PIN o[43]
    DIRECTION OUTPUT ;
    USE SIGNAL ;
    PORT
      LAYER M4 ;
        RECT  0 11.424 0.192 11.448 ;
    END
  END o[43]
  PIN o[440]
    DIRECTION OUTPUT ;
    USE SIGNAL ;
    PORT
      LAYER M4 ;
        RECT  0 76.368 0.192 76.392 ;
    END
  END o[440]
  PIN o[441]
    DIRECTION OUTPUT ;
    USE SIGNAL ;
    PORT
      LAYER M4 ;
        RECT  0 76.56 0.192 76.584 ;
    END
  END o[441]
  PIN o[442]
    DIRECTION OUTPUT ;
    USE SIGNAL ;
    PORT
      LAYER M4 ;
        RECT  0 76.704 0.192 76.728 ;
    END
  END o[442]
  PIN o[443]
    DIRECTION OUTPUT ;
    USE SIGNAL ;
    PORT
      LAYER M4 ;
        RECT  0 76.896 0.192 76.92 ;
    END
  END o[443]
  PIN o[444]
    DIRECTION OUTPUT ;
    USE SIGNAL ;
    PORT
      LAYER M4 ;
        RECT  0 77.04 0.192 77.064 ;
    END
  END o[444]
  PIN o[445]
    DIRECTION OUTPUT ;
    USE SIGNAL ;
    PORT
      LAYER M4 ;
        RECT  0 77.184 0.192 77.208 ;
    END
  END o[445]
  PIN o[446]
    DIRECTION OUTPUT ;
    USE SIGNAL ;
    PORT
      LAYER M4 ;
        RECT  0 77.376 0.192 77.4 ;
    END
  END o[446]
  PIN o[447]
    DIRECTION OUTPUT ;
    USE SIGNAL ;
    PORT
      LAYER M4 ;
        RECT  0 77.52 0.192 77.544 ;
    END
  END o[447]
  PIN o[448]
    DIRECTION OUTPUT ;
    USE SIGNAL ;
    PORT
      LAYER M4 ;
        RECT  0 77.712 0.192 77.736 ;
    END
  END o[448]
  PIN o[449]
    DIRECTION OUTPUT ;
    USE SIGNAL ;
    PORT
      LAYER M4 ;
        RECT  0 77.856 0.192 77.88 ;
    END
  END o[449]
  PIN o[44]
    DIRECTION OUTPUT ;
    USE SIGNAL ;
    PORT
      LAYER M4 ;
        RECT  0 11.616 0.192 11.64 ;
    END
  END o[44]
  PIN o[450]
    DIRECTION OUTPUT ;
    USE SIGNAL ;
    PORT
      LAYER M4 ;
        RECT  0 78 0.192 78.024 ;
    END
  END o[450]
  PIN o[451]
    DIRECTION OUTPUT ;
    USE SIGNAL ;
    PORT
      LAYER M4 ;
        RECT  0 78.192 0.192 78.216 ;
    END
  END o[451]
  PIN o[452]
    DIRECTION OUTPUT ;
    USE SIGNAL ;
    PORT
      LAYER M4 ;
        RECT  0 78.336 0.192 78.36 ;
    END
  END o[452]
  PIN o[453]
    DIRECTION OUTPUT ;
    USE SIGNAL ;
    PORT
      LAYER M4 ;
        RECT  0 78.528 0.192 78.552 ;
    END
  END o[453]
  PIN o[454]
    DIRECTION OUTPUT ;
    USE SIGNAL ;
    PORT
      LAYER M4 ;
        RECT  0 78.672 0.192 78.696 ;
    END
  END o[454]
  PIN o[455]
    DIRECTION OUTPUT ;
    USE SIGNAL ;
    PORT
      LAYER M4 ;
        RECT  0 78.816 0.192 78.84 ;
    END
  END o[455]
  PIN o[456]
    DIRECTION OUTPUT ;
    USE SIGNAL ;
    PORT
      LAYER M4 ;
        RECT  0 79.008 0.192 79.032 ;
    END
  END o[456]
  PIN o[457]
    DIRECTION OUTPUT ;
    USE SIGNAL ;
    PORT
      LAYER M4 ;
        RECT  0 79.152 0.192 79.176 ;
    END
  END o[457]
  PIN o[458]
    DIRECTION OUTPUT ;
    USE SIGNAL ;
    PORT
      LAYER M4 ;
        RECT  0 79.344 0.192 79.368 ;
    END
  END o[458]
  PIN o[459]
    DIRECTION OUTPUT ;
    USE SIGNAL ;
    PORT
      LAYER M4 ;
        RECT  0 79.488 0.192 79.512 ;
    END
  END o[459]
  PIN o[45]
    DIRECTION OUTPUT ;
    USE SIGNAL ;
    PORT
      LAYER M4 ;
        RECT  0 11.76 0.192 11.784 ;
    END
  END o[45]
  PIN o[460]
    DIRECTION OUTPUT ;
    USE SIGNAL ;
    PORT
      LAYER M4 ;
        RECT  0 79.68 0.192 79.704 ;
    END
  END o[460]
  PIN o[461]
    DIRECTION OUTPUT ;
    USE SIGNAL ;
    PORT
      LAYER M4 ;
        RECT  0 79.824 0.192 79.848 ;
    END
  END o[461]
  PIN o[462]
    DIRECTION OUTPUT ;
    USE SIGNAL ;
    PORT
      LAYER M4 ;
        RECT  0 79.968 0.192 79.992 ;
    END
  END o[462]
  PIN o[463]
    DIRECTION OUTPUT ;
    USE SIGNAL ;
    PORT
      LAYER M4 ;
        RECT  0 80.16 0.192 80.184 ;
    END
  END o[463]
  PIN o[464]
    DIRECTION OUTPUT ;
    USE SIGNAL ;
    PORT
      LAYER M4 ;
        RECT  0 80.304 0.192 80.328 ;
    END
  END o[464]
  PIN o[465]
    DIRECTION OUTPUT ;
    USE SIGNAL ;
    PORT
      LAYER M4 ;
        RECT  0 80.496 0.192 80.52 ;
    END
  END o[465]
  PIN o[466]
    DIRECTION OUTPUT ;
    USE SIGNAL ;
    PORT
      LAYER M4 ;
        RECT  0 80.64 0.192 80.664 ;
    END
  END o[466]
  PIN o[467]
    DIRECTION OUTPUT ;
    USE SIGNAL ;
    PORT
      LAYER M4 ;
        RECT  0 80.784 0.192 80.808 ;
    END
  END o[467]
  PIN o[468]
    DIRECTION OUTPUT ;
    USE SIGNAL ;
    PORT
      LAYER M4 ;
        RECT  0 80.976 0.192 81 ;
    END
  END o[468]
  PIN o[469]
    DIRECTION OUTPUT ;
    USE SIGNAL ;
    PORT
      LAYER M4 ;
        RECT  0 81.12 0.192 81.144 ;
    END
  END o[469]
  PIN o[46]
    DIRECTION OUTPUT ;
    USE SIGNAL ;
    PORT
      LAYER M4 ;
        RECT  0 11.952 0.192 11.976 ;
    END
  END o[46]
  PIN o[470]
    DIRECTION OUTPUT ;
    USE SIGNAL ;
    PORT
      LAYER M4 ;
        RECT  0 81.312 0.192 81.336 ;
    END
  END o[470]
  PIN o[471]
    DIRECTION OUTPUT ;
    USE SIGNAL ;
    PORT
      LAYER M4 ;
        RECT  0 81.456 0.192 81.48 ;
    END
  END o[471]
  PIN o[472]
    DIRECTION OUTPUT ;
    USE SIGNAL ;
    PORT
      LAYER M4 ;
        RECT  0 81.6 0.192 81.624 ;
    END
  END o[472]
  PIN o[473]
    DIRECTION OUTPUT ;
    USE SIGNAL ;
    PORT
      LAYER M4 ;
        RECT  0 81.792 0.192 81.816 ;
    END
  END o[473]
  PIN o[474]
    DIRECTION OUTPUT ;
    USE SIGNAL ;
    PORT
      LAYER M4 ;
        RECT  0 81.936 0.192 81.96 ;
    END
  END o[474]
  PIN o[475]
    DIRECTION OUTPUT ;
    USE SIGNAL ;
    PORT
      LAYER M4 ;
        RECT  0 82.128 0.192 82.152 ;
    END
  END o[475]
  PIN o[476]
    DIRECTION OUTPUT ;
    USE SIGNAL ;
    PORT
      LAYER M4 ;
        RECT  0 82.272 0.192 82.296 ;
    END
  END o[476]
  PIN o[477]
    DIRECTION OUTPUT ;
    USE SIGNAL ;
    PORT
      LAYER M4 ;
        RECT  0 82.416 0.192 82.44 ;
    END
  END o[477]
  PIN o[478]
    DIRECTION OUTPUT ;
    USE SIGNAL ;
    PORT
      LAYER M4 ;
        RECT  0 82.608 0.192 82.632 ;
    END
  END o[478]
  PIN o[479]
    DIRECTION OUTPUT ;
    USE SIGNAL ;
    PORT
      LAYER M4 ;
        RECT  0 82.752 0.192 82.776 ;
    END
  END o[479]
  PIN o[47]
    DIRECTION OUTPUT ;
    USE SIGNAL ;
    PORT
      LAYER M4 ;
        RECT  0 12.096 0.192 12.12 ;
    END
  END o[47]
  PIN o[480]
    DIRECTION OUTPUT ;
    USE SIGNAL ;
    PORT
      LAYER M4 ;
        RECT  0 82.944 0.192 82.968 ;
    END
  END o[480]
  PIN o[481]
    DIRECTION OUTPUT ;
    USE SIGNAL ;
    PORT
      LAYER M4 ;
        RECT  0 83.088 0.192 83.112 ;
    END
  END o[481]
  PIN o[482]
    DIRECTION OUTPUT ;
    USE SIGNAL ;
    PORT
      LAYER M4 ;
        RECT  0 83.232 0.192 83.256 ;
    END
  END o[482]
  PIN o[483]
    DIRECTION OUTPUT ;
    USE SIGNAL ;
    PORT
      LAYER M4 ;
        RECT  0 83.424 0.192 83.448 ;
    END
  END o[483]
  PIN o[484]
    DIRECTION OUTPUT ;
    USE SIGNAL ;
    PORT
      LAYER M4 ;
        RECT  0 83.568 0.192 83.592 ;
    END
  END o[484]
  PIN o[485]
    DIRECTION OUTPUT ;
    USE SIGNAL ;
    PORT
      LAYER M4 ;
        RECT  0 83.76 0.192 83.784 ;
    END
  END o[485]
  PIN o[486]
    DIRECTION OUTPUT ;
    USE SIGNAL ;
    PORT
      LAYER M4 ;
        RECT  0 83.904 0.192 83.928 ;
    END
  END o[486]
  PIN o[487]
    DIRECTION OUTPUT ;
    USE SIGNAL ;
    PORT
      LAYER M4 ;
        RECT  0 84.096 0.192 84.12 ;
    END
  END o[487]
  PIN o[488]
    DIRECTION OUTPUT ;
    USE SIGNAL ;
    PORT
      LAYER M4 ;
        RECT  0 84.24 0.192 84.264 ;
    END
  END o[488]
  PIN o[489]
    DIRECTION OUTPUT ;
    USE SIGNAL ;
    PORT
      LAYER M4 ;
        RECT  0 84.384 0.192 84.408 ;
    END
  END o[489]
  PIN o[48]
    DIRECTION OUTPUT ;
    USE SIGNAL ;
    PORT
      LAYER M4 ;
        RECT  0 12.288 0.192 12.312 ;
    END
  END o[48]
  PIN o[490]
    DIRECTION OUTPUT ;
    USE SIGNAL ;
    PORT
      LAYER M4 ;
        RECT  0 84.576 0.192 84.6 ;
    END
  END o[490]
  PIN o[491]
    DIRECTION OUTPUT ;
    USE SIGNAL ;
    PORT
      LAYER M4 ;
        RECT  0 84.72 0.192 84.744 ;
    END
  END o[491]
  PIN o[492]
    DIRECTION OUTPUT ;
    USE SIGNAL ;
    PORT
      LAYER M4 ;
        RECT  0 84.912 0.192 84.936 ;
    END
  END o[492]
  PIN o[493]
    DIRECTION OUTPUT ;
    USE SIGNAL ;
    PORT
      LAYER M4 ;
        RECT  0 85.056 0.192 85.08 ;
    END
  END o[493]
  PIN o[494]
    DIRECTION OUTPUT ;
    USE SIGNAL ;
    PORT
      LAYER M4 ;
        RECT  0 85.2 0.192 85.224 ;
    END
  END o[494]
  PIN o[495]
    DIRECTION OUTPUT ;
    USE SIGNAL ;
    PORT
      LAYER M4 ;
        RECT  0 85.392 0.192 85.416 ;
    END
  END o[495]
  PIN o[496]
    DIRECTION OUTPUT ;
    USE SIGNAL ;
    PORT
      LAYER M4 ;
        RECT  0 85.536 0.192 85.56 ;
    END
  END o[496]
  PIN o[497]
    DIRECTION OUTPUT ;
    USE SIGNAL ;
    PORT
      LAYER M4 ;
        RECT  0 85.728 0.192 85.752 ;
    END
  END o[497]
  PIN o[498]
    DIRECTION OUTPUT ;
    USE SIGNAL ;
    PORT
      LAYER M4 ;
        RECT  0 85.872 0.192 85.896 ;
    END
  END o[498]
  PIN o[499]
    DIRECTION OUTPUT ;
    USE SIGNAL ;
    PORT
      LAYER M4 ;
        RECT  0 86.016 0.192 86.04 ;
    END
  END o[499]
  PIN o[49]
    DIRECTION OUTPUT ;
    USE SIGNAL ;
    PORT
      LAYER M4 ;
        RECT  0 12.432 0.192 12.456 ;
    END
  END o[49]
  PIN o[4]
    DIRECTION OUTPUT ;
    USE SIGNAL ;
    PORT
      LAYER M4 ;
        RECT  0 5.088 0.192 5.112 ;
    END
  END o[4]
  PIN o[500]
    DIRECTION OUTPUT ;
    USE SIGNAL ;
    PORT
      LAYER M4 ;
        RECT  0 86.208 0.192 86.232 ;
    END
  END o[500]
  PIN o[501]
    DIRECTION OUTPUT ;
    USE SIGNAL ;
    PORT
      LAYER M4 ;
        RECT  0 86.352 0.192 86.376 ;
    END
  END o[501]
  PIN o[502]
    DIRECTION OUTPUT ;
    USE SIGNAL ;
    PORT
      LAYER M4 ;
        RECT  0 86.544 0.192 86.568 ;
    END
  END o[502]
  PIN o[503]
    DIRECTION OUTPUT ;
    USE SIGNAL ;
    PORT
      LAYER M4 ;
        RECT  0 86.688 0.192 86.712 ;
    END
  END o[503]
  PIN o[504]
    DIRECTION OUTPUT ;
    USE SIGNAL ;
    PORT
      LAYER M4 ;
        RECT  0 86.832 0.192 86.856 ;
    END
  END o[504]
  PIN o[505]
    DIRECTION OUTPUT ;
    USE SIGNAL ;
    PORT
      LAYER M4 ;
        RECT  0 87.024 0.192 87.048 ;
    END
  END o[505]
  PIN o[506]
    DIRECTION OUTPUT ;
    USE SIGNAL ;
    PORT
      LAYER M4 ;
        RECT  0 87.168 0.192 87.192 ;
    END
  END o[506]
  PIN o[507]
    DIRECTION OUTPUT ;
    USE SIGNAL ;
    PORT
      LAYER M4 ;
        RECT  0 87.36 0.192 87.384 ;
    END
  END o[507]
  PIN o[508]
    DIRECTION OUTPUT ;
    USE SIGNAL ;
    PORT
      LAYER M4 ;
        RECT  0 87.504 0.192 87.528 ;
    END
  END o[508]
  PIN o[509]
    DIRECTION OUTPUT ;
    USE SIGNAL ;
    PORT
      LAYER M4 ;
        RECT  0 87.696 0.192 87.72 ;
    END
  END o[509]
  PIN o[50]
    DIRECTION OUTPUT ;
    USE SIGNAL ;
    PORT
      LAYER M4 ;
        RECT  0 12.576 0.192 12.6 ;
    END
  END o[50]
  PIN o[510]
    DIRECTION OUTPUT ;
    USE SIGNAL ;
    PORT
      LAYER M4 ;
        RECT  0 87.84 0.192 87.864 ;
    END
  END o[510]
  PIN o[511]
    DIRECTION OUTPUT ;
    USE SIGNAL ;
    PORT
      LAYER M4 ;
        RECT  0 87.984 0.192 88.008 ;
    END
  END o[511]
  PIN o[512]
    DIRECTION OUTPUT ;
    USE SIGNAL ;
    PORT
      LAYER M4 ;
        RECT  0 88.176 0.192 88.2 ;
    END
  END o[512]
  PIN o[513]
    DIRECTION OUTPUT ;
    USE SIGNAL ;
    PORT
      LAYER M4 ;
        RECT  0 88.32 0.192 88.344 ;
    END
  END o[513]
  PIN o[514]
    DIRECTION OUTPUT ;
    USE SIGNAL ;
    PORT
      LAYER M4 ;
        RECT  0 88.512 0.192 88.536 ;
    END
  END o[514]
  PIN o[51]
    DIRECTION OUTPUT ;
    USE SIGNAL ;
    PORT
      LAYER M4 ;
        RECT  0 12.768 0.192 12.792 ;
    END
  END o[51]
  PIN o[52]
    DIRECTION OUTPUT ;
    USE SIGNAL ;
    PORT
      LAYER M4 ;
        RECT  0 12.912 0.192 12.936 ;
    END
  END o[52]
  PIN o[53]
    DIRECTION OUTPUT ;
    USE SIGNAL ;
    PORT
      LAYER M4 ;
        RECT  0 13.104 0.192 13.128 ;
    END
  END o[53]
  PIN o[54]
    DIRECTION OUTPUT ;
    USE SIGNAL ;
    PORT
      LAYER M4 ;
        RECT  0 13.248 0.192 13.272 ;
    END
  END o[54]
  PIN o[55]
    DIRECTION OUTPUT ;
    USE SIGNAL ;
    PORT
      LAYER M4 ;
        RECT  0 13.392 0.192 13.416 ;
    END
  END o[55]
  PIN o[56]
    DIRECTION OUTPUT ;
    USE SIGNAL ;
    PORT
      LAYER M4 ;
        RECT  0 13.584 0.192 13.608 ;
    END
  END o[56]
  PIN o[57]
    DIRECTION OUTPUT ;
    USE SIGNAL ;
    PORT
      LAYER M4 ;
        RECT  0 13.728 0.192 13.752 ;
    END
  END o[57]
  PIN o[58]
    DIRECTION OUTPUT ;
    USE SIGNAL ;
    PORT
      LAYER M4 ;
        RECT  0 13.92 0.192 13.944 ;
    END
  END o[58]
  PIN o[59]
    DIRECTION OUTPUT ;
    USE SIGNAL ;
    PORT
      LAYER M4 ;
        RECT  0 14.064 0.192 14.088 ;
    END
  END o[59]
  PIN o[5]
    DIRECTION OUTPUT ;
    USE SIGNAL ;
    PORT
      LAYER M4 ;
        RECT  0 5.232 0.192 5.256 ;
    END
  END o[5]
  PIN o[60]
    DIRECTION OUTPUT ;
    USE SIGNAL ;
    PORT
      LAYER M4 ;
        RECT  0 14.208 0.192 14.232 ;
    END
  END o[60]
  PIN o[61]
    DIRECTION OUTPUT ;
    USE SIGNAL ;
    PORT
      LAYER M4 ;
        RECT  0 14.4 0.192 14.424 ;
    END
  END o[61]
  PIN o[62]
    DIRECTION OUTPUT ;
    USE SIGNAL ;
    PORT
      LAYER M4 ;
        RECT  0 14.544 0.192 14.568 ;
    END
  END o[62]
  PIN o[63]
    DIRECTION OUTPUT ;
    USE SIGNAL ;
    PORT
      LAYER M4 ;
        RECT  0 14.736 0.192 14.76 ;
    END
  END o[63]
  PIN o[64]
    DIRECTION OUTPUT ;
    USE SIGNAL ;
    PORT
      LAYER M4 ;
        RECT  0 14.88 0.192 14.904 ;
    END
  END o[64]
  PIN o[65]
    DIRECTION OUTPUT ;
    USE SIGNAL ;
    PORT
      LAYER M4 ;
        RECT  0 15.024 0.192 15.048 ;
    END
  END o[65]
  PIN o[66]
    DIRECTION OUTPUT ;
    USE SIGNAL ;
    PORT
      LAYER M4 ;
        RECT  0 15.216 0.192 15.24 ;
    END
  END o[66]
  PIN o[67]
    DIRECTION OUTPUT ;
    USE SIGNAL ;
    PORT
      LAYER M4 ;
        RECT  0 15.36 0.192 15.384 ;
    END
  END o[67]
  PIN o[68]
    DIRECTION OUTPUT ;
    USE SIGNAL ;
    PORT
      LAYER M4 ;
        RECT  0 15.552 0.192 15.576 ;
    END
  END o[68]
  PIN o[69]
    DIRECTION OUTPUT ;
    USE SIGNAL ;
    PORT
      LAYER M4 ;
        RECT  0 15.696 0.192 15.72 ;
    END
  END o[69]
  PIN o[6]
    DIRECTION OUTPUT ;
    USE SIGNAL ;
    PORT
      LAYER M4 ;
        RECT  0 5.376 0.192 5.4 ;
    END
  END o[6]
  PIN o[70]
    DIRECTION OUTPUT ;
    USE SIGNAL ;
    PORT
      LAYER M4 ;
        RECT  0 15.84 0.192 15.864 ;
    END
  END o[70]
  PIN o[71]
    DIRECTION OUTPUT ;
    USE SIGNAL ;
    PORT
      LAYER M4 ;
        RECT  0 16.032 0.192 16.056 ;
    END
  END o[71]
  PIN o[72]
    DIRECTION OUTPUT ;
    USE SIGNAL ;
    PORT
      LAYER M4 ;
        RECT  0 16.176 0.192 16.2 ;
    END
  END o[72]
  PIN o[73]
    DIRECTION OUTPUT ;
    USE SIGNAL ;
    PORT
      LAYER M4 ;
        RECT  0 16.368 0.192 16.392 ;
    END
  END o[73]
  PIN o[74]
    DIRECTION OUTPUT ;
    USE SIGNAL ;
    PORT
      LAYER M4 ;
        RECT  0 16.512 0.192 16.536 ;
    END
  END o[74]
  PIN o[75]
    DIRECTION OUTPUT ;
    USE SIGNAL ;
    PORT
      LAYER M4 ;
        RECT  0 16.704 0.192 16.728 ;
    END
  END o[75]
  PIN o[76]
    DIRECTION OUTPUT ;
    USE SIGNAL ;
    PORT
      LAYER M4 ;
        RECT  0 16.848 0.192 16.872 ;
    END
  END o[76]
  PIN o[77]
    DIRECTION OUTPUT ;
    USE SIGNAL ;
    PORT
      LAYER M4 ;
        RECT  0 16.992 0.192 17.016 ;
    END
  END o[77]
  PIN o[78]
    DIRECTION OUTPUT ;
    USE SIGNAL ;
    PORT
      LAYER M4 ;
        RECT  0 17.184 0.192 17.208 ;
    END
  END o[78]
  PIN o[79]
    DIRECTION OUTPUT ;
    USE SIGNAL ;
    PORT
      LAYER M4 ;
        RECT  0 17.328 0.192 17.352 ;
    END
  END o[79]
  PIN o[7]
    DIRECTION OUTPUT ;
    USE SIGNAL ;
    PORT
      LAYER M4 ;
        RECT  0 5.568 0.192 5.592 ;
    END
  END o[7]
  PIN o[80]
    DIRECTION OUTPUT ;
    USE SIGNAL ;
    PORT
      LAYER M4 ;
        RECT  0 17.52 0.192 17.544 ;
    END
  END o[80]
  PIN o[81]
    DIRECTION OUTPUT ;
    USE SIGNAL ;
    PORT
      LAYER M4 ;
        RECT  0 17.664 0.192 17.688 ;
    END
  END o[81]
  PIN o[82]
    DIRECTION OUTPUT ;
    USE SIGNAL ;
    PORT
      LAYER M4 ;
        RECT  0 17.808 0.192 17.832 ;
    END
  END o[82]
  PIN o[83]
    DIRECTION OUTPUT ;
    USE SIGNAL ;
    PORT
      LAYER M4 ;
        RECT  0 18 0.192 18.024 ;
    END
  END o[83]
  PIN o[84]
    DIRECTION OUTPUT ;
    USE SIGNAL ;
    PORT
      LAYER M4 ;
        RECT  0 18.144 0.192 18.168 ;
    END
  END o[84]
  PIN o[85]
    DIRECTION OUTPUT ;
    USE SIGNAL ;
    PORT
      LAYER M4 ;
        RECT  0 18.336 0.192 18.36 ;
    END
  END o[85]
  PIN o[86]
    DIRECTION OUTPUT ;
    USE SIGNAL ;
    PORT
      LAYER M4 ;
        RECT  0 18.48 0.192 18.504 ;
    END
  END o[86]
  PIN o[87]
    DIRECTION OUTPUT ;
    USE SIGNAL ;
    PORT
      LAYER M4 ;
        RECT  0 18.624 0.192 18.648 ;
    END
  END o[87]
  PIN o[88]
    DIRECTION OUTPUT ;
    USE SIGNAL ;
    PORT
      LAYER M4 ;
        RECT  0 18.816 0.192 18.84 ;
    END
  END o[88]
  PIN o[89]
    DIRECTION OUTPUT ;
    USE SIGNAL ;
    PORT
      LAYER M4 ;
        RECT  0 18.96 0.192 18.984 ;
    END
  END o[89]
  PIN o[8]
    DIRECTION OUTPUT ;
    USE SIGNAL ;
    PORT
      LAYER M4 ;
        RECT  0 5.712 0.192 5.736 ;
    END
  END o[8]
  PIN o[90]
    DIRECTION OUTPUT ;
    USE SIGNAL ;
    PORT
      LAYER M4 ;
        RECT  0 19.152 0.192 19.176 ;
    END
  END o[90]
  PIN o[91]
    DIRECTION OUTPUT ;
    USE SIGNAL ;
    PORT
      LAYER M4 ;
        RECT  0 19.296 0.192 19.32 ;
    END
  END o[91]
  PIN o[92]
    DIRECTION OUTPUT ;
    USE SIGNAL ;
    PORT
      LAYER M4 ;
        RECT  0 19.44 0.192 19.464 ;
    END
  END o[92]
  PIN o[93]
    DIRECTION OUTPUT ;
    USE SIGNAL ;
    PORT
      LAYER M4 ;
        RECT  0 19.632 0.192 19.656 ;
    END
  END o[93]
  PIN o[94]
    DIRECTION OUTPUT ;
    USE SIGNAL ;
    PORT
      LAYER M4 ;
        RECT  0 19.776 0.192 19.8 ;
    END
  END o[94]
  PIN o[95]
    DIRECTION OUTPUT ;
    USE SIGNAL ;
    PORT
      LAYER M4 ;
        RECT  0 19.968 0.192 19.992 ;
    END
  END o[95]
  PIN o[96]
    DIRECTION OUTPUT ;
    USE SIGNAL ;
    PORT
      LAYER M4 ;
        RECT  0 20.112 0.192 20.136 ;
    END
  END o[96]
  PIN o[97]
    DIRECTION OUTPUT ;
    USE SIGNAL ;
    PORT
      LAYER M4 ;
        RECT  0 20.304 0.192 20.328 ;
    END
  END o[97]
  PIN o[98]
    DIRECTION OUTPUT ;
    USE SIGNAL ;
    PORT
      LAYER M4 ;
        RECT  0 20.448 0.192 20.472 ;
    END
  END o[98]
  PIN o[99]
    DIRECTION OUTPUT ;
    USE SIGNAL ;
    PORT
      LAYER M4 ;
        RECT  0 20.592 0.192 20.616 ;
    END
  END o[99]
  PIN o[9]
    DIRECTION OUTPUT ;
    USE SIGNAL ;
    PORT
      LAYER M4 ;
        RECT  0 5.904 0.192 5.928 ;
    END
  END o[9]
  PIN rs[0]
    DIRECTION INPUT ;
    USE SIGNAL ;
    PORT
      LAYER M5 ;
        RECT  62.64 0 62.664 0.192 ;
    END
    PORT
      LAYER M5 ;
        RECT  62.64 0.144 62.664 0.611 ;
    END
  END rs[0]
  PIN VDD
    DIRECTION INOUT ;
    USE POWER ;
    PORT
      LAYER M5 ;
        RECT  83.592 2.151 83.712 90.729 ;
        RECT  80.892 2.151 81.012 90.729 ;
        RECT  78.192 2.151 78.312 90.729 ;
        RECT  75.492 2.151 75.612 90.729 ;
        RECT  72.792 2.151 72.912 90.729 ;
        RECT  70.092 2.151 70.212 90.729 ;
        RECT  67.392 2.151 67.512 90.729 ;
        RECT  64.692 2.151 64.812 90.729 ;
        RECT  61.992 2.151 62.112 90.729 ;
        RECT  59.292 2.151 59.412 90.729 ;
        RECT  56.592 2.151 56.712 90.729 ;
        RECT  53.892 2.151 54.012 90.729 ;
        RECT  51.192 2.151 51.312 90.729 ;
        RECT  48.492 2.151 48.612 90.729 ;
        RECT  45.792 2.151 45.912 90.729 ;
        RECT  43.092 2.151 43.212 90.729 ;
        RECT  40.392 2.151 40.512 90.729 ;
        RECT  37.692 2.151 37.812 90.729 ;
        RECT  34.992 2.151 35.112 90.729 ;
        RECT  32.292 2.151 32.412 90.729 ;
        RECT  29.592 2.151 29.712 90.729 ;
        RECT  26.892 2.151 27.012 90.729 ;
        RECT  24.192 2.151 24.312 90.729 ;
        RECT  21.492 2.151 21.612 90.729 ;
        RECT  18.792 2.151 18.912 90.729 ;
        RECT  16.092 2.151 16.212 90.729 ;
        RECT  13.392 2.151 13.512 90.729 ;
        RECT  10.692 2.151 10.812 90.729 ;
        RECT  7.992 2.151 8.112 90.729 ;
        RECT  5.292 2.151 5.412 90.729 ;
        RECT  2.592 2.151 2.712 90.729 ;
    END
  END VDD
  PIN VSS
    DIRECTION INOUT ;
    USE GROUND ;
    PORT
      LAYER M5 ;
        RECT  83.4 2.137 83.52 90.743 ;
        RECT  80.7 2.137 80.82 90.743 ;
        RECT  78 2.137 78.12 90.743 ;
        RECT  75.3 2.137 75.42 90.743 ;
        RECT  72.6 2.137 72.72 90.743 ;
        RECT  69.9 2.137 70.02 90.743 ;
        RECT  67.2 2.137 67.32 90.743 ;
        RECT  64.5 2.137 64.62 90.743 ;
        RECT  61.8 2.137 61.92 90.743 ;
        RECT  59.1 2.137 59.22 90.743 ;
        RECT  56.4 2.137 56.52 90.743 ;
        RECT  53.7 2.137 53.82 90.743 ;
        RECT  51 2.137 51.12 90.743 ;
        RECT  48.3 2.137 48.42 90.743 ;
        RECT  45.6 2.137 45.72 90.743 ;
        RECT  42.9 2.137 43.02 90.743 ;
        RECT  40.2 2.137 40.32 90.743 ;
        RECT  37.5 2.137 37.62 90.743 ;
        RECT  34.8 2.137 34.92 90.743 ;
        RECT  32.1 2.137 32.22 90.743 ;
        RECT  29.4 2.137 29.52 90.743 ;
        RECT  26.7 2.137 26.82 90.743 ;
        RECT  24 2.137 24.12 90.743 ;
        RECT  21.3 2.137 21.42 90.743 ;
        RECT  18.6 2.137 18.72 90.743 ;
        RECT  15.9 2.137 16.02 90.743 ;
        RECT  13.2 2.137 13.32 90.743 ;
        RECT  10.5 2.137 10.62 90.743 ;
        RECT  7.8 2.137 7.92 90.743 ;
        RECT  5.1 2.137 5.22 90.743 ;
        RECT  2.4 2.137 2.52 90.743 ;
    END
  END VSS
  # OT_OBS_CLOSED layer=M5 d_um=1.536 added=934
  OBS
    LAYER RVTN ;
     RECT  2.16 2.16 84.24 2.295 ;
     RECT  2.16 2.565 84.24 2.835 ;
     RECT  2.16 3.105 84.24 3.375 ;
     RECT  2.16 3.645 84.24 3.915 ;
     RECT  2.16 4.185 84.24 4.455 ;
     RECT  2.16 4.725 84.24 4.995 ;
     RECT  2.16 5.265 84.24 5.535 ;
     RECT  2.16 5.805 84.24 6.075 ;
     RECT  2.16 6.345 84.24 6.615 ;
     RECT  2.16 6.885 84.24 7.155 ;
     RECT  2.16 7.425 84.24 7.695 ;
     RECT  2.16 7.965 84.24 8.235 ;
     RECT  2.16 8.505 84.24 8.775 ;
     RECT  2.16 9.045 84.24 9.315 ;
     RECT  2.16 9.585 84.24 9.855 ;
     RECT  2.16 10.125 84.24 10.395 ;
     RECT  2.16 10.665 84.24 10.935 ;
     RECT  2.16 11.205 84.24 11.475 ;
     RECT  2.16 11.745 84.24 12.015 ;
     RECT  2.16 12.285 84.24 12.555 ;
     RECT  2.16 12.825 84.24 13.095 ;
     RECT  2.16 13.365 84.24 13.635 ;
     RECT  2.16 13.905 84.24 14.175 ;
     RECT  2.16 14.445 84.24 14.715 ;
     RECT  2.16 14.985 84.24 15.255 ;
     RECT  2.16 15.525 84.24 15.795 ;
     RECT  2.16 16.065 84.24 16.335 ;
     RECT  2.16 16.605 84.24 16.875 ;
     RECT  2.16 17.145 84.24 17.415 ;
     RECT  2.16 17.685 84.24 17.955 ;
     RECT  2.16 18.225 84.24 18.495 ;
     RECT  2.16 18.765 84.24 19.035 ;
     RECT  2.16 19.305 84.24 19.575 ;
     RECT  2.16 19.845 84.24 20.115 ;
     RECT  2.16 20.385 84.24 20.655 ;
     RECT  2.16 20.925 84.24 21.195 ;
     RECT  2.16 21.465 84.24 21.735 ;
     RECT  2.16 22.005 84.24 22.275 ;
     RECT  2.16 22.545 84.24 22.815 ;
     RECT  2.16 23.085 84.24 23.355 ;
     RECT  2.16 23.625 84.24 23.895 ;
     RECT  2.16 24.165 84.24 24.435 ;
     RECT  2.16 24.705 84.24 24.975 ;
     RECT  2.16 25.245 84.24 25.515 ;
     RECT  2.16 25.785 84.24 26.055 ;
     RECT  2.16 26.325 84.24 26.595 ;
     RECT  2.16 26.865 84.24 27.135 ;
     RECT  2.16 27.405 84.24 27.675 ;
     RECT  2.16 27.945 84.24 28.215 ;
     RECT  2.16 28.485 84.24 28.755 ;
     RECT  2.16 29.025 84.24 29.295 ;
     RECT  2.16 29.565 84.24 29.835 ;
     RECT  2.16 30.105 84.24 30.375 ;
     RECT  2.16 30.645 84.24 30.915 ;
     RECT  2.16 31.185 84.24 31.455 ;
     RECT  2.16 31.725 84.24 31.995 ;
     RECT  2.16 32.265 84.24 32.535 ;
     RECT  2.16 32.805 84.24 33.075 ;
     RECT  2.16 33.345 84.24 33.615 ;
     RECT  2.16 33.885 84.24 34.155 ;
     RECT  2.16 34.425 84.24 34.695 ;
     RECT  2.16 34.965 84.24 35.235 ;
     RECT  2.16 35.505 84.24 35.775 ;
     RECT  2.16 36.045 84.24 36.315 ;
     RECT  2.16 36.585 84.24 36.855 ;
     RECT  2.16 37.125 84.24 37.395 ;
     RECT  2.16 37.665 84.24 37.935 ;
     RECT  2.16 38.205 84.24 38.475 ;
     RECT  2.16 38.745 84.24 39.015 ;
     RECT  2.16 39.285 84.24 39.555 ;
     RECT  2.16 39.825 84.24 40.095 ;
     RECT  2.16 40.365 84.24 40.635 ;
     RECT  2.16 40.905 84.24 41.175 ;
     RECT  2.16 41.445 84.24 41.715 ;
     RECT  2.16 41.985 84.24 42.255 ;
     RECT  2.16 42.525 84.24 42.795 ;
     RECT  2.16 43.065 84.24 43.335 ;
     RECT  2.16 43.605 84.24 43.875 ;
     RECT  2.16 44.145 84.24 44.415 ;
     RECT  2.16 44.685 84.24 44.955 ;
     RECT  2.16 45.225 84.24 45.495 ;
     RECT  2.16 45.765 84.24 46.035 ;
     RECT  2.16 46.305 84.24 46.575 ;
     RECT  2.16 46.845 84.24 47.115 ;
     RECT  2.16 47.385 84.24 47.655 ;
     RECT  2.16 47.925 84.24 48.195 ;
     RECT  2.16 48.465 84.24 48.735 ;
     RECT  2.16 49.005 84.24 49.275 ;
     RECT  2.16 49.545 84.24 49.815 ;
     RECT  2.16 50.085 84.24 50.355 ;
     RECT  2.16 50.625 84.24 50.895 ;
     RECT  2.16 51.165 84.24 51.435 ;
     RECT  2.16 51.705 84.24 51.975 ;
     RECT  2.16 52.245 84.24 52.515 ;
     RECT  2.16 52.785 84.24 53.055 ;
     RECT  2.16 53.325 84.24 53.595 ;
     RECT  2.16 53.865 84.24 54.135 ;
     RECT  2.16 54.405 84.24 54.675 ;
     RECT  2.16 54.945 84.24 55.215 ;
     RECT  2.16 55.485 84.24 55.755 ;
     RECT  2.16 56.025 84.24 56.295 ;
     RECT  2.16 56.565 84.24 56.835 ;
     RECT  2.16 57.105 84.24 57.375 ;
     RECT  2.16 57.645 84.24 57.915 ;
     RECT  2.16 58.185 84.24 58.455 ;
     RECT  2.16 58.725 84.24 58.995 ;
     RECT  2.16 59.265 84.24 59.535 ;
     RECT  2.16 59.805 84.24 60.075 ;
     RECT  2.16 60.345 84.24 60.615 ;
     RECT  2.16 60.885 84.24 61.155 ;
     RECT  2.16 61.425 84.24 61.695 ;
     RECT  2.16 61.965 84.24 62.235 ;
     RECT  2.16 62.505 84.24 62.775 ;
     RECT  2.16 63.045 84.24 63.315 ;
     RECT  2.16 63.585 84.24 63.855 ;
     RECT  2.16 64.125 84.24 64.395 ;
     RECT  2.16 64.665 84.24 64.935 ;
     RECT  2.16 65.205 84.24 65.475 ;
     RECT  2.16 65.745 84.24 66.015 ;
     RECT  2.16 66.285 84.24 66.555 ;
     RECT  2.16 66.825 84.24 67.095 ;
     RECT  2.16 67.365 84.24 67.635 ;
     RECT  2.16 67.905 84.24 68.175 ;
     RECT  2.16 68.445 84.24 68.715 ;
     RECT  2.16 68.985 84.24 69.255 ;
     RECT  2.16 69.525 84.24 69.795 ;
     RECT  2.16 70.065 84.24 70.335 ;
     RECT  2.16 70.605 84.24 70.875 ;
     RECT  2.16 71.145 84.24 71.415 ;
     RECT  2.16 71.685 84.24 71.955 ;
     RECT  2.16 72.225 84.24 72.495 ;
     RECT  2.16 72.765 84.24 73.035 ;
     RECT  2.16 73.305 84.24 73.575 ;
     RECT  2.16 73.845 84.24 74.115 ;
     RECT  2.16 74.385 84.24 74.655 ;
     RECT  2.16 74.925 84.24 75.195 ;
     RECT  2.16 75.465 84.24 75.735 ;
     RECT  2.16 76.005 84.24 76.275 ;
     RECT  2.16 76.545 84.24 76.815 ;
     RECT  2.16 77.085 84.24 77.355 ;
     RECT  2.16 77.625 84.24 77.895 ;
     RECT  2.16 78.165 84.24 78.435 ;
     RECT  2.16 78.705 84.24 78.975 ;
     RECT  2.16 79.245 84.24 79.515 ;
     RECT  2.16 79.785 84.24 80.055 ;
     RECT  2.16 80.325 84.24 80.595 ;
     RECT  2.16 80.865 84.24 81.135 ;
     RECT  2.16 81.405 84.24 81.675 ;
     RECT  2.16 81.945 84.24 82.215 ;
     RECT  2.16 82.485 84.24 82.755 ;
     RECT  2.16 83.025 84.24 83.295 ;
     RECT  2.16 83.565 84.24 83.835 ;
     RECT  2.16 84.105 84.24 84.375 ;
     RECT  2.16 84.645 84.24 84.915 ;
     RECT  2.16 85.185 84.24 85.455 ;
     RECT  2.16 85.725 84.24 85.995 ;
     RECT  2.16 86.265 84.24 86.535 ;
     RECT  2.16 86.805 84.24 87.075 ;
     RECT  2.16 87.345 84.24 87.615 ;
     RECT  2.16 87.885 84.24 88.155 ;
     RECT  2.16 88.425 84.24 88.695 ;
     RECT  2.16 88.965 84.24 89.235 ;
     RECT  2.16 89.505 84.24 89.775 ;
     RECT  2.16 90.045 84.24 90.315 ;
     RECT  2.16 90.585 84.24 90.72 ;
    LAYER RVTP ;
     RECT  2.16 2.295 84.24 2.565 ;
     RECT  2.16 2.835 84.24 3.105 ;
     RECT  2.16 3.375 84.24 3.645 ;
     RECT  2.16 3.915 84.24 4.185 ;
     RECT  2.16 4.455 84.24 4.725 ;
     RECT  2.16 4.995 84.24 5.265 ;
     RECT  2.16 5.535 84.24 5.805 ;
     RECT  2.16 6.075 84.24 6.345 ;
     RECT  2.16 6.615 84.24 6.885 ;
     RECT  2.16 7.155 84.24 7.425 ;
     RECT  2.16 7.695 84.24 7.965 ;
     RECT  2.16 8.235 84.24 8.505 ;
     RECT  2.16 8.775 84.24 9.045 ;
     RECT  2.16 9.315 84.24 9.585 ;
     RECT  2.16 9.855 84.24 10.125 ;
     RECT  2.16 10.395 84.24 10.665 ;
     RECT  2.16 10.935 84.24 11.205 ;
     RECT  2.16 11.475 84.24 11.745 ;
     RECT  2.16 12.015 84.24 12.285 ;
     RECT  2.16 12.555 84.24 12.825 ;
     RECT  2.16 13.095 84.24 13.365 ;
     RECT  2.16 13.635 84.24 13.905 ;
     RECT  2.16 14.175 84.24 14.445 ;
     RECT  2.16 14.715 84.24 14.985 ;
     RECT  2.16 15.255 84.24 15.525 ;
     RECT  2.16 15.795 84.24 16.065 ;
     RECT  2.16 16.335 84.24 16.605 ;
     RECT  2.16 16.875 84.24 17.145 ;
     RECT  2.16 17.415 84.24 17.685 ;
     RECT  2.16 17.955 84.24 18.225 ;
     RECT  2.16 18.495 84.24 18.765 ;
     RECT  2.16 19.035 84.24 19.305 ;
     RECT  2.16 19.575 84.24 19.845 ;
     RECT  2.16 20.115 84.24 20.385 ;
     RECT  2.16 20.655 84.24 20.925 ;
     RECT  2.16 21.195 84.24 21.465 ;
     RECT  2.16 21.735 84.24 22.005 ;
     RECT  2.16 22.275 84.24 22.545 ;
     RECT  2.16 22.815 84.24 23.085 ;
     RECT  2.16 23.355 84.24 23.625 ;
     RECT  2.16 23.895 84.24 24.165 ;
     RECT  2.16 24.435 84.24 24.705 ;
     RECT  2.16 24.975 84.24 25.245 ;
     RECT  2.16 25.515 84.24 25.785 ;
     RECT  2.16 26.055 84.24 26.325 ;
     RECT  2.16 26.595 84.24 26.865 ;
     RECT  2.16 27.135 84.24 27.405 ;
     RECT  2.16 27.675 84.24 27.945 ;
     RECT  2.16 28.215 84.24 28.485 ;
     RECT  2.16 28.755 84.24 29.025 ;
     RECT  2.16 29.295 84.24 29.565 ;
     RECT  2.16 29.835 84.24 30.105 ;
     RECT  2.16 30.375 84.24 30.645 ;
     RECT  2.16 30.915 84.24 31.185 ;
     RECT  2.16 31.455 84.24 31.725 ;
     RECT  2.16 31.995 84.24 32.265 ;
     RECT  2.16 32.535 84.24 32.805 ;
     RECT  2.16 33.075 84.24 33.345 ;
     RECT  2.16 33.615 84.24 33.885 ;
     RECT  2.16 34.155 84.24 34.425 ;
     RECT  2.16 34.695 84.24 34.965 ;
     RECT  2.16 35.235 84.24 35.505 ;
     RECT  2.16 35.775 84.24 36.045 ;
     RECT  2.16 36.315 84.24 36.585 ;
     RECT  2.16 36.855 84.24 37.125 ;
     RECT  2.16 37.395 84.24 37.665 ;
     RECT  2.16 37.935 84.24 38.205 ;
     RECT  2.16 38.475 84.24 38.745 ;
     RECT  2.16 39.015 84.24 39.285 ;
     RECT  2.16 39.555 84.24 39.825 ;
     RECT  2.16 40.095 84.24 40.365 ;
     RECT  2.16 40.635 84.24 40.905 ;
     RECT  2.16 41.175 84.24 41.445 ;
     RECT  2.16 41.715 84.24 41.985 ;
     RECT  2.16 42.255 84.24 42.525 ;
     RECT  2.16 42.795 84.24 43.065 ;
     RECT  2.16 43.335 84.24 43.605 ;
     RECT  2.16 43.875 84.24 44.145 ;
     RECT  2.16 44.415 84.24 44.685 ;
     RECT  2.16 44.955 84.24 45.225 ;
     RECT  2.16 45.495 84.24 45.765 ;
     RECT  2.16 46.035 84.24 46.305 ;
     RECT  2.16 46.575 84.24 46.845 ;
     RECT  2.16 47.115 84.24 47.385 ;
     RECT  2.16 47.655 84.24 47.925 ;
     RECT  2.16 48.195 84.24 48.465 ;
     RECT  2.16 48.735 84.24 49.005 ;
     RECT  2.16 49.275 84.24 49.545 ;
     RECT  2.16 49.815 84.24 50.085 ;
     RECT  2.16 50.355 84.24 50.625 ;
     RECT  2.16 50.895 84.24 51.165 ;
     RECT  2.16 51.435 84.24 51.705 ;
     RECT  2.16 51.975 84.24 52.245 ;
     RECT  2.16 52.515 84.24 52.785 ;
     RECT  2.16 53.055 84.24 53.325 ;
     RECT  2.16 53.595 84.24 53.865 ;
     RECT  2.16 54.135 84.24 54.405 ;
     RECT  2.16 54.675 84.24 54.945 ;
     RECT  2.16 55.215 84.24 55.485 ;
     RECT  2.16 55.755 84.24 56.025 ;
     RECT  2.16 56.295 84.24 56.565 ;
     RECT  2.16 56.835 84.24 57.105 ;
     RECT  2.16 57.375 84.24 57.645 ;
     RECT  2.16 57.915 84.24 58.185 ;
     RECT  2.16 58.455 84.24 58.725 ;
     RECT  2.16 58.995 84.24 59.265 ;
     RECT  2.16 59.535 84.24 59.805 ;
     RECT  2.16 60.075 84.24 60.345 ;
     RECT  2.16 60.615 84.24 60.885 ;
     RECT  2.16 61.155 84.24 61.425 ;
     RECT  2.16 61.695 84.24 61.965 ;
     RECT  2.16 62.235 84.24 62.505 ;
     RECT  2.16 62.775 84.24 63.045 ;
     RECT  2.16 63.315 84.24 63.585 ;
     RECT  2.16 63.855 84.24 64.125 ;
     RECT  2.16 64.395 84.24 64.665 ;
     RECT  2.16 64.935 84.24 65.205 ;
     RECT  2.16 65.475 84.24 65.745 ;
     RECT  2.16 66.015 84.24 66.285 ;
     RECT  2.16 66.555 84.24 66.825 ;
     RECT  2.16 67.095 84.24 67.365 ;
     RECT  2.16 67.635 84.24 67.905 ;
     RECT  2.16 68.175 84.24 68.445 ;
     RECT  2.16 68.715 84.24 68.985 ;
     RECT  2.16 69.255 84.24 69.525 ;
     RECT  2.16 69.795 84.24 70.065 ;
     RECT  2.16 70.335 84.24 70.605 ;
     RECT  2.16 70.875 84.24 71.145 ;
     RECT  2.16 71.415 84.24 71.685 ;
     RECT  2.16 71.955 84.24 72.225 ;
     RECT  2.16 72.495 84.24 72.765 ;
     RECT  2.16 73.035 84.24 73.305 ;
     RECT  2.16 73.575 84.24 73.845 ;
     RECT  2.16 74.115 84.24 74.385 ;
     RECT  2.16 74.655 84.24 74.925 ;
     RECT  2.16 75.195 84.24 75.465 ;
     RECT  2.16 75.735 84.24 76.005 ;
     RECT  2.16 76.275 84.24 76.545 ;
     RECT  2.16 76.815 84.24 77.085 ;
     RECT  2.16 77.355 84.24 77.625 ;
     RECT  2.16 77.895 84.24 78.165 ;
     RECT  2.16 78.435 84.24 78.705 ;
     RECT  2.16 78.975 84.24 79.245 ;
     RECT  2.16 79.515 84.24 79.785 ;
     RECT  2.16 80.055 84.24 80.325 ;
     RECT  2.16 80.595 84.24 80.865 ;
     RECT  2.16 81.135 84.24 81.405 ;
     RECT  2.16 81.675 84.24 81.945 ;
     RECT  2.16 82.215 84.24 82.485 ;
     RECT  2.16 82.755 84.24 83.025 ;
     RECT  2.16 83.295 84.24 83.565 ;
     RECT  2.16 83.835 84.24 84.105 ;
     RECT  2.16 84.375 84.24 84.645 ;
     RECT  2.16 84.915 84.24 85.185 ;
     RECT  2.16 85.455 84.24 85.725 ;
     RECT  2.16 85.995 84.24 86.265 ;
     RECT  2.16 86.535 84.24 86.805 ;
     RECT  2.16 87.075 84.24 87.345 ;
     RECT  2.16 87.615 84.24 87.885 ;
     RECT  2.16 88.155 84.24 88.425 ;
     RECT  2.16 88.695 84.24 88.965 ;
     RECT  2.16 89.235 84.24 89.505 ;
     RECT  2.16 89.775 84.24 90.045 ;
     RECT  2.16 90.315 84.24 90.585 ;
    LAYER M1 ;
     RECT  2.16 2.151 84.24 90.729 ;
    LAYER M2 ;
     RECT  0.211 18.126 0.247 18.144 ;
     RECT  0.211 56.376 0.247 57.564 ;
     RECT  0.211 68.886 0.247 68.904 ;
     RECT  0.211 40.806 0.463 40.824 ;
     RECT  0.427 33.552 0.499 33.57 ;
     RECT  0.463 40.806 0.499 41.13 ;
     RECT  0.463 12.024 0.535 12.042 ;
     RECT  0.463 13.068 0.535 13.086 ;
     RECT  0.211 21.636 0.535 21.654 ;
     RECT  0.211 23.256 0.535 23.274 ;
     RECT  0.211 24.606 0.535 24.624 ;
     RECT  0.499 33.516 0.535 33.57 ;
     RECT  0.211 37.566 0.535 37.584 ;
     RECT  0.499 40.806 0.535 41.544 ;
     RECT  0.499 47.286 0.535 47.304 ;
     RECT  0.499 76.716 0.535 76.734 ;
     RECT  0.535 11.916 0.563 13.086 ;
     RECT  0.211 60.786 1.175 61.218 ;
     RECT  0.211 6.246 2.16 6.804 ;
     RECT  0.535 8.478 2.16 8.496 ;
     RECT  1.975 9.9 2.16 9.918 ;
     RECT  0.563 11.916 2.16 12.474 ;
     RECT  0.535 14.148 2.16 14.166 ;
     RECT  0.247 18.126 2.16 18.414 ;
     RECT  0.535 20.898 2.16 23.274 ;
     RECT  0.535 24.606 2.16 26.046 ;
     RECT  0.211 28.926 2.16 28.944 ;
     RECT  0.535 32.436 2.16 33.57 ;
     RECT  0.535 34.596 2.16 34.614 ;
     RECT  0.535 37.566 2.16 37.962 ;
     RECT  0.211 38.718 2.16 38.736 ;
     RECT  0.535 40.806 2.16 43.254 ;
     RECT  0.535 47.196 2.16 47.844 ;
     RECT  0.535 54.486 2.16 54.504 ;
     RECT  0.535 55.26 2.16 55.278 ;
     RECT  0.247 56.196 2.16 58.104 ;
     RECT  0.211 59.706 2.16 59.724 ;
     RECT  1.175 60.786 2.16 61.146 ;
     RECT  0.211 62.676 2.16 62.694 ;
     RECT  0.247 68.886 2.16 68.94 ;
     RECT  0.211 70.506 2.16 71.064 ;
     RECT  0.535 74.016 2.16 74.574 ;
     RECT  0.535 76.248 2.16 77.274 ;
     RECT  0.535 78.066 2.16 78.624 ;
     RECT  0.211 82.026 2.16 82.044 ;
     RECT  0.211 83.196 2.16 83.754 ;
     RECT  0.211 89.046 2.16 89.064 ;
     RECT  2.16 2.151 31.891 90.729 ;
     RECT  31.891 2.106 62.231 90.729 ;
     RECT  62.231 2.151 84.24 90.729 ;
     RECT  84.24 4.5 84.407 88.722 ;
     RECT  84.407 4.968 84.443 30.438 ;
     RECT  84.407 31.428 84.443 41.166 ;
     RECT  84.407 41.958 84.443 42.246 ;
     RECT  84.407 44.658 84.443 52.848 ;
     RECT  84.407 63.828 84.443 68.778 ;
     RECT  84.407 70.038 84.443 78.426 ;
     RECT  84.407 79.56 84.443 88.722 ;
     RECT  84.443 4.968 84.479 6.714 ;
     RECT  84.443 8.478 84.479 26.82 ;
     RECT  84.443 27.648 84.479 29.862 ;
     RECT  84.443 38.484 84.479 41.166 ;
     RECT  84.443 44.658 84.479 48.726 ;
     RECT  84.443 49.518 84.479 52.848 ;
     RECT  84.443 63.828 84.479 68.274 ;
     RECT  84.479 13.878 84.911 24.156 ;
     RECT  84.479 24.948 84.911 26.82 ;
     RECT  84.407 53.676 84.911 63.036 ;
     RECT  84.479 4.968 84.947 6.606 ;
     RECT  84.443 7.668 84.947 7.686 ;
     RECT  84.479 9.018 84.947 13.086 ;
     RECT  84.911 13.878 84.947 18.216 ;
     RECT  84.911 19.08 84.947 20.916 ;
     RECT  84.911 21.708 84.947 23.652 ;
     RECT  84.911 25.218 84.947 26.82 ;
     RECT  84.479 27.648 84.947 27.666 ;
     RECT  84.479 28.458 84.947 29.862 ;
     RECT  84.443 31.428 84.947 31.518 ;
     RECT  84.443 32.274 84.947 34.992 ;
     RECT  84.443 35.748 84.947 36.846 ;
     RECT  84.443 37.602 84.947 37.62 ;
     RECT  84.479 38.52 84.947 41.166 ;
     RECT  84.443 41.994 84.947 42.246 ;
     RECT  84.407 43.11 84.947 43.866 ;
     RECT  84.479 44.658 84.947 46.566 ;
     RECT  84.479 47.43 84.947 48.726 ;
     RECT  84.479 49.788 84.947 52.848 ;
     RECT  84.911 53.676 84.947 59.796 ;
     RECT  84.911 60.588 84.947 63.036 ;
     RECT  84.479 63.828 84.947 65.196 ;
     RECT  84.479 65.988 84.947 68.274 ;
     RECT  84.443 70.038 84.947 71.136 ;
     RECT  84.443 71.928 84.947 72.216 ;
     RECT  84.443 72.972 84.947 73.062 ;
     RECT  84.443 73.818 84.947 74.646 ;
     RECT  84.443 75.438 84.947 75.456 ;
     RECT  84.443 76.32 84.947 78.264 ;
     RECT  84.443 79.56 84.947 85.446 ;
     RECT  84.443 86.238 84.947 86.796 ;
     RECT  84.443 87.588 84.947 88.686 ;
     RECT  84.947 9.018 84.983 9.306 ;
     RECT  84.947 10.17 84.983 12.348 ;
     RECT  84.947 14.148 84.983 15.858 ;
     RECT  84.947 23.598 84.983 23.652 ;
     RECT  84.947 32.274 84.983 33.066 ;
     RECT  84.947 35.748 84.983 36.144 ;
     RECT  84.947 40.068 84.983 41.166 ;
     RECT  84.947 46.008 84.983 46.296 ;
     RECT  84.947 50.67 84.983 50.688 ;
     RECT  84.947 52.83 84.983 52.848 ;
     RECT  84.947 55.458 84.983 56.088 ;
     RECT  84.947 57.888 84.983 59.058 ;
     RECT  84.947 60.858 84.983 61.254 ;
     RECT  84.947 62.28 84.983 62.802 ;
     RECT  84.947 64.098 84.983 64.116 ;
     RECT  84.947 66.834 84.983 68.274 ;
     RECT  84.947 71.928 84.983 71.946 ;
     RECT  84.947 76.59 84.983 77.148 ;
     RECT  84.947 81.144 84.983 83.016 ;
     RECT  84.947 84.618 84.983 84.906 ;
     RECT  84.947 87.588 84.983 88.218 ;
     RECT  84.983 40.608 85.019 40.932 ;
     RECT  84.947 6.39 85.523 6.57 ;
     RECT  84.983 9.288 85.523 9.306 ;
     RECT  84.983 10.44 85.523 10.728 ;
     RECT  84.983 11.754 85.523 12.348 ;
     RECT  84.983 14.49 85.523 14.508 ;
     RECT  84.983 15.84 85.523 15.858 ;
     RECT  84.947 16.65 85.523 16.668 ;
     RECT  84.947 18 85.523 18.018 ;
     RECT  84.947 19.548 85.523 19.566 ;
     RECT  84.947 20.7 85.523 20.718 ;
     RECT  84.947 21.708 85.523 22.23 ;
     RECT  84.983 23.634 85.523 23.652 ;
     RECT  84.947 26.1 85.523 26.352 ;
     RECT  84.947 29.034 85.523 29.052 ;
     RECT  84.947 29.844 85.523 29.862 ;
     RECT  84.947 31.5 85.523 31.518 ;
     RECT  84.983 32.274 85.523 32.832 ;
     RECT  84.947 33.93 85.523 33.948 ;
     RECT  84.947 34.974 85.523 34.992 ;
     RECT  84.983 36.054 85.523 36.144 ;
     RECT  85.019 40.608 85.523 40.626 ;
     RECT  84.947 42.228 85.523 42.246 ;
     RECT  84.947 43.11 85.523 43.434 ;
     RECT  84.947 45.234 85.523 45.252 ;
     RECT  84.983 46.278 85.523 46.296 ;
     RECT  84.947 47.43 85.523 47.682 ;
     RECT  84.947 52.02 85.523 52.038 ;
     RECT  84.947 53.676 85.523 53.694 ;
     RECT  84.983 56.07 85.523 56.088 ;
     RECT  84.983 57.96 85.523 59.058 ;
     RECT  84.983 61.236 85.523 61.254 ;
     RECT  84.983 62.784 85.523 62.802 ;
     RECT  84.983 66.834 85.523 66.852 ;
     RECT  84.983 67.644 85.523 68.274 ;
     RECT  84.947 73.044 85.523 73.062 ;
     RECT  84.983 77.13 85.523 77.148 ;
     RECT  84.947 77.94 85.523 78.264 ;
     RECT  84.947 80.1 85.523 80.118 ;
     RECT  84.983 81.144 85.523 81.162 ;
     RECT  84.983 82.26 85.523 83.016 ;
     RECT  84.983 84.888 85.523 84.906 ;
     RECT  84.947 86.238 85.523 86.256 ;
     RECT  84.983 88.2 85.523 88.218 ;
     RECT  85.523 12.33 85.559 12.348 ;
     RECT  85.523 26.334 85.559 26.352 ;
     RECT  85.523 58.5 85.559 58.518 ;
     RECT  85.523 67.95 85.559 67.968 ;
     RECT  85.523 82.26 85.559 82.854 ;
     RECT  85.523 32.274 85.595 32.292 ;
     RECT  85.523 36.09 85.595 36.108 ;
     RECT  85.559 82.8 85.595 82.818 ;
    LAYER M3 ;
     RECT  62.136 0.571 62.154 2.101 ;
     RECT  31.896 2.101 31.914 2.143 ;
     RECT  62.136 2.101 62.226 2.143 ;
     RECT  24.015 2.143 24.105 2.191 ;
     RECT  26.715 2.143 26.805 2.191 ;
     RECT  31.896 2.143 32.205 2.191 ;
     RECT  45.615 2.143 45.705 2.191 ;
     RECT  78.015 2.143 78.105 2.191 ;
     RECT  56.415 2.143 56.505 2.203 ;
     RECT  15.915 2.143 16.005 2.227 ;
     RECT  24.015 2.191 24.354 2.227 ;
     RECT  36.324 2.191 36.342 2.227 ;
     RECT  45.615 2.191 45.954 2.227 ;
     RECT  46.908 2.191 46.926 2.227 ;
     RECT  54.648 2.191 54.882 2.227 ;
     RECT  74.34 2.191 74.358 2.227 ;
     RECT  42.915 2.143 43.005 2.251 ;
     RECT  44.604 2.191 44.622 2.251 ;
     RECT  77.796 2.191 78.105 2.251 ;
     RECT  12.06 2.227 12.078 2.263 ;
     RECT  15.804 2.227 16.005 2.263 ;
     RECT  16.992 2.191 17.01 2.263 ;
     RECT  26.715 2.191 27.414 2.263 ;
     RECT  28.296 2.191 28.314 2.263 ;
     RECT  45.615 2.227 46.926 2.263 ;
     RECT  56.304 2.203 56.505 2.263 ;
     RECT  61.815 2.143 62.226 2.263 ;
     RECT  64.515 2.143 64.605 2.263 ;
     RECT  69.012 2.191 69.03 2.263 ;
     RECT  71.748 2.227 71.766 2.263 ;
     RECT  72.615 2.143 72.705 2.263 ;
     RECT  26.715 2.263 28.314 2.293 ;
     RECT  29.415 2.143 29.505 2.293 ;
     RECT  61.704 2.263 62.226 2.293 ;
     RECT  71.748 2.263 72.705 2.293 ;
     RECT  77.616 2.251 78.105 2.293 ;
     RECT  15.804 2.263 17.01 2.299 ;
     RECT  20.052 2.293 20.07 2.299 ;
     RECT  21.315 2.143 21.405 2.299 ;
     RECT  23.364 2.227 24.354 2.299 ;
     RECT  42.915 2.251 43.326 2.299 ;
     RECT  48.315 2.143 48.405 2.299 ;
     RECT  51.015 2.143 51.105 2.299 ;
     RECT  54.648 2.227 55.17 2.299 ;
     RECT  56.304 2.263 57.222 2.299 ;
     RECT  59.115 2.143 59.205 2.299 ;
     RECT  61.596 2.293 62.226 2.299 ;
     RECT  71.604 2.293 72.705 2.299 ;
     RECT  77.508 2.293 78.105 2.299 ;
     RECT  80.715 2.143 80.805 2.299 ;
     RECT  11.808 2.263 12.078 2.335 ;
     RECT  13.215 2.143 13.305 2.335 ;
     RECT  26.715 2.293 29.505 2.335 ;
     RECT  77.508 2.299 78.642 2.347 ;
     RECT  11.808 2.335 13.305 2.371 ;
     RECT  15.804 2.299 17.262 2.371 ;
     RECT  18.615 2.143 18.705 2.371 ;
     RECT  21.315 2.299 22.482 2.371 ;
     RECT  23.364 2.299 24.822 2.371 ;
     RECT  31.356 2.191 32.205 2.371 ;
     RECT  38.772 2.299 38.79 2.371 ;
     RECT  40.215 2.143 40.305 2.371 ;
     RECT  44.136 2.251 44.622 2.371 ;
     RECT  45.612 2.263 46.926 2.371 ;
     RECT  48.315 2.299 49.05 2.371 ;
     RECT  50.724 2.299 51.105 2.371 ;
     RECT  61.596 2.299 62.262 2.371 ;
     RECT  65.484 2.227 65.502 2.371 ;
     RECT  66.456 2.299 66.474 2.371 ;
     RECT  69.012 2.263 69.102 2.371 ;
     RECT  69.915 2.143 70.005 2.371 ;
     RECT  80.532 2.299 80.805 2.371 ;
     RECT  2.415 2.143 2.505 2.413 ;
     RECT  5.115 2.143 5.205 2.413 ;
     RECT  7.815 2.143 7.905 2.413 ;
     RECT  10.515 2.143 10.605 2.413 ;
     RECT  11.592 2.371 13.305 2.413 ;
     RECT  15.804 2.371 18.705 2.413 ;
     RECT  34.815 2.143 34.905 2.413 ;
     RECT  35.784 2.227 36.342 2.413 ;
     RECT  37.515 2.143 37.605 2.413 ;
     RECT  50.04 2.371 51.105 2.413 ;
     RECT  53.715 2.143 53.805 2.413 ;
     RECT  54.648 2.299 57.222 2.413 ;
     RECT  58.716 2.299 59.205 2.413 ;
     RECT  63.864 2.263 64.605 2.413 ;
     RECT  65.484 2.371 66.474 2.413 ;
     RECT  67.215 2.143 67.305 2.413 ;
     RECT  68.904 2.371 70.005 2.413 ;
     RECT  71.604 2.299 72.738 2.413 ;
     RECT  75.315 2.143 75.405 2.413 ;
     RECT  79.992 2.371 80.805 2.413 ;
     RECT  83.415 2.143 83.505 2.413 ;
     RECT  31.356 2.371 32.454 2.461 ;
     RECT  34.815 2.413 36.342 2.461 ;
     RECT  41.976 2.371 41.994 2.461 ;
     RECT  63.864 2.413 66.474 2.461 ;
     RECT  67.215 2.413 67.497 2.461 ;
     RECT  77.508 2.347 79.002 2.461 ;
     RECT  11.592 2.413 13.497 2.488 ;
     RECT  34.815 2.461 36.45 2.488 ;
     RECT  74.232 2.227 74.358 2.488 ;
     RECT  10.515 2.413 10.797 2.491 ;
     RECT  11.592 2.488 13.554 2.491 ;
     RECT  30.996 2.461 32.454 2.491 ;
     RECT  60.948 2.371 62.262 2.491 ;
     RECT  26.715 2.335 30.186 2.497 ;
     RECT  63.864 2.461 67.497 2.497 ;
     RECT  77.508 2.461 79.146 2.497 ;
     RECT  44.136 2.371 47.178 2.525 ;
     RECT  71.604 2.413 72.897 2.533 ;
     RECT  74.016 2.488 74.358 2.533 ;
     RECT  77.4 2.497 79.146 2.533 ;
     RECT  79.992 2.413 80.997 2.533 ;
     RECT  37.515 2.413 37.797 2.569 ;
     RECT  38.52 2.371 38.79 2.569 ;
     RECT  48.276 2.371 49.05 2.569 ;
     RECT  50.04 2.413 51.297 2.569 ;
     RECT  63.864 2.497 67.914 2.569 ;
     RECT  68.904 2.413 70.197 2.569 ;
     RECT  37.515 2.569 38.79 2.587 ;
     RECT  40.215 2.371 40.626 2.587 ;
     RECT  26.676 2.497 30.186 2.605 ;
     RECT  30.996 2.491 33.102 2.605 ;
     RECT  41.904 2.461 41.994 2.605 ;
     RECT  42.768 2.299 43.326 2.605 ;
     RECT  53.715 2.413 57.222 2.605 ;
     RECT  75.315 2.413 75.597 2.605 ;
     RECT  77.4 2.533 80.997 2.605 ;
     RECT  9 2.488 9.018 2.641 ;
     RECT  10.08 2.491 13.554 2.641 ;
     RECT  14.832 2.371 14.85 2.641 ;
     RECT  15.804 2.413 18.897 2.641 ;
     RECT  20.052 2.299 20.466 2.641 ;
     RECT  21.315 2.371 25.29 2.641 ;
     RECT  26.676 2.605 33.102 2.641 ;
     RECT  34.272 2.488 36.45 2.641 ;
     RECT  40.215 2.587 40.77 2.641 ;
     RECT  41.76 2.605 43.326 2.641 ;
     RECT  45.396 2.525 47.178 2.641 ;
     RECT  48.276 2.569 51.297 2.641 ;
     RECT  53.172 2.605 57.222 2.641 ;
     RECT  58.716 2.413 59.397 2.641 ;
     RECT  60.408 2.491 62.262 2.641 ;
     RECT  63 2.488 63.018 2.641 ;
     RECT  63.864 2.569 70.686 2.641 ;
     RECT  71.604 2.533 74.358 2.641 ;
     RECT  75.315 2.605 80.997 2.641 ;
     RECT  9 2.641 14.85 2.767 ;
     RECT  15.804 2.641 25.686 2.767 ;
     RECT  40.215 2.641 40.914 2.767 ;
     RECT  41.688 2.641 43.326 2.767 ;
     RECT  44.136 2.525 44.55 2.767 ;
     RECT  9 2.767 25.722 2.803 ;
     RECT  26.676 2.641 36.45 2.803 ;
     RECT  37.512 2.587 39.258 2.803 ;
     RECT  40.032 2.767 40.914 2.803 ;
     RECT  45.396 2.641 51.606 2.803 ;
     RECT  53.172 2.641 57.402 2.803 ;
     RECT  37.512 2.803 40.914 2.827 ;
     RECT  41.688 2.767 44.55 2.827 ;
     RECT  9 2.803 36.45 2.911 ;
     RECT  37.512 2.827 44.55 2.911 ;
     RECT  7.815 2.413 8.097 3.001 ;
     RECT  9 2.911 44.55 3.001 ;
     RECT  7.815 3.001 44.55 3.271 ;
     RECT  45.396 2.803 57.402 3.271 ;
     RECT  7.815 3.271 57.402 3.379 ;
     RECT  6.264 3.271 6.282 3.403 ;
     RECT  7.596 3.379 57.402 3.403 ;
     RECT  2.415 2.413 2.697 3.415 ;
     RECT  2.415 3.415 3.114 3.451 ;
     RECT  5.115 2.413 5.397 3.451 ;
     RECT  6.264 3.403 57.402 3.451 ;
     RECT  2.415 3.451 3.582 3.577 ;
     RECT  5.115 3.451 57.546 3.577 ;
     RECT  2.415 3.577 57.546 3.613 ;
     RECT  58.32 2.641 80.997 3.613 ;
     RECT  2.415 3.613 80.997 3.649 ;
     RECT  2.415 3.649 81.234 4.261 ;
     RECT  82.62 3.379 82.638 4.351 ;
     RECT  2.415 4.261 81.594 4.387 ;
     RECT  82.584 4.351 82.638 4.387 ;
     RECT  83.415 2.413 83.697 4.411 ;
     RECT  2.415 4.387 82.638 4.555 ;
     RECT  83.415 4.411 84.402 4.747 ;
     RECT  2.304 4.555 82.638 5.035 ;
     RECT  83.415 4.747 84.942 5.035 ;
     RECT  2.304 5.035 84.942 5.189 ;
     RECT  0.216 5.371 0.234 5.899 ;
     RECT  0.216 5.899 0.27 6.029 ;
     RECT  2.415 5.189 84.942 6.187 ;
     RECT  2.415 6.187 85.518 6.385 ;
     RECT  2.304 6.385 85.518 6.575 ;
     RECT  64.332 6.575 85.518 6.611 ;
     RECT  64.332 6.611 84.474 6.719 ;
     RECT  0.216 6.029 0.234 6.893 ;
     RECT  2.304 6.575 63.45 7.003 ;
     RECT  85.5 6.611 85.518 7.037 ;
     RECT  2.268 7.003 63.45 7.429 ;
     RECT  64.332 6.719 84.438 7.429 ;
     RECT  2.268 7.429 84.438 7.531 ;
     RECT  2.268 7.531 84.942 7.691 ;
     RECT  2.268 7.691 84.474 7.889 ;
     RECT  2.304 7.889 84.474 8.501 ;
     RECT  44.46 8.501 84.474 8.683 ;
     RECT  0.54 8.473 0.558 8.717 ;
     RECT  2.304 8.501 43.722 8.969 ;
     RECT  44.46 8.683 84.942 8.971 ;
     RECT  44.46 8.971 85.518 9.005 ;
     RECT  44.496 9.005 85.518 9.311 ;
     RECT  2.304 8.969 43.686 9.751 ;
     RECT  44.496 9.311 84.978 9.751 ;
     RECT  2.304 9.751 84.978 9.787 ;
     RECT  1.98 9.787 84.978 9.923 ;
     RECT  2.304 9.923 84.978 10.123 ;
     RECT  2.304 10.123 85.518 10.829 ;
     RECT  2.304 10.829 68.382 10.931 ;
     RECT  2.304 10.931 68.31 11.309 ;
     RECT  2.415 11.309 68.31 11.713 ;
     RECT  69.12 10.829 85.518 11.713 ;
     RECT  2.415 11.713 85.518 11.755 ;
     RECT  2.415 11.755 85.554 11.939 ;
     RECT  2.415 11.939 67.986 11.998 ;
     RECT  0.54 11.911 0.558 12.019 ;
     RECT  68.76 11.939 85.554 12.281 ;
     RECT  2.415 11.998 67.95 12.283 ;
     RECT  0.468 12.019 0.558 12.331 ;
     RECT  85.536 12.281 85.554 12.353 ;
     RECT  0.252 12.331 0.558 12.461 ;
     RECT  2.304 12.283 67.95 12.757 ;
     RECT  68.76 12.281 84.438 12.757 ;
     RECT  2.304 12.757 84.438 12.821 ;
     RECT  18.072 12.821 84.438 12.941 ;
     RECT  18.252 12.941 84.438 13.063 ;
     RECT  0.468 12.461 0.558 13.091 ;
     RECT  0.54 13.091 0.558 13.277 ;
     RECT  18.252 13.063 84.942 13.421 ;
     RECT  18.252 13.421 43.686 13.559 ;
     RECT  44.532 13.421 84.942 13.595 ;
     RECT  2.304 12.821 17.19 13.603 ;
     RECT  2.304 13.603 17.334 13.675 ;
     RECT  2.304 13.675 17.406 13.723 ;
     RECT  58.896 13.595 84.942 13.723 ;
     RECT  1.98 13.723 17.406 13.771 ;
     RECT  18.252 13.559 43.65 13.771 ;
     RECT  1.98 13.771 43.65 13.901 ;
     RECT  58.896 13.723 84.978 14.059 ;
     RECT  2.268 13.901 43.65 14.093 ;
     RECT  44.568 13.595 58.158 14.341 ;
     RECT  58.896 14.059 85.518 14.341 ;
     RECT  0.54 14.143 0.558 14.429 ;
     RECT  44.568 14.341 85.518 14.477 ;
     RECT  65.664 14.477 85.518 14.513 ;
     RECT  44.568 14.477 64.926 14.647 ;
     RECT  44.46 14.647 64.926 15.259 ;
     RECT  65.664 14.513 84.978 15.259 ;
     RECT  44.46 15.259 84.978 15.355 ;
     RECT  2.304 14.093 43.65 15.565 ;
     RECT  44.46 15.355 85.518 15.565 ;
     RECT  2.304 15.565 85.518 16.673 ;
     RECT  2.304 16.673 84.942 16.781 ;
     RECT  1.116 16.987 1.134 17.117 ;
     RECT  1.152 17.179 1.17 17.405 ;
     RECT  20.484 16.781 84.942 17.447 ;
     RECT  84.888 17.447 84.942 17.803 ;
     RECT  20.484 17.447 83.934 17.879 ;
     RECT  84.888 17.803 85.518 18.023 ;
     RECT  0.252 17.707 0.27 18.121 ;
     RECT  2.304 16.781 19.746 18.185 ;
     RECT  2.415 18.185 19.746 18.193 ;
     RECT  20.484 17.879 83.826 18.193 ;
     RECT  1.152 18.235 1.17 18.365 ;
     RECT  0.216 18.121 0.27 18.509 ;
     RECT  0.252 18.509 0.27 18.523 ;
     RECT  0.252 18.523 0.306 18.653 ;
     RECT  2.415 18.193 83.826 18.761 ;
     RECT  74.484 18.761 83.826 18.811 ;
     RECT  84.888 18.023 84.942 18.811 ;
     RECT  0.252 18.653 0.27 18.845 ;
     RECT  74.484 18.811 84.942 19.229 ;
     RECT  76.824 19.229 84.942 19.265 ;
     RECT  2.415 18.761 73.566 19.435 ;
     RECT  76.932 19.265 84.942 19.435 ;
     RECT  2.304 19.435 73.566 19.483 ;
     RECT  74.484 19.229 75.798 19.483 ;
     RECT  2.304 19.483 75.798 19.535 ;
     RECT  76.932 19.435 85.518 19.571 ;
     RECT  2.304 19.535 39.15 19.805 ;
     RECT  28.044 19.805 39.15 19.949 ;
     RECT  76.932 19.571 84.942 19.949 ;
     RECT  39.924 19.535 75.798 20.011 ;
     RECT  79.524 19.949 84.942 20.111 ;
     RECT  39.924 20.011 76.014 20.191 ;
     RECT  28.224 19.949 39.15 20.281 ;
     RECT  39.924 20.191 76.194 20.281 ;
     RECT  79.668 20.111 84.942 20.309 ;
     RECT  28.224 20.281 76.194 20.381 ;
     RECT  36.504 20.381 76.194 20.425 ;
     RECT  76.932 19.949 78.714 20.425 ;
     RECT  0.252 20.299 0.27 20.429 ;
     RECT  79.776 20.309 84.942 20.443 ;
     RECT  79.776 20.443 85.518 20.453 ;
     RECT  80.388 20.453 85.518 20.723 ;
     RECT  2.304 19.805 27.306 20.731 ;
     RECT  28.224 20.381 35.766 20.731 ;
     RECT  36.504 20.425 78.714 21.067 ;
     RECT  0.54 20.893 0.558 21.149 ;
     RECT  2.304 20.731 35.766 21.211 ;
     RECT  36.504 21.067 79.614 21.211 ;
     RECT  2.304 21.211 79.614 21.397 ;
     RECT  80.388 20.723 84.942 21.397 ;
     RECT  2.304 21.397 84.942 21.595 ;
     RECT  0.252 21.451 0.27 21.628 ;
     RECT  0.216 21.628 0.27 21.773 ;
     RECT  2.304 21.595 85.518 22.081 ;
     RECT  0.54 22.081 0.558 22.219 ;
     RECT  2.268 22.081 85.518 22.235 ;
     RECT  0.54 22.219 1.17 22.349 ;
     RECT  2.268 22.235 49.986 22.379 ;
     RECT  0.54 22.349 0.558 22.891 ;
     RECT  50.724 22.235 85.518 23.009 ;
     RECT  2.304 22.379 49.986 23.017 ;
     RECT  50.724 23.009 66.402 23.017 ;
     RECT  2.304 23.017 66.402 23.045 ;
     RECT  0.252 22.891 0.558 23.251 ;
     RECT  0.216 23.251 0.558 23.261 ;
     RECT  0.216 23.261 0.234 23.405 ;
     RECT  67.14 23.009 85.518 23.657 ;
     RECT  27.828 23.045 66.402 23.827 ;
     RECT  67.14 23.657 84.906 23.827 ;
     RECT  27.828 23.827 84.906 23.933 ;
     RECT  2.304 23.045 27.09 23.935 ;
     RECT  27.828 23.933 78.462 23.935 ;
     RECT  0.252 24.523 0.27 24.601 ;
     RECT  79.2 23.933 84.906 24.715 ;
     RECT  2.304 23.935 78.462 24.745 ;
     RECT  79.2 24.715 84.942 24.745 ;
     RECT  0.216 24.601 0.27 25.229 ;
     RECT  2.304 24.745 84.942 25.531 ;
     RECT  2.304 25.531 85.518 25.819 ;
     RECT  2.304 25.819 85.554 26.249 ;
     RECT  15.336 26.249 85.554 26.357 ;
     RECT  0.54 25.321 0.558 26.381 ;
     RECT  2.304 26.249 14.562 26.699 ;
     RECT  2.376 26.699 14.562 27.031 ;
     RECT  15.336 26.357 84.942 27.031 ;
     RECT  2.376 27.031 84.942 27.059 ;
     RECT  0.216 26.971 0.234 27.101 ;
     RECT  2.412 27.059 84.942 27.401 ;
     RECT  2.412 27.401 70.542 27.979 ;
     RECT  2.304 27.979 70.542 28.255 ;
     RECT  71.316 27.401 84.942 28.255 ;
     RECT  2.304 28.255 84.942 28.319 ;
     RECT  84.924 28.319 84.942 28.459 ;
     RECT  2.304 28.319 83.826 28.679 ;
     RECT  2.415 28.679 83.826 28.715 ;
     RECT  47.34 28.715 83.826 28.985 ;
     RECT  0.216 28.921 0.234 29.165 ;
     RECT  71.28 28.985 83.826 29.275 ;
     RECT  84.924 28.459 85.518 29.275 ;
     RECT  2.415 28.715 46.602 29.461 ;
     RECT  47.34 28.985 70.47 29.461 ;
     RECT  2.415 29.461 70.47 29.731 ;
     RECT  71.28 29.275 85.518 29.831 ;
     RECT  85.5 29.831 85.518 29.867 ;
     RECT  2.304 29.731 70.47 29.875 ;
     RECT  71.28 29.831 84.438 29.875 ;
     RECT  0.252 29.419 0.27 30.763 ;
     RECT  0.252 30.763 0.306 30.907 ;
     RECT  2.304 29.875 84.438 30.907 ;
     RECT  0.216 30.907 0.306 30.989 ;
     RECT  2.304 30.907 84.942 31.051 ;
     RECT  0.216 30.989 0.27 31.181 ;
     RECT  0.252 31.181 0.27 31.709 ;
     RECT  2.304 31.051 85.518 31.867 ;
     RECT  2.304 31.867 85.59 32.261 ;
     RECT  84.924 32.261 85.59 32.297 ;
     RECT  0.54 32.431 0.558 32.587 ;
     RECT  2.304 32.261 83.898 32.701 ;
     RECT  0.252 32.587 0.558 32.717 ;
     RECT  2.268 32.701 83.898 33.019 ;
     RECT  84.924 32.297 85.518 33.019 ;
     RECT  2.268 33.019 85.518 33.053 ;
     RECT  2.304 33.053 85.518 33.071 ;
     RECT  0.54 32.717 0.558 33.511 ;
     RECT  27.792 33.071 85.518 33.539 ;
     RECT  0.504 33.511 0.558 33.547 ;
     RECT  0.432 33.547 0.558 33.581 ;
     RECT  0.432 33.581 0.522 33.725 ;
     RECT  2.304 33.071 26.997 33.817 ;
     RECT  27.792 33.539 73.53 33.817 ;
     RECT  2.304 33.817 73.53 33.931 ;
     RECT  1.98 33.931 73.53 34.061 ;
     RECT  2.304 34.061 73.53 34.321 ;
     RECT  2.304 34.321 73.638 34.393 ;
     RECT  2.304 34.393 73.674 34.429 ;
     RECT  74.448 33.539 85.518 34.429 ;
     RECT  0.432 33.725 0.45 34.591 ;
     RECT  2.304 34.429 85.518 34.619 ;
     RECT  55.044 34.619 85.518 34.685 ;
     RECT  0.432 34.591 0.558 34.877 ;
     RECT  2.304 34.619 54.306 35.401 ;
     RECT  55.044 34.685 84.438 35.401 ;
     RECT  0.252 35.323 0.27 35.453 ;
     RECT  2.304 35.401 84.438 35.467 ;
     RECT  85.5 34.685 85.518 35.467 ;
     RECT  2.304 35.467 85.518 35.803 ;
     RECT  2.304 35.803 85.59 36.113 ;
     RECT  2.304 36.113 85.518 36.509 ;
     RECT  2.304 36.509 84.942 37.355 ;
     RECT  2.304 37.355 76.086 37.427 ;
     RECT  0.252 37.291 0.27 37.561 ;
     RECT  0.216 37.561 0.27 37.661 ;
     RECT  0.252 37.661 0.27 37.939 ;
     RECT  2.304 37.427 75.978 38.245 ;
     RECT  76.824 37.355 84.942 38.245 ;
     RECT  2.304 38.245 84.942 38.399 ;
     RECT  0.252 37.939 0.558 38.587 ;
     RECT  0.252 38.587 1.17 38.713 ;
     RECT  0.216 38.713 1.17 38.717 ;
     RECT  0.216 38.717 0.558 38.813 ;
     RECT  0.216 38.813 0.234 38.957 ;
     RECT  2.415 38.399 84.942 39.281 ;
     RECT  2.415 39.281 52.182 39.361 ;
     RECT  2.304 39.361 52.182 39.437 ;
     RECT  52.92 39.281 84.942 39.739 ;
     RECT  2.412 39.437 52.182 40.027 ;
     RECT  52.92 39.739 84.978 40.027 ;
     RECT  1.152 39.883 1.17 40.061 ;
     RECT  2.412 40.027 84.978 40.075 ;
     RECT  2.412 40.075 85.014 40.253 ;
     RECT  2.412 40.253 83.97 40.289 ;
     RECT  2.412 40.289 83.826 40.411 ;
     RECT  84.924 40.253 85.014 40.411 ;
     RECT  2.304 40.411 83.826 40.559 ;
     RECT  84.924 40.411 85.518 40.631 ;
     RECT  2.415 40.559 83.826 40.637 ;
     RECT  0.252 40.555 0.27 40.801 ;
     RECT  36.576 40.637 83.826 40.937 ;
     RECT  0.216 40.801 0.27 41.069 ;
     RECT  84.924 40.631 85.014 41.069 ;
     RECT  84.924 41.069 84.978 41.171 ;
     RECT  79.2 40.937 83.826 41.341 ;
     RECT  79.2 41.341 83.862 41.371 ;
     RECT  84.924 41.171 84.942 41.371 ;
     RECT  0.468 41.107 0.486 41.413 ;
     RECT  2.415 40.637 35.73 41.485 ;
     RECT  36.576 40.937 78.39 41.485 ;
     RECT  2.415 41.485 78.39 41.563 ;
     RECT  2.304 41.563 78.39 41.683 ;
     RECT  79.2 41.371 84.942 41.683 ;
     RECT  0.468 41.413 0.558 41.851 ;
     RECT  2.304 41.683 84.942 41.909 ;
     RECT  2.415 41.909 84.942 42.017 ;
     RECT  0.252 41.851 0.558 42.475 ;
     RECT  0.252 42.475 1.17 42.605 ;
     RECT  2.415 42.017 84.402 42.961 ;
     RECT  0.252 42.605 0.558 43.099 ;
     RECT  0.216 43.099 0.558 43.229 ;
     RECT  2.304 42.961 84.402 43.339 ;
     RECT  85.5 42.043 85.518 43.339 ;
     RECT  2.304 43.339 85.518 43.439 ;
     RECT  0.468 43.229 0.558 43.517 ;
     RECT  0.468 43.517 0.486 43.853 ;
     RECT  2.304 43.439 84.942 43.915 ;
     RECT  1.98 43.915 84.942 44.045 ;
     RECT  0.396 44.491 0.414 44.635 ;
     RECT  0.216 44.635 0.414 44.669 ;
     RECT  2.304 44.045 84.942 44.827 ;
     RECT  2.304 44.827 85.518 44.879 ;
     RECT  0.216 44.669 0.27 45.245 ;
     RECT  2.415 44.879 85.518 45.257 ;
     RECT  0.252 45.245 0.27 45.533 ;
     RECT  2.415 45.257 84.978 45.769 ;
     RECT  2.34 45.769 84.978 46.267 ;
     RECT  2.34 46.267 85.518 46.315 ;
     RECT  1.98 46.315 85.518 46.493 ;
     RECT  2.376 46.493 85.518 46.571 ;
     RECT  0.252 46.939 0.27 47.069 ;
     RECT  2.376 46.571 84.474 47.309 ;
     RECT  2.412 47.309 84.474 47.611 ;
     RECT  85.5 46.571 85.518 47.611 ;
     RECT  0.504 47.191 0.558 47.645 ;
     RECT  0.54 47.645 0.558 47.933 ;
     RECT  2.412 47.611 85.518 48.091 ;
     RECT  2.304 48.091 85.518 48.125 ;
     RECT  2.304 48.125 84.942 48.695 ;
     RECT  36.468 48.695 84.942 48.749 ;
     RECT  36.468 48.749 84.474 49.199 ;
     RECT  2.304 48.695 35.658 49.441 ;
     RECT  36.468 49.199 79.506 49.441 ;
     RECT  80.28 49.199 84.474 49.531 ;
     RECT  2.304 49.441 79.506 49.577 ;
     RECT  0.252 49.579 0.27 49.757 ;
     RECT  80.28 49.531 84.942 50.059 ;
     RECT  44.748 49.577 79.506 50.251 ;
     RECT  80.28 50.059 84.978 50.251 ;
     RECT  2.304 49.577 43.974 50.323 ;
     RECT  44.748 50.251 84.978 50.323 ;
     RECT  2.304 50.323 84.978 50.693 ;
     RECT  0.252 50.587 0.27 50.717 ;
     RECT  2.304 50.693 84.942 51.053 ;
     RECT  2.415 51.053 84.942 51.835 ;
     RECT  2.304 51.835 85.518 52.043 ;
     RECT  2.304 52.043 84.978 52.853 ;
     RECT  2.304 52.853 84.438 53.015 ;
     RECT  74.484 53.015 84.438 53.285 ;
     RECT  74.556 53.285 84.438 53.659 ;
     RECT  74.556 53.659 84.942 53.671 ;
     RECT  74.556 53.671 85.518 53.837 ;
     RECT  2.304 53.015 73.746 54.211 ;
     RECT  74.556 53.837 84.942 54.211 ;
     RECT  2.304 54.211 84.942 54.599 ;
     RECT  38.736 54.599 84.942 54.605 ;
     RECT  38.844 54.605 84.942 54.955 ;
     RECT  0.54 54.481 0.558 55.325 ;
     RECT  2.304 54.599 37.926 55.381 ;
     RECT  38.844 54.955 84.978 55.381 ;
     RECT  2.304 55.381 84.978 55.627 ;
     RECT  2.304 55.627 85.518 56.011 ;
     RECT  2.268 56.011 85.518 56.093 ;
     RECT  2.268 56.093 84.942 56.141 ;
     RECT  0.252 56.191 0.27 56.371 ;
     RECT  0.216 56.371 0.27 56.731 ;
     RECT  2.304 56.141 84.942 56.765 ;
     RECT  2.376 56.765 84.942 57.259 ;
     RECT  0.216 56.731 0.558 57.293 ;
     RECT  2.376 57.259 84.978 57.403 ;
     RECT  2.376 57.403 85.518 57.677 ;
     RECT  2.376 57.677 55.674 57.739 ;
     RECT  56.415 57.677 85.518 57.839 ;
     RECT  2.304 57.739 55.674 57.869 ;
     RECT  56.415 57.839 82.17 57.875 ;
     RECT  82.944 57.839 85.518 57.883 ;
     RECT  2.376 57.869 55.674 57.917 ;
     RECT  0.216 57.293 0.234 58.081 ;
     RECT  0.216 58.081 0.27 58.109 ;
     RECT  82.944 57.883 85.554 58.109 ;
     RECT  82.944 58.109 83.898 58.145 ;
     RECT  0.252 58.109 0.27 58.445 ;
     RECT  2.415 57.917 55.674 58.451 ;
     RECT  2.415 58.451 55.566 58.487 ;
     RECT  56.415 57.875 82.098 58.487 ;
     RECT  84.888 58.109 85.554 58.523 ;
     RECT  73.62 58.487 82.098 58.693 ;
     RECT  82.944 58.145 83.754 58.693 ;
     RECT  2.415 58.487 55.53 58.891 ;
     RECT  73.62 58.693 83.754 58.891 ;
     RECT  84.888 58.523 85.518 58.891 ;
     RECT  73.62 58.891 85.518 58.955 ;
     RECT  74.124 58.955 85.518 59.063 ;
     RECT  56.415 58.487 72.897 59.071 ;
     RECT  2.304 58.891 55.53 59.233 ;
     RECT  56.412 59.071 72.897 59.233 ;
     RECT  2.304 59.233 72.897 59.305 ;
     RECT  2.304 59.305 73.386 59.999 ;
     RECT  58.608 59.999 73.386 60.007 ;
     RECT  74.124 59.063 84.942 60.007 ;
     RECT  2.304 59.999 57.726 60.179 ;
     RECT  58.608 60.007 84.942 60.523 ;
     RECT  2.304 60.179 57.69 60.557 ;
     RECT  2.376 60.557 57.69 60.961 ;
     RECT  58.608 60.523 84.978 60.961 ;
     RECT  2.376 60.961 84.978 61.003 ;
     RECT  2.376 61.003 85.518 61.079 ;
     RECT  1.152 61.123 1.17 61.223 ;
     RECT  79.452 61.079 85.518 61.259 ;
     RECT  79.452 61.259 84.978 61.373 ;
     RECT  2.376 61.079 78.534 61.483 ;
     RECT  0.216 59.701 0.234 61.709 ;
     RECT  79.56 61.373 84.978 61.997 ;
     RECT  2.304 61.483 78.534 62.131 ;
     RECT  79.56 61.997 84.042 62.131 ;
     RECT  2.304 62.131 84.042 62.429 ;
     RECT  84.924 61.997 84.978 62.635 ;
     RECT  84.924 62.635 85.518 62.807 ;
     RECT  0.216 62.671 0.234 63.005 ;
     RECT  28.08 62.429 84.042 63.115 ;
     RECT  84.924 62.807 84.942 63.115 ;
     RECT  2.304 62.429 27.306 63.247 ;
     RECT  28.08 63.115 84.942 63.247 ;
     RECT  2.304 63.247 84.942 63.643 ;
     RECT  2.304 63.643 84.978 64.121 ;
     RECT  2.304 64.121 84.942 64.603 ;
     RECT  2.196 64.603 84.942 64.769 ;
     RECT  0.252 63.355 0.27 64.781 ;
     RECT  0.216 65.179 0.234 65.309 ;
     RECT  2.304 64.769 84.942 65.641 ;
     RECT  2.268 65.641 84.942 65.933 ;
     RECT  1.152 65.995 1.17 66.125 ;
     RECT  2.304 65.933 84.942 66.379 ;
     RECT  2.304 66.379 85.518 66.479 ;
     RECT  0.252 66.715 0.27 66.763 ;
     RECT  0.252 66.763 0.342 66.893 ;
     RECT  0.324 66.893 0.342 66.941 ;
     RECT  2.415 66.479 85.518 67.441 ;
     RECT  2.304 67.441 85.518 67.531 ;
     RECT  2.268 67.531 85.554 67.568 ;
     RECT  2.304 67.568 85.554 67.901 ;
     RECT  85.5 67.901 85.554 67.973 ;
     RECT  1.152 67.867 1.17 68.141 ;
     RECT  2.304 67.901 84.474 68.237 ;
     RECT  2.304 68.237 84.438 68.369 ;
     RECT  85.5 67.973 85.518 68.381 ;
     RECT  0.216 68.443 0.234 68.917 ;
     RECT  0.216 68.917 0.27 69.053 ;
     RECT  0.252 69.053 0.27 69.197 ;
     RECT  2.304 68.369 30.834 69.223 ;
     RECT  31.572 68.369 84.438 69.223 ;
     RECT  2.304 69.223 84.438 69.499 ;
     RECT  2.304 69.499 84.942 69.989 ;
     RECT  2.304 69.989 38.898 70.205 ;
     RECT  2.412 70.205 38.898 70.541 ;
     RECT  2.415 70.541 38.898 70.951 ;
     RECT  39.708 69.989 84.942 70.951 ;
     RECT  0.216 70.501 0.234 71.357 ;
     RECT  2.415 70.951 84.942 71.803 ;
     RECT  2.415 71.803 84.978 71.879 ;
     RECT  79.308 71.879 84.978 72.149 ;
     RECT  79.38 72.149 84.978 72.221 ;
     RECT  2.415 71.879 78.534 72.317 ;
     RECT  0.252 71.803 0.27 72.653 ;
     RECT  74.52 72.317 78.534 72.841 ;
     RECT  74.52 72.841 78.642 72.931 ;
     RECT  79.38 72.221 84.474 72.931 ;
     RECT  74.52 72.931 84.474 72.955 ;
     RECT  85.5 72.475 85.518 72.955 ;
     RECT  2.415 72.317 73.782 73.039 ;
     RECT  74.52 72.955 85.518 73.039 ;
     RECT  2.415 73.039 85.518 73.067 ;
     RECT  2.415 73.067 84.942 73.099 ;
     RECT  0.54 74.011 0.558 74.957 ;
     RECT  0.396 75.259 0.414 75.403 ;
     RECT  0.216 75.403 0.414 75.437 ;
     RECT  0.216 75.437 0.342 75.677 ;
     RECT  0.252 75.677 0.342 76.061 ;
     RECT  2.304 73.099 84.942 76.075 ;
     RECT  0.324 76.061 0.342 76.109 ;
     RECT  2.304 76.075 84.978 76.109 ;
     RECT  25.992 76.109 84.978 76.891 ;
     RECT  2.304 76.109 25.182 76.981 ;
     RECT  25.992 76.891 85.518 76.981 ;
     RECT  2.304 76.981 85.518 77.179 ;
     RECT  1.98 77.179 85.518 77.309 ;
     RECT  2.304 77.309 85.518 77.453 ;
     RECT  18.144 77.453 85.518 77.891 ;
     RECT  0.504 76.243 0.558 77.899 ;
     RECT  0.252 77.899 0.558 78.029 ;
     RECT  2.304 77.453 17.406 78.205 ;
     RECT  18.144 77.891 84.438 78.205 ;
     RECT  2.304 78.205 84.438 78.379 ;
     RECT  0.504 78.029 0.558 78.701 ;
     RECT  1.98 78.379 84.438 78.809 ;
     RECT  0.54 78.701 0.558 78.845 ;
     RECT  18.036 78.809 84.438 79.339 ;
     RECT  85.5 77.891 85.518 79.339 ;
     RECT  1.98 78.809 17.298 79.681 ;
     RECT  18.036 79.339 85.518 79.681 ;
     RECT  1.98 79.681 85.518 79.745 ;
     RECT  41.364 79.745 85.518 80.045 ;
     RECT  1.98 79.745 40.59 80.051 ;
     RECT  1.98 80.051 40.554 80.141 ;
     RECT  41.508 80.045 85.518 80.285 ;
     RECT  52.812 80.285 76.446 80.321 ;
     RECT  2.268 80.141 40.554 80.621 ;
     RECT  2.304 80.621 40.554 80.941 ;
     RECT  41.508 80.285 52.038 80.941 ;
     RECT  2.304 80.941 52.038 81.059 ;
     RECT  52.848 80.321 76.446 81.059 ;
     RECT  2.376 81.059 52.038 81.451 ;
     RECT  52.848 81.059 63.09 81.451 ;
     RECT  63.864 81.059 76.446 81.481 ;
     RECT  77.22 80.285 85.518 81.481 ;
     RECT  2.376 81.451 63.09 81.841 ;
     RECT  63.864 81.481 85.518 81.841 ;
     RECT  2.376 81.841 85.518 81.931 ;
     RECT  0.252 81.787 0.27 82.012 ;
     RECT  0.216 82.012 0.27 82.013 ;
     RECT  0.216 82.013 0.234 82.157 ;
     RECT  2.376 81.931 85.554 82.211 ;
     RECT  2.376 82.211 43.974 82.267 ;
     RECT  85.464 82.211 85.554 82.411 ;
     RECT  85.464 82.411 85.59 82.781 ;
     RECT  85.5 82.781 85.59 82.823 ;
     RECT  85.5 82.823 85.554 82.859 ;
     RECT  2.304 82.267 43.974 82.973 ;
     RECT  2.376 82.973 43.974 83.065 ;
     RECT  44.712 82.211 84.402 83.065 ;
     RECT  85.5 82.859 85.518 83.117 ;
     RECT  0.252 82.987 0.27 83.191 ;
     RECT  2.376 83.065 84.402 83.255 ;
     RECT  0.216 83.191 0.27 83.549 ;
     RECT  76.752 83.255 84.402 83.563 ;
     RECT  2.376 83.255 75.978 83.759 ;
     RECT  76.752 83.563 84.942 83.795 ;
     RECT  0.216 83.549 0.234 83.933 ;
     RECT  76.824 83.795 84.942 84.091 ;
     RECT  2.376 83.759 75.942 84.235 ;
     RECT  2.304 84.235 75.942 84.613 ;
     RECT  2.304 84.613 75.978 84.685 ;
     RECT  76.824 84.091 85.518 84.685 ;
     RECT  2.304 84.685 85.518 84.911 ;
     RECT  0.252 85.051 0.27 85.181 ;
     RECT  2.304 84.911 84.942 85.451 ;
     RECT  14.832 85.451 84.942 85.867 ;
     RECT  2.304 85.451 14.022 85.919 ;
     RECT  14.832 85.867 85.518 86.261 ;
     RECT  2.415 85.919 14.022 86.305 ;
     RECT  14.832 86.261 84.942 86.305 ;
     RECT  2.415 86.305 84.942 86.495 ;
     RECT  2.415 86.495 76.086 86.683 ;
     RECT  76.968 86.495 84.942 86.801 ;
     RECT  82.656 86.801 84.942 86.873 ;
     RECT  2.304 86.683 76.086 86.909 ;
     RECT  82.764 86.873 84.942 87.163 ;
     RECT  0.252 86.347 0.27 87.197 ;
     RECT  55.008 86.909 76.086 87.277 ;
     RECT  55.008 87.277 76.122 87.385 ;
     RECT  55.008 87.385 76.158 87.421 ;
     RECT  76.968 86.801 81.81 87.421 ;
     RECT  55.008 87.421 81.81 87.541 ;
     RECT  2.304 86.909 54.234 87.547 ;
     RECT  1.98 87.547 54.234 87.643 ;
     RECT  55.008 87.541 82.026 87.643 ;
     RECT  1.98 87.643 82.026 87.725 ;
     RECT  2.304 87.725 82.026 87.961 ;
     RECT  82.764 87.163 85.518 87.961 ;
     RECT  2.304 87.961 85.518 88.079 ;
     RECT  2.412 88.079 85.518 88.223 ;
     RECT  2.412 88.223 84.942 88.349 ;
     RECT  2.415 88.349 84.942 88.385 ;
     RECT  83.376 88.385 84.942 88.493 ;
     RECT  84.42 88.493 84.942 88.691 ;
     RECT  84.42 88.691 84.438 88.727 ;
     RECT  2.415 88.385 82.098 88.799 ;
     RECT  83.376 88.493 83.697 88.799 ;
     RECT  2.415 88.799 81.63 88.889 ;
     RECT  2.415 88.889 17.802 88.925 ;
     RECT  18.54 88.889 81.63 88.961 ;
     RECT  18.54 88.961 59.994 88.973 ;
     RECT  0.216 88.075 0.234 89.069 ;
     RECT  18.576 88.973 59.994 89.069 ;
     RECT  2.415 88.925 17.73 89.159 ;
     RECT  18.576 89.069 55.566 89.159 ;
     RECT  60.768 88.961 81.63 89.231 ;
     RECT  3.456 89.159 17.73 89.429 ;
     RECT  18.576 89.159 46.35 89.429 ;
     RECT  8.892 89.429 17.73 89.465 ;
     RECT  3.528 89.429 8.097 89.609 ;
     RECT  3.924 89.609 8.097 89.699 ;
     RECT  60.768 89.231 81.594 89.699 ;
     RECT  9.252 89.465 17.73 89.735 ;
     RECT  3.924 89.699 6.03 89.807 ;
     RECT  6.768 89.699 6.858 89.807 ;
     RECT  9.288 89.735 17.73 89.815 ;
     RECT  18.576 89.429 25.866 89.815 ;
     RECT  3.924 89.807 3.942 89.843 ;
     RECT  4.716 89.807 6.03 89.843 ;
     RECT  6.768 89.807 6.786 89.843 ;
     RECT  47.268 89.159 55.566 89.851 ;
     RECT  56.34 89.069 59.994 89.851 ;
     RECT  5.076 89.843 5.397 89.879 ;
     RECT  76.968 89.699 81.594 89.879 ;
     RECT  9.288 89.815 25.866 90.005 ;
     RECT  26.715 89.429 46.35 90.013 ;
     RECT  47.268 89.851 59.994 90.013 ;
     RECT  60.768 89.699 76.23 90.029 ;
     RECT  9.288 90.005 20.178 90.041 ;
     RECT  26.715 90.013 59.994 90.041 ;
     RECT  52.992 90.041 59.994 90.044 ;
     RECT  60.768 90.029 66.042 90.077 ;
     RECT  66.924 90.029 76.23 90.077 ;
     RECT  21.24 90.005 25.866 90.113 ;
     RECT  60.768 90.077 65.898 90.121 ;
     RECT  25.56 90.113 25.866 90.239 ;
     RECT  26.715 90.041 41.814 90.239 ;
     RECT  42.876 90.041 52.002 90.239 ;
     RECT  52.992 90.044 55.638 90.239 ;
     RECT  60.732 90.121 65.898 90.239 ;
     RECT  66.924 90.077 76.194 90.239 ;
     RECT  76.968 89.879 80.997 90.239 ;
     RECT  9.828 90.041 20.178 90.275 ;
     RECT  26.715 90.239 41.598 90.275 ;
     RECT  42.876 90.239 44.262 90.275 ;
     RECT  45.216 90.239 45.954 90.275 ;
     RECT  46.872 90.239 52.002 90.275 ;
     RECT  52.992 90.239 54.27 90.275 ;
     RECT  55.008 90.239 55.494 90.275 ;
     RECT  56.376 90.044 59.994 90.275 ;
     RECT  60.732 90.239 65.718 90.275 ;
     RECT  66.924 90.239 75.597 90.275 ;
     RECT  25.668 90.239 25.866 90.283 ;
     RECT  26.715 90.275 33.102 90.283 ;
     RECT  53.028 90.275 54.27 90.317 ;
     RECT  11.664 90.275 20.178 90.347 ;
     RECT  56.415 90.275 59.994 90.347 ;
     RECT  66.996 90.275 75.597 90.347 ;
     RECT  77.004 90.239 79.974 90.347 ;
     RECT  60.732 90.275 64.926 90.355 ;
     RECT  33.84 90.275 41.598 90.365 ;
     RECT  25.668 90.283 33.102 90.383 ;
     RECT  33.84 90.365 35.55 90.383 ;
     RECT  46.872 90.275 49.59 90.383 ;
     RECT  60.624 90.355 64.926 90.383 ;
     RECT  26.064 90.383 33.102 90.419 ;
     RECT  36.288 90.365 41.598 90.419 ;
     RECT  2.415 89.159 2.697 90.467 ;
     RECT  5.115 89.879 5.397 90.467 ;
     RECT  7.815 89.699 8.097 90.467 ;
     RECT  9.828 90.275 10.797 90.467 ;
     RECT  11.664 90.347 16.197 90.467 ;
     RECT  28.224 90.419 29.697 90.467 ;
     RECT  36.288 90.419 37.797 90.467 ;
     RECT  38.52 90.419 41.598 90.467 ;
     RECT  45.216 90.275 45.897 90.467 ;
     RECT  53.028 90.317 53.997 90.467 ;
     RECT  68.76 90.347 75.597 90.467 ;
     RECT  80.715 90.239 80.997 90.467 ;
     RECT  83.415 88.799 83.697 90.467 ;
     RECT  11.664 90.467 16.005 90.509 ;
     RECT  17.172 90.347 17.334 90.509 ;
     RECT  18.288 90.347 20.178 90.509 ;
     RECT  21.24 90.113 24.534 90.509 ;
     RECT  28.224 90.467 29.505 90.509 ;
     RECT  30.564 90.419 33.102 90.509 ;
     RECT  33.84 90.383 33.966 90.509 ;
     RECT  34.815 90.383 35.55 90.509 ;
     RECT  36.288 90.467 37.605 90.509 ;
     RECT  38.52 90.467 40.305 90.509 ;
     RECT  41.076 90.467 41.598 90.509 ;
     RECT  42.915 90.275 44.262 90.509 ;
     RECT  46.872 90.383 47.034 90.509 ;
     RECT  47.808 90.383 49.59 90.509 ;
     RECT  50.868 90.275 52.002 90.509 ;
     RECT  53.028 90.467 53.805 90.509 ;
     RECT  55.008 90.275 55.134 90.509 ;
     RECT  56.415 90.347 59.886 90.509 ;
     RECT  60.624 90.383 64.854 90.509 ;
     RECT  66.996 90.347 67.914 90.509 ;
     RECT  68.76 90.467 72.705 90.509 ;
     RECT  78.015 90.347 79.974 90.509 ;
     RECT  26.064 90.419 27.45 90.515 ;
     RECT  59.115 90.509 59.742 90.515 ;
     RECT  15.192 90.509 16.005 90.545 ;
     RECT  18.504 90.509 18.99 90.545 ;
     RECT  19.8 90.509 20.178 90.545 ;
     RECT  21.24 90.509 21.87 90.545 ;
     RECT  22.644 90.509 24.534 90.545 ;
     RECT  26.064 90.515 26.805 90.545 ;
     RECT  33.84 90.509 33.858 90.545 ;
     RECT  34.815 90.509 35.154 90.545 ;
     RECT  36.972 90.509 37.605 90.545 ;
     RECT  45.216 90.467 45.705 90.545 ;
     RECT  55.008 90.509 55.026 90.545 ;
     RECT  56.415 90.509 58.338 90.545 ;
     RECT  60.768 90.509 60.786 90.545 ;
     RECT  61.815 90.509 64.605 90.545 ;
     RECT  66.996 90.509 67.59 90.545 ;
     RECT  68.76 90.509 69.174 90.545 ;
     RECT  69.915 90.509 71.766 90.545 ;
     RECT  73.548 90.467 75.405 90.545 ;
     RECT  78.984 90.509 79.326 90.545 ;
     RECT  9.828 90.467 10.674 90.557 ;
     RECT  11.664 90.509 11.682 90.557 ;
     RECT  30.564 90.509 30.582 90.557 ;
     RECT  31.896 90.509 33.102 90.557 ;
     RECT  41.076 90.509 41.094 90.557 ;
     RECT  42.915 90.509 43.074 90.557 ;
     RECT  44.244 90.509 44.262 90.557 ;
     RECT  48.024 90.509 48.906 90.557 ;
     RECT  13.215 90.509 13.626 90.581 ;
     RECT  23.364 90.545 24.534 90.581 ;
     RECT  48.276 90.557 48.405 90.581 ;
     RECT  63.9 90.545 64.605 90.581 ;
     RECT  70.992 90.545 71.694 90.581 ;
     RECT  73.548 90.545 73.566 90.581 ;
     RECT  18.504 90.545 18.738 90.617 ;
     RECT  20.016 90.545 20.034 90.617 ;
     RECT  28.692 90.509 29.505 90.617 ;
     RECT  38.52 90.509 38.538 90.617 ;
     RECT  39.6 90.509 40.305 90.617 ;
     RECT  56.415 90.545 56.97 90.617 ;
     RECT  58.32 90.545 58.338 90.617 ;
     RECT  62.712 90.545 62.73 90.617 ;
     RECT  67.215 90.545 67.59 90.617 ;
     RECT  68.796 90.545 68.814 90.617 ;
     RECT  70.992 90.581 71.55 90.617 ;
     RECT  77.004 90.347 77.022 90.617 ;
     RECT  10.515 90.557 10.674 90.689 ;
     RECT  2.415 90.467 2.505 90.737 ;
     RECT  5.115 90.467 5.205 90.737 ;
     RECT  7.815 90.467 7.905 90.737 ;
     RECT  10.515 90.689 10.605 90.737 ;
     RECT  13.215 90.581 13.305 90.737 ;
     RECT  15.915 90.545 16.005 90.737 ;
     RECT  18.615 90.617 18.705 90.737 ;
     RECT  21.315 90.545 21.405 90.737 ;
     RECT  24.015 90.581 24.105 90.737 ;
     RECT  26.715 90.545 26.805 90.737 ;
     RECT  29.415 90.617 29.505 90.737 ;
     RECT  32.115 90.557 32.205 90.737 ;
     RECT  34.815 90.545 34.905 90.737 ;
     RECT  37.515 90.545 37.605 90.737 ;
     RECT  40.215 90.617 40.305 90.737 ;
     RECT  42.915 90.557 43.005 90.737 ;
     RECT  45.615 90.545 45.705 90.737 ;
     RECT  48.315 90.581 48.405 90.737 ;
     RECT  51.015 90.509 51.105 90.737 ;
     RECT  53.715 90.509 53.805 90.737 ;
     RECT  56.415 90.617 56.505 90.737 ;
     RECT  59.115 90.515 59.205 90.737 ;
     RECT  61.815 90.545 61.905 90.737 ;
     RECT  64.515 90.581 64.605 90.737 ;
     RECT  67.215 90.617 67.305 90.737 ;
     RECT  69.915 90.545 70.005 90.737 ;
     RECT  72.615 90.509 72.705 90.737 ;
     RECT  75.315 90.545 75.405 90.737 ;
     RECT  78.015 90.509 78.105 90.737 ;
     RECT  80.715 90.467 80.805 90.737 ;
     RECT  83.415 90.467 83.505 90.737 ;
    LAYER M4 ;
     RECT  0.156 4.416 0.245 88.536 ;
     RECT  0.245 4.416 2.408 88.2 ;
     RECT  2.408 2.148 2.512 90.732 ;
     RECT  2.512 2.418 2.704 90.462 ;
     RECT  2.704 3.936 2.819 47.112 ;
     RECT  2.819 4.032 2.837 47.112 ;
     RECT  2.704 48.24 2.837 54.744 ;
     RECT  2.704 55.728 2.837 56.04 ;
     RECT  2.837 4.032 3.089 47.064 ;
     RECT  2.704 60.288 3.161 89.064 ;
     RECT  3.161 60.288 3.769 70.008 ;
     RECT  2.837 55.728 3.805 55.8 ;
     RECT  3.161 71.616 3.845 89.064 ;
     RECT  2.837 51.84 3.913 54.744 ;
     RECT  3.805 55.728 3.913 55.992 ;
     RECT  2.837 48.48 3.985 50.616 ;
     RECT  3.913 51.84 4.057 55.992 ;
     RECT  2.704 57.024 4.057 59.064 ;
     RECT  3.845 71.616 4.201 88.776 ;
     RECT  3.769 60.096 4.237 70.008 ;
     RECT  3.985 48.48 4.273 50.856 ;
     RECT  4.057 51.84 4.273 59.064 ;
     RECT  3.089 4.176 4.309 47.064 ;
     RECT  4.273 48.48 4.309 59.064 ;
     RECT  4.237 60.096 4.345 70.344 ;
     RECT  4.201 71.376 4.345 88.776 ;
     RECT  4.309 4.176 4.501 59.064 ;
     RECT  4.501 3.936 4.525 59.064 ;
     RECT  4.345 60.096 4.525 88.776 ;
     RECT  4.525 3.936 5.108 88.776 ;
     RECT  3.913 89.808 5.108 89.832 ;
     RECT  5.108 2.148 5.212 90.732 ;
     RECT  5.212 2.418 5.404 90.462 ;
     RECT  5.404 74.16 6.041 89.832 ;
     RECT  5.404 3.456 6.397 73.08 ;
     RECT  6.397 3.456 6.577 73.128 ;
     RECT  6.041 74.16 6.577 88.92 ;
     RECT  6.577 3.456 6.721 88.92 ;
     RECT  6.721 3.408 7.808 88.92 ;
     RECT  7.808 2.148 7.912 90.732 ;
     RECT  7.912 2.418 8.104 90.462 ;
     RECT  8.104 28.704 8.165 41.976 ;
     RECT  8.104 75.648 8.281 89.448 ;
     RECT  8.104 43.584 8.345 74.664 ;
     RECT  8.281 79.008 8.669 89.448 ;
     RECT  8.669 85.728 8.956 89.448 ;
     RECT  8.165 31.104 9.349 41.976 ;
     RECT  8.345 61.632 9.457 74.664 ;
     RECT  8.345 43.584 9.493 60.408 ;
     RECT  9.457 61.44 9.493 74.664 ;
     RECT  8.281 75.648 9.529 77.976 ;
     RECT  8.669 79.008 9.529 84.744 ;
     RECT  9.349 31.104 9.673 42.504 ;
     RECT  9.493 43.584 9.685 74.664 ;
     RECT  9.529 75.648 9.685 84.744 ;
     RECT  8.165 28.704 9.853 30.072 ;
     RECT  9.673 31.104 9.853 42.552 ;
     RECT  8.104 4.176 9.925 27.432 ;
     RECT  9.853 28.704 9.925 42.552 ;
     RECT  9.685 43.584 9.997 84.744 ;
     RECT  8.956 85.728 9.997 88.92 ;
     RECT  9.925 4.176 10.316 42.552 ;
     RECT  9.997 43.584 10.316 88.92 ;
     RECT  10.316 4.176 10.357 88.92 ;
     RECT  10.357 4.08 10.501 88.92 ;
     RECT  8.104 2.496 10.508 2.52 ;
     RECT  10.501 3.6 10.508 88.92 ;
     RECT  9.817 90.528 10.508 90.552 ;
     RECT  10.508 2.148 10.612 90.732 ;
     RECT  10.612 2.418 10.804 90.552 ;
     RECT  10.804 60.384 10.865 90.552 ;
     RECT  10.865 60.384 10.973 60.408 ;
     RECT  10.804 2.496 11.233 33.384 ;
     RECT  10.865 61.44 11.405 90.552 ;
     RECT  11.405 69.504 11.513 90.552 ;
     RECT  11.513 77.568 11.693 90.552 ;
     RECT  10.804 34.464 11.797 59.016 ;
     RECT  11.233 4.176 11.909 33.384 ;
     RECT  11.693 77.568 12.035 90.12 ;
     RECT  11.405 61.44 12.037 68.52 ;
     RECT  11.797 34.464 12.085 59.256 ;
     RECT  12.037 60.96 12.124 68.52 ;
     RECT  12.085 34.368 12.193 59.256 ;
     RECT  11.513 69.504 12.22 76.344 ;
     RECT  12.124 61.392 12.373 68.52 ;
     RECT  12.22 69.504 12.373 71.208 ;
     RECT  12.193 34.368 12.517 59.592 ;
     RECT  11.233 2.496 12.625 2.52 ;
     RECT  11.909 4.176 12.949 24.792 ;
     RECT  11.909 25.776 12.949 33.384 ;
     RECT  12.949 4.176 13.021 33.384 ;
     RECT  12.625 2.496 13.208 2.856 ;
     RECT  13.021 4.128 13.208 33.384 ;
     RECT  12.517 34.368 13.208 60.408 ;
     RECT  12.373 61.392 13.208 71.208 ;
     RECT  12.22 72.192 13.208 76.344 ;
     RECT  12.035 77.568 13.208 88.92 ;
     RECT  12.035 90.096 13.208 90.12 ;
     RECT  13.208 2.148 13.312 90.732 ;
     RECT  13.312 2.418 13.504 90.462 ;
     RECT  13.504 2.496 13.565 71.208 ;
     RECT  13.565 3.408 13.745 71.208 ;
     RECT  13.745 18.48 13.781 50.664 ;
     RECT  13.504 81.408 13.817 90.12 ;
     RECT  13.745 51.648 13.997 71.208 ;
     RECT  13.504 72.192 14.033 80.376 ;
     RECT  13.997 64.32 14.141 71.208 ;
     RECT  14.033 77.808 14.497 80.376 ;
     RECT  13.817 81.408 14.497 89.016 ;
     RECT  14.033 72.192 14.605 76.776 ;
     RECT  13.781 34.464 14.857 50.664 ;
     RECT  13.997 51.648 14.857 63.24 ;
     RECT  13.745 3.408 14.861 17.496 ;
     RECT  13.781 18.48 15.037 33.432 ;
     RECT  14.857 34.464 15.037 63.24 ;
     RECT  15.037 18.48 15.109 63.24 ;
     RECT  14.141 64.32 15.109 70.92 ;
     RECT  15.109 18.48 15.145 70.92 ;
     RECT  14.605 72 15.145 76.776 ;
     RECT  14.497 77.808 15.181 89.016 ;
     RECT  14.861 5.184 15.469 17.496 ;
     RECT  15.145 18.48 15.469 76.776 ;
     RECT  14.861 3.408 15.793 4.2 ;
     RECT  15.469 5.184 15.793 76.776 ;
     RECT  15.793 2.784 15.908 4.2 ;
     RECT  15.793 5.184 15.908 76.824 ;
     RECT  15.181 77.808 15.908 89.448 ;
     RECT  15.908 2.148 16.012 90.732 ;
     RECT  16.012 2.418 16.204 90.462 ;
     RECT  16.204 2.784 16.589 76.872 ;
     RECT  16.204 77.904 16.841 90.072 ;
     RECT  16.841 77.904 17.237 83.832 ;
     RECT  16.589 51.216 17.417 76.824 ;
     RECT  17.417 60.96 17.489 76.824 ;
     RECT  16.589 2.784 17.809 50.136 ;
     RECT  17.417 51.216 17.809 59.592 ;
     RECT  17.489 61.008 18.044 76.824 ;
     RECT  17.237 77.904 18.044 79.032 ;
     RECT  17.237 80.112 18.085 83.832 ;
     RECT  16.841 85.104 18.085 90.072 ;
     RECT  18.044 61.008 18.229 79.032 ;
     RECT  18.085 80.112 18.229 90.072 ;
     RECT  17.809 2.784 18.608 59.592 ;
     RECT  18.229 61.008 18.608 90.072 ;
     RECT  18.608 2.148 18.712 90.732 ;
     RECT  18.712 2.418 18.904 90.462 ;
     RECT  18.904 12.24 19.145 90.072 ;
     RECT  19.145 12.24 19.181 50.664 ;
     RECT  18.904 2.496 19.289 8.52 ;
     RECT  19.145 51.648 19.427 90.072 ;
     RECT  19.181 26.064 19.433 50.664 ;
     RECT  19.427 63.504 19.433 90.072 ;
     RECT  19.181 12.24 19.541 25.08 ;
     RECT  19.433 44.16 19.541 50.664 ;
     RECT  18.904 9.888 19.992 11.016 ;
     RECT  19.289 2.496 20.041 2.52 ;
     RECT  19.433 26.064 20.051 43.176 ;
     RECT  19.992 9.648 20.053 11.016 ;
     RECT  19.541 12.24 20.053 25.032 ;
     RECT  19.433 63.504 20.081 89.496 ;
     RECT  19.541 47.04 20.197 50.664 ;
     RECT  19.427 51.648 20.197 62.52 ;
     RECT  20.051 26.064 20.297 32.616 ;
     RECT  20.051 33.6 20.401 43.176 ;
     RECT  19.541 44.16 20.401 45.864 ;
     RECT  20.041 2.304 20.473 2.52 ;
     RECT  19.289 4.128 20.473 8.52 ;
     RECT  20.401 33.6 20.533 45.864 ;
     RECT  20.197 47.04 20.533 62.52 ;
     RECT  20.473 2.304 20.725 8.52 ;
     RECT  20.053 9.648 20.725 25.032 ;
     RECT  20.297 28.944 21.085 32.616 ;
     RECT  20.533 33.6 21.085 62.52 ;
     RECT  20.081 63.504 21.157 89.256 ;
     RECT  20.725 2.304 21.308 25.032 ;
     RECT  20.297 26.064 21.308 27.912 ;
     RECT  21.085 28.944 21.308 62.52 ;
     RECT  21.157 63.504 21.308 90.12 ;
     RECT  21.308 2.148 21.412 90.732 ;
     RECT  21.412 2.418 21.604 90.462 ;
     RECT  21.604 55.728 22.061 74.664 ;
     RECT  21.604 28.896 22.277 54.648 ;
     RECT  22.061 55.872 22.385 74.664 ;
     RECT  21.604 2.418 22.453 27.912 ;
     RECT  21.604 75.744 22.637 89.448 ;
     RECT  22.637 75.744 22.705 84.12 ;
     RECT  22.637 85.152 22.741 89.448 ;
     RECT  22.277 47.088 22.817 54.648 ;
     RECT  22.453 2.304 22.892 27.912 ;
     RECT  22.277 28.896 22.892 45.864 ;
     RECT  22.385 68.928 22.957 74.664 ;
     RECT  22.705 75.696 22.957 84.12 ;
     RECT  22.817 51.216 23.077 54.648 ;
     RECT  22.957 68.928 23.605 84.12 ;
     RECT  22.741 85.152 23.605 89.736 ;
     RECT  22.385 55.872 23.66 67.848 ;
     RECT  23.605 68.928 23.66 89.736 ;
     RECT  17.365 0.192 23.789 0.216 ;
     RECT  23.077 51.216 24.001 54.696 ;
     RECT  23.66 55.872 24.001 89.736 ;
     RECT  22.892 2.304 24.008 45.864 ;
     RECT  22.817 47.088 24.008 50.136 ;
     RECT  24.001 51.216 24.008 89.736 ;
     RECT  24.008 2.148 24.112 90.732 ;
     RECT  24.112 2.418 24.304 90.462 ;
     RECT  24.304 2.592 24.419 8.52 ;
     RECT  24.419 2.592 24.473 3.144 ;
     RECT  24.304 69.024 24.545 90.36 ;
     RECT  24.304 54.048 24.563 67.944 ;
     RECT  24.304 9.888 24.581 53.016 ;
     RECT  24.545 77.472 25.043 90.36 ;
     RECT  25.043 77.472 25.193 89.256 ;
     RECT  24.563 54.384 25.549 67.944 ;
     RECT  24.545 69.024 25.549 76.488 ;
     RECT  24.419 4.176 25.573 8.52 ;
     RECT  24.581 9.888 25.585 27.96 ;
     RECT  24.581 28.992 25.585 53.016 ;
     RECT  25.585 9.888 25.621 53.016 ;
     RECT  25.549 54.384 25.628 76.488 ;
     RECT  25.193 77.472 25.628 80.376 ;
     RECT  25.573 4.176 25.66 8.664 ;
     RECT  25.621 9.888 25.669 53.4 ;
     RECT  25.628 54.384 25.669 80.376 ;
     RECT  25.669 9.888 25.715 80.376 ;
     RECT  24.473 3.12 25.981 3.144 ;
     RECT  25.66 4.176 25.981 8.52 ;
     RECT  25.981 3.12 26.708 8.52 ;
     RECT  25.715 9.888 26.708 76.488 ;
     RECT  25.715 77.472 26.708 80.376 ;
     RECT  25.193 81.456 26.708 89.256 ;
     RECT  25.043 90.336 26.708 90.36 ;
     RECT  26.708 2.148 26.812 90.732 ;
     RECT  26.812 2.418 27.004 90.504 ;
     RECT  27.004 9.696 27.155 23.976 ;
     RECT  27.004 24.96 27.155 70.68 ;
     RECT  27.155 24.96 27.173 53.4 ;
     RECT  27.155 54.432 27.209 70.68 ;
     RECT  27.173 34.368 27.749 53.4 ;
     RECT  27.209 54.432 27.965 69.336 ;
     RECT  27.965 54.432 27.971 65.256 ;
     RECT  27.004 89.952 27.971 90.504 ;
     RECT  27.971 54.432 28.001 59.832 ;
     RECT  27.155 9.888 28.069 23.976 ;
     RECT  27.173 24.96 28.069 27.72 ;
     RECT  27.749 34.464 28.141 53.4 ;
     RECT  28.001 54.432 28.141 59.736 ;
     RECT  27.004 71.712 28.285 76.488 ;
     RECT  27.004 77.472 28.285 88.92 ;
     RECT  28.069 9.888 28.321 27.72 ;
     RECT  27.173 29.088 28.321 33.384 ;
     RECT  27.209 70.608 28.465 70.68 ;
     RECT  28.285 71.712 28.465 88.92 ;
     RECT  27.004 2.592 28.501 8.52 ;
     RECT  28.465 70.608 28.753 88.92 ;
     RECT  27.971 89.952 28.753 89.976 ;
     RECT  28.321 9.888 29.005 33.384 ;
     RECT  28.141 34.464 29.005 59.736 ;
     RECT  28.501 2.304 29.041 8.52 ;
     RECT  29.005 9.888 29.041 59.736 ;
     RECT  28.753 70.608 29.113 89.976 ;
     RECT  27.965 66.288 29.269 69.336 ;
     RECT  29.113 70.368 29.269 89.976 ;
     RECT  29.041 2.304 29.408 59.736 ;
     RECT  27.971 61.44 29.408 65.256 ;
     RECT  29.269 66.288 29.408 89.976 ;
     RECT  29.408 2.148 29.512 90.732 ;
     RECT  29.512 2.418 29.704 90.462 ;
     RECT  29.704 9.888 29.873 28.296 ;
     RECT  29.873 25.008 29.909 28.296 ;
     RECT  29.704 44.16 29.909 90.462 ;
     RECT  29.704 29.568 29.945 43.176 ;
     RECT  29.704 3.024 30.017 8.52 ;
     RECT  29.909 60 30.053 90.462 ;
     RECT  30.017 3.024 30.197 3.048 ;
     RECT  29.945 29.568 30.233 37.704 ;
     RECT  30.053 60.576 30.269 90.462 ;
     RECT  29.945 38.688 30.341 43.176 ;
     RECT  30.341 38.736 30.364 43.176 ;
     RECT  29.909 44.16 30.467 59.016 ;
     RECT  30.269 60.576 30.593 89.496 ;
     RECT  30.593 66.288 30.629 89.496 ;
     RECT  29.909 25.152 30.917 28.296 ;
     RECT  30.233 29.568 30.917 37.416 ;
     RECT  30.629 75.744 31.061 89.496 ;
     RECT  30.017 4.176 31.201 8.52 ;
     RECT  29.873 9.888 31.237 23.832 ;
     RECT  31.201 4.176 31.669 8.568 ;
     RECT  30.917 29.568 31.669 37.176 ;
     RECT  30.467 44.16 31.849 54.408 ;
     RECT  30.467 55.536 31.849 59.016 ;
     RECT  30.629 66.288 31.849 74.712 ;
     RECT  31.061 75.744 31.849 88.776 ;
     RECT  30.364 38.736 31.885 43.128 ;
     RECT  30.917 25.152 31.921 27.912 ;
     RECT  31.669 29.184 31.921 37.176 ;
     RECT  31.669 3.696 31.957 8.568 ;
     RECT  31.237 9.888 31.957 23.928 ;
     RECT  31.921 25.152 31.957 37.176 ;
     RECT  31.885 38.496 31.957 43.128 ;
     RECT  30.593 60.576 31.957 65.256 ;
     RECT  31.849 66.288 31.957 88.776 ;
     RECT  31.957 3.12 32.108 8.568 ;
     RECT  31.957 9.888 32.108 43.128 ;
     RECT  31.849 44.16 32.108 59.016 ;
     RECT  31.957 60.576 32.108 88.776 ;
     RECT  30.553 90.528 32.108 90.552 ;
     RECT  32.108 2.148 32.212 90.732 ;
     RECT  32.212 2.418 32.404 90.552 ;
     RECT  32.404 51.12 32.573 53.4 ;
     RECT  32.404 90.24 33.113 90.552 ;
     RECT  32.404 71.712 33.149 89.16 ;
     RECT  32.404 9.552 33.293 43.128 ;
     RECT  33.149 71.712 33.329 89.016 ;
     RECT  32.573 51.168 33.433 53.4 ;
     RECT  32.404 54.384 33.433 59.016 ;
     RECT  32.404 60.576 33.469 70.632 ;
     RECT  33.329 71.712 33.469 88.776 ;
     RECT  33.433 51.168 33.509 59.016 ;
     RECT  33.509 55.776 33.541 59.016 ;
     RECT  32.404 4.176 33.577 8.52 ;
     RECT  33.293 9.552 33.577 23.976 ;
     RECT  33.293 25.152 33.653 43.128 ;
     RECT  33.653 28.992 33.689 43.128 ;
     RECT  33.541 55.776 33.721 59.544 ;
     RECT  33.469 60.576 33.721 88.776 ;
     RECT  32.404 2.496 33.733 2.856 ;
     RECT  33.577 4.176 33.733 23.976 ;
     RECT  32.404 44.16 33.973 50.136 ;
     RECT  33.509 51.168 33.973 54.744 ;
     RECT  33.689 38.4 34.117 43.128 ;
     RECT  33.973 44.16 34.117 54.744 ;
     RECT  33.733 2.496 34.808 23.976 ;
     RECT  33.653 25.152 34.808 27.72 ;
     RECT  33.689 28.992 34.808 37.176 ;
     RECT  34.117 38.4 34.808 54.744 ;
     RECT  33.721 55.776 34.808 88.776 ;
     RECT  33.113 90.24 34.808 90.264 ;
     RECT  34.808 2.148 34.912 90.732 ;
     RECT  34.912 2.256 35.104 90.462 ;
     RECT  35.104 3.408 35.129 8.52 ;
     RECT  35.104 9.744 35.267 33.384 ;
     RECT  35.267 9.744 35.597 28.536 ;
     RECT  35.104 34.368 35.669 53.4 ;
     RECT  35.597 25.056 35.705 28.536 ;
     RECT  35.104 54.384 35.795 76.776 ;
     RECT  35.104 2.256 35.813 2.28 ;
     RECT  35.597 9.744 36.029 23.928 ;
     RECT  35.669 44.16 36.085 53.4 ;
     RECT  35.795 54.384 36.085 65.256 ;
     RECT  35.104 90.336 36.205 90.36 ;
     RECT  36.205 90.048 36.245 90.36 ;
     RECT  35.129 3.696 36.277 8.52 ;
     RECT  35.267 29.568 36.421 33.384 ;
     RECT  35.669 34.368 36.421 43.128 ;
     RECT  36.085 44.16 36.533 65.256 ;
     RECT  35.795 66.288 36.673 76.776 ;
     RECT  35.104 77.76 36.673 88.776 ;
     RECT  36.673 66.288 36.925 88.776 ;
     RECT  36.029 9.888 37.004 23.928 ;
     RECT  35.705 25.152 37.004 28.536 ;
     RECT  36.925 66.288 37.465 88.92 ;
     RECT  36.245 90.048 37.465 90.072 ;
     RECT  37.501 2.592 37.508 2.616 ;
     RECT  36.277 3.696 37.508 8.568 ;
     RECT  37.004 9.888 37.508 28.536 ;
     RECT  36.421 29.568 37.508 43.128 ;
     RECT  36.533 44.16 37.508 50.136 ;
     RECT  36.533 51.168 37.508 65.256 ;
     RECT  37.465 66.288 37.508 90.072 ;
     RECT  37.508 2.148 37.612 90.732 ;
     RECT  37.612 2.418 37.804 90.6 ;
     RECT  37.804 60.288 38.099 76.296 ;
     RECT  37.804 81.696 38.771 90.6 ;
     RECT  38.099 60.816 38.833 76.296 ;
     RECT  38.771 81.696 38.869 89.304 ;
     RECT  38.833 60.816 38.941 76.392 ;
     RECT  37.804 77.904 38.941 80.376 ;
     RECT  38.941 60.816 38.977 80.376 ;
     RECT  38.869 81.456 38.977 89.304 ;
     RECT  37.804 25.152 39.161 55.464 ;
     RECT  39.161 44.112 39.205 55.464 ;
     RECT  37.804 56.496 39.205 59.256 ;
     RECT  38.977 60.816 39.229 89.304 ;
     RECT  37.804 2.592 39.301 3.144 ;
     RECT  37.804 4.128 39.301 23.928 ;
     RECT  39.205 44.112 39.589 59.256 ;
     RECT  39.229 60.384 39.589 89.304 ;
     RECT  38.771 90.576 40.057 90.6 ;
     RECT  39.301 2.592 40.069 23.928 ;
     RECT  40.069 2.592 40.208 24.12 ;
     RECT  39.161 25.152 40.208 43.128 ;
     RECT  39.589 44.112 40.208 89.304 ;
     RECT  40.057 90.528 40.208 90.6 ;
     RECT  40.208 2.148 40.312 90.732 ;
     RECT  40.312 2.418 40.504 90.552 ;
     RECT  40.504 44.112 40.601 54.696 ;
     RECT  40.504 2.592 40.709 27.912 ;
     RECT  40.709 2.592 40.781 8.52 ;
     RECT  40.601 44.112 40.787 54.648 ;
     RECT  40.709 9.792 40.961 27.912 ;
     RECT  40.504 60.912 40.997 89.256 ;
     RECT  40.504 90.528 41.105 90.552 ;
     RECT  40.961 18.48 41.164 27.912 ;
     RECT  41.164 25.152 41.804 27.912 ;
     RECT  40.504 28.992 41.804 43.128 ;
     RECT  40.997 66.288 41.861 89.256 ;
     RECT  41.804 25.152 41.891 43.128 ;
     RECT  40.997 60.912 41.965 65.256 ;
     RECT  41.861 66.288 41.965 70.536 ;
     RECT  41.861 71.664 42.109 89.256 ;
     RECT  40.781 2.832 42.145 8.52 ;
     RECT  42.145 2.784 42.289 8.52 ;
     RECT  40.961 9.792 42.289 17.496 ;
     RECT  41.164 18.48 42.325 23.928 ;
     RECT  41.891 25.152 42.325 27.72 ;
     RECT  41.891 29.568 42.361 43.128 ;
     RECT  40.787 44.16 42.361 54.648 ;
     RECT  41.965 60.912 42.577 70.536 ;
     RECT  42.361 29.568 42.613 54.648 ;
     RECT  40.504 55.872 42.613 59.64 ;
     RECT  42.289 2.784 42.649 17.496 ;
     RECT  42.325 18.48 42.649 27.72 ;
     RECT  42.613 29.568 42.685 59.64 ;
     RECT  42.577 60.672 42.685 70.536 ;
     RECT  42.109 71.664 42.757 90.024 ;
     RECT  42.685 29.568 42.829 70.536 ;
     RECT  42.649 2.784 42.908 27.72 ;
     RECT  42.829 29.568 42.908 70.632 ;
     RECT  42.757 71.664 42.908 90.552 ;
     RECT  42.908 2.148 43.012 90.732 ;
     RECT  43.012 2.256 43.204 90.552 ;
     RECT  43.204 71.712 43.331 89.304 ;
     RECT  43.204 9.792 43.373 59.064 ;
     RECT  43.204 2.256 43.619 8.52 ;
     RECT  43.619 3.408 43.625 8.52 ;
     RECT  43.625 3.936 43.667 8.52 ;
     RECT  43.373 18.48 43.877 59.064 ;
     RECT  43.877 38.736 43.913 59.064 ;
     RECT  43.619 2.256 44.165 2.28 ;
     RECT  43.913 51.12 44.165 59.064 ;
     RECT  44.165 56.016 44.269 59.064 ;
     RECT  43.204 60.432 44.269 70.632 ;
     RECT  43.204 90.528 44.273 90.552 ;
     RECT  43.331 71.712 44.339 89.256 ;
     RECT  44.339 77.904 44.413 89.256 ;
     RECT  43.373 9.792 44.437 17.496 ;
     RECT  44.269 56.016 44.629 70.632 ;
     RECT  44.339 71.712 44.629 76.776 ;
     RECT  43.667 4.176 44.737 8.52 ;
     RECT  44.437 9.648 44.737 17.496 ;
     RECT  43.913 38.736 44.989 50.136 ;
     RECT  44.165 51.12 44.989 54.888 ;
     RECT  45.601 2.304 45.608 2.328 ;
     RECT  44.737 4.176 45.608 17.496 ;
     RECT  43.877 18.48 45.608 37.704 ;
     RECT  44.989 38.736 45.608 54.888 ;
     RECT  44.629 56.016 45.608 76.776 ;
     RECT  44.413 77.904 45.608 89.304 ;
     RECT  45.608 2.148 45.712 90.732 ;
     RECT  45.712 2.304 45.904 90.462 ;
     RECT  45.904 60.864 45.965 90.408 ;
     RECT  45.904 2.304 46.019 24.216 ;
     RECT  46.019 3.84 46.145 24.216 ;
     RECT  45.965 61.104 46.181 90.408 ;
     RECT  46.181 61.104 46.505 89.304 ;
     RECT  45.904 25.248 46.513 59.496 ;
     RECT  46.019 2.304 46.541 2.856 ;
     RECT  46.505 61.104 46.541 69.48 ;
     RECT  46.145 9.552 46.685 24.216 ;
     RECT  46.685 9.552 46.793 17.448 ;
     RECT  46.513 38.688 47.084 59.496 ;
     RECT  47.084 38.688 47.125 59.736 ;
     RECT  46.685 18.432 47.257 24.216 ;
     RECT  46.513 25.248 47.257 37.704 ;
     RECT  46.505 70.512 47.315 89.304 ;
     RECT  46.145 3.84 47.333 8.52 ;
     RECT  47.125 38.688 47.333 60.264 ;
     RECT  47.315 81.6 47.365 89.304 ;
     RECT  46.181 90.384 47.365 90.408 ;
     RECT  46.541 61.44 47.749 69.48 ;
     RECT  47.365 81.6 48.013 90.408 ;
     RECT  46.793 9.888 48.085 17.448 ;
     RECT  47.257 18.432 48.085 37.704 ;
     RECT  48.085 9.888 48.181 37.704 ;
     RECT  47.333 38.688 48.181 59.88 ;
     RECT  47.333 3.888 48.229 8.52 ;
     RECT  48.181 9.888 48.229 59.88 ;
     RECT  46.541 2.784 48.308 2.856 ;
     RECT  48.229 3.888 48.308 59.88 ;
     RECT  47.749 61.44 48.308 69.528 ;
     RECT  47.315 70.512 48.308 80.376 ;
     RECT  48.013 81.6 48.308 90.552 ;
     RECT  48.308 2.148 48.412 90.732 ;
     RECT  48.412 2.418 48.604 90.552 ;
     RECT  48.604 3.888 48.809 24.12 ;
     RECT  48.604 29.568 48.809 76.296 ;
     RECT  48.604 90 48.917 90.552 ;
     RECT  48.809 29.568 48.947 60.408 ;
     RECT  48.947 38.736 49.421 60.408 ;
     RECT  48.917 90 49.565 90.072 ;
     RECT  48.604 25.152 49.633 28.2 ;
     RECT  48.947 29.568 49.633 37.704 ;
     RECT  48.809 61.44 49.715 76.296 ;
     RECT  48.604 77.52 49.741 80.376 ;
     RECT  48.604 81.456 49.741 88.92 ;
     RECT  48.604 2.832 49.745 2.856 ;
     RECT  49.633 25.152 49.817 37.704 ;
     RECT  48.809 3.888 49.961 23.928 ;
     RECT  49.421 51.168 50.101 60.408 ;
     RECT  49.715 61.44 50.101 69.48 ;
     RECT  49.741 77.52 50.173 88.92 ;
     RECT  49.715 70.56 50.245 76.296 ;
     RECT  50.173 77.52 50.245 88.968 ;
     RECT  50.101 51.168 50.749 69.48 ;
     RECT  50.245 70.56 50.749 88.968 ;
     RECT  49.565 90 50.857 90.024 ;
     RECT  50.749 51.168 50.929 88.968 ;
     RECT  50.893 2.832 51.008 2.856 ;
     RECT  49.961 3.936 51.008 23.928 ;
     RECT  49.817 25.152 51.008 27.912 ;
     RECT  49.817 28.992 51.008 37.704 ;
     RECT  49.421 38.736 51.008 50.136 ;
     RECT  50.929 51.12 51.008 88.968 ;
     RECT  50.857 90 51.008 90.36 ;
     RECT  51.008 2.148 51.112 90.732 ;
     RECT  51.112 2.418 51.304 90.462 ;
     RECT  51.304 4.128 51.617 23.928 ;
     RECT  51.304 90 51.869 90.36 ;
     RECT  51.617 9.36 51.905 23.928 ;
     RECT  51.304 25.152 51.905 37.704 ;
     RECT  51.304 38.736 51.905 54.936 ;
     RECT  51.869 90.336 52.013 90.36 ;
     RECT  51.617 4.128 52.259 8.28 ;
     RECT  51.905 9.504 52.333 23.928 ;
     RECT  52.333 9.504 52.369 24.12 ;
     RECT  51.905 25.152 52.369 28.008 ;
     RECT  51.304 56.016 52.501 59.64 ;
     RECT  52.501 56.016 52.549 59.88 ;
     RECT  51.304 60.912 52.549 80.376 ;
     RECT  52.549 56.016 52.553 80.376 ;
     RECT  52.369 9.504 52.909 28.008 ;
     RECT  51.905 29.232 52.909 37.704 ;
     RECT  52.553 64.128 53.017 80.376 ;
     RECT  51.304 81.456 53.017 88.68 ;
     RECT  52.259 4.224 53.029 8.28 ;
     RECT  52.909 9.504 53.029 37.704 ;
     RECT  52.553 56.016 53.125 63.048 ;
     RECT  53.017 64.128 53.521 88.68 ;
     RECT  51.905 44.16 53.557 54.936 ;
     RECT  53.125 55.968 53.557 63.048 ;
     RECT  53.557 44.16 53.665 63.048 ;
     RECT  53.521 64.128 53.665 88.968 ;
     RECT  51.304 2.832 53.708 2.856 ;
     RECT  53.029 4.224 53.708 37.704 ;
     RECT  51.905 38.736 53.708 43.128 ;
     RECT  53.665 44.16 53.708 88.968 ;
     RECT  53.708 2.148 53.812 90.732 ;
     RECT  53.812 2.208 54.004 90.462 ;
     RECT  54.004 34.368 54.065 37.608 ;
     RECT  54.004 38.784 54.317 76.488 ;
     RECT  54.317 38.784 54.389 50.136 ;
     RECT  54.317 51.12 54.611 76.488 ;
     RECT  54.004 90.048 54.755 90.312 ;
     RECT  54.004 3.504 54.821 17.496 ;
     RECT  54.821 3.504 55.037 8.28 ;
     RECT  54.004 77.904 55.141 88.92 ;
     RECT  54.004 18.48 55.285 33.384 ;
     RECT  54.065 34.368 55.285 37.368 ;
     RECT  54.611 70.608 55.321 76.488 ;
     RECT  55.141 77.568 55.321 88.92 ;
     RECT  55.321 70.608 55.325 88.92 ;
     RECT  55.325 70.608 55.405 88.68 ;
     RECT  54.821 9.888 55.429 17.496 ;
     RECT  55.285 18.48 55.429 37.368 ;
     RECT  54.389 44.16 55.681 50.136 ;
     RECT  54.611 51.12 55.681 69.576 ;
     RECT  54.389 38.784 55.753 43.032 ;
     RECT  55.429 9.888 55.825 37.368 ;
     RECT  55.681 44.16 55.825 69.576 ;
     RECT  55.405 70.608 55.825 76.344 ;
     RECT  55.825 9.84 56.149 37.368 ;
     RECT  54.004 2.208 56.293 2.376 ;
     RECT  55.753 38.784 56.293 43.128 ;
     RECT  55.825 44.16 56.293 76.344 ;
     RECT  56.293 2.208 56.408 2.856 ;
     RECT  55.037 3.936 56.408 8.28 ;
     RECT  56.149 9.84 56.408 37.656 ;
     RECT  56.293 38.784 56.408 76.344 ;
     RECT  55.405 77.568 56.408 88.68 ;
     RECT  54.755 90.048 56.408 90.072 ;
     RECT  56.408 2.148 56.512 90.732 ;
     RECT  56.512 2.418 56.704 90.462 ;
     RECT  56.704 3.936 56.837 28.536 ;
     RECT  56.704 29.856 57.197 76.344 ;
     RECT  57.197 29.856 57.269 76.296 ;
     RECT  56.704 77.52 57.269 88.776 ;
     RECT  56.837 3.936 57.341 12.648 ;
     RECT  57.269 81.696 57.521 88.776 ;
     RECT  57.269 29.856 57.539 63.048 ;
     RECT  57.539 39.024 57.587 63.048 ;
     RECT  57.587 44.16 57.629 63.048 ;
     RECT  57.269 64.128 57.629 76.296 ;
     RECT  56.837 13.68 57.665 28.536 ;
     RECT  57.341 9.84 57.773 12.648 ;
     RECT  57.539 29.856 58.021 37.464 ;
     RECT  57.629 70.32 58.237 76.296 ;
     RECT  57.269 77.52 58.237 80.616 ;
     RECT  57.521 81.696 58.237 88.44 ;
     RECT  57.985 89.472 58.237 89.496 ;
     RECT  57.629 61.104 58.309 63.048 ;
     RECT  57.629 64.128 58.309 69.336 ;
     RECT  57.773 9.888 58.345 12.648 ;
     RECT  57.665 13.68 58.345 28.2 ;
     RECT  58.309 61.104 58.633 69.336 ;
     RECT  58.237 70.32 58.633 88.44 ;
     RECT  58.345 9.888 58.669 28.2 ;
     RECT  58.633 61.104 58.693 88.44 ;
     RECT  58.237 89.472 58.693 89.88 ;
     RECT  57.587 39.024 58.705 43.128 ;
     RECT  57.629 44.16 58.705 59.832 ;
     RECT  58.021 29.616 58.849 37.464 ;
     RECT  58.705 39.024 58.849 59.832 ;
     RECT  57.341 3.936 58.957 8.28 ;
     RECT  58.669 9.888 58.957 28.488 ;
     RECT  58.957 3.936 59.108 28.488 ;
     RECT  58.849 29.616 59.108 59.832 ;
     RECT  58.693 61.104 59.108 89.88 ;
     RECT  59.108 2.148 59.212 90.732 ;
     RECT  59.212 2.418 59.404 90.504 ;
     RECT  59.404 2.832 59.501 23.928 ;
     RECT  59.404 60.816 59.537 89.496 ;
     RECT  59.404 25.248 59.753 59.496 ;
     RECT  59.537 77.904 59.861 89.496 ;
     RECT  59.861 77.904 59.933 88.872 ;
     RECT  59.501 2.832 59.969 12.36 ;
     RECT  59.933 77.904 60.113 81.144 ;
     RECT  59.753 25.248 60.329 40.68 ;
     RECT  59.537 60.816 60.329 76.296 ;
     RECT  59.969 3.696 60.469 12.36 ;
     RECT  59.501 13.68 60.469 23.928 ;
     RECT  60.329 60.816 60.473 69.528 ;
     RECT  60.329 25.248 60.505 37.176 ;
     RECT  60.329 38.16 60.757 40.68 ;
     RECT  59.753 41.712 60.757 59.496 ;
     RECT  59.404 90.48 60.797 90.504 ;
     RECT  60.113 77.904 60.901 81.048 ;
     RECT  59.933 82.512 60.997 88.872 ;
     RECT  60.505 25.152 61.009 37.176 ;
     RECT  60.997 82.416 61.045 88.872 ;
     RECT  61.045 82.416 61.117 89.496 ;
     RECT  60.397 2.496 61.513 2.52 ;
     RECT  60.469 3.696 61.513 23.928 ;
     RECT  61.513 2.496 61.585 23.928 ;
     RECT  60.329 70.608 61.585 76.296 ;
     RECT  60.901 77.424 61.585 81.048 ;
     RECT  61.117 82.128 61.669 89.496 ;
     RECT  61.585 2.304 61.808 23.928 ;
     RECT  61.009 25.056 61.808 37.176 ;
     RECT  60.757 38.16 61.808 59.496 ;
     RECT  60.473 60.912 61.808 69.528 ;
     RECT  61.585 70.608 61.808 81.048 ;
     RECT  61.669 82.128 61.808 89.544 ;
     RECT  61.808 2.148 61.912 90.732 ;
     RECT  61.912 2.304 62.104 90.462 ;
     RECT  62.104 25.152 62.165 40.68 ;
     RECT  62.104 41.712 62.243 76.536 ;
     RECT  62.104 2.304 62.273 12.84 ;
     RECT  62.243 41.712 62.273 59.832 ;
     RECT  62.243 61.392 62.273 76.536 ;
     RECT  62.165 25.152 62.332 37.944 ;
     RECT  62.273 41.712 62.669 59.496 ;
     RECT  62.125 0.576 62.675 0.6 ;
     RECT  62.332 29.568 62.741 37.944 ;
     RECT  62.669 41.712 62.813 54.504 ;
     RECT  62.273 61.392 62.819 69.336 ;
     RECT  62.273 70.32 62.957 76.536 ;
     RECT  62.104 81.648 62.993 89.592 ;
     RECT  62.273 2.496 63.029 12.84 ;
     RECT  62.813 51.12 63.101 54.504 ;
     RECT  62.669 55.68 63.137 59.496 ;
     RECT  62.165 38.928 63.233 40.68 ;
     RECT  62.813 41.712 63.233 50.136 ;
     RECT  63.233 38.928 63.317 50.136 ;
     RECT  62.957 70.608 63.385 76.536 ;
     RECT  62.104 77.568 63.385 80.616 ;
     RECT  62.332 25.152 63.421 28.44 ;
     RECT  63.029 3.312 63.461 12.84 ;
     RECT  63.461 4.752 63.491 12.84 ;
     RECT  63.421 24.912 63.497 28.44 ;
     RECT  63.385 70.608 63.541 80.616 ;
     RECT  62.741 30.864 63.601 37.944 ;
     RECT  63.317 38.928 63.601 40.728 ;
     RECT  63.101 51.168 63.709 54.504 ;
     RECT  62.819 64.128 63.925 69.336 ;
     RECT  63.541 70.608 63.925 80.904 ;
     RECT  62.741 29.568 63.961 29.88 ;
     RECT  63.461 3.312 64.105 3.72 ;
     RECT  62.993 81.888 64.141 88.92 ;
     RECT  64.105 90 64.141 90.024 ;
     RECT  63.925 64.128 64.165 80.904 ;
     RECT  64.141 81.888 64.165 90.024 ;
     RECT  63.709 51.168 64.177 54.648 ;
     RECT  63.137 55.968 64.177 59.496 ;
     RECT  64.165 64.128 64.177 90.024 ;
     RECT  63.491 10.128 64.285 12.84 ;
     RECT  64.105 3.072 64.321 3.72 ;
     RECT  64.177 51.168 64.393 59.496 ;
     RECT  64.321 2.592 64.508 3.72 ;
     RECT  63.491 4.752 64.508 9.048 ;
     RECT  64.285 10.128 64.508 12.888 ;
     RECT  62.104 13.872 64.508 23.928 ;
     RECT  63.497 24.912 64.508 27.912 ;
     RECT  63.961 28.944 64.508 29.88 ;
     RECT  63.601 30.864 64.508 40.728 ;
     RECT  63.317 41.712 64.508 50.136 ;
     RECT  64.393 51.168 64.508 60.312 ;
     RECT  62.819 61.392 64.508 63.048 ;
     RECT  64.177 64.128 64.508 90.072 ;
     RECT  64.508 2.148 64.612 90.732 ;
     RECT  64.612 2.256 64.804 90.462 ;
     RECT  64.804 2.256 65.037 8.28 ;
     RECT  64.804 9.648 65.297 80.664 ;
     RECT  65.037 3.648 65.441 8.28 ;
     RECT  65.037 2.256 65.513 2.616 ;
     RECT  65.297 29.568 65.603 80.664 ;
     RECT  65.603 60.528 65.644 80.664 ;
     RECT  65.513 2.592 65.729 2.616 ;
     RECT  65.603 29.568 65.845 59.496 ;
     RECT  65.297 9.648 65.945 28.248 ;
     RECT  65.441 4.752 66.013 8.28 ;
     RECT  65.945 9.648 66.013 23.928 ;
     RECT  65.441 3.648 66.085 3.72 ;
     RECT  65.644 60.576 66.157 80.664 ;
     RECT  64.804 82.416 66.229 90.072 ;
     RECT  65.845 29.568 66.373 50.136 ;
     RECT  66.157 60.576 66.625 81 ;
     RECT  66.229 82.272 66.625 90.072 ;
     RECT  65.845 51.168 66.661 59.496 ;
     RECT  65.945 25.056 66.697 28.248 ;
     RECT  66.697 25.056 66.913 28.488 ;
     RECT  66.373 29.52 66.949 50.136 ;
     RECT  66.661 51.168 66.949 59.592 ;
     RECT  66.085 2.736 66.985 3.72 ;
     RECT  66.013 4.752 66.985 23.928 ;
     RECT  66.985 2.736 67.208 23.928 ;
     RECT  66.913 24.96 67.208 28.488 ;
     RECT  66.949 29.52 67.208 59.592 ;
     RECT  66.625 60.576 67.208 90.072 ;
     RECT  67.208 2.148 67.312 90.732 ;
     RECT  67.312 2.418 67.504 90.462 ;
     RECT  67.504 10.08 67.673 23.928 ;
     RECT  67.504 2.592 67.709 9.096 ;
     RECT  67.504 60.576 67.781 90.024 ;
     RECT  67.709 4.752 67.925 9.096 ;
     RECT  67.504 34.368 68.38 37.464 ;
     RECT  67.781 61.44 68.893 90.024 ;
     RECT  68.893 61.44 68.933 90.072 ;
     RECT  67.709 2.592 68.965 3.72 ;
     RECT  67.925 4.752 68.965 8.52 ;
     RECT  67.673 10.08 68.965 17.496 ;
     RECT  68.933 61.44 69.001 88.92 ;
     RECT  68.965 2.592 69.037 8.52 ;
     RECT  68.965 9.552 69.037 17.496 ;
     RECT  67.504 24.96 69.073 33.384 ;
     RECT  68.38 34.368 69.073 37.176 ;
     RECT  67.504 38.688 69.212 59.592 ;
     RECT  69.001 61.2 69.212 88.92 ;
     RECT  69.037 2.592 69.289 17.496 ;
     RECT  67.673 18.48 69.289 23.928 ;
     RECT  69.073 24.96 69.397 37.176 ;
     RECT  69.289 2.592 69.469 23.928 ;
     RECT  69.397 24.96 69.469 37.704 ;
     RECT  69.469 2.592 69.908 37.704 ;
     RECT  69.212 38.688 69.908 88.92 ;
     RECT  68.933 90 69.908 90.072 ;
     RECT  69.908 2.148 70.012 90.732 ;
     RECT  70.012 2.418 70.204 90.462 ;
     RECT  70.204 5.28 70.373 29.064 ;
     RECT  70.373 5.664 70.445 29.064 ;
     RECT  70.204 2.592 70.451 4.152 ;
     RECT  70.204 70.608 70.589 90.072 ;
     RECT  70.445 5.664 70.787 28.872 ;
     RECT  70.204 38.688 70.805 59.832 ;
     RECT  70.204 30.192 70.828 37.176 ;
     RECT  70.589 70.608 70.949 90.024 ;
     RECT  70.204 66.816 71.197 69.336 ;
     RECT  70.787 5.664 71.219 28.488 ;
     RECT  70.451 2.64 71.233 4.152 ;
     RECT  70.204 61.2 71.269 65.496 ;
     RECT  71.197 66.528 71.269 69.336 ;
     RECT  70.949 82.368 71.525 90.024 ;
     RECT  71.233 2.64 71.593 4.2 ;
     RECT  71.269 61.2 71.593 69.336 ;
     RECT  71.525 82.368 71.597 89.256 ;
     RECT  71.219 5.664 71.665 27.912 ;
     RECT  70.805 39.072 71.701 59.832 ;
     RECT  71.593 61.2 71.701 69.48 ;
     RECT  71.593 2.304 71.737 4.2 ;
     RECT  71.737 2.256 71.773 4.2 ;
     RECT  71.665 5.52 71.773 27.912 ;
     RECT  70.828 30.336 72.133 37.176 ;
     RECT  71.701 39.072 72.385 69.48 ;
     RECT  70.949 70.608 72.385 81.048 ;
     RECT  72.133 30 72.421 37.176 ;
     RECT  72.421 29.856 72.469 37.176 ;
     RECT  71.773 2.256 72.493 27.912 ;
     RECT  71.597 82.368 72.493 89.208 ;
     RECT  72.493 2.256 72.608 28.2 ;
     RECT  72.469 29.328 72.608 37.176 ;
     RECT  72.385 39.072 72.608 81.048 ;
     RECT  72.493 82.176 72.608 89.208 ;
     RECT  72.608 2.148 72.712 90.732 ;
     RECT  72.712 2.304 72.749 90.462 ;
     RECT  72.749 2.418 72.904 90.462 ;
     RECT  72.904 9.888 72.965 28.2 ;
     RECT  72.904 2.88 73.001 8.472 ;
     RECT  72.904 39.072 73.037 59.592 ;
     RECT  72.904 29.328 73.181 37.368 ;
     RECT  72.965 10.08 73.325 28.2 ;
     RECT  72.904 82.176 73.897 89.016 ;
     RECT  73.001 3.312 74.005 4.392 ;
     RECT  72.904 60.768 74.077 69.528 ;
     RECT  72.904 70.608 74.077 80.952 ;
     RECT  73.037 50.832 74.149 59.592 ;
     RECT  74.077 60.768 74.149 80.952 ;
     RECT  73.897 82.08 74.149 89.016 ;
     RECT  74.005 2.496 74.153 4.536 ;
     RECT  74.149 50.832 74.221 89.016 ;
     RECT  73.181 30.912 74.365 37.368 ;
     RECT  73.037 39.072 74.365 49.848 ;
     RECT  73.181 29.328 74.401 29.88 ;
     RECT  74.365 30.912 74.401 49.848 ;
     RECT  74.221 50.832 74.401 89.544 ;
     RECT  74.401 29.328 74.473 89.544 ;
     RECT  73.001 5.52 74.653 8.472 ;
     RECT  73.325 10.08 74.725 27.912 ;
     RECT  74.473 29.328 74.725 89.592 ;
     RECT  74.725 10.08 74.797 89.592 ;
     RECT  74.653 5.52 75.157 8.52 ;
     RECT  74.797 9.696 75.157 89.592 ;
     RECT  74.153 2.496 75.308 2.52 ;
     RECT  74.153 3.696 75.308 4.536 ;
     RECT  75.157 5.52 75.308 89.592 ;
     RECT  75.308 2.148 75.412 90.732 ;
     RECT  75.412 2.418 75.604 90.462 ;
     RECT  75.604 10.416 75.665 59.832 ;
     RECT  75.604 66 75.665 80.616 ;
     RECT  75.604 2.784 75.731 9.048 ;
     RECT  75.665 30.816 75.737 59.832 ;
     RECT  75.665 66.288 75.773 80.616 ;
     RECT  75.773 66.288 75.827 80.376 ;
     RECT  75.737 30.816 75.845 39.336 ;
     RECT  75.604 60.912 75.917 65.016 ;
     RECT  75.665 10.416 75.989 29.64 ;
     RECT  75.845 30.816 76.133 39.096 ;
     RECT  75.737 40.368 76.307 59.832 ;
     RECT  75.827 70.608 76.313 80.376 ;
     RECT  75.989 10.416 76.597 27.96 ;
     RECT  75.989 29.184 76.601 29.64 ;
     RECT  76.133 30.912 76.601 39.096 ;
     RECT  76.307 40.368 76.637 59.592 ;
     RECT  75.827 66.288 76.669 69.528 ;
     RECT  76.669 66.24 76.844 69.528 ;
     RECT  76.313 70.608 76.844 79.848 ;
     RECT  75.604 81.648 76.933 88.92 ;
     RECT  75.604 90.048 76.933 90.072 ;
     RECT  75.917 60.912 76.939 62.52 ;
     RECT  76.601 30.912 76.997 38.28 ;
     RECT  76.933 81.648 77.02 90.072 ;
     RECT  76.597 10.128 77.033 27.96 ;
     RECT  77.033 10.32 77.209 27.96 ;
     RECT  76.637 50.832 77.281 59.592 ;
     RECT  76.997 30.912 77.317 38.184 ;
     RECT  76.637 40.368 77.353 49.848 ;
     RECT  75.731 3.264 77.389 9.048 ;
     RECT  75.917 63.504 77.489 65.016 ;
     RECT  77.389 2.832 77.497 9.048 ;
     RECT  77.497 2.304 77.605 9.048 ;
     RECT  76.939 60.96 77.785 62.52 ;
     RECT  77.489 63.504 77.785 65.064 ;
     RECT  77.605 2.256 78.008 9.048 ;
     RECT  77.209 10.32 78.008 28.2 ;
     RECT  76.601 29.616 78.008 29.64 ;
     RECT  77.317 30.816 78.008 38.184 ;
     RECT  77.353 39.504 78.008 49.848 ;
     RECT  77.281 50.832 78.008 59.832 ;
     RECT  77.785 60.96 78.008 65.064 ;
     RECT  76.844 66.24 78.008 79.848 ;
     RECT  77.02 81.648 78.008 88.776 ;
     RECT  77.02 90.048 78.008 90.072 ;
     RECT  78.008 2.148 78.112 90.732 ;
     RECT  78.112 2.256 78.304 90.504 ;
     RECT  78.304 90.048 78.401 90.504 ;
     RECT  78.304 2.256 78.419 14.376 ;
     RECT  78.304 29.184 78.445 59.832 ;
     RECT  78.419 2.304 78.653 14.376 ;
     RECT  78.445 29.184 78.653 49.848 ;
     RECT  78.304 60.816 78.659 80.856 ;
     RECT  78.653 29.184 78.689 49.56 ;
     RECT  78.304 16.032 78.761 28.2 ;
     RECT  78.659 70.608 78.797 80.856 ;
     RECT  78.689 30.816 78.833 49.56 ;
     RECT  78.659 60.816 78.833 69.528 ;
     RECT  78.689 29.184 78.905 29.784 ;
     RECT  78.653 2.352 79.013 14.376 ;
     RECT  78.304 81.84 79.193 88.44 ;
     RECT  78.445 50.832 79.285 59.832 ;
     RECT  78.833 60.816 79.285 69.048 ;
     RECT  79.013 2.784 79.297 14.376 ;
     RECT  78.905 29.232 79.301 29.784 ;
     RECT  78.761 18.672 79.333 28.2 ;
     RECT  78.401 90.48 79.337 90.504 ;
     RECT  79.285 50.832 79.372 69.048 ;
     RECT  79.372 50.832 79.373 59.592 ;
     RECT  79.193 84.096 79.405 88.44 ;
     RECT  79.297 2.784 79.409 14.76 ;
     RECT  79.405 84.096 79.489 88.968 ;
     RECT  79.409 2.784 79.517 4.536 ;
     RECT  78.797 70.896 79.549 80.856 ;
     RECT  79.193 81.84 79.549 83.112 ;
     RECT  78.761 16.032 79.573 17.688 ;
     RECT  79.489 84.096 79.625 88.92 ;
     RECT  79.573 15.984 79.729 17.688 ;
     RECT  79.333 18.672 79.729 28.248 ;
     RECT  79.372 60.816 80.161 69.048 ;
     RECT  79.549 70.896 80.161 83.112 ;
     RECT  79.729 15.984 80.233 28.248 ;
     RECT  79.301 29.232 80.233 29.256 ;
     RECT  78.833 46.944 80.269 49.56 ;
     RECT  80.269 46.944 80.341 49.608 ;
     RECT  78.833 30.816 80.377 45.864 ;
     RECT  80.341 46.848 80.377 49.608 ;
     RECT  79.373 50.832 80.413 59.496 ;
     RECT  80.161 60.816 80.413 83.112 ;
     RECT  79.517 3.696 80.593 4.536 ;
     RECT  79.409 5.76 80.593 14.76 ;
     RECT  80.233 15.984 80.629 29.256 ;
     RECT  80.593 3.696 80.708 14.76 ;
     RECT  80.629 15.84 80.708 29.592 ;
     RECT  80.377 30.816 80.708 49.608 ;
     RECT  80.413 50.832 80.708 83.112 ;
     RECT  79.625 84.096 80.708 88.44 ;
     RECT  80.708 2.148 80.812 90.732 ;
     RECT  80.812 2.418 81.004 90.462 ;
     RECT  81.004 19.824 81.065 80.904 ;
     RECT  81.065 43.392 81.137 80.904 ;
     RECT  81.004 3.696 81.173 18.792 ;
     RECT  81.004 84.864 81.173 88.44 ;
     RECT  81.065 19.824 81.281 42.12 ;
     RECT  81.137 54.096 81.281 80.904 ;
     RECT  81.281 54.432 81.353 80.904 ;
     RECT  81.173 3.696 81.497 14.712 ;
     RECT  81.353 54.672 81.569 80.904 ;
     RECT  81.497 3.696 81.587 6.648 ;
     RECT  81.587 4.512 81.713 6.648 ;
     RECT  81.004 81.984 81.749 83.064 ;
     RECT  81.281 28.176 81.785 42.12 ;
     RECT  81.173 15.696 81.929 18.792 ;
     RECT  81.281 19.824 81.929 27.144 ;
     RECT  81.569 60.528 81.965 80.904 ;
     RECT  81.497 7.632 82.001 14.712 ;
     RECT  81.173 85.248 82.001 88.44 ;
     RECT  81.929 21.264 82.037 27.144 ;
     RECT  81.785 28.176 82.037 38.712 ;
     RECT  82.001 85.392 82.037 88.44 ;
     RECT  82.037 33.552 82.073 38.712 ;
     RECT  81.569 54.672 82.073 59.544 ;
     RECT  81.713 4.512 82.109 4.536 ;
     RECT  82.073 55.104 82.109 59.544 ;
     RECT  81.965 62.16 82.109 80.904 ;
     RECT  82.037 85.392 82.109 86.76 ;
     RECT  82.001 7.632 82.145 10.344 ;
     RECT  82.001 11.424 82.145 14.712 ;
     RECT  81.929 15.744 82.145 18.792 ;
     RECT  81.929 19.824 82.145 19.848 ;
     RECT  82.109 55.44 82.145 57.432 ;
     RECT  81.713 5.76 82.181 6.648 ;
     RECT  82.145 18 82.181 18.792 ;
     RECT  82.037 21.264 82.181 22.248 ;
     RECT  82.037 23.328 82.181 27.144 ;
     RECT  82.145 11.616 82.217 14.184 ;
     RECT  82.073 35.712 82.217 38.712 ;
     RECT  81.137 43.392 82.253 53.064 ;
     RECT  82.109 75.456 82.253 80.904 ;
     RECT  81.785 39.744 82.289 42.12 ;
     RECT  82.145 55.728 82.325 57.432 ;
     RECT  82.109 62.16 82.325 74.088 ;
     RECT  82.145 7.632 82.361 9.96 ;
     RECT  82.037 28.176 82.361 32.568 ;
     RECT  82.289 39.84 82.361 42.12 ;
     RECT  82.253 78.288 82.361 80.904 ;
     RECT  81.965 60.528 82.433 61.128 ;
     RECT  82.109 85.392 82.433 85.8 ;
     RECT  82.181 23.568 82.573 27.144 ;
     RECT  82.361 28.176 82.573 28.968 ;
     RECT  81.749 82.128 82.609 83.064 ;
     RECT  82.609 82.128 82.681 83.784 ;
     RECT  82.681 82.128 82.717 84.072 ;
     RECT  82.253 43.392 82.789 47.832 ;
     RECT  82.181 5.808 83.408 6.648 ;
     RECT  82.361 7.68 83.408 9 ;
     RECT  82.217 11.856 83.408 14.184 ;
     RECT  82.145 15.744 83.408 16.392 ;
     RECT  82.181 18 83.408 18.168 ;
     RECT  82.181 21.36 83.408 22.248 ;
     RECT  82.573 23.568 83.408 28.968 ;
     RECT  82.361 30.144 83.408 31.896 ;
     RECT  82.073 33.552 83.408 34.68 ;
     RECT  82.217 35.712 83.408 38.472 ;
     RECT  82.361 39.84 83.408 41.976 ;
     RECT  82.789 43.296 83.408 47.832 ;
     RECT  82.253 48.96 83.408 53.064 ;
     RECT  82.325 55.728 83.408 55.752 ;
     RECT  82.325 56.88 83.408 57.432 ;
     RECT  82.109 58.896 83.408 59.544 ;
     RECT  82.433 60.528 83.408 60.84 ;
     RECT  82.325 62.16 83.408 69.768 ;
     RECT  82.325 71.04 83.408 74.088 ;
     RECT  82.253 75.456 83.408 77.304 ;
     RECT  82.361 78.288 83.408 79.8 ;
     RECT  82.361 80.832 83.408 80.904 ;
     RECT  82.717 82.128 83.408 84.36 ;
     RECT  82.433 85.776 83.408 85.8 ;
     RECT  82.037 88.416 83.408 88.44 ;
     RECT  83.408 2.148 83.512 90.732 ;
     RECT  83.512 2.418 83.704 90.462 ;
     RECT  83.704 4.416 84.877 57.096 ;
     RECT  83.704 58.08 84.877 88.536 ;
     RECT  84.877 4.416 86.22 88.536 ;
    LAYER M5 ;
     RECT  2.4 2.137 2.52 2.151 ;
     RECT  5.1 2.137 5.22 2.151 ;
     RECT  7.8 2.137 7.92 2.151 ;
     RECT  10.5 2.137 10.62 2.151 ;
     RECT  13.2 2.137 13.32 2.151 ;
     RECT  15.9 2.137 16.02 2.151 ;
     RECT  18.6 2.137 18.72 2.151 ;
     RECT  21.3 2.137 21.42 2.151 ;
     RECT  24 2.137 24.12 2.151 ;
     RECT  26.7 2.137 26.82 2.151 ;
     RECT  29.4 2.137 29.52 2.151 ;
     RECT  32.1 2.137 32.22 2.151 ;
     RECT  34.8 2.137 34.92 2.151 ;
     RECT  37.5 2.137 37.62 2.151 ;
     RECT  40.2 2.137 40.32 2.151 ;
     RECT  42.9 2.137 43.02 2.151 ;
     RECT  45.6 2.137 45.72 2.151 ;
     RECT  48.3 2.137 48.42 2.151 ;
     RECT  51 2.137 51.12 2.151 ;
     RECT  53.7 2.137 53.82 2.151 ;
     RECT  56.4 2.137 56.52 2.151 ;
     RECT  59.1 2.137 59.22 2.151 ;
     RECT  61.8 2.137 61.92 2.151 ;
     RECT  64.5 2.137 64.62 2.151 ;
     RECT  67.2 2.137 67.32 2.151 ;
     RECT  69.9 2.137 70.02 2.151 ;
     RECT  72.6 2.137 72.72 2.151 ;
     RECT  75.3 2.137 75.42 2.151 ;
     RECT  78 2.137 78.12 2.151 ;
     RECT  80.7 2.137 80.82 2.151 ;
     RECT  83.4 2.137 83.52 2.151 ;
     RECT  34.8 2.151 35.112 2.245 ;
     RECT  64.5 2.151 64.812 2.245 ;
     RECT  72.6 2.151 72.912 2.245 ;
     RECT  78 2.151 78.312 2.245 ;
     RECT  24 2.151 24.312 2.293 ;
     RECT  45.6 2.151 45.912 2.293 ;
     RECT  21.3 2.151 21.612 2.485 ;
     RECT  26.7 2.151 27.012 2.581 ;
     RECT  69.9 2.151 70.212 2.581 ;
     RECT  75.3 2.151 75.612 2.773 ;
     RECT  17.376 0.181 17.4 2.821 ;
     RECT  18.6 2.151 18.912 2.821 ;
     RECT  23.136 2.293 24.312 2.821 ;
     RECT  42.9 2.151 43.212 2.821 ;
     RECT  56.4 2.151 56.712 2.821 ;
     RECT  71.76 2.245 72.912 2.915 ;
     RECT  32.1 2.151 32.412 3.109 ;
     RECT  40.2 2.151 40.512 3.205 ;
     RECT  64.5 2.245 65.016 3.299 ;
     RECT  23.136 2.821 24.408 3.301 ;
     RECT  22.8 3.301 24.408 3.347 ;
     RECT  10.5 2.151 10.812 3.397 ;
     RECT  69.9 2.581 70.44 3.397 ;
     RECT  80.7 2.151 81.012 3.685 ;
     RECT  2.4 2.151 2.712 3.925 ;
     RECT  5.1 2.151 5.412 3.925 ;
     RECT  7.8 2.151 8.112 3.925 ;
     RECT  22.8 3.347 22.824 3.925 ;
     RECT  29.4 2.151 29.712 3.925 ;
     RECT  42.9 2.821 43.608 3.925 ;
     RECT  51 2.151 51.312 3.925 ;
     RECT  53.7 2.151 54.012 3.925 ;
     RECT  56.304 2.821 56.712 3.925 ;
     RECT  56.304 3.925 57.624 3.971 ;
     RECT  68.976 3.397 70.44 3.971 ;
     RECT  22.704 3.925 22.824 4.019 ;
     RECT  2.4 3.925 2.808 4.067 ;
     RECT  69.504 3.971 70.44 4.067 ;
     RECT  10.5 3.397 11.208 4.069 ;
     RECT  31.968 3.109 32.412 4.115 ;
     RECT  34.8 2.245 35.784 4.115 ;
     RECT  45.6 2.293 46.008 4.115 ;
     RECT  50.256 3.925 51.312 4.117 ;
     RECT  17.376 2.821 18.912 4.259 ;
     RECT  37.5 2.151 37.812 4.357 ;
     RECT  40.2 3.205 41.4 4.403 ;
     RECT  10.368 4.069 11.208 4.405 ;
     RECT  53.7 3.925 54.744 4.451 ;
     RECT  20.448 2.485 21.612 4.501 ;
     RECT  29.4 3.925 29.928 4.501 ;
     RECT  26.7 2.581 27.96 4.547 ;
     RECT  50.256 4.117 52.248 4.691 ;
     RECT  61.8 2.151 62.112 4.789 ;
     RECT  28.992 4.501 29.928 4.835 ;
     RECT  4.512 3.925 5.412 4.883 ;
     RECT  78 2.245 78.408 4.931 ;
     RECT  40.2 4.403 40.512 4.933 ;
     RECT  7.104 3.925 8.112 4.981 ;
     RECT  72.6 2.915 72.912 5.029 ;
     RECT  20.256 4.501 21.612 5.125 ;
     RECT  42.9 3.925 43.656 5.171 ;
     RECT  61.8 4.789 62.376 5.219 ;
     RECT  37.5 4.357 38.664 5.221 ;
     RECT  45.6 4.115 45.912 5.221 ;
     RECT  32.1 4.115 32.412 5.605 ;
     RECT  13.2 2.151 13.512 5.653 ;
     RECT  14.88 5.173 14.904 5.653 ;
     RECT  53.7 4.451 54.012 5.653 ;
     RECT  33.744 3.397 33.768 5.699 ;
     RECT  56.4 3.971 57.624 5.699 ;
     RECT  64.5 3.299 64.968 5.701 ;
     RECT  50.256 4.691 51.312 5.747 ;
     RECT  64.032 5.701 64.968 5.747 ;
     RECT  12.528 5.653 13.512 5.795 ;
     RECT  24 3.347 24.408 5.795 ;
     RECT  15.9 2.151 16.212 5.797 ;
     RECT  59.1 2.151 59.412 5.845 ;
     RECT  45.168 5.221 45.912 5.941 ;
     RECT  19.92 5.125 21.612 5.987 ;
     RECT  59.1 5.845 59.736 5.987 ;
     RECT  72.336 5.029 72.912 5.989 ;
     RECT  64.032 5.747 64.812 6.035 ;
     RECT  6.864 4.981 8.112 6.085 ;
     RECT  20.256 5.987 21.612 6.131 ;
     RECT  45.024 5.941 45.912 6.131 ;
     RECT  72.336 5.989 73.416 6.131 ;
     RECT  31.968 5.605 32.412 6.133 ;
     RECT  42.9 5.171 43.212 6.133 ;
     RECT  48.3 2.151 48.612 6.133 ;
     RECT  75.3 2.773 75.72 6.229 ;
     RECT  79.584 6.037 79.608 6.229 ;
     RECT  78 4.931 78.312 6.277 ;
     RECT  52.992 5.653 54.012 6.323 ;
     RECT  26.7 4.547 27.336 6.371 ;
     RECT  45.168 6.131 45.912 6.515 ;
     RECT  20.496 6.131 21.612 6.517 ;
     RECT  22.704 4.019 22.728 6.517 ;
     RECT  26.7 6.371 27.144 6.565 ;
     RECT  34.8 4.115 35.112 6.565 ;
     RECT  72.336 6.131 72.912 6.565 ;
     RECT  28.992 4.835 29.832 6.611 ;
     RECT  20.496 6.517 22.728 6.709 ;
     RECT  24 5.795 24.312 6.709 ;
     RECT  39.984 4.933 40.512 6.803 ;
     RECT  14.64 5.653 14.904 6.805 ;
     RECT  15.9 5.797 16.344 6.805 ;
     RECT  18.6 4.259 18.912 6.805 ;
     RECT  20.496 6.709 24.312 6.805 ;
     RECT  55.152 4.501 55.176 6.805 ;
     RECT  56.4 5.699 56.712 6.805 ;
     RECT  31.968 6.133 33.192 6.851 ;
     RECT  36.864 5.221 38.664 6.851 ;
     RECT  55.152 6.805 56.712 6.851 ;
     RECT  71.376 6.565 72.912 6.851 ;
     RECT  28.992 6.611 29.712 6.899 ;
     RECT  78 6.277 78.408 6.899 ;
     RECT  79.536 6.229 79.608 6.899 ;
     RECT  60.768 5.797 60.792 6.901 ;
     RECT  61.8 5.219 62.112 6.901 ;
     RECT  26.544 6.565 27.144 7.043 ;
     RECT  29.088 6.899 29.712 7.043 ;
     RECT  20.496 6.805 24.552 7.091 ;
     RECT  9.6 4.405 11.208 7.139 ;
     RECT  14.64 6.805 16.344 7.141 ;
     RECT  17.376 4.259 17.4 7.141 ;
     RECT  14.64 7.141 17.4 7.187 ;
     RECT  20.496 7.091 21.612 7.237 ;
     RECT  34.8 6.565 35.208 7.237 ;
     RECT  47.616 6.133 48.612 7.283 ;
     RECT  60.768 6.901 62.112 7.381 ;
     RECT  67.2 2.151 67.512 7.381 ;
     RECT  14.88 7.187 17.4 7.475 ;
     RECT  22.704 7.091 24.552 7.475 ;
     RECT  40.2 6.803 40.512 7.573 ;
     RECT  6.864 6.085 8.232 7.619 ;
     RECT  42.144 6.133 43.212 7.859 ;
     RECT  23.328 7.475 24.552 7.861 ;
     RECT  45.6 6.515 45.912 7.909 ;
     RECT  69.504 4.067 70.212 7.909 ;
     RECT  23.328 7.861 25.128 7.955 ;
     RECT  40.2 7.573 40.632 7.955 ;
     RECT  40.2 7.955 40.512 7.957 ;
     RECT  18.6 6.805 19.176 8.003 ;
     RECT  20.4 7.237 21.612 8.003 ;
     RECT  57.984 6.661 58.008 8.003 ;
     RECT  24 7.955 25.128 8.101 ;
     RECT  53.04 6.323 54.012 8.101 ;
     RECT  24 8.101 25.608 8.147 ;
     RECT  32.1 6.851 33.192 8.149 ;
     RECT  55.824 6.851 56.712 8.195 ;
     RECT  31.392 8.149 33.192 8.435 ;
     RECT  53.04 8.101 54.12 8.435 ;
     RECT  29.4 7.043 29.712 8.437 ;
     RECT  12.864 5.795 13.512 8.483 ;
     RECT  34.8 7.237 35.928 8.483 ;
     RECT  47.952 7.283 48.612 8.483 ;
     RECT  75.3 6.229 76.104 8.485 ;
     RECT  60.432 7.381 62.112 8.531 ;
     RECT  10.5 7.139 11.208 8.533 ;
     RECT  13.056 8.483 13.512 8.579 ;
     RECT  75.168 8.485 76.104 8.579 ;
     RECT  25.584 8.147 25.608 8.675 ;
     RECT  13.104 8.579 13.512 8.725 ;
     RECT  13.104 8.725 13.608 8.771 ;
     RECT  59.1 5.987 59.412 8.965 ;
     RECT  14.88 7.475 14.904 9.011 ;
     RECT  53.04 8.435 54.012 9.011 ;
     RECT  71.808 6.851 72.912 9.011 ;
     RECT  75.168 8.579 75.816 9.059 ;
     RECT  2.4 4.067 2.712 9.061 ;
     RECT  15.9 7.475 17.4 9.061 ;
     RECT  66.768 7.381 67.512 9.109 ;
     RECT  69.504 7.909 70.344 9.155 ;
     RECT  63.456 7.957 63.48 9.203 ;
     RECT  6.864 7.619 8.112 9.205 ;
     RECT  44.976 7.909 45.912 9.299 ;
     RECT  50.688 5.747 51.312 9.493 ;
     RECT  69.504 9.155 70.212 9.541 ;
     RECT  20.496 8.003 21.612 9.637 ;
     RECT  50.304 9.493 51.312 9.637 ;
     RECT  60.96 8.531 62.112 9.637 ;
     RECT  59.1 8.965 59.544 9.731 ;
     RECT  75.168 9.059 75.72 9.731 ;
     RECT  80.7 3.685 81.576 9.731 ;
     RECT  42.288 7.859 43.212 9.827 ;
     RECT  39.888 7.957 40.512 9.971 ;
     RECT  37.5 6.851 38.664 10.021 ;
     RECT  13.2 8.771 13.608 10.069 ;
     RECT  59.1 9.731 59.412 10.069 ;
     RECT  13.104 10.069 13.608 10.115 ;
     RECT  60.96 9.637 62.232 10.115 ;
     RECT  40.2 9.971 40.512 10.213 ;
     RECT  26.7 7.043 27.144 10.261 ;
     RECT  66.288 9.109 67.512 10.307 ;
     RECT  5.1 4.883 5.412 10.453 ;
     RECT  15.6 9.061 17.4 10.501 ;
     RECT  18.6 8.003 18.912 10.501 ;
     RECT  44.448 9.637 44.472 10.549 ;
     RECT  45.6 9.299 45.912 10.549 ;
     RECT  6.864 9.205 9 10.595 ;
     RECT  44.448 10.549 45.912 10.595 ;
     RECT  5.1 10.453 5.688 10.597 ;
     RECT  26.7 10.261 27.912 10.597 ;
     RECT  15.6 10.501 18.912 10.693 ;
     RECT  68.976 9.541 70.212 10.835 ;
     RECT  2.4 9.061 2.904 10.883 ;
     RECT  4.176 10.597 5.688 10.883 ;
     RECT  6.864 10.595 8.568 10.883 ;
     RECT  40.2 10.213 41.496 10.883 ;
     RECT  79.584 6.899 79.608 10.931 ;
     RECT  69.504 10.835 70.212 10.979 ;
     RECT  72.432 9.011 72.912 11.171 ;
     RECT  37.392 10.021 38.664 11.269 ;
     RECT  20.064 9.637 21.612 11.363 ;
     RECT  72.48 11.171 72.912 11.555 ;
     RECT  75.3 9.731 75.72 11.555 ;
     RECT  72.6 11.555 72.912 11.557 ;
     RECT  26.064 10.597 27.912 11.699 ;
     RECT  58.992 10.069 59.412 11.701 ;
     RECT  14.928 10.693 18.912 11.747 ;
     RECT  33.696 10.165 33.72 11.939 ;
     RECT  75.3 11.555 75.612 11.941 ;
     RECT  7.68 10.883 8.568 11.987 ;
     RECT  49.824 9.637 51.312 11.987 ;
     RECT  10.5 8.533 11.304 11.989 ;
     RECT  13.104 10.115 13.512 12.035 ;
     RECT  50.304 11.987 51.312 12.035 ;
     RECT  40.2 10.883 40.512 12.037 ;
     RECT  72.6 11.557 73.416 12.037 ;
     RECT  44.736 10.595 45.912 12.179 ;
     RECT  60.48 11.365 60.504 12.179 ;
     RECT  61.8 10.115 62.232 12.227 ;
     RECT  72.6 12.037 73.848 12.227 ;
     RECT  40.2 12.037 40.968 12.275 ;
     RECT  50.736 12.035 51.312 12.275 ;
     RECT  40.2 12.275 40.872 12.371 ;
     RECT  26.7 11.699 27.912 12.515 ;
     RECT  7.68 11.987 8.112 12.517 ;
     RECT  13.2 12.035 13.512 12.517 ;
     RECT  14.928 11.747 17.4 12.517 ;
     RECT  13.2 12.517 17.4 12.563 ;
     RECT  20.496 11.363 21.612 12.563 ;
     RECT  31.392 8.435 32.412 12.563 ;
     RECT  7.44 12.517 8.112 12.803 ;
     RECT  15.408 12.563 17.4 12.803 ;
     RECT  66 11.941 66.024 12.995 ;
     RECT  74.832 11.941 75.612 12.997 ;
     RECT  24 8.147 24.552 13.045 ;
     RECT  37.392 11.269 38.76 13.091 ;
     RECT  72.6 12.227 73.416 13.139 ;
     RECT  7.68 12.803 8.112 13.283 ;
     RECT  20.736 12.563 21.612 13.573 ;
     RECT  37.392 13.091 37.812 13.573 ;
     RECT  15.9 12.803 17.4 13.621 ;
     RECT  18.6 11.747 18.912 13.621 ;
     RECT  26.7 12.515 27.012 13.621 ;
     RECT  61.8 12.227 62.112 13.621 ;
     RECT  4.176 10.883 5.412 13.669 ;
     RECT  71.52 13.045 71.544 13.811 ;
     RECT  24 13.045 25.08 13.859 ;
     RECT  3.936 13.669 5.412 13.907 ;
     RECT  24 13.859 24.312 14.101 ;
     RECT  32.1 12.563 32.412 14.197 ;
     RECT  34.8 8.483 35.112 14.197 ;
     RECT  45.6 12.179 45.912 14.197 ;
     RECT  48.3 8.483 48.612 14.197 ;
     RECT  58.608 11.701 59.412 14.245 ;
     RECT  80.7 9.731 81.012 14.389 ;
     RECT  29.4 8.437 30.024 14.435 ;
     RECT  15.9 13.621 18.912 14.533 ;
     RECT  53.7 9.011 54.012 14.581 ;
     RECT  15.456 14.533 18.912 14.627 ;
     RECT  10.5 11.989 11.784 14.675 ;
     RECT  37.056 13.573 37.812 14.771 ;
     RECT  4.8 13.907 5.412 14.773 ;
     RECT  72.6 13.139 72.912 14.773 ;
     RECT  74.832 12.997 75.96 14.773 ;
     RECT  61.44 13.621 62.112 14.819 ;
     RECT  56.4 8.195 56.712 14.821 ;
     RECT  67.2 10.307 67.512 15.013 ;
     RECT  50.88 12.275 51.312 15.059 ;
     RECT  55.872 14.821 56.712 15.109 ;
     RECT  23.856 14.101 24.312 15.155 ;
     RECT  44.976 14.197 45.912 15.251 ;
     RECT  58.128 14.245 59.412 15.299 ;
     RECT  47.856 14.197 48.612 15.347 ;
     RECT  72.6 14.773 73.32 15.349 ;
     RECT  74.64 14.773 76.056 15.349 ;
     RECT  72.6 15.349 76.056 15.445 ;
     RECT  20.736 13.573 22.536 15.491 ;
     RECT  31.584 14.197 32.412 15.491 ;
     RECT  34.8 14.197 35.208 15.491 ;
     RECT  29.4 14.435 29.976 15.539 ;
     RECT  58.176 15.299 59.412 15.589 ;
     RECT  4.8 14.773 6.216 15.685 ;
     RECT  64.5 6.035 64.812 15.733 ;
     RECT  10.5 14.675 10.812 15.829 ;
     RECT  51 15.059 51.312 15.829 ;
     RECT  69.744 10.979 70.212 15.877 ;
     RECT  2.4 10.883 2.712 15.925 ;
     RECT  53.7 14.581 54.168 15.973 ;
     RECT  69.12 15.877 70.212 15.973 ;
     RECT  80.352 14.389 81.012 15.973 ;
     RECT  49.824 14.533 49.848 16.019 ;
     RECT  61.584 14.819 62.112 16.019 ;
     RECT  67.2 15.013 67.608 16.019 ;
     RECT  20.736 15.491 21.72 16.069 ;
     RECT  34.8 15.491 35.112 16.069 ;
     RECT  53.7 15.973 54.264 16.115 ;
     RECT  20.112 16.069 21.72 16.307 ;
     RECT  4.8 15.685 6.792 16.403 ;
     RECT  13.2 12.563 14.088 16.405 ;
     RECT  78 6.899 78.312 16.453 ;
     RECT  28.32 14.197 28.344 16.501 ;
     RECT  29.4 15.539 29.928 16.501 ;
     RECT  4.992 16.403 6.792 16.547 ;
     RECT  15.456 14.627 17.4 16.595 ;
     RECT  34.704 16.069 35.112 16.595 ;
     RECT  55.872 15.109 56.904 16.595 ;
     RECT  58.176 15.589 59.784 16.595 ;
     RECT  79.584 15.973 81.012 16.595 ;
     RECT  11.808 14.773 11.832 16.597 ;
     RECT  11.808 16.597 11.928 16.643 ;
     RECT  72.6 15.445 77.016 16.691 ;
     RECT  18.48 14.627 18.912 16.741 ;
     RECT  72.6 16.691 75.612 16.787 ;
     RECT  18.48 16.741 19.56 16.835 ;
     RECT  20.736 16.307 21.72 16.835 ;
     RECT  78 16.453 78.408 16.835 ;
     RECT  40.2 12.371 40.512 16.837 ;
     RECT  41.808 16.213 41.832 16.837 ;
     RECT  20.832 16.835 21.72 16.883 ;
     RECT  7.8 13.283 8.112 17.077 ;
     RECT  68.976 15.973 70.212 17.077 ;
     RECT  68.976 17.077 70.824 17.123 ;
     RECT  18.6 16.835 19.56 17.171 ;
     RECT  76.656 16.691 77.016 17.171 ;
     RECT  1.248 17.077 1.272 17.219 ;
     RECT  10.368 15.829 10.812 17.219 ;
     RECT  40.2 16.837 41.832 17.363 ;
     RECT  61.8 16.019 62.112 17.365 ;
     RECT  28.32 16.501 29.928 17.411 ;
     RECT  28.32 17.411 29.832 17.555 ;
     RECT  24 15.155 24.312 17.605 ;
     RECT  37.392 14.771 37.812 17.605 ;
     RECT  40.2 17.363 41.448 17.605 ;
     RECT  61.68 17.365 62.112 17.605 ;
     RECT  7.8 17.077 8.232 17.651 ;
     RECT  6.672 16.547 6.792 17.699 ;
     RECT  22.704 15.829 22.728 17.699 ;
     RECT  64.5 15.733 64.968 17.843 ;
     RECT  26.064 13.621 27.012 17.941 ;
     RECT  6.672 17.699 6.696 17.987 ;
     RECT  72.6 16.787 73.32 18.035 ;
     RECT  51 15.829 51.432 18.085 ;
     RECT  37.248 17.605 37.812 18.133 ;
     RECT  13.104 16.405 14.088 18.179 ;
     RECT  4.992 16.547 5.412 18.181 ;
     RECT  26.064 17.941 27.528 18.181 ;
     RECT  40.08 17.605 41.448 18.275 ;
     RECT  69.12 17.123 70.824 18.419 ;
     RECT  13.2 18.179 14.088 18.565 ;
     RECT  15.9 16.595 17.4 18.565 ;
     RECT  69.12 18.419 70.212 18.565 ;
     RECT  51 18.085 51.912 18.661 ;
     RECT  7.8 17.651 8.112 18.709 ;
     RECT  10.5 17.219 10.812 18.757 ;
     RECT  36.288 18.133 37.812 18.803 ;
     RECT  76.656 17.171 76.68 18.803 ;
     RECT  2.4 15.925 3.192 18.995 ;
     RECT  50.448 18.661 51.912 18.995 ;
     RECT  56.4 16.595 56.904 18.997 ;
     RECT  53.7 16.115 54.012 19.093 ;
     RECT  74.688 16.787 75.612 19.093 ;
     RECT  20.928 16.883 21.72 19.235 ;
     RECT  25.968 18.181 27.528 19.235 ;
     RECT  42.9 9.827 43.212 19.237 ;
     RECT  56.4 18.997 56.952 19.331 ;
     RECT  45.6 15.251 45.912 19.333 ;
     RECT  48.3 15.347 48.612 19.333 ;
     RECT  13.2 18.565 17.4 19.379 ;
     RECT  36.288 18.803 36.312 19.427 ;
     RECT  50.448 18.995 51.864 19.427 ;
     RECT  9.984 18.757 10.812 19.619 ;
     RECT  74.688 19.093 75.96 19.619 ;
     RECT  80.352 16.595 81.012 19.765 ;
     RECT  13.2 19.379 14.088 19.813 ;
     RECT  11.904 16.643 11.928 19.859 ;
     RECT  69.024 18.565 70.212 20.003 ;
     RECT  74.832 19.619 75.96 20.051 ;
     RECT  72.6 18.035 72.912 20.149 ;
     RECT  48.192 19.333 48.612 20.293 ;
     RECT  4.992 18.181 5.544 20.339 ;
     RECT  48.192 20.293 48.744 20.339 ;
     RECT  15.9 19.379 17.4 20.341 ;
     RECT  18.6 17.171 18.912 20.341 ;
     RECT  40.2 18.275 41.448 20.341 ;
     RECT  42.9 19.237 43.32 20.435 ;
     RECT  42.9 20.435 43.212 20.485 ;
     RECT  44.784 19.333 45.912 20.579 ;
     RECT  51 19.427 51.864 20.579 ;
     RECT  53.7 19.093 54.696 20.579 ;
     RECT  61.248 17.605 62.112 20.579 ;
     RECT  15.9 20.341 18.912 20.723 ;
     RECT  28.752 17.555 29.832 20.725 ;
     RECT  7.8 18.709 8.52 20.869 ;
     RECT  24 17.605 24.504 20.869 ;
     RECT  4.992 20.339 5.412 20.915 ;
     RECT  24 20.869 25.032 21.107 ;
     RECT  48.3 20.339 48.744 21.155 ;
     RECT  42.768 20.485 43.212 21.203 ;
     RECT  12.912 19.813 14.088 21.205 ;
     RECT  51 20.579 51.312 21.253 ;
     RECT  15.9 20.723 17.4 21.301 ;
     RECT  56.4 19.331 56.904 21.541 ;
     RECT  24 21.107 24.408 21.683 ;
     RECT  69.12 20.003 70.212 21.683 ;
     RECT  37.392 18.803 37.812 21.733 ;
     RECT  15.6 21.301 17.4 21.781 ;
     RECT  45.6 20.579 45.912 21.829 ;
     RECT  40.08 20.341 41.448 21.971 ;
     RECT  45.6 21.829 46.536 22.019 ;
     RECT  34.8 16.595 35.112 22.117 ;
     RECT  10.5 19.619 10.812 22.165 ;
     RECT  24 21.683 24.312 22.165 ;
     RECT  69.744 21.683 70.212 22.165 ;
     RECT  48.3 21.155 48.612 22.213 ;
     RECT  12.624 21.205 14.088 22.259 ;
     RECT  26.7 19.235 27.528 22.453 ;
     RECT  28.752 20.725 30.408 22.499 ;
     RECT  12.624 22.259 13.512 22.597 ;
     RECT  20.928 19.235 21.612 22.597 ;
     RECT  37.392 21.733 38.424 22.693 ;
     RECT  55.728 21.541 56.904 22.693 ;
     RECT  64.5 17.843 64.812 22.693 ;
     RECT  55.296 22.693 56.904 22.739 ;
     RECT  34.8 22.117 35.208 22.741 ;
     RECT  42.9 21.203 43.212 22.741 ;
     RECT  79.824 19.765 81.012 22.787 ;
     RECT  58.176 16.595 59.412 22.883 ;
     RECT  37.392 22.693 38.76 22.979 ;
     RECT  76.944 20.437 76.968 22.979 ;
     RECT  15.552 21.781 17.4 23.267 ;
     RECT  10.368 22.165 10.812 23.315 ;
     RECT  32.1 15.491 32.412 23.317 ;
     RECT  33.552 18.229 33.576 23.317 ;
     RECT  42.768 22.741 43.212 23.363 ;
     RECT  60.432 21.925 60.456 23.363 ;
     RECT  45.6 22.019 46.392 23.365 ;
     RECT  12.24 22.597 13.512 23.411 ;
     RECT  50.16 21.253 51.312 23.411 ;
     RECT  28.752 22.499 29.88 23.507 ;
     RECT  34.8 22.741 36.072 23.555 ;
     RECT  45.072 23.365 46.392 23.555 ;
     RECT  55.296 22.739 55.32 23.555 ;
     RECT  20.544 22.597 21.612 23.603 ;
     RECT  23.808 22.165 24.312 23.845 ;
     RECT  15.9 23.267 17.4 23.893 ;
     RECT  18.6 20.723 18.912 23.893 ;
     RECT  32.1 23.317 33.576 23.893 ;
     RECT  61.8 20.579 62.112 23.893 ;
     RECT  72.48 20.149 72.912 23.893 ;
     RECT  26.112 22.453 27.528 23.987 ;
     RECT  31.248 23.893 33.576 23.987 ;
     RECT  64.5 22.693 64.968 23.987 ;
     RECT  69.744 22.165 70.824 23.987 ;
     RECT  72.48 23.893 73.464 23.987 ;
     RECT  74.832 20.051 75.612 23.989 ;
     RECT  31.248 23.987 33.048 24.131 ;
     RECT  40.08 21.971 40.512 24.131 ;
     RECT  45.072 23.555 45.912 24.131 ;
     RECT  48.096 22.213 48.612 24.131 ;
     RECT  20.928 23.603 21.612 24.469 ;
     RECT  40.2 24.131 40.512 24.469 ;
     RECT  56.4 22.739 56.904 24.469 ;
     RECT  26.112 23.987 27.012 24.563 ;
     RECT  72.6 23.987 73.464 24.707 ;
     RECT  53.7 20.579 54.012 24.709 ;
     RECT  5.1 20.915 5.412 24.757 ;
     RECT  37.392 22.979 37.812 24.805 ;
     RECT  67.2 16.019 67.512 24.949 ;
     RECT  34.8 23.555 35.112 25.045 ;
     RECT  64.5 23.987 64.812 25.045 ;
     RECT  20.928 24.469 21.96 25.139 ;
     RECT  55.824 24.469 56.904 25.139 ;
     RECT  23.808 23.845 24.456 25.187 ;
     RECT  40.2 24.469 41.112 25.189 ;
     RECT  42.9 23.363 43.212 25.189 ;
     RECT  61.8 23.893 62.664 25.189 ;
     RECT  28.752 23.507 29.832 25.235 ;
     RECT  31.248 24.131 32.412 25.333 ;
     RECT  80.7 22.787 81.012 25.429 ;
     RECT  69.744 23.987 70.212 25.619 ;
     RECT  55.824 25.139 56.856 25.715 ;
     RECT  61.68 25.189 62.664 25.715 ;
     RECT  64.5 25.045 65.736 25.715 ;
     RECT  45.6 24.131 45.912 25.717 ;
     RECT  37.056 24.805 37.812 26.051 ;
     RECT  48.3 24.131 48.612 26.053 ;
     RECT  20.928 25.139 21.612 26.101 ;
     RECT  20.928 26.101 21.72 26.197 ;
     RECT  28.752 25.235 29.712 26.197 ;
     RECT  42.9 25.189 43.896 26.243 ;
     RECT  20.544 26.197 21.72 26.245 ;
     RECT  55.824 25.715 56.712 26.245 ;
     RECT  72.6 24.707 72.912 26.245 ;
     RECT  74.736 23.989 75.612 26.245 ;
     RECT  24 25.187 24.456 26.293 ;
     RECT  58.848 22.883 59.412 26.389 ;
     RECT  24 26.293 25.032 26.435 ;
     RECT  55.104 26.245 56.712 26.435 ;
     RECT  48.192 26.053 48.612 26.483 ;
     RECT  19.968 26.245 21.72 26.531 ;
     RECT  30.864 25.333 32.412 26.627 ;
     RECT  74.736 26.245 75.864 26.627 ;
     RECT  5.1 24.757 5.928 26.677 ;
     RECT  45.6 25.717 46.008 26.677 ;
     RECT  53.568 24.709 54.012 26.677 ;
     RECT  31.344 26.627 32.412 26.725 ;
     RECT  39.888 25.189 41.112 26.725 ;
     RECT  52.416 23.317 52.44 26.771 ;
     RECT  64.5 25.715 64.812 26.773 ;
     RECT  31.344 26.725 33.288 26.819 ;
     RECT  61.68 25.715 62.112 26.819 ;
     RECT  12.624 23.411 13.512 27.061 ;
     RECT  24 26.435 24.456 27.107 ;
     RECT  12.624 27.061 13.704 27.205 ;
     RECT  7.8 20.869 9.096 27.253 ;
     RECT  39.6 26.725 41.112 27.301 ;
     RECT  55.824 26.435 56.712 27.301 ;
     RECT  15.9 23.893 18.912 27.347 ;
     RECT  39.6 27.301 41.88 27.445 ;
     RECT  39.264 27.445 41.88 27.491 ;
     RECT  53.52 26.677 54.012 27.491 ;
     RECT  17.376 27.347 18.912 27.589 ;
     RECT  19.968 26.531 21.612 27.589 ;
     RECT  37.392 26.051 37.812 27.589 ;
     RECT  55.824 27.301 57.624 27.589 ;
     RECT  48.3 26.483 48.612 27.685 ;
     RECT  12.624 27.205 13.752 27.781 ;
     RECT  32.1 26.819 33.288 27.877 ;
     RECT  44.448 27.685 44.472 27.877 ;
     RECT  45.6 26.677 46.728 27.877 ;
     RECT  44.448 27.877 46.728 27.923 ;
     RECT  74.736 26.627 75.768 27.923 ;
     RECT  76.896 25.333 76.92 27.971 ;
     RECT  31.68 27.877 33.288 28.403 ;
     RECT  34.8 25.045 35.352 28.403 ;
     RECT  61.8 26.819 62.112 28.453 ;
     RECT  69.9 25.619 70.212 28.453 ;
     RECT  71.184 27.301 71.208 28.453 ;
     RECT  69.9 28.453 71.208 28.499 ;
     RECT  24 27.107 24.312 28.501 ;
     RECT  55.2 27.589 57.624 28.547 ;
     RECT  39.264 27.491 40.512 28.691 ;
     RECT  67.2 24.949 67.608 28.691 ;
     RECT  17.376 27.589 21.612 28.885 ;
     RECT  22.944 27.301 22.968 28.885 ;
     RECT  55.2 28.547 56.712 28.979 ;
     RECT  34.8 28.403 35.256 28.981 ;
     RECT  51 23.411 51.312 28.981 ;
     RECT  10.5 23.315 10.812 29.029 ;
     RECT  12.624 27.781 14.52 29.029 ;
     RECT  4.272 26.677 5.928 29.123 ;
     RECT  64.5 26.773 64.92 29.219 ;
     RECT  74.88 27.923 75.768 29.219 ;
     RECT  5.1 29.123 5.928 29.317 ;
     RECT  6.912 27.253 9.096 29.317 ;
     RECT  5.1 29.317 9.096 29.363 ;
     RECT  58.8 26.389 59.412 29.365 ;
     RECT  11.808 29.029 14.52 29.507 ;
     RECT  25.68 27.925 25.704 29.651 ;
     RECT  55.2 28.979 55.272 29.699 ;
     RECT  11.808 29.507 13.704 29.747 ;
     RECT  31.68 28.403 32.412 29.747 ;
     RECT  10.08 29.029 10.812 29.795 ;
     RECT  44.928 27.923 46.728 29.893 ;
     RECT  51 28.981 51.576 29.987 ;
     RECT  72.336 26.245 72.912 29.989 ;
     RECT  26.7 24.563 27.012 30.037 ;
     RECT  12.528 29.747 13.704 30.083 ;
     RECT  26.208 30.037 27.012 30.133 ;
     RECT  28.656 26.197 29.712 30.133 ;
     RECT  48.3 27.685 48.744 30.133 ;
     RECT  53.568 27.491 54.012 30.133 ;
     RECT  34.032 28.981 35.256 30.275 ;
     RECT  58.8 29.365 60.168 30.275 ;
     RECT  34.032 30.275 35.112 30.277 ;
     RECT  17.376 28.885 22.968 30.323 ;
     RECT  33.648 30.277 35.112 30.323 ;
     RECT  41.856 27.491 41.88 30.323 ;
     RECT  37.2 27.589 37.812 30.565 ;
     RECT  55.248 29.699 55.272 30.611 ;
     RECT  58.8 30.275 59.412 30.661 ;
     RECT  40.2 28.691 40.512 30.709 ;
     RECT  10.5 29.795 10.812 30.757 ;
     RECT  56.4 28.979 56.712 30.757 ;
     RECT  61.8 28.453 62.28 30.757 ;
     RECT  26.208 30.133 29.712 30.803 ;
     RECT  36.192 30.277 36.216 30.803 ;
     RECT  15.9 27.347 16.344 30.805 ;
     RECT  17.376 30.323 22.056 30.805 ;
     RECT  5.1 29.363 8.112 30.851 ;
     RECT  33.648 30.323 33.672 30.851 ;
     RECT  74.88 29.219 75.612 30.853 ;
     RECT  86.112 30.757 86.136 30.899 ;
     RECT  12.624 30.083 13.704 30.997 ;
     RECT  14.784 30.757 14.808 30.997 ;
     RECT  37.2 30.565 38.328 30.997 ;
     RECT  39.312 30.709 40.512 30.997 ;
     RECT  12.624 30.997 14.808 31.043 ;
     RECT  37.2 30.997 40.512 31.043 ;
     RECT  15.9 30.805 22.056 31.091 ;
     RECT  26.208 30.803 27.012 31.141 ;
     RECT  42.9 26.243 43.212 31.141 ;
     RECT  64.5 29.219 64.812 31.141 ;
     RECT  61.8 30.757 62.616 31.187 ;
     RECT  6.864 30.851 8.112 31.285 ;
     RECT  24 28.501 24.408 31.333 ;
     RECT  12.624 31.043 14.184 31.379 ;
     RECT  2.4 18.995 2.712 31.381 ;
     RECT  34.8 30.323 35.112 31.381 ;
     RECT  2.4 31.381 2.808 31.621 ;
     RECT  53.568 30.133 54.12 31.765 ;
     RECT  51 29.987 51.432 31.811 ;
     RECT  25.968 31.141 27.012 31.861 ;
     RECT  78 16.835 78.312 31.861 ;
     RECT  23.232 31.333 24.408 31.955 ;
     RECT  44.928 29.893 46.776 31.955 ;
     RECT  69.9 28.499 70.776 31.957 ;
     RECT  72.144 29.989 72.912 31.957 ;
     RECT  24 31.955 24.408 32.005 ;
     RECT  74.88 30.853 75.768 32.005 ;
     RECT  74.112 32.005 75.768 32.051 ;
     RECT  10.272 30.757 10.812 32.149 ;
     RECT  53.568 31.765 54.696 32.197 ;
     RECT  24 32.005 24.504 32.243 ;
     RECT  37.2 31.043 38.904 32.243 ;
     RECT  69.9 31.957 72.912 32.243 ;
     RECT  15.9 31.091 20.04 32.291 ;
     RECT  71.28 32.243 72.912 32.291 ;
     RECT  24 32.243 24.408 32.387 ;
     RECT  25.968 31.861 27.72 32.387 ;
     RECT  6.864 31.285 8.52 32.483 ;
     RECT  33.6 31.813 33.624 32.483 ;
     RECT  48.3 30.133 49.56 32.483 ;
     RECT  21.3 31.091 22.056 32.485 ;
     RECT  53.04 32.197 54.696 32.531 ;
     RECT  58.704 30.661 59.412 32.531 ;
     RECT  64.5 31.141 64.968 32.531 ;
     RECT  34.8 31.381 35.208 32.581 ;
     RECT  42.144 31.141 43.212 32.723 ;
     RECT  34.656 32.581 35.208 32.771 ;
     RECT  48.3 32.483 48.744 32.771 ;
     RECT  34.8 32.771 35.208 32.869 ;
     RECT  17.376 32.291 20.04 33.011 ;
     RECT  5.1 30.851 5.412 33.013 ;
     RECT  6.864 32.483 8.112 33.013 ;
     RECT  21.3 32.485 22.152 33.013 ;
     RECT  48.3 32.771 48.612 33.013 ;
     RECT  61.8 31.187 62.232 33.013 ;
     RECT  67.2 28.691 67.512 33.013 ;
     RECT  2.4 31.621 2.904 33.059 ;
     RECT  74.112 32.051 75.612 33.107 ;
     RECT  72.144 32.291 72.912 33.155 ;
     RECT  21.3 33.013 22.824 33.397 ;
     RECT  24 32.387 24.312 33.397 ;
     RECT  21.3 33.397 24.312 33.443 ;
     RECT  77.136 31.861 78.312 33.443 ;
     RECT  77.472 33.443 78.312 33.541 ;
     RECT  53.568 32.531 54.696 33.589 ;
     RECT  4.512 33.013 8.112 33.829 ;
     RECT  10.176 32.149 10.812 33.875 ;
     RECT  44.928 31.955 46.296 33.877 ;
     RECT  40.2 31.043 40.512 34.069 ;
     RECT  41.904 33.973 41.928 34.069 ;
     RECT  69.9 32.243 70.212 34.117 ;
     RECT  17.376 33.011 19.752 34.165 ;
     RECT  28.704 30.803 29.712 34.165 ;
     RECT  30.72 32.149 30.744 34.165 ;
     RECT  51 31.811 51.312 34.165 ;
     RECT  23.136 33.443 24.312 34.211 ;
     RECT  40.2 34.069 41.928 34.211 ;
     RECT  47.904 33.013 48.612 34.211 ;
     RECT  77.472 33.541 78.408 34.211 ;
     RECT  37.2 32.243 38.328 34.259 ;
     RECT  4.512 33.829 8.76 34.355 ;
     RECT  26.304 32.387 27.72 34.355 ;
     RECT  28.704 34.165 30.744 34.355 ;
     RECT  32.1 29.747 32.412 34.405 ;
     RECT  37.2 34.259 37.812 34.405 ;
     RECT  51 34.165 52.296 34.405 ;
     RECT  80.592 25.429 81.012 34.501 ;
     RECT  34.8 32.869 35.256 34.547 ;
     RECT  12.096 33.013 12.12 34.595 ;
     RECT  60.384 33.013 60.408 34.595 ;
     RECT  34.8 34.547 35.112 34.597 ;
     RECT  66.672 33.013 67.512 34.643 ;
     RECT  10.5 33.875 10.812 34.741 ;
     RECT  13.2 31.379 14.184 34.835 ;
     RECT  17.376 34.165 20.04 34.835 ;
     RECT  53.568 33.589 55.32 34.835 ;
     RECT  61.8 33.013 62.52 34.835 ;
     RECT  69.9 34.117 70.824 34.835 ;
     RECT  77.472 34.211 78.312 34.835 ;
     RECT  50.64 34.405 52.296 34.883 ;
     RECT  72.288 33.155 72.912 34.883 ;
     RECT  41.904 34.211 41.928 34.931 ;
     RECT  44.928 33.877 46.824 34.931 ;
     RECT  4.512 34.355 8.112 34.979 ;
     RECT  79.824 34.501 81.012 35.027 ;
     RECT  32.1 34.405 32.904 35.077 ;
     RECT  28.704 34.355 30.264 35.267 ;
     RECT  72.6 34.883 72.912 35.269 ;
     RECT  34.704 34.597 35.112 35.459 ;
     RECT  21.3 33.443 22.152 35.605 ;
     RECT  51 34.883 52.296 35.699 ;
     RECT  15.9 32.291 16.212 35.701 ;
     RECT  5.1 34.979 8.112 35.845 ;
     RECT  59.1 32.531 59.412 35.845 ;
     RECT  5.1 35.845 8.76 35.939 ;
     RECT  44.928 34.931 45.912 35.989 ;
     RECT  55.296 34.835 55.32 36.035 ;
     RECT  6.864 35.939 8.76 36.131 ;
     RECT  32.1 35.077 32.952 36.229 ;
     RECT  31.968 36.229 32.952 36.275 ;
     RECT  51 35.699 51.312 36.277 ;
     RECT  59.1 35.845 60.216 36.323 ;
     RECT  15.792 35.701 16.212 36.421 ;
     RECT  78 34.835 78.312 36.421 ;
     RECT  40.2 34.211 40.512 36.469 ;
     RECT  17.376 34.835 19.752 36.515 ;
     RECT  21.3 35.605 22.776 36.517 ;
     RECT  34.8 35.459 35.112 36.517 ;
     RECT  56.4 30.757 57.48 36.517 ;
     RECT  21.168 36.517 22.776 36.659 ;
     RECT  53.568 34.835 54.12 36.659 ;
     RECT  21.168 36.659 22.152 36.853 ;
     RECT  42.9 32.723 43.212 36.997 ;
     RECT  36.384 34.405 37.812 37.091 ;
     RECT  53.7 36.659 54.12 37.091 ;
     RECT  72.6 35.269 73.128 37.331 ;
     RECT  34.8 36.517 35.208 37.429 ;
     RECT  36.384 37.091 36.504 37.429 ;
     RECT  67.2 34.643 67.512 37.429 ;
     RECT  69.9 34.835 70.212 37.429 ;
     RECT  26.7 34.355 27.72 37.573 ;
     RECT  28.704 35.267 29.712 37.573 ;
     RECT  48.3 34.211 48.612 37.573 ;
     RECT  80.7 35.027 81.012 37.573 ;
     RECT  44.928 35.989 46.728 37.619 ;
     RECT  50.832 36.277 51.312 37.619 ;
     RECT  77.328 36.421 78.312 37.619 ;
     RECT  34.8 37.429 36.504 37.667 ;
     RECT  5.1 35.939 5.412 37.669 ;
     RECT  7.056 36.131 8.76 37.859 ;
     RECT  42.768 36.997 43.212 37.907 ;
     RECT  17.376 36.515 19.416 38.147 ;
     RECT  25.392 36.997 25.416 38.147 ;
     RECT  59.1 36.323 59.412 38.149 ;
     RECT  44.928 37.619 46.488 38.243 ;
     RECT  74.88 33.107 75.612 38.243 ;
     RECT  24 34.211 24.312 38.341 ;
     RECT  40.2 36.469 41.352 38.387 ;
     RECT  15.168 36.421 16.212 38.435 ;
     RECT  23.328 38.341 24.312 38.437 ;
     RECT  48.192 37.573 48.612 38.485 ;
     RECT  17.376 38.147 19.32 38.531 ;
     RECT  20.688 36.853 22.152 38.531 ;
     RECT  23.328 38.437 25.08 38.579 ;
     RECT  48.192 38.485 48.936 38.675 ;
     RECT  75.168 38.243 75.612 38.675 ;
     RECT  67.2 37.429 68.328 38.723 ;
     RECT  69.792 37.429 70.212 38.723 ;
     RECT  67.2 38.723 68.088 38.725 ;
     RECT  7.056 37.859 8.52 38.915 ;
     RECT  59.1 38.149 59.832 38.915 ;
     RECT  56.4 36.517 57.528 38.917 ;
     RECT  26.7 37.573 29.712 39.059 ;
     RECT  10.5 34.741 11.304 39.061 ;
     RECT  13.2 34.835 13.512 39.061 ;
     RECT  26.7 39.059 27.012 39.157 ;
     RECT  50.88 37.619 51.312 39.253 ;
     RECT  66.624 38.725 68.088 39.395 ;
     RECT  64.5 32.531 64.812 39.493 ;
     RECT  48.3 38.675 48.936 39.779 ;
     RECT  61.8 34.835 62.112 39.829 ;
     RECT  5.1 37.669 5.784 39.877 ;
     RECT  12.336 39.061 13.512 39.923 ;
     RECT  15.552 38.435 16.212 39.923 ;
     RECT  10.368 39.061 11.304 40.019 ;
     RECT  21.12 38.531 22.152 40.067 ;
     RECT  64.5 39.493 65.448 40.259 ;
     RECT  61.584 39.829 62.112 40.261 ;
     RECT  46.992 38.677 47.016 40.307 ;
     RECT  26.208 39.157 27.012 40.309 ;
     RECT  40.2 38.387 41.256 40.309 ;
     RECT  4.464 39.877 5.784 40.355 ;
     RECT  13.104 39.923 13.512 40.357 ;
     RECT  13.104 40.357 13.704 40.403 ;
     RECT  60.72 40.261 62.112 40.403 ;
     RECT  55.824 38.917 57.528 40.405 ;
     RECT  59.1 38.915 59.412 40.405 ;
     RECT  25.632 40.309 27.012 40.691 ;
     RECT  40.2 40.309 41.496 40.693 ;
     RECT  42.9 37.907 43.212 40.693 ;
     RECT  63.264 39.829 63.288 40.787 ;
     RECT  61.584 40.403 62.112 40.835 ;
     RECT  34.8 37.667 36.024 40.837 ;
     RECT  75.3 38.675 75.612 40.885 ;
     RECT  34.704 40.837 36.024 40.979 ;
     RECT  72.6 37.331 72.912 40.981 ;
     RECT  13.2 40.403 13.704 41.075 ;
     RECT  28.704 39.059 29.712 41.075 ;
     RECT  40.2 40.693 43.212 41.075 ;
     RECT  50.736 39.253 51.312 41.125 ;
     RECT  55.824 40.405 59.412 41.221 ;
     RECT  31.968 36.275 32.412 41.459 ;
     RECT  10.5 40.019 11.304 41.509 ;
     RECT  17.376 38.531 18.912 41.509 ;
     RECT  13.2 41.075 13.512 41.557 ;
     RECT  4.464 40.355 5.412 41.651 ;
     RECT  55.344 41.221 59.412 41.651 ;
     RECT  61.68 40.835 62.112 41.699 ;
     RECT  25.632 40.691 25.656 41.747 ;
     RECT  7.056 38.915 8.112 41.797 ;
     RECT  15.9 39.923 16.212 41.797 ;
     RECT  75.168 40.885 75.612 41.797 ;
     RECT  21.168 40.067 22.152 41.893 ;
     RECT  23.328 38.579 24.312 41.893 ;
     RECT  53.7 37.091 54.012 41.893 ;
     RECT  21.168 41.893 24.312 41.939 ;
     RECT  50.736 41.125 51.96 41.939 ;
     RECT  7.008 41.797 8.112 42.085 ;
     RECT  69.9 38.723 70.212 42.133 ;
     RECT  12.528 41.557 13.512 42.467 ;
     RECT  56.4 41.651 59.412 42.659 ;
     RECT  55.344 41.651 55.368 42.661 ;
     RECT  56.4 42.659 57.576 42.661 ;
     RECT  53.04 41.893 54.012 42.709 ;
     RECT  10.368 41.509 11.304 42.755 ;
     RECT  17.376 41.509 19.416 42.755 ;
     RECT  21.3 41.939 24.312 42.755 ;
     RECT  40.2 41.075 41.256 42.755 ;
     RECT  75.12 41.797 75.612 42.755 ;
     RECT  29.088 41.075 29.712 42.757 ;
     RECT  55.344 42.661 57.576 42.803 ;
     RECT  53.04 42.709 54.12 42.851 ;
     RECT  38.928 42.613 38.952 42.997 ;
     RECT  44.928 38.243 45.912 42.997 ;
     RECT  6.624 42.085 8.112 43.043 ;
     RECT  34.8 40.979 36.024 43.043 ;
     RECT  40.2 42.755 41.064 43.043 ;
     RECT  15.552 41.797 16.212 43.093 ;
     RECT  17.376 42.755 18.912 43.093 ;
     RECT  69.9 42.133 70.68 43.139 ;
     RECT  28.416 42.757 29.712 43.141 ;
     RECT  72.48 40.981 72.912 43.285 ;
     RECT  15.552 43.093 18.912 43.331 ;
     RECT  28.416 43.141 30.312 43.379 ;
     RECT  38.784 42.997 38.952 43.379 ;
     RECT  56.4 42.803 57.576 43.379 ;
     RECT  5.1 41.651 5.412 43.621 ;
     RECT  50.736 41.939 51.312 43.621 ;
     RECT  10.368 42.755 11.016 43.861 ;
     RECT  13.2 42.467 13.512 43.861 ;
     RECT  61.8 41.699 62.112 43.861 ;
     RECT  42.9 41.075 43.212 43.909 ;
     RECT  3.936 43.909 3.96 44.099 ;
     RECT  40.2 43.043 40.512 44.101 ;
     RECT  75.3 42.755 75.612 44.101 ;
     RECT  40.2 44.101 40.776 44.197 ;
     RECT  15.9 43.331 18.912 44.293 ;
     RECT  20.016 43.141 20.04 44.293 ;
     RECT  15.9 44.293 20.04 44.339 ;
     RECT  34.8 43.043 35.112 44.341 ;
     RECT  21.3 42.755 22.968 44.387 ;
     RECT  44.928 42.997 46.008 44.387 ;
     RECT  74.976 44.101 75.612 44.435 ;
     RECT  80.592 37.573 81.012 44.437 ;
     RECT  28.128 43.909 28.152 44.483 ;
     RECT  38.784 43.379 38.808 44.483 ;
     RECT  50.688 43.621 51.312 44.483 ;
     RECT  37.5 37.091 37.812 44.533 ;
     RECT  7.152 43.043 8.112 44.579 ;
     RECT  78 37.619 78.312 44.677 ;
     RECT  66.624 39.395 67.512 44.723 ;
     RECT  61.68 43.861 62.112 44.773 ;
     RECT  53.7 42.851 54.12 44.917 ;
     RECT  72.432 43.285 72.912 45.011 ;
     RECT  5.1 43.621 5.736 45.059 ;
     RECT  15.9 44.339 19.848 45.059 ;
     RECT  34.224 44.341 35.112 45.059 ;
     RECT  77.472 44.677 78.312 45.059 ;
     RECT  5.1 45.059 5.412 45.157 ;
     RECT  24 42.755 24.312 45.157 ;
     RECT  80.544 44.437 81.012 45.253 ;
     RECT  79.68 45.253 81.012 45.299 ;
     RECT  42.9 43.909 43.8 45.347 ;
     RECT  21.3 44.387 22.824 45.491 ;
     RECT  9.6 43.861 11.016 45.541 ;
     RECT  21.3 45.491 22.152 45.541 ;
     RECT  64.5 40.259 64.812 45.541 ;
     RECT  66.72 44.723 67.512 45.541 ;
     RECT  66.72 45.541 67.752 45.587 ;
     RECT  40.2 44.197 41.016 45.635 ;
     RECT  4.992 45.157 5.412 45.731 ;
     RECT  50.88 44.483 51.312 45.731 ;
     RECT  79.68 45.299 79.704 45.875 ;
     RECT  13.2 43.861 13.608 45.971 ;
     RECT  56.4 43.379 56.712 46.069 ;
     RECT  9.6 45.541 11.112 46.163 ;
     RECT  61.584 44.773 62.112 46.163 ;
     RECT  42.9 45.347 43.608 46.211 ;
     RECT  53.568 44.917 54.12 46.211 ;
     RECT  63.312 44.917 63.336 46.211 ;
     RECT  67.2 45.587 67.752 46.211 ;
     RECT  15.9 45.059 18.912 46.259 ;
     RECT  24 45.157 24.408 46.259 ;
     RECT  37.5 44.533 38.76 46.259 ;
     RECT  64.5 45.541 65.352 46.259 ;
     RECT  71.328 44.917 71.352 46.259 ;
     RECT  26.7 40.691 27.012 46.261 ;
     RECT  29.4 43.379 30.312 46.307 ;
     RECT  44.928 44.387 45.912 46.549 ;
     RECT  72.6 45.011 72.912 46.597 ;
     RECT  53.7 46.211 54.12 46.645 ;
     RECT  75.3 44.435 75.612 46.645 ;
     RECT  21.168 45.541 22.152 46.693 ;
     RECT  7.68 44.579 8.112 46.741 ;
     RECT  10.5 46.163 11.112 46.787 ;
     RECT  40.2 45.635 40.92 46.787 ;
     RECT  32.1 41.459 32.412 46.789 ;
     RECT  42.9 46.211 43.212 46.789 ;
     RECT  75.3 46.645 76.056 46.933 ;
     RECT  40.2 46.787 40.512 47.029 ;
     RECT  56.4 46.069 57.624 47.029 ;
     RECT  51 45.731 51.312 47.077 ;
     RECT  5.1 45.731 5.412 47.269 ;
     RECT  7.152 46.741 8.112 47.269 ;
     RECT  24 46.259 24.312 47.269 ;
     RECT  61.8 46.163 62.112 47.269 ;
     RECT  29.4 46.307 29.712 47.317 ;
     RECT  15.9 46.259 16.212 47.365 ;
     RECT  17.376 46.259 18.912 47.365 ;
     RECT  34.8 45.059 35.112 47.701 ;
     RECT  26.448 46.261 27.012 47.747 ;
     RECT  53.7 46.645 54.6 47.749 ;
     RECT  74.544 46.933 76.056 47.843 ;
     RECT  10.5 46.787 10.812 47.845 ;
     RECT  20.544 46.693 22.152 47.845 ;
     RECT  37.5 46.259 37.812 47.845 ;
     RECT  50.112 47.077 51.312 47.845 ;
     RECT  61.584 47.269 62.112 47.845 ;
     RECT  64.5 46.259 64.812 47.845 ;
     RECT  67.2 46.211 67.512 47.845 ;
     RECT  74.544 47.843 75.612 47.891 ;
     RECT  15.9 47.365 18.912 47.893 ;
     RECT  72.336 46.597 72.912 47.987 ;
     RECT  56.304 47.029 57.624 48.085 ;
     RECT  56.304 48.085 57.912 48.131 ;
     RECT  61.584 47.845 62.232 48.131 ;
     RECT  56.304 48.131 56.856 48.227 ;
     RECT  80.7 45.299 81.012 48.229 ;
     RECT  15.408 47.893 18.912 48.371 ;
     RECT  78 45.059 78.312 48.373 ;
     RECT  5.1 47.269 8.112 48.419 ;
     RECT  42.672 46.789 43.212 48.421 ;
     RECT  64.5 47.845 65.16 48.421 ;
     RECT  20.544 47.845 22.968 48.467 ;
     RECT  29.088 47.317 29.712 48.467 ;
     RECT  37.5 47.845 37.944 48.467 ;
     RECT  64.5 48.421 66.12 48.467 ;
     RECT  39.84 47.029 40.512 48.469 ;
     RECT  10.5 47.845 11.016 48.515 ;
     RECT  7.152 48.419 8.112 48.659 ;
     RECT  53.136 47.749 54.6 48.659 ;
     RECT  57.888 48.131 57.912 48.659 ;
     RECT  32.1 46.789 33.096 48.755 ;
     RECT  32.1 48.755 32.412 48.805 ;
     RECT  69.9 43.139 70.212 48.805 ;
     RECT  71.232 47.797 71.256 48.805 ;
     RECT  17.616 48.371 18.912 48.947 ;
     RECT  29.28 48.467 29.712 48.949 ;
     RECT  30.768 47.749 30.792 48.949 ;
     RECT  37.5 48.467 37.812 48.949 ;
     RECT  29.28 48.949 30.792 48.995 ;
     RECT  69.9 48.805 71.256 49.043 ;
     RECT  39.792 48.469 40.512 49.091 ;
     RECT  49.824 47.845 51.312 49.091 ;
     RECT  74.688 47.891 75.612 49.091 ;
     RECT  66.096 48.467 66.12 49.187 ;
     RECT  67.2 47.845 68.328 49.235 ;
     RECT  56.304 48.227 56.712 49.379 ;
     RECT  36.768 48.949 37.812 49.475 ;
     RECT  10.5 48.515 10.812 49.525 ;
     RECT  12 49.477 12.024 49.525 ;
     RECT  61.8 48.131 62.232 49.859 ;
     RECT  15.408 48.371 16.344 50.003 ;
     RECT  15.9 50.003 16.344 50.053 ;
     RECT  17.712 48.947 18.912 50.053 ;
     RECT  67.2 49.235 67.512 50.053 ;
     RECT  77.232 48.373 78.312 50.053 ;
     RECT  21.3 48.467 22.968 50.147 ;
     RECT  24 47.269 25.128 50.291 ;
     RECT  44.592 46.549 45.912 50.581 ;
     RECT  56.4 49.379 56.712 50.629 ;
     RECT  29.28 48.995 30.216 50.677 ;
     RECT  75.3 49.091 75.612 50.821 ;
     RECT  42.144 48.421 43.212 50.867 ;
     RECT  53.136 48.659 54.012 50.867 ;
     RECT  77.232 50.053 78.408 50.867 ;
     RECT  34.8 47.701 35.208 50.965 ;
     RECT  36.48 50.773 36.504 50.965 ;
     RECT  55.92 50.629 56.712 51.253 ;
     RECT  64.5 48.467 64.812 51.253 ;
     RECT  65.808 50.677 65.832 51.253 ;
     RECT  66.96 50.053 67.512 51.253 ;
     RECT  78 50.867 78.408 51.253 ;
     RECT  15.9 50.053 18.912 51.347 ;
     RECT  81.984 50.101 82.008 51.347 ;
     RECT  34.8 50.965 36.504 51.443 ;
     RECT  31.92 48.805 32.412 51.635 ;
     RECT  17.712 51.347 18.912 51.637 ;
     RECT  20.208 48.949 20.232 51.637 ;
     RECT  26.592 47.747 27.012 51.637 ;
     RECT  61.8 49.859 62.112 51.685 ;
     RECT  64.5 51.253 65.832 51.685 ;
     RECT  66.816 51.253 67.512 51.685 ;
     RECT  64.5 51.685 67.512 51.731 ;
     RECT  5.1 48.419 5.412 51.733 ;
     RECT  6.528 51.637 6.552 51.733 ;
     RECT  74.544 50.821 75.612 51.733 ;
     RECT  7.68 48.659 8.112 51.781 ;
     RECT  26.592 51.637 27.144 51.829 ;
     RECT  72.6 47.987 72.912 51.829 ;
     RECT  69.9 49.043 70.728 51.875 ;
     RECT  36.096 51.443 36.504 51.923 ;
     RECT  78 51.253 78.84 51.923 ;
     RECT  42.9 50.867 43.212 52.021 ;
     RECT  32.1 51.635 32.412 52.117 ;
     RECT  28.752 50.677 30.216 52.163 ;
     RECT  10.5 49.525 12.024 52.211 ;
     RECT  66.096 51.731 67.512 52.211 ;
     RECT  5.1 51.733 6.552 52.261 ;
     RECT  21.3 50.147 22.152 52.261 ;
     RECT  24 50.291 24.312 52.261 ;
     RECT  42.9 52.021 43.32 52.307 ;
     RECT  28.752 52.163 29.712 52.405 ;
     RECT  49.824 49.091 49.848 52.405 ;
     RECT  53.7 50.867 54.012 52.405 ;
     RECT  49.632 52.405 49.848 52.451 ;
     RECT  42.9 52.307 43.212 52.453 ;
     RECT  4.944 52.261 6.552 52.499 ;
     RECT  64.5 51.731 65.064 52.691 ;
     RECT  15.9 51.347 16.212 52.789 ;
     RECT  21.3 52.261 24.312 52.835 ;
     RECT  32.1 52.117 32.52 52.981 ;
     RECT  37.5 49.475 37.812 52.981 ;
     RECT  49.632 52.451 49.656 52.981 ;
     RECT  59.1 42.659 59.412 52.981 ;
     RECT  4.944 52.499 6.216 53.027 ;
     RECT  53.568 52.405 54.456 53.029 ;
     RECT  55.68 51.253 56.712 53.029 ;
     RECT  44.592 50.581 46.824 53.075 ;
     RECT  52.416 51.829 52.44 53.075 ;
     RECT  25.68 51.829 27.144 53.077 ;
     RECT  7.584 51.781 8.112 53.123 ;
     RECT  48.3 39.779 48.612 53.125 ;
     RECT  36.096 51.923 36.12 53.413 ;
     RECT  74.544 51.733 75.72 53.459 ;
     RECT  41.952 52.453 43.212 53.555 ;
     RECT  10.5 52.211 11.112 53.557 ;
     RECT  3.936 52.549 3.96 53.603 ;
     RECT  14.832 53.317 14.856 53.603 ;
     RECT  37.5 52.981 37.944 53.603 ;
     RECT  44.592 53.075 46.2 53.603 ;
     RECT  71.808 51.829 72.912 53.651 ;
     RECT  13.2 45.971 13.512 53.653 ;
     RECT  61.584 51.685 62.112 53.795 ;
     RECT  23.088 52.835 24.312 53.797 ;
     RECT  17.712 51.637 20.232 53.843 ;
     RECT  22.896 53.797 24.312 54.037 ;
     RECT  10.5 53.557 11.448 54.085 ;
     RECT  39.936 49.091 40.512 54.085 ;
     RECT  49.584 52.981 49.656 54.085 ;
     RECT  51 49.091 51.312 54.085 ;
     RECT  49.584 54.085 51.312 54.131 ;
     RECT  36.096 53.413 36.36 54.229 ;
     RECT  36.096 54.229 36.408 54.275 ;
     RECT  10.5 54.085 11.976 54.325 ;
     RECT  28.656 52.405 29.712 54.421 ;
     RECT  64.5 52.691 64.812 54.469 ;
     RECT  32.1 52.981 32.664 54.565 ;
     RECT  69.9 51.875 70.212 54.565 ;
     RECT  32.1 54.565 33.528 54.611 ;
     RECT  36.336 54.275 36.408 54.659 ;
     RECT  9.504 52.981 9.528 54.661 ;
     RECT  10.5 54.325 12.072 54.661 ;
     RECT  36.384 54.659 36.408 54.661 ;
     RECT  64.5 54.469 64.92 54.661 ;
     RECT  69.9 54.565 70.728 54.661 ;
     RECT  22.896 54.037 24.552 54.707 ;
     RECT  7.8 53.123 8.112 54.709 ;
     RECT  72.6 53.651 72.912 54.853 ;
     RECT  28.656 54.421 30.456 54.899 ;
     RECT  60.48 50.437 60.504 54.947 ;
     RECT  74.544 53.459 75.612 54.949 ;
     RECT  53.568 53.029 56.712 54.995 ;
     RECT  4.944 53.027 5.736 55.139 ;
     RECT  15.9 52.789 16.536 55.139 ;
     RECT  24 54.707 24.552 55.237 ;
     RECT  25.632 53.077 27.144 55.237 ;
     RECT  47.856 53.125 48.612 55.237 ;
     RECT  74.16 54.949 75.612 55.283 ;
     RECT  9.504 54.661 12.072 55.331 ;
     RECT  24 55.237 27.144 55.331 ;
     RECT  42.768 53.555 43.212 55.331 ;
     RECT  66.816 52.211 67.512 55.331 ;
     RECT  25.44 55.331 27.144 55.427 ;
     RECT  53.568 54.995 54.744 55.475 ;
     RECT  13.2 53.653 14.424 55.477 ;
     RECT  13.2 55.477 14.616 55.619 ;
     RECT  20.016 53.843 20.232 55.667 ;
     RECT  49.632 54.131 51.312 55.667 ;
     RECT  61.8 53.795 62.112 55.669 ;
     RECT  9.6 55.331 12.072 55.715 ;
     RECT  10.5 55.715 12.072 55.813 ;
     RECT  13.2 55.619 14.52 55.813 ;
     RECT  17.712 53.843 18.912 55.813 ;
     RECT  20.016 55.667 20.04 55.813 ;
     RECT  28.752 54.899 30.456 55.859 ;
     RECT  28.752 55.859 29.712 55.861 ;
     RECT  49.632 55.667 49.656 55.907 ;
     RECT  7.152 54.709 8.112 55.955 ;
     RECT  36.384 54.661 36.456 55.957 ;
     RECT  37.5 53.603 37.812 55.957 ;
     RECT  56.064 54.995 56.712 55.957 ;
     RECT  58.464 52.981 59.412 56.003 ;
     RECT  72.48 54.853 72.912 56.099 ;
     RECT  80.592 48.229 81.012 56.099 ;
     RECT  7.8 55.955 8.112 56.101 ;
     RECT  53.7 55.475 54.744 56.291 ;
     RECT  33.504 54.611 33.528 56.293 ;
     RECT  64.5 54.661 64.968 56.341 ;
     RECT  56.064 55.957 57.288 56.389 ;
     RECT  10.5 55.813 14.52 56.483 ;
     RECT  25.44 55.427 27.012 56.483 ;
     RECT  39.216 54.085 40.512 56.485 ;
     RECT  61.8 55.669 62.76 56.485 ;
     RECT  69.9 54.661 70.776 56.485 ;
     RECT  4.944 55.139 5.688 56.531 ;
     RECT  26.208 56.483 27.012 56.531 ;
     RECT  28.224 55.861 29.712 56.531 ;
     RECT  13.2 56.483 14.52 56.627 ;
     RECT  61.8 56.485 62.856 56.627 ;
     RECT  33.504 56.293 33.576 56.629 ;
     RECT  64.5 56.341 65.352 56.675 ;
     RECT  4.944 56.531 5.412 56.677 ;
     RECT  39.216 56.485 41.16 56.869 ;
     RECT  38.88 56.869 41.16 56.915 ;
     RECT  22.896 54.707 22.92 57.011 ;
     RECT  7.8 56.101 8.568 57.013 ;
     RECT  17.712 55.813 20.04 57.013 ;
     RECT  69.216 56.485 70.776 57.013 ;
     RECT  61.8 56.627 62.76 57.059 ;
     RECT  69.072 57.013 70.776 57.061 ;
     RECT  42.9 55.331 43.212 57.109 ;
     RECT  44.592 53.603 45.912 57.109 ;
     RECT  72.6 56.099 72.912 57.109 ;
     RECT  17.712 57.013 20.136 57.155 ;
     RECT  30.96 56.389 30.984 57.251 ;
     RECT  68.976 57.061 70.776 57.347 ;
     RECT  24 55.331 24.312 57.397 ;
     RECT  36.384 55.957 37.812 57.445 ;
     RECT  38.88 56.915 38.904 57.445 ;
     RECT  75.3 55.283 75.612 57.445 ;
     RECT  69.072 57.347 70.776 57.491 ;
     RECT  36.384 57.445 38.904 57.539 ;
     RECT  75.3 57.445 75.72 57.541 ;
     RECT  56.064 56.389 57.768 57.587 ;
     RECT  61.8 57.059 62.232 57.635 ;
     RECT  21.3 52.835 21.612 57.637 ;
     RECT  24 57.397 24.408 57.731 ;
     RECT  78 51.923 78.312 57.877 ;
     RECT  33.456 56.629 33.576 57.925 ;
     RECT  34.8 51.443 35.112 57.925 ;
     RECT  69.744 57.491 70.776 57.971 ;
     RECT  7.104 57.013 8.568 57.973 ;
     RECT  22.656 57.013 22.68 57.973 ;
     RECT  13.2 56.627 14.424 58.021 ;
     RECT  15.9 55.139 16.344 58.021 ;
     RECT  72.144 57.109 72.912 58.021 ;
     RECT  10.5 56.483 10.812 58.117 ;
     RECT  11.952 56.483 12.168 58.117 ;
     RECT  47.664 55.237 48.612 58.117 ;
     RECT  53.7 56.291 54.012 58.117 ;
     RECT  58.848 56.003 59.412 58.117 ;
     RECT  67.2 55.331 67.512 58.117 ;
     RECT  33.456 57.925 35.112 58.163 ;
     RECT  37.5 57.539 38.904 58.163 ;
     RECT  56.4 57.587 57.288 58.163 ;
     RECT  47.136 58.117 48.612 58.211 ;
     RECT  81.984 56.965 82.008 58.259 ;
     RECT  67.2 58.117 67.704 58.309 ;
     RECT  21.024 57.637 21.612 58.403 ;
     RECT  58.848 58.117 59.736 58.451 ;
     RECT  34.176 58.163 35.112 58.597 ;
     RECT  7.104 57.973 8.664 58.645 ;
     RECT  22.656 57.973 22.824 58.645 ;
     RECT  34.176 58.597 35.208 58.645 ;
     RECT  36.384 57.539 36.456 58.645 ;
     RECT  72.144 58.021 73.128 58.645 ;
     RECT  74.16 55.283 74.184 58.645 ;
     RECT  78 57.877 78.408 58.645 ;
     RECT  10.5 58.117 12.168 58.691 ;
     RECT  21.072 58.403 21.612 58.739 ;
     RECT  28.512 56.531 29.712 58.739 ;
     RECT  66.672 58.309 67.704 58.739 ;
     RECT  26.7 56.531 27.012 58.741 ;
     RECT  64.5 56.675 65.016 58.741 ;
     RECT  13.2 58.021 16.344 58.787 ;
     RECT  42.9 57.109 45.912 58.835 ;
     RECT  25.728 58.741 27.012 58.883 ;
     RECT  28.896 58.739 29.712 58.883 ;
     RECT  10.5 58.691 11.976 58.931 ;
     RECT  13.2 58.787 16.212 58.933 ;
     RECT  69.744 57.971 70.212 59.029 ;
     RECT  61.8 57.635 62.112 59.173 ;
     RECT  78 58.645 78.504 59.173 ;
     RECT  13.104 58.933 16.212 59.219 ;
     RECT  34.176 58.645 36.456 59.219 ;
     RECT  22.656 58.645 22.92 59.221 ;
     RECT  24 57.731 24.312 59.221 ;
     RECT  69.264 59.029 70.212 59.221 ;
     RECT  49.584 58.645 49.608 59.267 ;
     RECT  75.3 57.541 76.392 59.315 ;
     RECT  6.816 58.645 8.664 59.459 ;
     RECT  26.7 58.883 27.012 59.701 ;
     RECT  29.04 58.883 29.712 59.747 ;
     RECT  22.656 59.221 24.312 59.749 ;
     RECT  58.992 58.451 59.736 59.749 ;
     RECT  72.144 58.645 74.184 59.795 ;
     RECT  21.3 58.739 21.612 59.797 ;
     RECT  52.512 59.605 52.536 59.891 ;
     RECT  53.7 58.117 54.264 59.891 ;
     RECT  34.8 59.219 36.456 59.939 ;
     RECT  7.104 59.459 8.664 59.987 ;
     RECT  78 59.173 79.32 60.035 ;
     RECT  13.2 59.219 16.212 60.275 ;
     RECT  47.136 58.211 47.16 60.275 ;
     RECT  17.712 57.155 19.176 60.277 ;
     RECT  4.8 56.677 5.412 60.325 ;
     RECT  4.8 60.325 5.544 60.373 ;
     RECT  10.5 58.931 10.812 60.373 ;
     RECT  26.7 59.701 27.96 60.373 ;
     RECT  40.2 56.915 40.512 60.373 ;
     RECT  80.7 56.099 81.012 60.373 ;
     RECT  7.104 59.987 8.112 60.419 ;
     RECT  22.656 59.749 25.128 60.419 ;
     RECT  42.9 58.835 43.212 60.421 ;
     RECT  44.592 58.835 45.912 60.421 ;
     RECT  72.336 59.795 74.184 60.421 ;
     RECT  75.3 59.315 76.296 60.421 ;
     RECT  36.144 59.939 36.456 60.563 ;
     RECT  21.072 59.797 21.612 60.565 ;
     RECT  22.656 60.419 24.312 60.611 ;
     RECT  66.672 58.739 67.608 60.611 ;
     RECT  37.5 58.163 38.376 60.851 ;
     RECT  11.952 58.931 11.976 60.949 ;
     RECT  33.744 59.797 33.768 61.043 ;
     RECT  39.888 60.373 40.512 61.043 ;
     RECT  42.9 60.421 45.912 61.043 ;
     RECT  20.88 60.565 21.612 61.091 ;
     RECT  7.8 60.419 8.112 61.189 ;
     RECT  32.1 54.611 32.412 61.189 ;
     RECT  49.968 60.373 49.992 61.189 ;
     RECT  51 55.667 51.312 61.189 ;
     RECT  42.9 61.043 43.212 61.237 ;
     RECT  13.2 60.275 14.424 61.333 ;
     RECT  15.792 60.275 16.212 61.333 ;
     RECT  72.336 60.421 76.296 61.379 ;
     RECT  66.672 60.611 67.512 61.427 ;
     RECT  4.8 60.373 5.64 61.525 ;
     RECT  17.712 60.277 19.416 61.525 ;
     RECT  26.592 60.373 27.96 61.573 ;
     RECT  64.5 58.741 65.592 61.619 ;
     RECT  34.8 59.939 35.112 61.621 ;
     RECT  36.432 60.563 36.456 61.667 ;
     RECT  58.512 59.749 59.736 61.765 ;
     RECT  13.2 61.333 14.808 61.907 ;
     RECT  56.4 58.163 57.24 61.909 ;
     RECT  22.656 60.611 22.92 61.957 ;
     RECT  24 60.611 24.312 61.957 ;
     RECT  40.2 61.043 40.512 61.957 ;
     RECT  61.8 59.173 62.232 61.957 ;
     RECT  21.3 61.091 21.612 62.053 ;
     RECT  22.656 61.957 24.312 62.053 ;
     RECT  49.968 61.189 51.312 62.101 ;
     RECT  60.912 61.957 62.232 62.149 ;
     RECT  4.8 61.525 5.688 62.195 ;
     RECT  14.784 61.907 14.808 62.195 ;
     RECT  42.144 61.237 43.212 62.195 ;
     RECT  49.824 62.101 51.312 62.195 ;
     RECT  72.6 61.379 75.96 62.195 ;
     RECT  78 60.035 78.408 62.195 ;
     RECT  64.5 61.619 64.968 62.243 ;
     RECT  26.592 61.573 28.056 62.291 ;
     RECT  7.8 61.189 8.232 62.435 ;
     RECT  15.792 61.333 16.584 62.435 ;
     RECT  74.592 62.195 75.96 62.435 ;
     RECT  58.512 61.765 59.928 62.581 ;
     RECT  60.912 62.149 62.664 62.581 ;
     RECT  58.32 62.581 59.928 62.675 ;
     RECT  40.2 61.957 40.632 62.677 ;
     RECT  56.304 61.909 57.24 62.677 ;
     RECT  13.2 61.907 13.656 63.011 ;
     RECT  48.3 58.211 48.612 63.061 ;
     RECT  13.2 63.011 13.608 63.205 ;
     RECT  15.792 62.435 16.212 63.205 ;
     RECT  4.8 62.195 5.544 63.251 ;
     RECT  11.952 60.949 12.072 63.251 ;
     RECT  78 62.195 78.312 63.253 ;
     RECT  26.7 62.291 28.056 63.395 ;
     RECT  15.408 63.205 16.212 63.493 ;
     RECT  7.8 62.435 8.112 63.589 ;
     RECT  64.5 62.243 64.812 63.685 ;
     RECT  71.424 62.389 71.448 63.779 ;
     RECT  15.408 63.493 16.536 63.781 ;
     RECT  17.712 61.525 19.752 63.781 ;
     RECT  29.4 59.747 29.712 63.781 ;
     RECT  26.7 63.395 27.012 63.829 ;
     RECT  60.912 62.581 62.808 63.875 ;
     RECT  52.464 63.349 52.488 64.019 ;
     RECT  28.032 63.395 28.056 64.067 ;
     RECT  42.9 62.195 43.212 64.117 ;
     RECT  44.592 61.043 45.912 64.117 ;
     RECT  79.296 62.773 79.32 64.163 ;
     RECT  56.304 62.677 57.336 64.165 ;
     RECT  47.328 63.061 48.612 64.213 ;
     RECT  25.776 63.829 27.012 64.355 ;
     RECT  40.2 62.677 41.208 64.355 ;
     RECT  42.9 64.117 45.912 64.355 ;
     RECT  15.408 63.781 19.752 64.357 ;
     RECT  13.104 63.205 13.608 64.403 ;
     RECT  36.432 63.205 36.456 64.403 ;
     RECT  34.8 61.621 35.352 64.405 ;
     RECT  4.8 63.251 5.412 64.451 ;
     RECT  47.328 64.213 48.744 64.595 ;
     RECT  61.8 63.875 62.808 64.595 ;
     RECT  11.952 63.251 11.976 64.643 ;
     RECT  77.904 63.253 78.312 64.693 ;
     RECT  21.3 62.053 24.312 64.835 ;
     RECT  48.3 64.595 48.744 64.837 ;
     RECT  49.824 62.195 49.848 64.837 ;
     RECT  80.592 60.373 81.012 64.837 ;
     RECT  15.408 64.357 19.944 64.883 ;
     RECT  23.376 64.835 24.312 64.883 ;
     RECT  5.1 64.451 5.412 64.885 ;
     RECT  6.912 63.589 8.112 64.885 ;
     RECT  15.408 64.883 16.212 64.931 ;
     RECT  64.5 63.685 65.064 64.979 ;
     RECT  9.648 60.373 10.812 65.027 ;
     RECT  74.592 62.435 75.612 65.029 ;
     RECT  77.52 64.693 78.312 65.075 ;
     RECT  5.1 64.885 8.112 65.125 ;
     RECT  10.08 65.027 10.812 65.171 ;
     RECT  17.712 64.883 19.944 65.171 ;
     RECT  48.3 64.837 49.848 65.171 ;
     RECT  55.872 64.165 57.336 65.173 ;
     RECT  58.32 62.675 59.412 65.173 ;
     RECT  55.872 65.173 59.412 65.219 ;
     RECT  64.5 64.979 64.968 65.269 ;
     RECT  26.7 64.355 27.012 65.365 ;
     RECT  63.984 65.269 64.968 65.411 ;
     RECT  44.592 64.355 45.912 65.413 ;
     RECT  10.272 65.171 10.812 65.509 ;
     RECT  51 62.195 51.312 65.509 ;
     RECT  72.6 62.195 73.272 65.509 ;
     RECT  13.104 64.403 13.512 65.555 ;
     RECT  56.112 65.219 59.412 65.557 ;
     RECT  15.792 64.931 16.212 65.603 ;
     RECT  44.448 65.413 45.912 65.653 ;
     RECT  72.432 65.509 73.272 65.653 ;
     RECT  56.112 65.557 59.832 65.699 ;
     RECT  61.8 64.595 62.232 65.699 ;
     RECT  71.808 65.653 73.272 65.699 ;
     RECT  37.5 60.851 38.232 65.747 ;
     RECT  29.4 63.781 30.216 65.797 ;
     RECT  32.1 61.189 32.856 65.941 ;
     RECT  42.9 64.355 43.212 66.085 ;
     RECT  17.712 65.171 19.416 66.179 ;
     RECT  64.5 65.411 64.968 66.275 ;
     RECT  21.3 64.835 22.248 66.469 ;
     RECT  44.448 65.653 46.008 66.515 ;
     RECT  42.768 66.085 43.212 66.611 ;
     RECT  13.2 65.555 13.512 66.613 ;
     RECT  14.688 66.085 14.712 66.613 ;
     RECT  5.1 65.125 9.096 66.755 ;
     RECT  26.7 65.365 27.672 66.755 ;
     RECT  44.448 66.515 45.912 66.755 ;
     RECT  68.928 59.221 70.212 66.755 ;
     RECT  40.2 64.355 40.632 66.805 ;
     RECT  59.1 65.699 59.832 66.901 ;
     RECT  59.1 66.901 60.648 66.947 ;
     RECT  49.824 65.171 49.848 66.997 ;
     RECT  50.88 65.509 51.312 66.997 ;
     RECT  42.9 66.611 43.212 67.045 ;
     RECT  48.3 65.171 48.612 67.045 ;
     RECT  49.824 66.997 51.312 67.187 ;
     RECT  10.272 65.509 11.208 67.237 ;
     RECT  44.544 66.755 45.912 67.283 ;
     RECT  49.824 67.187 49.992 67.283 ;
     RECT  68.976 66.755 70.212 67.283 ;
     RECT  71.808 65.699 72.912 67.283 ;
     RECT  13.2 66.613 14.712 67.285 ;
     RECT  31.968 65.941 32.856 67.285 ;
     RECT  40.2 66.805 40.776 67.285 ;
     RECT  5.1 66.755 8.112 67.331 ;
     RECT  13.2 67.285 14.808 67.331 ;
     RECT  80.448 64.837 81.012 67.331 ;
     RECT  23.712 64.883 24.312 67.333 ;
     RECT  21.3 66.469 22.344 67.381 ;
     RECT  34.8 64.405 35.784 67.381 ;
     RECT  56.112 65.699 57.576 67.381 ;
     RECT  17.712 66.179 19.176 67.427 ;
     RECT  31.584 67.285 32.856 67.427 ;
     RECT  40.2 67.285 40.872 67.427 ;
     RECT  44.592 67.283 45.912 67.475 ;
     RECT  56.112 67.381 57.72 67.571 ;
     RECT  42.9 67.045 43.368 67.619 ;
     RECT  14.688 67.331 14.808 67.621 ;
     RECT  56.4 67.571 57.72 67.667 ;
     RECT  45.6 67.475 45.912 67.669 ;
     RECT  47.184 66.373 47.208 67.669 ;
     RECT  67.2 61.427 67.512 67.669 ;
     RECT  29.4 65.797 30.504 67.715 ;
     RECT  31.584 67.427 32.412 67.715 ;
     RECT  45.6 67.669 47.208 67.715 ;
     RECT  23.712 67.333 24.408 67.763 ;
     RECT  14.688 67.621 14.856 67.811 ;
     RECT  10.272 67.237 12.024 67.859 ;
     RECT  14.688 67.811 14.808 67.859 ;
     RECT  72.336 67.283 72.912 67.859 ;
     RECT  14.784 67.859 14.808 67.907 ;
     RECT  49.968 67.283 49.992 67.955 ;
     RECT  5.1 67.331 5.736 68.003 ;
     RECT  10.272 67.859 11.592 68.099 ;
     RECT  6.72 67.331 8.112 68.197 ;
     RECT  10.272 68.099 10.812 68.243 ;
     RECT  17.808 67.427 18.912 68.243 ;
     RECT  26.7 66.755 27.012 68.341 ;
     RECT  34.8 67.381 36.408 68.341 ;
     RECT  6.72 68.197 8.664 68.627 ;
     RECT  45.6 67.715 46.584 68.627 ;
     RECT  21.168 67.381 22.344 68.675 ;
     RECT  29.4 67.715 29.88 68.773 ;
     RECT  48.192 67.045 48.612 68.821 ;
     RECT  21.3 68.675 22.344 68.917 ;
     RECT  23.712 67.763 24.312 68.917 ;
     RECT  26.592 68.341 27.012 68.917 ;
     RECT  37.5 65.747 37.944 68.917 ;
     RECT  53.7 59.891 54.012 68.917 ;
     RECT  56.4 67.667 57.576 68.917 ;
     RECT  69.9 67.283 70.212 68.917 ;
     RECT  74.352 65.029 75.612 68.917 ;
     RECT  29.28 68.773 29.88 69.011 ;
     RECT  66.672 67.669 67.512 69.011 ;
     RECT  37.5 68.917 38.808 69.251 ;
     RECT  74.352 68.917 75.816 69.253 ;
     RECT  60.624 66.947 60.648 69.395 ;
     RECT  7.104 68.627 8.664 69.493 ;
     RECT  15.9 65.603 16.212 69.493 ;
     RECT  61.8 65.699 62.112 69.493 ;
     RECT  67.2 69.011 67.512 69.493 ;
     RECT  78 65.075 78.312 69.493 ;
     RECT  47.76 68.821 48.612 69.539 ;
     RECT  74.352 69.253 75.96 69.539 ;
     RECT  34.8 68.341 36.456 69.587 ;
     RECT  53.7 68.917 54.6 69.731 ;
     RECT  64.5 66.275 64.812 69.829 ;
     RECT  74.352 69.539 75.816 69.875 ;
     RECT  80.7 67.331 81.012 69.973 ;
     RECT  31.872 67.715 32.412 70.069 ;
     RECT  45.6 68.627 45.912 70.069 ;
     RECT  78 69.493 78.648 70.069 ;
     RECT  76.896 70.069 78.648 70.163 ;
     RECT  37.5 69.251 37.812 70.357 ;
     RECT  38.784 69.251 38.808 70.357 ;
     RECT  76.896 70.163 78.312 70.451 ;
     RECT  12 69.493 12.024 70.453 ;
     RECT  13.2 67.331 13.512 70.501 ;
     RECT  14.64 70.309 14.664 70.547 ;
     RECT  11.856 70.453 12.024 70.643 ;
     RECT  13.2 70.501 13.608 70.643 ;
     RECT  21.3 68.917 24.312 70.643 ;
     RECT  72.6 67.859 72.912 70.645 ;
     RECT  12 70.643 12.024 70.691 ;
     RECT  51 67.187 51.312 70.693 ;
     RECT  15.9 69.493 17.064 70.787 ;
     RECT  37.5 70.357 38.808 70.981 ;
     RECT  69.072 68.917 70.212 71.075 ;
     RECT  67.2 69.493 67.752 71.077 ;
     RECT  31.392 70.069 32.412 71.221 ;
     RECT  48.3 69.539 48.612 71.221 ;
     RECT  49.68 70.021 49.704 71.221 ;
     RECT  36.912 70.981 38.808 71.267 ;
     RECT  63.936 69.829 64.812 71.315 ;
     RECT  71.856 70.645 72.912 71.363 ;
     RECT  34.8 69.587 35.88 71.411 ;
     RECT  7.104 69.493 8.808 71.603 ;
     RECT  51 70.693 51.528 71.651 ;
     RECT  5.1 68.003 5.412 71.701 ;
     RECT  80.352 69.973 81.012 71.701 ;
     RECT  80.352 71.701 81.24 71.747 ;
     RECT  56.4 68.917 57.624 71.795 ;
     RECT  12.144 71.221 12.168 71.797 ;
     RECT  18.6 68.243 18.912 71.797 ;
     RECT  69.744 71.075 70.212 71.797 ;
     RECT  77.616 70.451 78.312 71.797 ;
     RECT  15.9 70.787 17.016 71.843 ;
     RECT  29.28 69.011 29.712 71.989 ;
     RECT  21.3 70.643 21.612 72.229 ;
     RECT  72.6 71.363 72.912 72.277 ;
     RECT  74.352 69.875 75.612 72.277 ;
     RECT  61.68 69.493 62.112 72.325 ;
     RECT  72.6 72.277 75.612 72.325 ;
     RECT  18.6 71.797 19.368 72.373 ;
     RECT  40.2 67.427 40.512 72.421 ;
     RECT  23.232 70.643 24.312 72.469 ;
     RECT  18.192 72.373 19.368 72.563 ;
     RECT  12.048 71.797 12.168 72.565 ;
     RECT  13.2 70.643 13.512 72.565 ;
     RECT  22.8 72.469 24.312 72.611 ;
     RECT  7.8 71.603 8.808 72.661 ;
     RECT  12.048 72.565 13.512 72.755 ;
     RECT  12.144 72.755 13.512 72.803 ;
     RECT  61.584 72.325 62.112 72.805 ;
     RECT  48.3 71.221 49.704 72.853 ;
     RECT  51 71.651 51.312 72.853 ;
     RECT  41.616 69.541 41.64 72.899 ;
     RECT  60.912 72.805 62.112 72.947 ;
     RECT  72.336 72.325 75.612 72.947 ;
     RECT  48.3 72.853 51.312 72.949 ;
     RECT  48.3 72.949 52.008 72.995 ;
     RECT  18.192 72.563 19.32 73.091 ;
     RECT  66.624 71.077 67.752 73.235 ;
     RECT  69.744 71.797 70.728 73.283 ;
     RECT  28.416 71.989 29.712 73.333 ;
     RECT  28.32 73.333 29.712 73.379 ;
     RECT  4.512 71.701 5.412 73.477 ;
     RECT  7.344 72.661 8.808 73.477 ;
     RECT  40.08 72.421 40.512 73.765 ;
     RECT  36.912 71.267 38.136 73.811 ;
     RECT  61.584 72.947 62.112 73.909 ;
     RECT  39.888 73.765 40.512 74.051 ;
     RECT  20.496 72.229 21.612 74.099 ;
     RECT  64.5 71.315 64.812 74.101 ;
     RECT  72.336 72.947 72.912 74.101 ;
     RECT  74.352 72.947 75.612 74.101 ;
     RECT  72.336 74.101 75.612 74.147 ;
     RECT  13.2 72.803 13.512 74.149 ;
     RECT  3.936 73.477 5.412 74.293 ;
     RECT  7.056 73.477 8.808 74.293 ;
     RECT  45.6 70.069 46.056 74.293 ;
     RECT  13.104 74.149 13.512 74.339 ;
     RECT  48.3 72.995 48.612 74.389 ;
     RECT  45.6 74.293 46.776 74.435 ;
     RECT  3.936 74.293 8.808 74.483 ;
     RECT  41.664 73.525 41.688 74.533 ;
     RECT  41.664 74.533 41.88 74.579 ;
     RECT  44.592 67.475 44.616 74.581 ;
     RECT  72.6 74.147 75.612 74.581 ;
     RECT  3.936 74.483 5.412 74.627 ;
     RECT  23.328 72.611 24.312 74.725 ;
     RECT  25.68 68.917 27.012 74.771 ;
     RECT  47.76 74.389 48.612 74.771 ;
     RECT  60.912 73.909 62.112 74.771 ;
     RECT  77.52 71.797 78.312 74.771 ;
     RECT  49.68 72.995 52.008 74.819 ;
     RECT  59.1 66.947 59.412 74.965 ;
     RECT  72.6 74.581 75.816 75.107 ;
     RECT  28.32 73.379 28.344 75.155 ;
     RECT  61.8 74.771 62.112 75.157 ;
     RECT  39.984 74.051 40.512 75.203 ;
     RECT  7.056 74.483 8.808 75.205 ;
     RECT  10.5 68.243 10.812 75.205 ;
     RECT  18.6 73.091 19.32 75.205 ;
     RECT  53.7 69.731 54.012 75.205 ;
     RECT  66.624 73.235 67.512 75.205 ;
     RECT  7.056 75.205 10.812 75.251 ;
     RECT  41.856 74.579 41.88 75.251 ;
     RECT  74.352 75.107 75.816 75.299 ;
     RECT  36.912 73.811 37.812 75.443 ;
     RECT  23.04 74.725 24.312 75.685 ;
     RECT  29.4 73.379 29.712 75.685 ;
     RECT  31.296 71.221 32.412 75.685 ;
     RECT  78 74.771 78.312 75.685 ;
     RECT  53.7 75.205 54.84 75.875 ;
     RECT  66.624 75.205 68.28 75.875 ;
     RECT  64.128 74.101 64.812 75.971 ;
     RECT  22.8 75.685 24.312 76.021 ;
     RECT  15.9 71.843 16.584 76.165 ;
     RECT  7.8 75.251 10.812 76.211 ;
     RECT  67.2 75.875 68.28 76.211 ;
     RECT  44.4 74.581 44.616 76.309 ;
     RECT  48.3 74.771 48.612 76.309 ;
     RECT  78 75.685 78.408 76.355 ;
     RECT  2.4 33.059 2.712 76.357 ;
     RECT  21.3 74.099 21.612 76.357 ;
     RECT  22.8 76.021 24.552 76.357 ;
     RECT  14.928 76.165 16.584 76.451 ;
     RECT  51 74.819 52.008 76.499 ;
     RECT  31.296 75.685 33.096 76.547 ;
     RECT  69.744 73.283 70.212 76.645 ;
     RECT  18.6 75.205 19.848 76.739 ;
     RECT  34.8 71.411 35.592 76.741 ;
     RECT  29.4 75.685 30.168 76.883 ;
     RECT  18.6 76.739 19.032 76.885 ;
     RECT  40.032 75.203 40.512 76.885 ;
     RECT  47.808 76.309 48.612 76.885 ;
     RECT  67.2 76.211 67.944 76.931 ;
     RECT  2.4 76.357 2.856 76.979 ;
     RECT  6.768 76.837 6.792 76.979 ;
     RECT  55.344 76.309 55.368 76.979 ;
     RECT  58.656 74.965 59.412 76.979 ;
     RECT  21.3 76.357 24.552 76.981 ;
     RECT  21.168 76.981 24.552 77.027 ;
     RECT  18.24 76.885 19.032 77.413 ;
     RECT  53.7 75.875 54.012 77.413 ;
     RECT  26.7 74.771 27.012 77.461 ;
     RECT  74.352 75.299 75.612 77.461 ;
     RECT  23.04 77.027 24.552 77.507 ;
     RECT  49.68 74.819 49.704 77.555 ;
     RECT  44.304 76.309 44.616 77.603 ;
     RECT  14.928 76.451 16.344 77.843 ;
     RECT  21.168 77.027 21.96 77.893 ;
     RECT  15.264 77.843 16.344 77.939 ;
     RECT  69.744 76.645 70.344 77.987 ;
     RECT  80.7 71.747 81.24 77.987 ;
     RECT  20.496 77.893 21.96 77.989 ;
     RECT  23.04 77.507 24.408 77.989 ;
     RECT  45.6 74.435 45.912 77.989 ;
     RECT  47.328 76.885 48.612 78.035 ;
     RECT  10.5 76.211 10.812 78.037 ;
     RECT  18.096 77.413 19.032 78.037 ;
     RECT  61.8 75.157 62.76 78.037 ;
     RECT  40.032 76.885 41.352 78.085 ;
     RECT  64.5 75.971 64.812 78.085 ;
     RECT  20.496 77.989 24.408 78.131 ;
     RECT  31.296 76.547 32.412 78.131 ;
     RECT  34.8 76.741 35.976 78.131 ;
     RECT  69.744 77.987 70.212 78.181 ;
     RECT  72.6 75.107 72.912 78.181 ;
     RECT  74.064 77.461 75.612 78.181 ;
     RECT  10.5 78.037 11.112 78.229 ;
     RECT  26.7 77.461 27.384 78.371 ;
     RECT  39.36 78.085 41.352 78.371 ;
     RECT  4.512 74.627 5.412 78.373 ;
     RECT  68.976 78.181 70.212 78.419 ;
     RECT  23.424 78.131 24.408 78.469 ;
     RECT  25.68 74.771 25.704 78.469 ;
     RECT  72.6 78.181 75.612 78.515 ;
     RECT  37.5 75.443 37.812 78.565 ;
     RECT  23.424 78.469 25.704 78.659 ;
     RECT  15.264 77.939 16.212 78.707 ;
     RECT  20.496 78.131 22.104 78.707 ;
     RECT  37.5 78.565 38.04 78.707 ;
     RECT  53.568 77.413 54.012 78.707 ;
     RECT  17.184 78.037 19.032 78.755 ;
     RECT  3.936 78.373 5.412 78.949 ;
     RECT  15.9 78.707 16.212 78.949 ;
     RECT  17.184 78.755 17.208 78.949 ;
     RECT  67.2 76.931 67.512 78.997 ;
     RECT  2.4 76.979 2.712 79.189 ;
     RECT  3.888 78.949 5.412 79.189 ;
     RECT  18.24 78.755 19.032 79.189 ;
     RECT  42.9 67.619 43.212 79.189 ;
     RECT  44.592 77.603 44.616 79.189 ;
     RECT  61.8 78.037 63 79.189 ;
     RECT  72.6 78.515 72.912 79.189 ;
     RECT  15.9 78.949 17.208 79.235 ;
     RECT  45.6 77.989 46.152 79.235 ;
     RECT  20.736 78.707 22.104 79.283 ;
     RECT  39.84 78.371 41.352 79.283 ;
     RECT  69.072 78.419 70.212 79.283 ;
     RECT  3.888 79.189 5.592 79.331 ;
     RECT  79.536 76.021 79.56 79.427 ;
     RECT  18.24 79.189 19.512 79.475 ;
     RECT  31.872 78.131 32.412 79.475 ;
     RECT  61.68 79.189 63 79.475 ;
     RECT  64.5 78.085 65.496 79.475 ;
     RECT  15.9 79.235 17.16 79.715 ;
     RECT  23.424 78.659 24.408 79.715 ;
     RECT  25.68 78.659 25.704 79.717 ;
     RECT  26.7 78.371 27.012 79.717 ;
     RECT  37.5 78.707 37.812 79.717 ;
     RECT  69.696 79.283 70.212 79.717 ;
     RECT  80.7 77.987 81.012 79.717 ;
     RECT  24 79.715 24.408 79.765 ;
     RECT  25.68 79.717 27.012 79.765 ;
     RECT  56.4 71.795 57.576 79.765 ;
     RECT  2.4 79.189 2.856 79.859 ;
     RECT  67.2 78.997 67.8 79.859 ;
     RECT  72.336 79.189 72.912 79.859 ;
     RECT  10.5 78.229 12.072 80.003 ;
     RECT  18.6 79.475 19.512 80.005 ;
     RECT  20.736 79.283 21.612 80.005 ;
     RECT  4.512 79.331 5.592 80.051 ;
     RECT  7.8 76.211 8.808 80.053 ;
     RECT  29.4 76.883 29.976 80.149 ;
     RECT  64.5 79.475 64.812 80.197 ;
     RECT  32.1 79.475 32.412 80.293 ;
     RECT  40.2 79.283 41.352 80.293 ;
     RECT  42.9 79.189 44.616 80.293 ;
     RECT  45.6 79.235 45.912 80.293 ;
     RECT  24 79.765 27.012 80.339 ;
     RECT  80.496 79.717 81.012 80.435 ;
     RECT  39.6 80.293 41.352 80.773 ;
     RECT  29.4 80.149 30.312 80.819 ;
     RECT  2.4 79.859 2.712 80.917 ;
     RECT  61.68 79.475 62.112 80.917 ;
     RECT  22.608 80.773 22.632 80.963 ;
     RECT  74.352 78.515 75.612 80.963 ;
     RECT  67.2 79.859 67.512 80.965 ;
     RECT  32.1 80.293 32.664 81.059 ;
     RECT  60.96 80.917 62.112 81.059 ;
     RECT  69.696 79.717 71.016 81.059 ;
     RECT  42.9 80.293 45.912 81.061 ;
     RECT  42.576 81.061 45.912 81.107 ;
     RECT  29.4 80.819 30.216 81.349 ;
     RECT  39.36 80.773 41.352 81.443 ;
     RECT  18.6 80.005 21.612 81.445 ;
     RECT  39.36 81.443 40.512 81.445 ;
     RECT  51 76.499 51.312 81.445 ;
     RECT  59.1 76.979 59.412 81.445 ;
     RECT  25.68 80.339 27.012 81.491 ;
     RECT  2.4 80.917 3.144 81.731 ;
     RECT  48.3 78.035 48.612 81.781 ;
     RECT  80.7 80.435 81.012 81.829 ;
     RECT  42.576 81.107 43.212 81.923 ;
     RECT  48.3 81.781 48.984 82.019 ;
     RECT  74.688 80.963 75.612 82.021 ;
     RECT  63.552 80.197 64.812 82.115 ;
     RECT  37.104 79.717 37.812 82.259 ;
     RECT  67.104 80.965 67.512 82.307 ;
     RECT  44.592 81.107 45.912 82.357 ;
     RECT  44.448 82.357 45.912 82.403 ;
     RECT  18.192 81.445 21.612 82.405 ;
     RECT  61.8 81.059 62.112 82.405 ;
     RECT  72.6 79.859 72.912 82.405 ;
     RECT  10.5 80.003 11.112 82.453 ;
     RECT  10.5 82.453 11.976 82.499 ;
     RECT  29.28 81.349 30.216 82.501 ;
     RECT  18.192 82.405 22.392 82.547 ;
     RECT  29.232 82.501 30.936 82.547 ;
     RECT  42.9 81.923 43.212 82.597 ;
     RECT  47.28 80.869 47.304 82.691 ;
     RECT  59.1 81.445 59.688 82.691 ;
     RECT  74.688 82.021 76.296 82.691 ;
     RECT  34.8 78.131 35.592 82.693 ;
     RECT  29.232 82.547 29.712 82.739 ;
     RECT  4.512 80.051 5.412 82.741 ;
     RECT  64.176 82.115 64.812 82.741 ;
     RECT  64.176 82.741 65.736 82.787 ;
     RECT  14.832 82.693 14.856 82.835 ;
     RECT  18.192 82.547 21.612 82.835 ;
     RECT  38.88 81.445 40.512 82.931 ;
     RECT  13.2 74.339 13.512 82.933 ;
     RECT  59.1 82.691 59.412 82.933 ;
     RECT  69.696 81.059 70.212 82.933 ;
     RECT  56.4 79.765 57.912 82.979 ;
     RECT  61.008 82.405 62.112 82.979 ;
     RECT  74.688 82.691 75.864 82.979 ;
     RECT  18.192 82.835 19.368 83.027 ;
     RECT  18.192 83.027 18.912 83.077 ;
     RECT  24 80.339 24.408 83.077 ;
     RECT  67.2 82.307 67.512 83.077 ;
     RECT  68.976 82.933 70.212 83.077 ;
     RECT  67.2 83.077 70.212 83.123 ;
     RECT  26.7 81.491 27.012 83.173 ;
     RECT  57.888 82.979 57.912 83.219 ;
     RECT  20.544 82.835 21.612 83.267 ;
     RECT  23.616 83.077 24.408 83.267 ;
     RECT  30.912 82.547 30.936 83.267 ;
     RECT  4.512 82.741 5.688 83.317 ;
     RECT  61.536 82.979 62.112 83.363 ;
     RECT  64.5 82.787 65.736 83.459 ;
     RECT  4.512 83.317 5.736 83.653 ;
     RECT  48.3 82.019 48.744 83.701 ;
     RECT  11.952 82.499 11.976 83.749 ;
     RECT  17.76 83.077 18.912 83.843 ;
     RECT  48.3 83.701 49.032 83.843 ;
     RECT  42.9 82.597 43.32 83.939 ;
     RECT  67.2 83.123 68.376 83.939 ;
     RECT  48.3 83.843 48.744 84.083 ;
     RECT  26.7 83.173 27.336 84.275 ;
     RECT  7.8 80.053 9.096 84.325 ;
     RECT  23.616 83.267 24.312 84.419 ;
     RECT  11.952 83.749 12.12 84.563 ;
     RECT  23.904 84.419 24.312 84.661 ;
     RECT  25.68 81.491 25.704 84.661 ;
     RECT  72.336 82.405 72.912 84.757 ;
     RECT  75.3 82.979 75.864 84.803 ;
     RECT  29.28 82.739 29.712 84.805 ;
     RECT  13.2 82.933 13.608 84.851 ;
     RECT  4.512 83.653 6.264 84.899 ;
     RECT  34.8 82.693 35.736 84.901 ;
     RECT  37.5 82.259 37.812 84.901 ;
     RECT  53.7 78.707 54.012 84.901 ;
     RECT  69.696 83.123 70.212 84.901 ;
     RECT  13.2 84.851 13.512 84.949 ;
     RECT  15.9 79.715 16.212 85.093 ;
     RECT  18.096 83.843 18.912 85.139 ;
     RECT  44.448 82.403 44.616 85.139 ;
     RECT  7.392 84.325 9.096 85.187 ;
     RECT  39.6 82.931 40.512 85.381 ;
     RECT  42.9 83.939 43.212 85.381 ;
     RECT  23.904 84.661 25.704 85.429 ;
     RECT  56.4 82.979 56.712 85.669 ;
     RECT  72.336 84.757 73.512 85.715 ;
     RECT  53.7 84.901 54.12 85.955 ;
     RECT  69.696 84.901 70.584 85.955 ;
     RECT  61.8 83.363 62.112 85.957 ;
     RECT  72.336 85.715 72.912 85.957 ;
     RECT  5.1 84.899 5.688 86.005 ;
     RECT  48.3 84.083 48.612 86.005 ;
     RECT  69.696 85.955 70.212 86.005 ;
     RECT  42.72 85.381 43.212 86.053 ;
     RECT  7.8 85.187 9.096 86.099 ;
     RECT  23.616 85.429 25.704 86.243 ;
     RECT  50.688 81.445 51.312 86.293 ;
     RECT  58.944 82.933 59.412 86.341 ;
     RECT  13.104 84.949 13.512 86.435 ;
     RECT  41.616 84.325 41.64 86.483 ;
     RECT  79.776 81.829 81.012 86.485 ;
     RECT  79.776 86.485 81.624 86.581 ;
     RECT  79.44 86.581 81.624 86.627 ;
     RECT  45.6 82.403 45.912 86.629 ;
     RECT  15.9 85.093 16.536 86.675 ;
     RECT  47.376 86.005 48.984 86.675 ;
     RECT  39.12 85.381 40.512 86.773 ;
     RECT  42.72 86.053 43.32 86.819 ;
     RECT  34.8 84.901 37.812 87.059 ;
     RECT  34.8 87.059 35.352 87.155 ;
     RECT  11.952 84.563 11.976 87.157 ;
     RECT  58.944 86.341 59.688 87.203 ;
     RECT  60.96 85.957 62.112 87.203 ;
     RECT  25.68 86.243 25.704 87.251 ;
     RECT  28.32 84.805 29.712 87.251 ;
     RECT  57.84 86.341 57.864 87.251 ;
     RECT  36.576 87.059 37.812 87.299 ;
     RECT  28.32 87.251 28.344 87.347 ;
     RECT  18.6 85.139 18.912 87.397 ;
     RECT  23.616 86.243 24.312 87.397 ;
     RECT  56.16 85.669 56.712 87.397 ;
     RECT  80.592 86.627 81.624 87.587 ;
     RECT  3.936 87.541 3.96 87.683 ;
     RECT  10.5 82.499 10.812 87.685 ;
     RECT  20.736 83.267 21.612 87.685 ;
     RECT  50.688 86.293 52.296 87.781 ;
     RECT  11.952 87.157 12.024 87.827 ;
     RECT  34.8 87.155 35.208 87.827 ;
     RECT  80.592 87.587 81.012 87.827 ;
     RECT  45.6 86.629 46.008 87.829 ;
     RECT  15.9 86.675 16.212 87.877 ;
     RECT  20.736 87.685 22.104 87.925 ;
     RECT  23.376 87.397 24.312 87.925 ;
     RECT  45.6 87.829 46.2 87.971 ;
     RECT  13.2 86.435 13.512 88.021 ;
     RECT  20.736 87.925 24.312 88.067 ;
     RECT  22.8 88.067 24.312 88.163 ;
     RECT  68.976 86.005 70.212 88.307 ;
     RECT  10.176 87.685 10.812 88.355 ;
     RECT  50.544 87.781 52.296 88.357 ;
     RECT  56.112 87.397 56.712 88.403 ;
     RECT  53.7 85.955 54.012 88.405 ;
     RECT  58.944 87.203 59.544 88.405 ;
     RECT  61.8 87.203 62.112 88.405 ;
     RECT  44.592 85.139 44.616 88.451 ;
     RECT  13.2 88.021 13.752 88.453 ;
     RECT  50.208 88.357 52.296 88.643 ;
     RECT  50.208 88.643 51.312 88.691 ;
     RECT  37.5 87.299 37.812 88.693 ;
     RECT  38.976 86.773 40.512 88.693 ;
     RECT  58.704 88.405 59.544 88.739 ;
     RECT  60.864 88.405 62.112 88.739 ;
     RECT  5.1 86.005 5.736 88.789 ;
     RECT  13.104 88.453 13.752 88.883 ;
     RECT  26.7 84.275 27.012 88.885 ;
     RECT  47.376 86.675 48.612 88.885 ;
     RECT  53.7 88.405 54.312 88.885 ;
     RECT  15.9 87.877 16.344 88.931 ;
     RECT  71.808 85.957 72.912 88.931 ;
     RECT  50.544 88.691 51.312 88.979 ;
     RECT  79.44 86.627 79.464 88.979 ;
     RECT  18.6 87.397 19.56 89.075 ;
     RECT  12 87.827 12.024 89.171 ;
     RECT  13.2 88.883 13.752 89.171 ;
     RECT  20.736 88.067 21.612 89.267 ;
     RECT  42.9 86.819 43.32 89.269 ;
     RECT  64.5 83.459 64.812 89.269 ;
     RECT  37.5 88.693 40.512 89.315 ;
     RECT  42.768 89.269 43.32 89.315 ;
     RECT  7.8 86.099 8.904 89.459 ;
     RECT  23.376 88.163 24.312 89.461 ;
     RECT  59.1 88.739 59.544 89.461 ;
     RECT  61.68 88.739 62.112 89.555 ;
     RECT  23.376 89.461 25.032 89.747 ;
     RECT  5.1 88.789 5.832 89.843 ;
     RECT  47.376 88.885 49.032 90.035 ;
     RECT  37.5 89.315 38.76 90.083 ;
     RECT  48.3 90.035 49.032 90.083 ;
     RECT  64.5 89.269 65.016 90.083 ;
     RECT  76.944 88.309 76.968 90.083 ;
     RECT  21.168 89.267 21.612 90.131 ;
     RECT  33.744 87.829 33.768 90.275 ;
     RECT  45.6 87.971 46.008 90.275 ;
     RECT  53.7 88.885 54.744 90.323 ;
     RECT  24 89.747 25.032 90.371 ;
     RECT  26.7 88.885 27.96 90.515 ;
     RECT  59.1 89.461 59.736 90.515 ;
     RECT  42.768 89.315 43.212 90.563 ;
     RECT  2.4 81.731 2.712 90.729 ;
     RECT  5.1 89.843 5.412 90.729 ;
     RECT  7.8 89.459 8.112 90.729 ;
     RECT  10.5 88.355 10.812 90.729 ;
     RECT  13.2 89.171 13.512 90.729 ;
     RECT  15.9 88.931 16.212 90.729 ;
     RECT  18.6 89.075 18.912 90.729 ;
     RECT  21.3 90.131 21.612 90.729 ;
     RECT  24 90.371 24.312 90.729 ;
     RECT  26.7 90.515 27.012 90.729 ;
     RECT  29.4 87.251 29.712 90.729 ;
     RECT  32.1 81.059 32.412 90.729 ;
     RECT  34.8 87.827 35.112 90.729 ;
     RECT  37.5 90.083 37.812 90.729 ;
     RECT  40.2 89.315 40.512 90.729 ;
     RECT  42.9 90.563 43.212 90.729 ;
     RECT  45.6 90.275 45.912 90.729 ;
     RECT  48.3 90.083 48.612 90.729 ;
     RECT  51 88.979 51.312 90.729 ;
     RECT  53.7 90.323 54.012 90.729 ;
     RECT  56.4 88.403 56.712 90.729 ;
     RECT  59.1 90.515 59.412 90.729 ;
     RECT  61.8 89.555 62.112 90.729 ;
     RECT  64.5 90.083 64.812 90.729 ;
     RECT  67.2 83.939 67.512 90.729 ;
     RECT  69.9 88.307 70.212 90.729 ;
     RECT  72.6 88.931 72.912 90.729 ;
     RECT  75.3 84.803 75.612 90.729 ;
     RECT  78 76.355 78.312 90.729 ;
     RECT  80.7 87.827 81.012 90.729 ;
     RECT  83.4 2.151 83.712 90.729 ;
     RECT  2.4 90.729 2.52 90.743 ;
     RECT  5.1 90.729 5.22 90.743 ;
     RECT  7.8 90.729 7.92 90.743 ;
     RECT  10.5 90.729 10.62 90.743 ;
     RECT  13.2 90.729 13.32 90.743 ;
     RECT  15.9 90.729 16.02 90.743 ;
     RECT  18.6 90.729 18.72 90.743 ;
     RECT  21.3 90.729 21.42 90.743 ;
     RECT  24 90.729 24.12 90.743 ;
     RECT  26.7 90.729 26.82 90.743 ;
     RECT  29.4 90.729 29.52 90.743 ;
     RECT  32.1 90.729 32.22 90.743 ;
     RECT  34.8 90.729 34.92 90.743 ;
     RECT  37.5 90.729 37.62 90.743 ;
     RECT  40.2 90.729 40.32 90.743 ;
     RECT  42.9 90.729 43.02 90.743 ;
     RECT  45.6 90.729 45.72 90.743 ;
     RECT  48.3 90.729 48.42 90.743 ;
     RECT  51 90.729 51.12 90.743 ;
     RECT  53.7 90.729 53.82 90.743 ;
     RECT  56.4 90.729 56.52 90.743 ;
     RECT  59.1 90.729 59.22 90.743 ;
     RECT  61.8 90.729 61.92 90.743 ;
     RECT  64.5 90.729 64.62 90.743 ;
     RECT  67.2 90.729 67.32 90.743 ;
     RECT  69.9 90.729 70.02 90.743 ;
     RECT  72.6 90.729 72.72 90.743 ;
     RECT  75.3 90.729 75.42 90.743 ;
     RECT  78 90.729 78.12 90.743 ;
     RECT  80.7 90.729 80.82 90.743 ;
     RECT  83.4 90.729 83.52 90.743 ;
     RECT  16.02 2.137 17.376 2.151 ;
     RECT  17.4 2.137 18.6 2.821 ;
     RECT  16.212 2.151 17.376 5.797 ;
     RECT  21.612 2.293 23.136 3.301 ;
     RECT  27.96 2.581 29.4 4.501 ;
     RECT  70.44 2.581 71.76 2.915 ;
     RECT  41.4 3.205 42.9 4.403 ;
     RECT  21.612 3.301 22.8 3.925 ;
     RECT  22.824 3.347 24 4.019 ;
     RECT  32.412 3.397 33.744 5.699 ;
     RECT  33.768 3.397 34.8 5.699 ;
     RECT  67.512 3.397 68.976 3.971 ;
     RECT  21.612 3.925 22.704 6.517 ;
     RECT  57.624 3.925 59.1 5.699 ;
     RECT  56.304 3.971 56.4 4.501 ;
     RECT  22.728 4.019 24 6.709 ;
     RECT  31.968 4.115 32.1 5.605 ;
     RECT  52.248 4.117 53.7 4.691 ;
     RECT  17.4 4.259 18.6 10.501 ;
     RECT  8.112 4.405 9.6 6.085 ;
     RECT  54.012 4.451 54.744 4.501 ;
     RECT  18.912 4.501 20.256 5.125 ;
     RECT  27.96 4.501 28.992 4.547 ;
     RECT  54.012 4.501 55.152 6.851 ;
     RECT  55.176 4.501 56.4 6.805 ;
     RECT  52.992 4.691 53.7 5.653 ;
     RECT  78.312 4.931 78.408 6.037 ;
     RECT  38.664 4.933 39.984 6.803 ;
     RECT  5.412 4.981 6.864 10.453 ;
     RECT  18.912 5.125 19.92 5.987 ;
     RECT  13.512 5.173 14.88 5.653 ;
     RECT  14.904 5.173 15.9 6.805 ;
     RECT  11.208 5.653 12.528 5.795 ;
     RECT  13.512 5.653 14.64 7.187 ;
     RECT  32.412 5.699 33.192 6.133 ;
     RECT  56.712 5.699 59.1 6.661 ;
     RECT  24.312 5.795 24.408 6.805 ;
     RECT  16.344 5.797 17.376 7.141 ;
     RECT  59.412 5.797 60.768 5.845 ;
     RECT  60.792 5.797 61.8 6.901 ;
     RECT  59.736 5.845 60.768 5.987 ;
     RECT  18.912 5.987 20.256 6.131 ;
     RECT  59.412 5.987 60.768 7.381 ;
     RECT  78.312 6.037 79.584 6.229 ;
     RECT  79.608 6.037 80.7 10.931 ;
     RECT  8.232 6.085 9.6 7.139 ;
     RECT  18.912 6.131 20.496 6.805 ;
     RECT  78.312 6.229 79.536 6.277 ;
     RECT  78.408 6.277 79.536 6.899 ;
     RECT  45.168 6.515 45.6 7.909 ;
     RECT  70.212 6.565 71.376 6.851 ;
     RECT  56.712 6.661 57.984 8.003 ;
     RECT  58.008 6.661 59.1 8.003 ;
     RECT  38.664 6.803 40.2 7.957 ;
     RECT  19.176 6.805 20.496 7.237 ;
     RECT  31.968 6.851 32.1 8.149 ;
     RECT  54.012 6.851 54.12 8.101 ;
     RECT  70.212 6.851 71.808 7.909 ;
     RECT  78.312 6.899 79.584 10.931 ;
     RECT  26.544 7.043 26.7 7.861 ;
     RECT  21.612 7.091 22.704 7.475 ;
     RECT  13.512 7.187 14.88 8.725 ;
     RECT  19.176 7.237 20.4 8.003 ;
     RECT  59.412 7.381 60.432 8.531 ;
     RECT  14.904 7.475 15.9 9.011 ;
     RECT  40.632 7.573 42.144 7.859 ;
     RECT  25.128 7.861 26.7 8.101 ;
     RECT  70.344 7.909 71.808 9.011 ;
     RECT  38.664 7.957 39.888 9.971 ;
     RECT  62.112 7.957 63.456 9.203 ;
     RECT  63.48 7.957 64.5 9.203 ;
     RECT  25.608 8.101 26.7 8.675 ;
     RECT  24.552 8.147 25.584 8.675 ;
     RECT  30.024 8.437 31.392 12.563 ;
     RECT  59.412 8.531 60.96 8.965 ;
     RECT  13.608 8.725 14.88 9.011 ;
     RECT  13.104 8.771 13.2 10.069 ;
     RECT  59.544 8.965 60.96 9.731 ;
     RECT  15.6 9.011 15.9 9.061 ;
     RECT  64.812 9.109 66.288 10.307 ;
     RECT  62.112 9.203 62.232 9.637 ;
     RECT  9 9.205 10.5 10.595 ;
     RECT  44.976 9.299 45.6 9.637 ;
     RECT  67.512 9.541 68.976 10.835 ;
     RECT  18.912 9.637 20.064 11.363 ;
     RECT  43.212 9.637 44.448 10.595 ;
     RECT  44.472 9.637 45.6 10.549 ;
     RECT  48.612 9.637 49.824 11.987 ;
     RECT  42.288 9.827 42.9 10.213 ;
     RECT  38.664 9.971 40.2 11.269 ;
     RECT  13.512 10.115 13.608 10.693 ;
     RECT  60.96 10.115 61.8 11.365 ;
     RECT  32.412 10.165 33.696 11.939 ;
     RECT  33.72 10.165 34.8 11.939 ;
     RECT  41.496 10.213 42.9 10.883 ;
     RECT  27.912 10.261 29.4 12.515 ;
     RECT  5.688 10.453 6.864 10.883 ;
     RECT  43.212 10.595 44.736 12.179 ;
     RECT  2.904 10.597 4.176 10.883 ;
     RECT  24.552 10.597 26.064 11.699 ;
     RECT  13.512 10.693 14.928 12.517 ;
     RECT  2.712 10.883 4.176 13.669 ;
     RECT  40.512 10.883 40.968 12.037 ;
     RECT  38.76 11.269 40.2 13.091 ;
     RECT  59.412 11.365 60.48 12.179 ;
     RECT  60.504 11.365 61.8 12.179 ;
     RECT  72.48 11.555 72.6 13.045 ;
     RECT  75.612 11.555 75.72 12.997 ;
     RECT  24.552 11.699 25.08 13.045 ;
     RECT  17.4 11.747 18.6 13.621 ;
     RECT  64.812 11.941 66 12.995 ;
     RECT  66.024 11.941 67.2 12.995 ;
     RECT  73.416 11.941 74.832 12.037 ;
     RECT  11.784 11.989 13.104 12.035 ;
     RECT  11.784 12.035 13.2 14.675 ;
     RECT  73.848 12.037 74.832 12.227 ;
     RECT  61.44 12.179 61.8 13.621 ;
     RECT  73.416 12.227 74.832 13.139 ;
     RECT  14.088 12.563 15.408 12.803 ;
     RECT  70.212 13.045 71.52 13.811 ;
     RECT  71.544 13.045 72.6 13.811 ;
     RECT  22.536 13.573 24 14.101 ;
     RECT  25.08 13.621 26.064 13.859 ;
     RECT  2.712 13.669 3.936 13.907 ;
     RECT  22.536 14.101 23.856 15.155 ;
     RECT  27.012 14.197 28.32 17.555 ;
     RECT  28.344 14.197 29.4 16.501 ;
     RECT  56.712 14.245 58.128 15.109 ;
     RECT  14.088 14.533 15.456 16.595 ;
     RECT  48.612 14.533 49.824 16.019 ;
     RECT  49.848 14.533 50.88 15.059 ;
     RECT  17.4 14.627 18.48 16.835 ;
     RECT  10.812 14.675 13.2 14.773 ;
     RECT  10.812 14.773 11.808 16.643 ;
     RECT  11.832 14.773 13.2 16.405 ;
     RECT  73.32 14.773 74.64 15.349 ;
     RECT  49.848 15.059 51 16.019 ;
     RECT  56.904 15.109 58.128 15.299 ;
     RECT  22.536 15.155 24 15.491 ;
     RECT  56.904 15.299 58.176 18.997 ;
     RECT  77.016 15.445 78 17.171 ;
     RECT  21.72 15.491 24 15.829 ;
     RECT  6.792 15.685 7.8 17.699 ;
     RECT  21.72 15.829 22.704 17.699 ;
     RECT  22.728 15.829 24 17.699 ;
     RECT  67.608 15.877 69.12 15.973 ;
     RECT  67.608 15.973 68.976 16.019 ;
     RECT  78.312 15.973 79.584 16.453 ;
     RECT  61.68 16.019 61.8 17.365 ;
     RECT  67.512 16.019 68.976 17.123 ;
     RECT  18.912 16.069 20.112 16.307 ;
     RECT  40.512 16.213 41.808 16.837 ;
     RECT  41.832 16.213 42.9 17.363 ;
     RECT  18.912 16.307 20.736 16.741 ;
     RECT  11.832 16.405 13.104 16.597 ;
     RECT  78.408 16.453 79.584 16.595 ;
     RECT  5.412 16.547 6.672 17.987 ;
     RECT  11.928 16.597 13.104 18.179 ;
     RECT  10.812 16.643 11.904 19.859 ;
     RECT  75.612 16.691 76.656 18.803 ;
     RECT  19.56 16.741 20.736 16.835 ;
     RECT  73.32 16.787 74.688 18.035 ;
     RECT  17.4 16.835 18.6 20.341 ;
     RECT  19.56 16.835 20.832 16.883 ;
     RECT  19.56 16.883 20.928 17.171 ;
     RECT  1.272 17.077 2.4 17.219 ;
     RECT  67.512 17.123 69.12 18.565 ;
     RECT  76.68 17.171 78 18.803 ;
     RECT  41.448 17.363 42.9 20.485 ;
     RECT  27.012 17.555 28.752 17.941 ;
     RECT  8.112 17.651 8.232 18.709 ;
     RECT  6.696 17.699 7.8 17.987 ;
     RECT  27.528 17.941 28.752 23.987 ;
     RECT  5.412 17.987 5.544 18.181 ;
     RECT  35.112 18.133 36.288 19.427 ;
     RECT  11.928 18.179 13.2 19.813 ;
     RECT  24.504 18.181 25.968 19.235 ;
     RECT  32.412 18.229 33.552 23.317 ;
     RECT  33.576 18.229 34.8 23.987 ;
     RECT  67.512 18.565 69.024 20.003 ;
     RECT  8.52 18.757 9.984 19.619 ;
     RECT  36.312 18.803 37.392 19.427 ;
     RECT  75.612 18.803 75.96 19.093 ;
     RECT  56.952 18.997 58.176 19.331 ;
     RECT  56.904 19.331 58.176 22.883 ;
     RECT  43.32 19.333 44.784 20.435 ;
     RECT  8.52 19.619 10.5 20.869 ;
     RECT  78.312 19.765 79.824 22.787 ;
     RECT  11.928 19.813 12.912 19.859 ;
     RECT  12.624 19.859 12.912 21.205 ;
     RECT  75.612 20.051 75.96 20.437 ;
     RECT  75.612 20.437 76.944 22.979 ;
     RECT  76.968 20.437 78 22.979 ;
     RECT  41.448 20.485 42.768 21.203 ;
     RECT  61.248 20.579 61.8 21.925 ;
     RECT  17.4 20.723 18.6 23.893 ;
     RECT  9.096 20.869 10.5 22.165 ;
     RECT  41.448 21.203 42.9 21.971 ;
     RECT  14.088 21.301 15.6 21.781 ;
     RECT  14.088 21.781 15.552 22.259 ;
     RECT  59.412 21.925 60.432 23.363 ;
     RECT  60.456 21.925 61.8 23.363 ;
     RECT  42.768 21.971 42.9 22.741 ;
     RECT  9.096 22.165 10.368 23.315 ;
     RECT  29.88 22.499 30.408 23.507 ;
     RECT  10.812 22.597 12.24 23.411 ;
     RECT  38.76 22.693 40.08 22.979 ;
     RECT  54.012 22.693 55.296 23.555 ;
     RECT  55.32 22.739 56.4 23.555 ;
     RECT  36.072 22.741 37.392 23.555 ;
     RECT  9.096 23.315 10.5 29.029 ;
     RECT  51.312 23.317 52.416 26.771 ;
     RECT  52.44 23.317 53.7 24.709 ;
     RECT  29.832 23.507 30.408 23.893 ;
     RECT  35.112 23.555 35.352 25.045 ;
     RECT  37.056 23.555 37.392 24.805 ;
     RECT  55.824 23.555 56.4 24.469 ;
     RECT  29.832 23.893 31.248 25.235 ;
     RECT  73.464 23.893 74.832 23.989 ;
     RECT  64.812 23.987 64.968 25.045 ;
     RECT  73.464 23.989 74.736 24.707 ;
     RECT  40.08 24.131 40.2 25.189 ;
     RECT  52.44 24.709 53.568 26.677 ;
     RECT  65.736 25.045 67.2 25.715 ;
     RECT  21.612 25.139 21.72 26.101 ;
     RECT  29.712 25.235 31.248 25.333 ;
     RECT  29.712 25.333 30.864 26.627 ;
     RECT  75.612 25.333 76.896 26.245 ;
     RECT  76.92 25.333 78 27.971 ;
     RECT  64.812 25.715 64.92 26.773 ;
     RECT  43.212 26.243 43.896 27.685 ;
     RECT  18.912 26.245 19.968 27.589 ;
     RECT  54.012 26.245 55.104 26.435 ;
     RECT  75.864 26.245 76.896 26.627 ;
     RECT  24.456 26.435 25.032 27.107 ;
     RECT  54.012 26.435 55.824 27.589 ;
     RECT  21.612 26.531 21.72 27.301 ;
     RECT  75.768 26.627 76.896 27.971 ;
     RECT  52.44 26.677 53.52 26.771 ;
     RECT  33.288 26.725 34.8 28.403 ;
     RECT  31.68 26.819 32.1 27.877 ;
     RECT  24.312 27.107 25.032 27.925 ;
     RECT  5.928 27.253 6.912 29.317 ;
     RECT  21.612 27.301 22.944 28.885 ;
     RECT  22.968 27.301 24 30.323 ;
     RECT  41.88 27.301 42.9 30.323 ;
     RECT  57.624 27.301 58.8 28.547 ;
     RECT  70.212 27.301 71.184 28.453 ;
     RECT  71.208 27.301 72.336 28.499 ;
     RECT  16.344 27.347 17.376 30.805 ;
     RECT  37.812 27.445 39.264 28.691 ;
     RECT  40.512 27.491 41.856 30.323 ;
     RECT  54.012 27.589 55.2 29.699 ;
     RECT  43.212 27.685 44.448 27.923 ;
     RECT  44.472 27.685 45.6 27.877 ;
     RECT  14.52 27.781 15.9 29.507 ;
     RECT  24.312 27.925 25.68 28.501 ;
     RECT  25.704 27.925 26.7 29.651 ;
     RECT  34.032 28.403 34.8 28.981 ;
     RECT  70.776 28.499 72.336 29.989 ;
     RECT  24.408 28.501 25.68 29.651 ;
     RECT  55.272 28.979 56.4 30.611 ;
     RECT  9.096 29.029 10.08 29.363 ;
     RECT  10.812 29.029 11.808 29.747 ;
     RECT  13.704 29.507 15.9 30.757 ;
     RECT  25.968 29.651 26.7 30.037 ;
     RECT  54.012 29.699 55.248 30.133 ;
     RECT  10.272 29.795 10.5 30.757 ;
     RECT  46.776 29.893 48.3 31.955 ;
     RECT  70.776 29.989 72.144 31.957 ;
     RECT  25.968 30.037 26.208 31.141 ;
     RECT  49.56 30.133 51 32.483 ;
     RECT  54.12 30.133 55.248 30.611 ;
     RECT  35.112 30.275 35.256 30.277 ;
     RECT  32.412 30.277 33.648 30.851 ;
     RECT  35.112 30.277 36.192 30.803 ;
     RECT  36.216 30.277 37.2 30.803 ;
     RECT  22.056 30.323 24 31.333 ;
     RECT  33.672 30.323 34.8 30.851 ;
     RECT  42.144 30.323 42.9 31.141 ;
     RECT  54.12 30.611 54.696 31.765 ;
     RECT  38.328 30.709 39.312 30.997 ;
     RECT  13.704 30.757 14.784 30.997 ;
     RECT  14.808 30.757 15.9 31.043 ;
     RECT  57.48 30.757 58.704 32.531 ;
     RECT  27.012 30.803 28.704 31.861 ;
     RECT  35.112 30.803 35.208 31.381 ;
     RECT  5.412 30.851 6.864 33.013 ;
     RECT  32.412 30.851 34.8 31.813 ;
     RECT  38.904 31.043 40.2 32.243 ;
     RECT  20.04 31.091 21.3 33.011 ;
     RECT  22.056 31.333 23.232 31.955 ;
     RECT  32.412 31.813 33.6 32.483 ;
     RECT  33.624 31.813 34.8 32.483 ;
     RECT  27.72 31.861 28.704 37.573 ;
     RECT  75.768 31.861 77.136 32.051 ;
     RECT  22.056 31.955 24 32.485 ;
     RECT  47.904 31.955 48.3 33.013 ;
     RECT  24.504 32.005 25.968 32.243 ;
     RECT  72.912 32.005 74.112 33.107 ;
     RECT  75.612 32.051 77.136 33.443 ;
     RECT  29.712 32.149 30.72 34.165 ;
     RECT  30.744 32.149 32.1 34.355 ;
     RECT  70.212 32.243 71.28 32.291 ;
     RECT  16.212 32.291 17.376 43.093 ;
     RECT  8.112 32.483 8.52 33.829 ;
     RECT  34.656 32.483 34.8 32.581 ;
     RECT  22.152 32.485 24 33.013 ;
     RECT  42.144 32.723 42.9 33.973 ;
     RECT  19.752 33.011 21.3 34.165 ;
     RECT  10.812 33.013 12.096 34.595 ;
     RECT  12.12 33.013 13.2 34.595 ;
     RECT  22.824 33.013 24 33.397 ;
     RECT  59.412 33.013 60.384 34.595 ;
     RECT  60.408 33.013 61.8 34.595 ;
     RECT  72.144 33.155 72.288 34.117 ;
     RECT  22.152 33.443 23.136 34.211 ;
     RECT  55.32 33.589 56.4 36.035 ;
     RECT  8.76 33.829 10.176 33.875 ;
     RECT  46.824 33.877 47.904 34.211 ;
     RECT  40.512 33.973 41.904 34.069 ;
     RECT  41.928 33.973 42.9 34.931 ;
     RECT  70.824 34.117 72.288 34.835 ;
     RECT  20.04 34.165 21.3 34.835 ;
     RECT  52.296 34.165 53.568 35.699 ;
     RECT  22.152 34.211 24 35.605 ;
     RECT  40.512 34.211 41.904 34.931 ;
     RECT  46.824 34.211 48.3 34.931 ;
     RECT  78.312 34.211 78.408 34.501 ;
     RECT  8.112 34.355 8.76 35.845 ;
     RECT  35.256 34.405 36.384 34.547 ;
     RECT  78.312 34.501 79.824 35.027 ;
     RECT  35.112 34.547 36.384 36.517 ;
     RECT  10.812 34.595 11.304 34.741 ;
     RECT  59.412 34.595 60.216 35.845 ;
     RECT  54.12 34.835 55.296 36.035 ;
     RECT  50.832 34.883 51 36.277 ;
     RECT  45.912 34.931 46.728 35.989 ;
     RECT  22.776 35.605 24 36.659 ;
     RECT  5.412 35.939 6.864 36.131 ;
     RECT  19.416 36.515 19.752 36.517 ;
     RECT  19.416 36.517 21.168 36.853 ;
     RECT  35.208 36.517 36.384 37.429 ;
     RECT  19.416 36.853 20.688 38.147 ;
     RECT  24.312 36.997 25.392 38.147 ;
     RECT  25.416 36.997 26.7 38.147 ;
     RECT  41.352 36.997 42.768 37.907 ;
     RECT  36.504 37.091 37.5 37.667 ;
     RECT  68.328 37.429 69.792 38.723 ;
     RECT  46.728 37.573 48.192 37.619 ;
     RECT  46.488 37.619 48.192 38.243 ;
     RECT  36.024 37.667 37.5 43.043 ;
     RECT  5.784 37.669 7.056 40.355 ;
     RECT  19.32 38.147 20.688 38.531 ;
     RECT  24.312 38.147 26.7 38.437 ;
     RECT  45.912 38.243 48.192 38.675 ;
     RECT  22.152 38.341 23.328 41.893 ;
     RECT  25.08 38.437 26.7 38.579 ;
     RECT  26.208 38.579 26.7 39.157 ;
     RECT  45.912 38.675 48.3 38.677 ;
     RECT  45.912 38.677 46.992 40.307 ;
     RECT  47.016 38.677 48.3 40.307 ;
     RECT  59.412 38.915 59.832 40.261 ;
     RECT  11.304 39.061 12.336 39.923 ;
     RECT  65.448 39.493 66.624 40.259 ;
     RECT  62.112 39.829 63.264 40.787 ;
     RECT  63.288 39.829 64.5 40.787 ;
     RECT  10.368 40.019 10.5 41.509 ;
     RECT  59.412 40.261 60.72 40.403 ;
     RECT  24.312 40.309 25.632 41.747 ;
     RECT  41.496 40.309 42.9 40.693 ;
     RECT  7.008 40.355 7.056 41.797 ;
     RECT  13.104 40.403 13.2 41.557 ;
     RECT  25.656 40.691 26.7 41.747 ;
     RECT  54.012 41.221 55.344 42.709 ;
     RECT  11.304 41.557 12.528 42.467 ;
     RECT  55.368 41.651 56.4 42.661 ;
     RECT  51.96 41.893 53.04 41.939 ;
     RECT  21.168 41.939 21.3 43.141 ;
     RECT  5.412 42.085 6.624 43.043 ;
     RECT  37.812 42.613 38.928 42.997 ;
     RECT  38.952 42.613 40.2 43.379 ;
     RECT  57.576 42.659 59.1 43.379 ;
     RECT  54.12 42.709 55.344 42.803 ;
     RECT  18.912 42.755 19.416 43.141 ;
     RECT  22.968 42.755 24 44.387 ;
     RECT  75.12 42.755 75.3 44.101 ;
     RECT  27.012 42.757 28.416 43.379 ;
     RECT  37.812 42.997 38.784 44.483 ;
     RECT  5.412 43.043 7.152 43.621 ;
     RECT  40.512 43.043 41.016 44.101 ;
     RECT  18.912 43.141 20.016 44.293 ;
     RECT  20.04 43.141 21.3 44.339 ;
     RECT  27.012 43.379 29.4 43.909 ;
     RECT  38.808 43.379 40.2 44.483 ;
     RECT  5.736 43.621 7.152 44.579 ;
     RECT  8.112 43.861 9.6 46.163 ;
     RECT  2.712 43.909 3.936 44.099 ;
     RECT  3.96 43.909 5.1 44.099 ;
     RECT  27.012 43.909 28.128 44.483 ;
     RECT  28.152 43.909 29.4 44.483 ;
     RECT  43.8 43.909 44.928 45.347 ;
     RECT  4.992 44.099 5.1 45.157 ;
     RECT  40.776 44.101 41.016 44.197 ;
     RECT  19.848 44.339 21.3 45.059 ;
     RECT  22.824 44.387 24 45.491 ;
     RECT  37.812 44.483 40.2 44.533 ;
     RECT  38.76 44.533 40.2 46.259 ;
     RECT  66.624 44.723 66.72 45.541 ;
     RECT  62.112 44.917 63.312 46.211 ;
     RECT  63.336 44.917 64.5 46.211 ;
     RECT  70.212 44.917 71.328 46.259 ;
     RECT  71.352 44.917 72.432 45.011 ;
     RECT  71.352 45.011 72.6 46.259 ;
     RECT  21.168 45.059 21.3 45.541 ;
     RECT  78.312 45.253 79.68 45.875 ;
     RECT  79.704 45.299 80.7 45.875 ;
     RECT  43.608 45.347 44.928 46.211 ;
     RECT  65.352 45.541 66.72 45.587 ;
     RECT  50.88 45.731 51 47.077 ;
     RECT  57.624 46.069 59.1 48.085 ;
     RECT  61.584 46.163 61.8 47.269 ;
     RECT  43.212 46.211 44.928 46.549 ;
     RECT  16.212 46.259 17.376 47.365 ;
     RECT  24.312 46.259 24.408 47.269 ;
     RECT  39.84 46.259 40.2 47.029 ;
     RECT  72.336 46.259 72.6 46.597 ;
     RECT  29.712 46.307 30.312 47.749 ;
     RECT  43.212 46.549 44.592 52.021 ;
     RECT  10.812 46.787 11.016 47.845 ;
     RECT  48.612 47.077 50.112 47.845 ;
     RECT  25.128 47.269 26.448 47.747 ;
     RECT  25.128 47.747 26.592 50.291 ;
     RECT  29.712 47.749 30.768 48.949 ;
     RECT  30.792 47.749 32.1 48.805 ;
     RECT  70.212 47.797 71.232 48.805 ;
     RECT  71.256 47.797 72.336 47.987 ;
     RECT  22.968 47.845 24 50.147 ;
     RECT  48.612 47.845 49.824 52.405 ;
     RECT  71.256 47.987 72.6 49.043 ;
     RECT  57.912 48.085 59.1 48.659 ;
     RECT  56.856 48.131 57.888 48.227 ;
     RECT  56.712 48.227 57.888 48.659 ;
     RECT  16.344 48.371 17.616 48.947 ;
     RECT  66.12 48.421 67.2 49.187 ;
     RECT  20.544 48.467 21.3 48.949 ;
     RECT  64.812 48.467 66.096 49.187 ;
     RECT  10.812 48.515 11.016 49.477 ;
     RECT  30.792 48.805 31.92 48.995 ;
     RECT  16.344 48.947 17.712 50.053 ;
     RECT  18.912 48.949 20.208 51.637 ;
     RECT  20.232 48.949 21.3 55.667 ;
     RECT  49.848 49.091 51 52.451 ;
     RECT  64.812 49.187 67.2 50.053 ;
     RECT  56.304 49.379 56.4 50.629 ;
     RECT  36.768 49.475 37.5 50.773 ;
     RECT  10.812 49.477 12 49.525 ;
     RECT  12.024 49.477 13.2 52.211 ;
     RECT  64.812 50.053 66.96 50.677 ;
     RECT  81.012 50.101 81.984 51.347 ;
     RECT  82.008 50.101 83.4 51.347 ;
     RECT  59.412 50.437 60.48 54.947 ;
     RECT  60.504 50.437 61.8 51.685 ;
     RECT  46.824 50.581 48.3 53.075 ;
     RECT  64.812 50.677 65.808 51.253 ;
     RECT  65.832 50.677 66.96 51.253 ;
     RECT  35.208 50.773 36.48 50.965 ;
     RECT  36.504 50.773 37.5 51.923 ;
     RECT  53.136 50.867 53.7 51.829 ;
     RECT  65.832 51.253 66.816 51.685 ;
     RECT  16.212 51.347 17.712 52.789 ;
     RECT  35.112 51.443 36.096 54.275 ;
     RECT  5.412 51.637 6.528 51.733 ;
     RECT  6.552 51.637 7.68 51.781 ;
     RECT  60.504 51.685 61.584 53.795 ;
     RECT  65.064 51.731 66.096 52.211 ;
     RECT  6.552 51.781 7.584 52.499 ;
     RECT  24.312 51.829 25.68 53.077 ;
     RECT  51.312 51.829 52.416 53.075 ;
     RECT  52.44 51.829 53.7 52.405 ;
     RECT  70.728 51.829 71.808 51.875 ;
     RECT  36.12 51.923 37.5 53.413 ;
     RECT  43.32 52.021 44.592 52.307 ;
     RECT  11.112 52.211 11.448 53.557 ;
     RECT  43.212 52.307 44.592 57.109 ;
     RECT  27.144 52.405 28.656 54.899 ;
     RECT  48.612 52.405 49.632 52.981 ;
     RECT  52.44 52.405 53.568 53.075 ;
     RECT  54.456 52.405 55.68 53.029 ;
     RECT  49.656 52.451 51 54.085 ;
     RECT  40.512 52.453 41.952 53.555 ;
     RECT  6.216 52.499 7.584 53.027 ;
     RECT  2.712 52.549 3.936 53.603 ;
     RECT  3.96 52.549 4.944 53.603 ;
     RECT  16.536 52.789 17.712 55.139 ;
     RECT  21.612 52.835 23.088 53.797 ;
     RECT  8.112 52.981 9.504 55.331 ;
     RECT  9.528 52.981 10.5 54.661 ;
     RECT  48.612 52.981 49.584 54.131 ;
     RECT  47.856 53.075 48.3 53.125 ;
     RECT  24.312 53.077 25.632 54.037 ;
     RECT  13.512 53.317 14.832 53.603 ;
     RECT  14.856 53.317 15.9 53.603 ;
     RECT  36.36 53.413 37.5 54.229 ;
     RECT  13.512 53.603 15.9 53.653 ;
     RECT  37.812 53.603 37.944 54.085 ;
     RECT  72.48 53.651 72.6 54.853 ;
     RECT  14.424 53.653 15.9 55.477 ;
     RECT  60.504 53.795 61.8 54.947 ;
     RECT  21.612 53.797 22.896 57.011 ;
     RECT  18.912 53.843 20.016 55.813 ;
     RECT  24.552 54.037 25.632 55.237 ;
     RECT  11.976 54.085 13.2 54.325 ;
     RECT  37.812 54.085 39.216 56.869 ;
     RECT  48.612 54.131 49.632 55.907 ;
     RECT  36.408 54.229 37.5 54.661 ;
     RECT  35.112 54.275 36.336 54.659 ;
     RECT  12.072 54.325 13.2 55.813 ;
     RECT  33.528 54.565 34.8 56.293 ;
     RECT  32.412 54.611 33.504 56.629 ;
     RECT  35.112 54.659 36.384 58.597 ;
     RECT  36.456 54.661 37.5 55.957 ;
     RECT  22.92 54.707 24 57.011 ;
     RECT  5.736 54.709 7.152 55.139 ;
     RECT  27.144 54.899 28.752 55.427 ;
     RECT  72.912 54.949 74.16 58.021 ;
     RECT  54.744 54.995 56.064 56.291 ;
     RECT  5.688 55.139 7.152 55.955 ;
     RECT  16.344 55.139 17.712 58.787 ;
     RECT  74.184 55.283 75.3 60.421 ;
     RECT  8.112 55.331 9.6 55.715 ;
     RECT  24.312 55.331 25.44 56.483 ;
     RECT  27.012 55.427 28.752 55.861 ;
     RECT  14.616 55.477 15.9 55.619 ;
     RECT  14.52 55.619 15.9 56.627 ;
     RECT  20.04 55.667 21.3 57.013 ;
     RECT  49.656 55.667 51 55.907 ;
     RECT  8.112 55.715 8.568 56.101 ;
     RECT  29.712 55.859 30.456 56.389 ;
     RECT  27.012 55.861 28.224 56.531 ;
     RECT  5.688 55.955 7.8 56.531 ;
     RECT  57.288 55.957 58.464 56.003 ;
     RECT  57.288 56.003 58.848 56.389 ;
     RECT  72.48 56.099 72.6 57.109 ;
     RECT  33.576 56.293 34.8 57.925 ;
     RECT  29.712 56.389 30.96 57.251 ;
     RECT  30.984 56.389 32.1 57.251 ;
     RECT  57.768 56.389 58.848 57.587 ;
     RECT  10.812 56.483 11.952 58.117 ;
     RECT  12.168 56.483 13.2 58.691 ;
     RECT  24.312 56.483 24.408 57.397 ;
     RECT  7.104 56.531 7.8 57.013 ;
     RECT  27.012 56.531 28.512 58.739 ;
     RECT  14.424 56.627 15.9 58.021 ;
     RECT  32.412 56.629 33.456 58.163 ;
     RECT  37.812 56.869 38.88 57.445 ;
     RECT  38.904 56.915 40.2 58.163 ;
     RECT  81.012 56.965 81.984 58.259 ;
     RECT  82.008 56.965 83.4 58.259 ;
     RECT  21.612 57.011 24 57.013 ;
     RECT  20.136 57.013 21.3 57.155 ;
     RECT  21.612 57.013 22.656 62.053 ;
     RECT  22.68 57.013 24 57.973 ;
     RECT  67.512 57.061 68.976 57.347 ;
     RECT  70.776 57.109 72.144 57.971 ;
     RECT  21.024 57.155 21.3 57.637 ;
     RECT  67.512 57.347 69.072 57.491 ;
     RECT  67.512 57.491 67.704 58.117 ;
     RECT  36.456 57.539 37.5 61.667 ;
     RECT  24.312 57.731 24.408 58.741 ;
     RECT  22.824 57.973 24 58.645 ;
     RECT  73.128 58.021 74.16 58.645 ;
     RECT  45.912 58.117 47.136 60.275 ;
     RECT  47.16 58.211 48.3 60.275 ;
     RECT  58.848 58.451 58.992 59.749 ;
     RECT  35.208 58.597 36.384 58.645 ;
     RECT  5.412 58.645 6.816 59.459 ;
     RECT  22.92 58.645 24 59.221 ;
     RECT  48.612 58.645 49.584 59.267 ;
     RECT  49.608 58.645 51 59.267 ;
     RECT  11.976 58.691 13.2 58.933 ;
     RECT  21.072 58.739 21.3 59.797 ;
     RECT  27.012 58.739 28.896 58.883 ;
     RECT  67.608 58.739 67.704 59.221 ;
     RECT  24.312 58.741 25.728 58.883 ;
     RECT  65.592 58.741 66.672 61.427 ;
     RECT  16.212 58.787 17.712 61.333 ;
     RECT  43.212 58.835 44.592 60.421 ;
     RECT  24.312 58.883 26.7 59.749 ;
     RECT  27.012 58.883 29.04 59.701 ;
     RECT  10.812 58.931 11.952 64.643 ;
     RECT  11.976 58.933 13.104 59.219 ;
     RECT  79.32 59.173 80.7 60.035 ;
     RECT  11.976 59.219 13.2 60.949 ;
     RECT  34.176 59.219 34.8 59.797 ;
     RECT  67.608 59.221 68.928 60.611 ;
     RECT  48.612 59.267 51 60.373 ;
     RECT  5.412 59.459 7.104 60.325 ;
     RECT  51.312 59.605 52.512 59.891 ;
     RECT  52.536 59.605 53.7 59.891 ;
     RECT  27.96 59.701 29.04 59.747 ;
     RECT  27.96 59.747 29.4 61.573 ;
     RECT  25.128 59.749 26.7 60.373 ;
     RECT  57.24 59.749 58.512 62.581 ;
     RECT  32.412 59.797 33.744 61.043 ;
     RECT  33.768 59.797 34.8 61.043 ;
     RECT  35.112 59.939 36.144 60.563 ;
     RECT  8.112 59.987 8.664 60.373 ;
     RECT  80.592 60.035 80.7 60.373 ;
     RECT  14.424 60.275 15.792 61.333 ;
     RECT  5.544 60.325 7.104 60.373 ;
     RECT  5.64 60.373 7.104 60.419 ;
     RECT  8.112 60.373 9.648 61.189 ;
     RECT  25.128 60.373 26.592 60.419 ;
     RECT  38.376 60.373 39.888 60.851 ;
     RECT  48.612 60.373 49.968 62.101 ;
     RECT  49.992 60.373 51 61.189 ;
     RECT  5.64 60.419 5.688 61.525 ;
     RECT  35.112 60.563 36.432 61.621 ;
     RECT  19.416 60.565 20.88 61.091 ;
     RECT  22.92 60.611 24 61.957 ;
     RECT  67.512 60.611 68.928 66.755 ;
     RECT  12.072 60.949 13.2 63.205 ;
     RECT  32.412 61.043 32.856 61.189 ;
     RECT  43.212 61.043 44.592 64.117 ;
     RECT  19.416 61.091 19.752 61.525 ;
     RECT  8.232 61.189 9.648 62.435 ;
     RECT  14.808 61.333 15.792 62.195 ;
     RECT  16.584 61.333 17.712 62.435 ;
     RECT  72.336 61.379 72.6 62.389 ;
     RECT  28.056 61.573 29.4 64.067 ;
     RECT  35.352 61.621 36.432 61.667 ;
     RECT  13.656 61.907 14.784 62.195 ;
     RECT  40.632 61.957 42.144 62.195 ;
     RECT  59.928 61.957 60.912 62.675 ;
     RECT  48.612 62.101 49.824 64.213 ;
     RECT  5.544 62.195 5.688 63.251 ;
     RECT  15.408 62.195 15.792 63.205 ;
     RECT  40.632 62.195 41.208 62.677 ;
     RECT  49.848 62.195 51 65.509 ;
     RECT  73.272 62.195 74.592 65.029 ;
     RECT  78.312 62.195 78.408 62.773 ;
     RECT  64.812 62.243 64.968 63.685 ;
     RECT  70.212 62.389 71.424 63.779 ;
     RECT  71.448 62.389 72.6 63.779 ;
     RECT  16.212 62.435 17.712 63.493 ;
     RECT  57.24 62.581 58.32 62.677 ;
     RECT  59.412 62.675 60.912 63.875 ;
     RECT  57.336 62.677 58.32 65.173 ;
     RECT  78.312 62.773 79.296 64.163 ;
     RECT  79.32 62.773 80.592 64.163 ;
     RECT  45.912 63.061 47.328 64.595 ;
     RECT  12.072 63.205 13.104 63.251 ;
     RECT  35.352 63.205 36.432 64.403 ;
     RECT  36.456 63.205 37.5 64.403 ;
     RECT  5.412 63.251 5.688 63.589 ;
     RECT  11.976 63.251 13.104 64.643 ;
     RECT  51.312 63.349 52.464 64.019 ;
     RECT  52.488 63.349 53.7 64.019 ;
     RECT  27.012 63.395 28.032 64.067 ;
     RECT  16.536 63.493 17.712 63.781 ;
     RECT  5.412 63.589 6.912 64.885 ;
     RECT  24.312 63.829 25.776 64.355 ;
     RECT  27.012 64.067 27.672 65.365 ;
     RECT  80.448 64.163 80.592 64.837 ;
     RECT  48.744 64.213 49.824 64.837 ;
     RECT  43.212 64.355 44.592 65.413 ;
     RECT  19.944 64.357 21.3 65.171 ;
     RECT  35.352 64.403 35.784 64.405 ;
     RECT  45.912 64.595 46.008 65.653 ;
     RECT  10.812 64.643 11.208 65.509 ;
     RECT  22.248 64.835 23.376 64.883 ;
     RECT  16.212 64.883 17.712 67.427 ;
     RECT  22.248 64.883 23.712 66.469 ;
     RECT  15.408 64.931 15.792 65.603 ;
     RECT  9.648 65.027 10.08 65.125 ;
     RECT  73.272 65.029 74.352 65.699 ;
     RECT  9.096 65.125 10.08 65.171 ;
     RECT  9.096 65.171 10.272 66.755 ;
     RECT  48.612 65.171 49.824 67.283 ;
     RECT  43.212 65.413 44.448 66.755 ;
     RECT  49.848 65.509 50.88 66.997 ;
     RECT  15.408 65.603 15.9 66.085 ;
     RECT  57.576 65.699 59.1 67.381 ;
     RECT  72.912 65.699 74.352 72.277 ;
     RECT  30.504 65.941 31.968 67.285 ;
     RECT  13.512 66.085 14.688 66.613 ;
     RECT  14.712 66.085 15.9 67.285 ;
     RECT  46.008 66.373 47.184 66.515 ;
     RECT  47.208 66.373 48.3 67.045 ;
     RECT  22.344 66.469 23.712 68.917 ;
     RECT  45.912 66.515 47.184 67.669 ;
     RECT  8.112 66.755 8.664 68.197 ;
     RECT  43.212 66.755 44.544 67.045 ;
     RECT  67.512 66.755 68.976 67.283 ;
     RECT  60.648 66.901 61.8 69.395 ;
     RECT  59.412 66.947 60.624 69.395 ;
     RECT  43.368 67.045 44.544 67.283 ;
     RECT  47.208 67.045 48.192 67.715 ;
     RECT  49.992 67.187 51 67.955 ;
     RECT  12.024 67.237 13.2 67.859 ;
     RECT  43.368 67.283 44.592 67.619 ;
     RECT  48.612 67.283 49.968 67.955 ;
     RECT  14.808 67.285 15.9 67.621 ;
     RECT  30.504 67.285 31.584 67.715 ;
     RECT  5.736 67.331 6.72 68.003 ;
     RECT  13.512 67.331 14.688 67.859 ;
     RECT  36.408 67.381 37.5 68.341 ;
     RECT  57.72 67.381 59.1 67.667 ;
     RECT  44.616 67.475 45.6 80.293 ;
     RECT  43.212 67.619 44.592 74.581 ;
     RECT  14.856 67.621 15.9 67.811 ;
     RECT  57.576 67.667 59.1 68.917 ;
     RECT  46.584 67.715 48.192 68.627 ;
     RECT  24.312 67.763 24.408 68.917 ;
     RECT  14.808 67.811 15.9 67.907 ;
     RECT  13.512 67.859 14.784 67.907 ;
     RECT  5.412 68.003 6.72 68.627 ;
     RECT  10.812 68.099 11.592 69.493 ;
     RECT  36.456 68.341 37.5 69.587 ;
     RECT  45.912 68.627 46.056 70.069 ;
     RECT  47.76 68.627 48.192 68.821 ;
     RECT  24.312 68.917 25.68 76.021 ;
     RECT  38.808 68.917 40.2 71.267 ;
     RECT  57.624 68.917 59.1 71.795 ;
     RECT  37.812 69.251 38.784 70.357 ;
     RECT  61.68 69.395 61.8 69.493 ;
     RECT  10.812 69.493 12 70.453 ;
     RECT  12.024 69.493 13.2 70.691 ;
     RECT  67.752 69.493 69.072 71.075 ;
     RECT  75.816 69.539 75.96 69.875 ;
     RECT  40.512 69.541 41.616 72.899 ;
     RECT  41.64 69.541 42.9 72.899 ;
     RECT  35.88 69.587 37.5 70.981 ;
     RECT  75.612 69.875 75.96 70.069 ;
     RECT  48.612 70.021 49.68 71.221 ;
     RECT  49.704 70.021 51 72.853 ;
     RECT  75.612 70.069 76.896 70.451 ;
     RECT  13.512 70.309 14.64 70.501 ;
     RECT  14.664 70.309 15.9 70.547 ;
     RECT  77.52 70.451 77.616 71.797 ;
     RECT  10.812 70.453 11.856 70.643 ;
     RECT  13.608 70.501 14.64 70.547 ;
     RECT  10.812 70.643 12 70.691 ;
     RECT  10.812 70.691 13.2 71.221 ;
     RECT  35.88 70.981 36.912 71.411 ;
     RECT  10.812 71.221 12.144 71.797 ;
     RECT  12.168 71.221 13.2 72.565 ;
     RECT  40.08 71.267 40.2 72.421 ;
     RECT  72.336 71.363 72.6 72.325 ;
     RECT  35.592 71.411 36.912 75.443 ;
     RECT  7.344 71.603 7.8 72.661 ;
     RECT  51.312 71.651 51.528 72.949 ;
     RECT  57.576 71.795 59.1 74.965 ;
     RECT  10.812 71.797 12.048 72.755 ;
     RECT  27.012 71.989 28.416 73.333 ;
     RECT  19.368 72.229 20.496 72.563 ;
     RECT  21.612 72.469 22.8 72.611 ;
     RECT  19.32 72.563 20.496 74.099 ;
     RECT  10.812 72.755 12.144 72.803 ;
     RECT  13.104 72.803 13.2 74.149 ;
     RECT  59.412 72.805 60.912 72.947 ;
     RECT  40.512 72.899 42.9 73.525 ;
     RECT  59.412 72.947 61.584 73.909 ;
     RECT  72.912 72.947 74.352 74.101 ;
     RECT  48.612 72.995 49.68 77.555 ;
     RECT  27.012 73.333 28.32 75.155 ;
     RECT  28.344 73.379 29.4 75.155 ;
     RECT  2.712 73.477 3.936 74.627 ;
     RECT  40.512 73.525 41.664 74.579 ;
     RECT  41.688 73.525 42.9 74.533 ;
     RECT  59.412 73.909 60.912 74.771 ;
     RECT  19.32 74.099 21.3 75.205 ;
     RECT  46.776 74.293 48.3 74.389 ;
     RECT  46.776 74.389 47.76 74.435 ;
     RECT  41.88 74.533 42.9 75.251 ;
     RECT  40.512 74.579 41.856 75.251 ;
     RECT  43.212 74.581 44.4 76.309 ;
     RECT  21.612 74.725 23.04 75.685 ;
     RECT  25.704 74.771 26.7 79.717 ;
     RECT  49.704 74.819 51 77.555 ;
     RECT  57.576 74.965 58.656 76.979 ;
     RECT  72.912 75.107 74.352 77.461 ;
     RECT  62.76 75.157 64.128 75.971 ;
     RECT  19.848 75.205 21.3 76.739 ;
     RECT  68.28 75.205 69.744 76.211 ;
     RECT  35.592 75.443 37.5 76.741 ;
     RECT  21.612 75.685 22.8 76.357 ;
     RECT  30.168 75.685 31.296 76.883 ;
     RECT  54.012 75.875 54.84 76.309 ;
     RECT  24.552 76.021 25.68 77.507 ;
     RECT  78.408 76.021 79.536 76.355 ;
     RECT  79.56 76.021 80.7 79.427 ;
     RECT  13.512 76.165 14.928 77.843 ;
     RECT  43.212 76.309 44.304 77.603 ;
     RECT  54.012 76.309 55.344 76.979 ;
     RECT  55.368 76.309 56.4 76.979 ;
     RECT  78.312 76.355 79.536 79.427 ;
     RECT  19.032 76.739 21.3 76.981 ;
     RECT  35.976 76.741 37.5 78.131 ;
     RECT  5.412 76.837 6.768 76.979 ;
     RECT  6.792 76.837 7.8 76.979 ;
     RECT  29.976 76.883 31.296 78.131 ;
     RECT  45.912 76.885 47.328 77.989 ;
     RECT  67.512 76.931 67.944 78.181 ;
     RECT  2.712 76.979 2.856 78.373 ;
     RECT  57.576 76.979 59.1 79.765 ;
     RECT  19.032 76.981 21.168 77.893 ;
     RECT  21.96 77.027 23.04 77.989 ;
     RECT  72.912 77.461 74.064 78.181 ;
     RECT  24.408 77.507 25.68 78.469 ;
     RECT  43.212 77.603 44.592 79.189 ;
     RECT  19.032 77.893 20.496 78.707 ;
     RECT  16.212 77.939 16.344 78.037 ;
     RECT  46.152 77.989 47.328 78.035 ;
     RECT  16.212 78.037 17.184 78.949 ;
     RECT  63 78.037 64.5 79.475 ;
     RECT  22.104 78.131 23.424 79.283 ;
     RECT  67.512 78.181 68.976 78.419 ;
     RECT  12.072 78.229 13.2 80.003 ;
     RECT  2.712 78.373 3.936 78.949 ;
     RECT  67.512 78.419 69.072 78.997 ;
     RECT  72.912 78.515 74.352 80.963 ;
     RECT  24.408 78.659 25.68 79.765 ;
     RECT  19.032 78.707 20.736 79.189 ;
     RECT  17.208 78.755 18.24 79.235 ;
     RECT  2.712 78.949 3.888 79.189 ;
     RECT  67.8 78.997 69.072 79.283 ;
     RECT  2.856 79.189 3.888 79.331 ;
     RECT  19.512 79.189 20.736 80.005 ;
     RECT  17.16 79.235 18.24 79.475 ;
     RECT  21.612 79.283 23.424 79.715 ;
     RECT  39.84 79.283 40.2 80.293 ;
     RECT  80.496 79.427 80.7 79.717 ;
     RECT  17.16 79.475 18.6 79.715 ;
     RECT  62.112 79.475 64.5 80.197 ;
     RECT  21.612 79.715 24 80.773 ;
     RECT  35.592 79.717 37.104 82.259 ;
     RECT  71.016 79.717 72.336 79.859 ;
     RECT  57.912 79.765 59.1 82.933 ;
     RECT  2.712 79.859 2.856 80.917 ;
     RECT  9.096 80.053 10.5 86.099 ;
     RECT  62.112 80.197 63.552 82.115 ;
     RECT  24.408 80.339 25.68 83.267 ;
     RECT  80.496 80.435 80.7 81.829 ;
     RECT  21.612 80.773 22.608 80.963 ;
     RECT  22.632 80.773 24 80.963 ;
     RECT  45.912 80.869 47.28 82.691 ;
     RECT  47.304 80.869 48.3 82.691 ;
     RECT  3.144 80.917 4.512 81.731 ;
     RECT  21.612 80.963 22.392 82.405 ;
     RECT  60.96 81.059 61.8 81.445 ;
     RECT  41.352 81.061 42.576 81.443 ;
     RECT  43.212 81.107 44.592 82.357 ;
     RECT  37.812 81.445 38.88 82.931 ;
     RECT  59.688 81.445 61.8 82.405 ;
     RECT  25.704 81.491 26.7 87.251 ;
     RECT  78.312 81.829 79.776 86.581 ;
     RECT  35.592 82.259 35.736 82.693 ;
     RECT  67.104 82.307 67.2 82.741 ;
     RECT  43.212 82.357 44.448 82.597 ;
     RECT  44.616 82.403 45.6 88.451 ;
     RECT  59.688 82.405 61.008 82.691 ;
     RECT  11.976 82.453 13.2 83.749 ;
     RECT  10.812 82.499 11.952 87.827 ;
     RECT  30.936 82.501 32.1 83.267 ;
     RECT  29.712 82.547 30.912 83.267 ;
     RECT  43.32 82.597 44.448 83.939 ;
     RECT  13.512 82.693 14.832 82.835 ;
     RECT  14.856 82.693 15.9 82.835 ;
     RECT  65.736 82.741 67.2 83.459 ;
     RECT  13.512 82.835 13.608 82.933 ;
     RECT  19.368 82.835 20.544 83.027 ;
     RECT  57.912 82.933 58.944 83.219 ;
     RECT  67.512 82.933 68.976 83.077 ;
     RECT  56.712 82.979 57.888 83.219 ;
     RECT  68.376 83.123 69.696 83.939 ;
     RECT  24.312 83.267 25.68 84.661 ;
     RECT  12.12 83.749 13.2 84.563 ;
     RECT  43.212 83.939 44.448 85.139 ;
     RECT  27.012 84.275 27.336 84.805 ;
     RECT  6.264 84.325 7.392 84.899 ;
     RECT  40.512 84.325 41.616 86.483 ;
     RECT  41.64 84.325 42.9 85.381 ;
     RECT  23.616 84.419 23.904 85.429 ;
     RECT  11.976 84.563 13.2 84.949 ;
     RECT  27.012 84.805 28.32 87.347 ;
     RECT  5.688 84.899 5.736 86.005 ;
     RECT  11.976 84.949 13.104 86.435 ;
     RECT  43.212 85.139 44.592 86.053 ;
     RECT  37.812 85.381 39.12 86.773 ;
     RECT  41.64 85.381 42.72 86.483 ;
     RECT  45.912 86.005 47.376 86.629 ;
     RECT  67.512 86.005 68.976 88.307 ;
     RECT  43.32 86.053 44.592 88.451 ;
     RECT  24.312 86.243 25.68 87.251 ;
     RECT  52.296 86.293 53.7 88.643 ;
     RECT  56.712 86.341 57.84 87.251 ;
     RECT  57.864 86.341 58.944 87.251 ;
     RECT  59.688 86.341 60.96 87.203 ;
     RECT  11.976 86.435 13.2 87.157 ;
     RECT  78.312 86.581 79.44 88.979 ;
     RECT  79.464 86.627 80.592 87.827 ;
     RECT  46.008 86.629 47.376 87.829 ;
     RECT  16.212 86.675 16.344 87.877 ;
     RECT  37.812 86.773 38.976 88.693 ;
     RECT  35.352 87.059 36.576 87.155 ;
     RECT  35.208 87.155 36.576 87.299 ;
     RECT  12.024 87.157 13.2 88.453 ;
     RECT  59.544 87.203 61.8 88.405 ;
     RECT  28.344 87.251 29.4 87.347 ;
     RECT  58.704 87.251 58.944 88.405 ;
     RECT  19.56 87.397 20.736 89.075 ;
     RECT  2.712 87.541 3.936 87.683 ;
     RECT  3.96 87.541 5.1 87.683 ;
     RECT  8.904 87.685 10.176 88.355 ;
     RECT  22.104 87.685 23.376 87.925 ;
     RECT  10.812 87.827 12 89.171 ;
     RECT  79.464 87.827 80.7 88.979 ;
     RECT  32.412 87.829 33.744 90.275 ;
     RECT  33.768 87.829 34.8 90.275 ;
     RECT  46.2 87.829 47.376 87.971 ;
     RECT  46.008 87.971 47.376 90.035 ;
     RECT  21.612 88.067 22.8 88.163 ;
     RECT  75.612 88.309 76.944 90.083 ;
     RECT  76.968 88.309 78 90.083 ;
     RECT  59.544 88.405 60.864 88.739 ;
     RECT  12.024 88.453 13.104 88.883 ;
     RECT  50.208 88.691 50.544 88.885 ;
     RECT  59.544 88.739 59.736 89.461 ;
     RECT  12.024 88.883 13.2 89.171 ;
     RECT  27.96 88.885 29.4 90.515 ;
     RECT  49.032 88.885 50.544 88.979 ;
     RECT  38.76 89.315 40.2 90.083 ;
  END
END dsfd_r2l_vr_512x1__hsel
END LIBRARY
